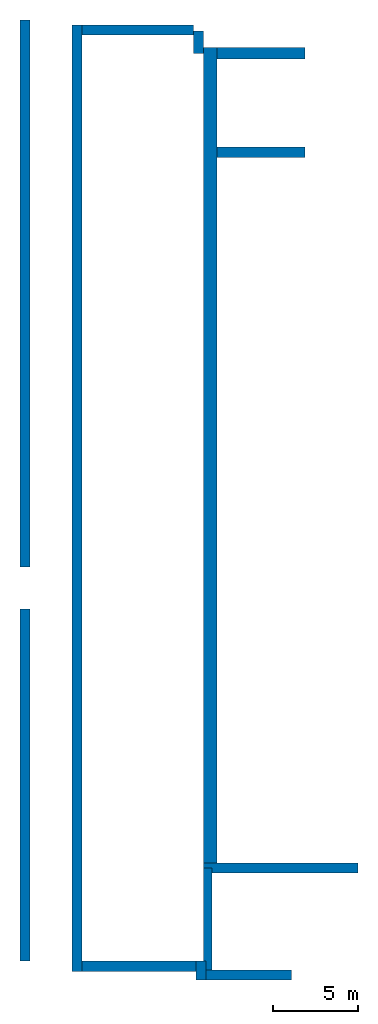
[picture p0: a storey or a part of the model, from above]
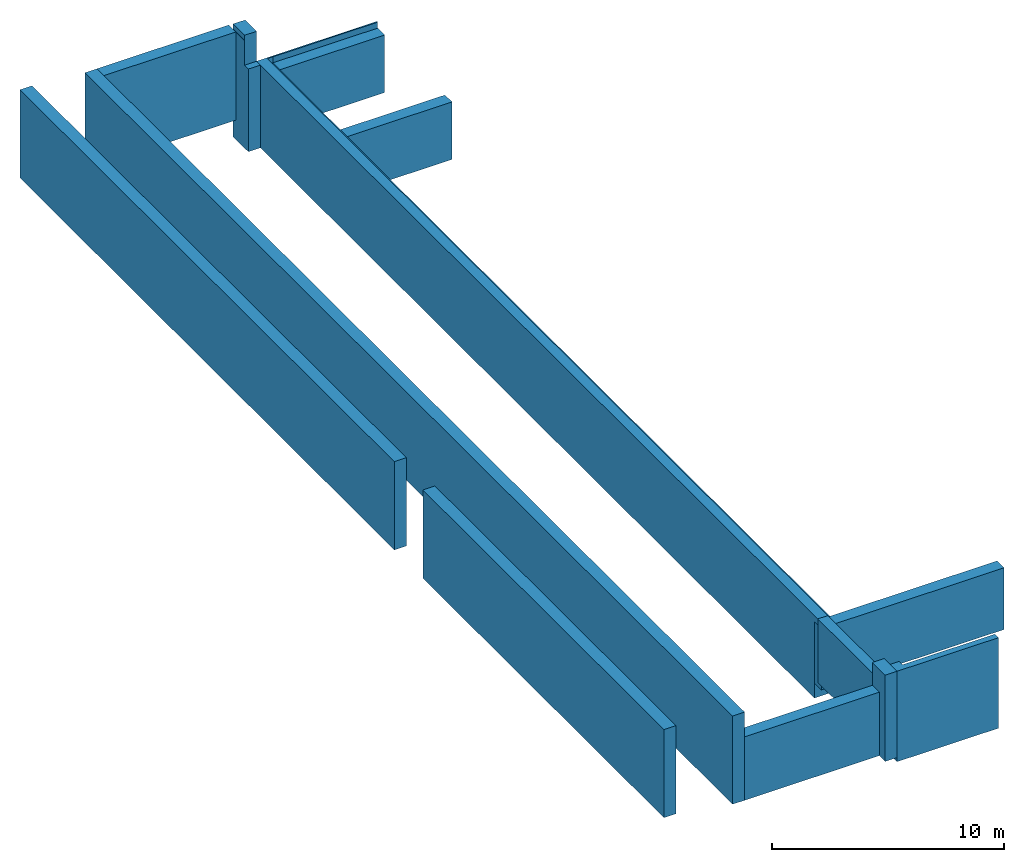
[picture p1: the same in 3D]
Properties of the parts of a building model (IFC2X3), part 1 of 7

# File
Description: ViewDefinition [CoordinationView_V2.0, QuantityTakeOffAddOnView], RevitIdentifiers [VersionGUID: 77220d87-94bb-491e-9206-e94cbbbe58ce, NumberOfSaves: 40], CoordinateReference [CoordinateBase: Project Base Point, ProjectSite: Internal]
File name: 22001 - AR_RaRa_AB_TJ_Pilv.ifc
Time: 2025-01-14T10:44:37
Written by: ODA IFC SDK 22.8
Made in: 22.1.70.9 - IFC 22.7.0.0 - Default UI

# IfcProject, 22001
LongName: Eesti Rahvusraamatukogu hoone renoveerimise projekteerimistööd; Phase: TJ

# IfcSite, Default
LongName: 78401:107:0570; RefLatitude: 59, 26, 11, 113586; RefLongitude: 24, 45, 9, 290313; RefElevation: 0 mm
Pset_SiteCommon - BuildableArea: 11110 m2; TotalArea: 19297 m2; BuildingHeightLimit: 3420 mm
AR_Kinnistu - 010_Katastritunnus: 78401:107:0570; 015_Ehitatav_pindala: 11110 m2; 020_Pindala: 19297 m2; 025_Max_kõrgus: 3420

# IfcBuilding, Eesti Rahvusraamatukogu hoone renoveerimise projekteerimistööd
LongName: Eesti Rahvusraamatukogu hoone renoveerimise projekteerimistööd
Pset_BuildingCommon - SprinklerProtection: yes; NumberOfStoreys: 10
AR_Hoone - 001_Nimetus: Eesti Rahvusraamatukogu hoone renoveerimise projekteerimistööd; 030_Hoone_aadress: Tõnismägi 2 ja Endla tn. 3, Tallinn, Harju maakond; 035_Sprinkler: yes; 040_Kõrgus: 34.18; ?: 11110; 050_Neto_pindala: 45329.3; 055_Neto_ruumala: 194973

# IfcBuildingStorey: Level:Level head 1 (12)
In: Eesti Rahvusraamatukogu hoone renoveerimise projekteerimistööd
Pset_AirSideSystemInformation - sets with these values: 2
Name | LongName | Elevation (mm) | Name = 060_Korruse_nimi | AboveGround = 070_Maapealne | 065_Korruse_number
-2. korrus | -2. korrus | -4990 | -3. Korrus_-7.50 | no | AB-3
-1. korrus | -1. korrus | -1650 | -1. korrus | no | AB-1
1. korrus | 1. korrus | 0 | 1. korrus | yes | AB1
E-korpus 2. korrus | E-korpus 2. korrus | 3100 | E-korpus 2. korrus | yes | E2
2. korrus | 2. korrus | 4950 | 2. korrus | yes | AB2
E-korpus 3. korrus | E-korpus 3. korrus | 6100 | E-korpus 3. korrus | yes | E3
3. korrus | 3. korrus | 8250 | 3. korrus | yes | AB3
4. korrus | 4. korrus | 11550 | 4. korrus | yes | AB4
5. korrus | 5. korrus | 14850 | 5. korrus | yes | AB5
6. korrus | 6. korrus | 18150 | 6. korrus | yes | AB6
7. korrus | 7. korrus | 21550 | 7. korrus | yes | AB7
8. korrus | 8. korrus | 24800 | 8. korrus | yes | AB8

# IfcBuildingStorey: Level:Level head 2, E-korpus -1. korrus
In: Eesti Rahvusraamatukogu hoone renoveerimise projekteerimistööd
LongName: E-korpus -1. korrus; Elevation: -4060 mm
Pset_AirSideSystemInformation - Name: E-korpus -1. korrus; sets with these values: 2
Pset_BuildingStoreyCommon - AboveGround: no
AR_Korrus - 070_Maapealne: no; 060_Korruse_nimi: E-korpus -1. korrus; 065_Korruse_number: E-1

# IfcSpace: Abiruum AB-3205:7871316, AB-3205
In: 3. korrus
LongName: Abiruum; InteriorOrExteriorSpace: INTERNAL; Group: SE AB 3.1M2 kõrvaltsoon
Pset_AirSideSystemInformation - Name: Abiruum
Pset_ProductRequirements - Name: Abiruum; Category: 12200 Büroo
Pset_SpaceCommon - Reference: Abiruum AB-3205; Category: 12200 Büroo
AR_Tsoon - 085_Tuletõkkesektsioon: EI120; 090_Pindala: 2.22796 m2; 080_Tähis SE: SE AB 3.1M2 kõrvaltsoon
AR_Ruum - 100_Nimi: Abiruum; 105_Number: AB-3205; 110_Tüüp: Mitteeluruumid; 115_Kategooria: RR Büroo; 120_Pindala: 2.22796 m2; 125_Turvatsoon: Kollane
BaseQuantities - NetFloorArea: 2.22796 m2; Height: 3000 mm; GrossFloorArea: 2.22796 m2; GrossVolume: 6.68388 m3

# IfcSpace: Büroo AB-1113:4274502, AB-1113
In: 1. korrus
LongName: Büroo; InteriorOrExteriorSpace: INTERNAL; Group: TT 57
Pset_AirSideSystemInformation - Name: Büroo
Pset_ProductRequirements - Name: Büroo; Category: 12200 Büroo
Pset_SpaceCommon - Reference: Büroo AB-1113; Category: 12200 Büroo
AR_Tsoon - 080_Tähis TO: TT 57; 085_Tuletõkkesektsioon: EI60; 090_Pindala: 31.6928 m2
AR_Ruum - 100_Nimi: Büroo; 105_Number: AB-1113; 110_Tüüp: Mitteeluruumid; 115_Kategooria: RR Büroo; 120_Pindala: 31.6928 m2; 125_Turvatsoon: Kollane
BaseQuantities - NetFloorArea: 31.6928 m2; Height: 3000 mm; GrossFloorArea: 31.6928 m2; GrossVolume: 95.0783 m3

# IfcSpace: Büroo AB-1114:6909133, AB-1114
In: 1. korrus
LongName: Büroo; InteriorOrExteriorSpace: INTERNAL; Group: TT 57
Pset_AirSideSystemInformation - Name: Büroo
Pset_ProductRequirements - Name: Büroo; Category: 12200 Büroo
Pset_SpaceCommon - Reference: Büroo AB-1114; Category: 12200 Büroo
AR_Tsoon - 080_Tähis TO: TT 57; 085_Tuletõkkesektsioon: EI60; 090_Pindala: 35.2581 m2
AR_Ruum - 100_Nimi: Büroo; 105_Number: AB-1114; 110_Tüüp: Mitteeluruumid; 115_Kategooria: RR Büroo; 120_Pindala: 35.2581 m2; 125_Turvatsoon: Kollane
BaseQuantities - NetFloorArea: 35.2581 m2; Height: 6300 mm; GrossFloorArea: 35.2581 m2; GrossVolume: 222.126 m3

# IfcSpace: Büroo AB-1122:6909135, AB-1122
In: 1. korrus
LongName: Büroo; InteriorOrExteriorSpace: INTERNAL; Group: TT 57
Pset_AirSideSystemInformation - Name: Büroo
Pset_ProductRequirements - Name: Büroo; Category: 12200 Büroo
Pset_SpaceCommon - Reference: Büroo AB-1122; Category: 12200 Büroo
AR_Tsoon - 080_Tähis TO: TT 57; 085_Tuletõkkesektsioon: EI60; 090_Pindala: 32.9428 m2
AR_Ruum - 100_Nimi: Büroo; 105_Number: AB-1122; 110_Tüüp: Mitteeluruumid; 115_Kategooria: RR Büroo; 120_Pindala: 32.9428 m2; 125_Turvatsoon: Kollane
BaseQuantities - NetFloorArea: 32.9428 m2; Height: 6300 mm; GrossFloorArea: 32.9428 m2; GrossVolume: 207.539 m3

# IfcSpace: Büroo AB-1124.1:13919361, AB-1124.1
In: 1. korrus
LongName: Büroo; InteriorOrExteriorSpace: INTERNAL; Group: TT 57
Pset_AirSideSystemInformation - Name: Büroo
Pset_ProductRequirements - Name: Büroo; Category: 12200 Büroo
Pset_SpaceCommon - Reference: Büroo AB-1124.1; Category: 12200 Büroo
AR_Tsoon - 080_Tähis TO: TT 57; 085_Tuletõkkesektsioon: EI60; 090_Pindala: 32.217 m2
AR_Ruum - 100_Nimi: Büroo; 105_Number: AB-1124.1; 110_Tüüp: Mitteeluruumid; 115_Kategooria: RR Büroo; 120_Pindala: 32.217 m2; 125_Turvatsoon: Kollane
BaseQuantities - NetFloorArea: 32.217 m2; Height: 9900 mm; GrossFloorArea: 32.217 m2; GrossVolume: 318.948 m3

# IfcSpace: Büroo AB-1124:1302545, AB-1124
In: 1. korrus
LongName: Büroo; InteriorOrExteriorSpace: INTERNAL; Group: TT 57
Pset_AirSideSystemInformation - Name: Büroo
Pset_ProductRequirements - Name: Büroo; Category: 12200 Büroo
Pset_SpaceCommon - Reference: Büroo AB-1124; Category: 12200 Büroo
AR_Tsoon - 080_Tähis TO: TT 57; 085_Tuletõkkesektsioon: EI60; 090_Pindala: 30.4486 m2
AR_Ruum - 100_Nimi: Büroo; 105_Number: AB-1124; 110_Tüüp: Mitteeluruumid; 115_Kategooria: RR Büroo; 120_Pindala: 30.4486 m2; 125_Turvatsoon: Kollane
BaseQuantities - NetFloorArea: 30.4486 m2; Height: 3000 mm; GrossFloorArea: 30.4486 m2; GrossVolume: 91.3458 m3

# IfcSpace: Dušš AB-01012:9327001, AB-01012
In: -1. korrus
LongName: Dušš; InteriorOrExteriorSpace: INTERNAL; Group: TT 48; SE AB -1.1M4
Pset_AirSideSystemInformation - Name: Dušš; sets with these values: 2
Pset_SpaceCommon - Reference: Dušš AB-01012
AR_Tsoon - 080_Tähis TO: TT 48; 085_Tuletõkkesektsioon: EI60; 090_Pindala: 3.37676 m2; 080_Tähis SE: SE AB -1.1M4
AR_Ruum - 100_Nimi: Dušš; 105_Number: AB-01012; 110_Tüüp: Üldkasutatavad alad; 115_Kategooria: Personaliruumid; 120_Pindala: 3.37676 m2; 125_Turvatsoon: Roheline
BaseQuantities - NetFloorArea: 3.37676 m2; Height: 9900 mm; GrossFloorArea: 3.37676 m2; GrossVolume: 33.43 m3

# IfcSpace: Eesruum / köök AB-2104:1990514, AB-2104
In: 2. korrus
LongName: Eesruum / köök; InteriorOrExteriorSpace: INTERNAL; Group: TT 23
Pset_AirSideSystemInformation - Name: Eesruum / köök
Pset_ProductRequirements - Name: Eesruum / köök; Category: 12200 Büroo
Pset_SpaceCommon - Reference: Eesruum / köök AB-2104; Category: 12200 Büroo
AR_Tsoon - 080_Tähis TO: TT 23; 085_Tuletõkkesektsioon: EI60; 090_Pindala: 13.9472 m2
AR_Ruum - 100_Nimi: Eesruum / köök; 105_Number: AB-2104; 110_Tüüp: Üldkasutatavad alad; 115_Kategooria: RR Büroo; 120_Pindala: 13.9472 m2; 125_Turvatsoon: Kollane
BaseQuantities - NetFloorArea: 13.9472 m2; Height: 3901.76 mm; GrossPerimeter: 16099.2 mm; GrossFloorArea: 13.9472 m2; GrossVolume: 54.4189 m3

# IfcSpace: Eesruum E-2002:2863406, E-2002
In: E-korpus 2. korrus
LongName: Eesruum; InteriorOrExteriorSpace: INTERNAL; Group: TT 26
Pset_AirSideSystemInformation - Name: Eesruum; sets with these values: 2
Pset_SpaceCommon - Reference: Eesruum E-2002
AR_Tsoon - 080_Tähis TO: TT 26; 085_Tuletõkkesektsioon: EI60; 090_Pindala: 4.54861 m2
AR_Ruum - 100_Nimi: Eesruum; 105_Number: E-2002; 110_Tüüp: Üldkasutatavad alad; 115_Kategooria: Üldala; 120_Pindala: 4.54861 m2; 125_Turvatsoon: Kollane
BaseQuantities - NetFloorArea: 4.54861 m2; Height: 3121.53 mm; GrossPerimeter: 9055.15 mm; GrossFloorArea: 4.54861 m2; GrossVolume: 14.1986 m3

# IfcSpace: Fuajee AB-1036:6178383, AB-1036
In: 1. korrus
LongName: Fuajee; InteriorOrExteriorSpace: INTERNAL; Group: TT 01; SE AB 1.1M4
Pset_AirSideSystemInformation - Name: Fuajee; sets with these values: 2
Pset_SpaceCommon - Reference: Fuajee AB-1036
AR_Tsoon - 080_Tähis TO: TT 01; 085_Tuletõkkesektsioon: EI60; 090_Pindala: 132.862 m2; 080_Tähis SE: SE AB 1.1M4
AR_Ruum - 100_Nimi: Fuajee; 105_Number: AB-1036; 110_Tüüp: Üldkasutatavad alad; 115_Kategooria: Üldala; 120_Pindala: 132.862 m2; 125_Turvatsoon: Roheline
BaseQuantities - NetFloorArea: 132.862 m2; Height: 2974.99 mm; GrossPerimeter: 61078.5 mm; GrossFloorArea: 132.862 m2; GrossVolume: 395.264 m3

# IfcSpace: Garderoob AB-3235:6668970, AB-3235
In: 3. korrus
LongName: Garderoob; InteriorOrExteriorSpace: INTERNAL; Group: TT 27; SE AB 3.1M2
Pset_AirSideSystemInformation - Name: Garderoob
Pset_ProductRequirements - Name: Garderoob; Category: 12200 Büroo
Pset_SpaceCommon - Reference: Garderoob AB-3235; Category: 12200 Büroo
AR_Tsoon - 080_Tähis TO: TT 27; 085_Tuletõkkesektsioon: EI90; 090_Pindala: 14.8637 m2; 080_Tähis SE: SE AB 3.1M2
AR_Ruum - 100_Nimi: Garderoob; 105_Number: AB-3235; 110_Tüüp: Mitteeluruumid; 115_Kategooria: Üld õppeala; 120_Pindala: 14.8637 m2; 125_Turvatsoon: Kollane
BaseQuantities - NetFloorArea: 14.8637 m2; Height: 3000 mm; GrossPerimeter: 17231 mm; GrossFloorArea: 14.8637 m2; GrossVolume: 44.5911 m3

# IfcSpace: Hoidlatöötajad AB-2123:1362904, AB-2123
In: 2. korrus
LongName: Hoidlatöötajad; InteriorOrExteriorSpace: INTERNAL; Group: TT 21
Pset_AirSideSystemInformation - Name: Hoidlatöötajad
Pset_ProductRequirements - Name: Hoidlatöötajad; Category: 12200 Büroo
Pset_SpaceCommon - Reference: Hoidlatöötajad AB-2123; Category: 12200 Büroo
AR_Tsoon - 080_Tähis TO: TT 21; 085_Tuletõkkesektsioon: EI60; 090_Pindala: 32.9681 m2
AR_Ruum - 100_Nimi: Hoidlatöötajad; 105_Number: AB-2123; 110_Tüüp: Mitteeluruumid; 115_Kategooria: RR Büroo; 120_Pindala: 32.9681 m2; 125_Turvatsoon: Kollane
BaseQuantities - NetFloorArea: 32.9681 m2; Height: 3000 mm; GrossPerimeter: 23109 mm; GrossFloorArea: 32.9681 m2; GrossVolume: 98.9042 m3

# IfcSpace: Hoiuruum, ümbrised AB-01109:4434795, AB-01109
In: -1. korrus
LongName: Hoiuruum, ümbrised; InteriorOrExteriorSpace: INTERNAL; Group: SE AB -1.1M4 kõrvaltsoon
Pset_AirSideSystemInformation - Name: Hoiuruum, ümbrised
Pset_ProductRequirements - Name: Hoiuruum, ümbrised; Category: 12624 Arhiiv
Pset_SpaceCommon - Reference: Hoiuruum, ümbrised AB-01109; Category: 12624 Arhiiv
AR_Tsoon - 085_Tuletõkkesektsioon: EI90; 090_Pindala: 18.2886 m2; 080_Tähis SE: SE AB -1.1M4 kõrvaltsoon
AR_Ruum - 100_Nimi: Hoiuruum, ümbrised; 105_Number: AB-01109; 110_Tüüp: Mitteeluruumid; 115_Kategooria: RR Büroo; 120_Pindala: 18.2886 m2; 125_Turvatsoon: Punane
BaseQuantities - NetFloorArea: 18.2886 m2; Height: 2985 mm; GrossFloorArea: 18.2886 m2; GrossVolume: 54.5913 m3

# IfcSpace: ITAK AB-2138:1362880, AB-2138
In: 2. korrus
LongName: ITAK; InteriorOrExteriorSpace: INTERNAL; Group: TT 21
Pset_AirSideSystemInformation - Name: ITAK
Pset_ProductRequirements - Name: ITAK; Category: 12200 Büroo
Pset_SpaceCommon - Reference: ITAK AB-2138; Category: 12200 Büroo
AR_Tsoon - 080_Tähis TO: TT 21; 085_Tuletõkkesektsioon: EI60; 090_Pindala: 51.3226 m2
AR_Ruum - 100_Nimi: ITAK; 105_Number: AB-2138; 110_Tüüp: Mitteeluruumid; 115_Kategooria: RR Büroo; 120_Pindala: 51.3226 m2; 125_Turvatsoon: Kollane
BaseQuantities - NetFloorArea: 51.3226 m2; Height: 3000 mm; GrossPerimeter: 31345.1 mm; GrossFloorArea: 51.3226 m2; GrossVolume: 153.968 m3

# IfcSpace: ITAK Juhataja AB-2137:7048196, AB-2137
In: 2. korrus
LongName: ITAK Juhataja; InteriorOrExteriorSpace: INTERNAL; Group: TT 21
Pset_AirSideSystemInformation - Name: ITAK Juhataja
Pset_ProductRequirements - Name: ITAK Juhataja; Category: 12200 Büroo
Pset_SpaceCommon - Reference: ITAK Juhataja AB-2137; Category: 12200 Büroo
AR_Tsoon - 080_Tähis TO: TT 21; 085_Tuletõkkesektsioon: EI60; 090_Pindala: 17.2797 m2
AR_Ruum - 100_Nimi: ITAK Juhataja; 105_Number: AB-2137; 110_Tüüp: Mitteeluruumid; 115_Kategooria: RR Büroo; 120_Pindala: 17.2797 m2; 125_Turvatsoon: Punane
BaseQuantities - NetFloorArea: 17.2797 m2; Height: 3000 mm; GrossPerimeter: 17564.5 mm; GrossFloorArea: 17.2797 m2; GrossVolume: 51.8392 m3

# IfcSpace: ITAK puhkeruum AB-2139:1362876, AB-2139
In: 2. korrus
LongName: ITAK puhkeruum; InteriorOrExteriorSpace: INTERNAL; Group: TT 21
Pset_AirSideSystemInformation - Name: ITAK puhkeruum
Pset_ProductRequirements - Name: ITAK puhkeruum; Category: 12200 Büroo
Pset_SpaceCommon - Reference: ITAK puhkeruum AB-2139; Category: 12200 Büroo
AR_Tsoon - 080_Tähis TO: TT 21; 085_Tuletõkkesektsioon: EI60; 090_Pindala: 32.2565 m2
AR_Ruum - 100_Nimi: ITAK puhkeruum; 105_Number: AB-2139; 110_Tüüp: Mitteeluruumid; 115_Kategooria: RR Büroo; 120_Pindala: 32.2565 m2; 125_Turvatsoon: Kollane
BaseQuantities - NetFloorArea: 32.2565 m2; Height: 3000 mm; GrossPerimeter: 23408 mm; GrossFloorArea: 32.2565 m2; GrossVolume: 96.7696 m3

# IfcSpace: Juhtiv spets. F-1116:2388867, F-1116
In: 1. korrus
LongName: Juhtiv spets.; InteriorOrExteriorSpace: INTERNAL; Group: TT 05
Pset_AirSideSystemInformation - Name: Juhtiv spets.
Pset_ProductRequirements - Name: Juhtiv spets.; Category: 12200 Büroo
Pset_SpaceCommon - Reference: Juhtiv spets. F-1116; Category: 12200 Büroo
AR_Tsoon - 080_Tähis TO: TT 05; 085_Tuletõkkesektsioon: EI60; 090_Pindala: 17.6284 m2
AR_Ruum - 100_Nimi: Juhtiv spets.; 105_Number: F-1116; 110_Tüüp: Mitteeluruumid; 115_Kategooria: RR Büroo; 120_Pindala: 17.6284 m2; 125_Turvatsoon: Punane
BaseQuantities - NetFloorArea: 17.6284 m2; Height: 4000 mm; GrossFloorArea: 17.6284 m2; GrossVolume: 70.5136 m3

# IfcSpace: KAO ladu AB-2136:1362888, AB-2136
In: 2. korrus
LongName: KAO ladu; InteriorOrExteriorSpace: INTERNAL
Pset_AirSideSystemInformation - Name: KAO ladu
Pset_ProductRequirements - Name: KAO ladu; Category: 12200 Büroo
Pset_SpaceCommon - Reference: KAO ladu AB-2136; Category: 12200 Büroo
AR_Tsoon - 085_Tuletõkkesektsioon: EI120; 090_Pindala: 11.8014 m2
AR_Ruum - 100_Nimi: KAO ladu; 105_Number: AB-2136; 110_Tüüp: Mitteeluruumid; 115_Kategooria: RR Büroo; 120_Pindala: 11.8014 m2; 125_Turvatsoon: Kollane
BaseQuantities - NetFloorArea: 11.8014 m2; Height: 3000 mm; GrossPerimeter: 15571 mm; GrossFloorArea: 11.8014 m2; GrossVolume: 35.4042 m3

# IfcSpace: Kabinet AB-2121:1362984, AB-2121
In: 2. korrus
LongName: Kabinet; InteriorOrExteriorSpace: INTERNAL; Group: TT 21
Pset_AirSideSystemInformation - Name: Kabinet
Pset_ProductRequirements - Name: Kabinet; Category: 12200 Büroo
Pset_SpaceCommon - Reference: Kabinet AB-2121; Category: 12200 Büroo
AR_Tsoon - 080_Tähis TO: TT 21; 085_Tuletõkkesektsioon: EI60; 090_Pindala: 31.8685 m2
AR_Ruum - 100_Nimi: Kabinet; 105_Number: AB-2121; 110_Tüüp: Mitteeluruumid; 115_Kategooria: RR Büroo; 120_Pindala: 31.8685 m2; 125_Turvatsoon: Kollane
BaseQuantities - NetFloorArea: 31.8685 m2; Height: 3000 mm; GrossPerimeter: 23062 mm; GrossFloorArea: 31.8685 m2; GrossVolume: 95.6054 m3

# IfcSpace: Kanal AB-02302:5475221, AB-02302
In: E-korpus -1. korrus
LongName: Kanal; InteriorOrExteriorSpace: INTERNAL
Pset_AirSideSystemInformation - Name: Kanal; sets with these values: 2
Pset_SpaceCommon - Reference: Kanal AB-02302
AR_Tsoon - 085_Tuletõkkesektsioon: EI60; 090_Pindala: 32.5664 m2
AR_Ruum - 100_Nimi: Kanal; 105_Number: AB-02302; 110_Tüüp: Tehnilised ruumid; 115_Kategooria: Tehnilised ruumid; 120_Pindala: 32.5664 m2; 125_Turvatsoon: Punane
BaseQuantities - NetFloorArea: 32.5664 m2; Height: 2062.47 mm; GrossFloorArea: 32.5664 m2; GrossVolume: 67.1671 m3

# IfcSpace: Kanal AB-02303:5281081, AB-02303
In: E-korpus -1. korrus
LongName: Kanal; InteriorOrExteriorSpace: INTERNAL; Group: SE AB -2.1M2 AT
Pset_AirSideSystemInformation - Name: Kanal; sets with these values: 2
Pset_SpaceCommon - Reference: Kanal AB-02303
AR_Tsoon - 085_Tuletõkkesektsioon: EI60; 090_Pindala: 198.182 m2; 080_Tähis SE: SE AB -2.1M2 AT
AR_Ruum - 100_Nimi: Kanal; 105_Number: AB-02303; 110_Tüüp: Tehnilised ruumid; 115_Kategooria: Tehnilised ruumid; 120_Pindala: 198.182 m2; 125_Turvatsoon: Punane
BaseQuantities - NetFloorArea: 198.182 m2; Height: 1910 mm; GrossFloorArea: 198.182 m2; GrossVolume: 378.528 m3

# IfcSpace: Karbistamise tööruum F-1108:2388882, F-1108
In: 1. korrus
LongName: Karbistamise tööruum; InteriorOrExteriorSpace: INTERNAL; Group: TT 05
Pset_AirSideSystemInformation - Name: Karbistamise tööruum
Pset_ProductRequirements - Name: Karbistamise tööruum; Category: 12200 Büroo
Pset_SpaceCommon - Reference: Karbistamise tööruum F-1108; Category: 12200 Büroo
AR_Tsoon - 080_Tähis TO: TT 05; 085_Tuletõkkesektsioon: EI60; 090_Pindala: 39.6037 m2
AR_Ruum - 100_Nimi: Karbistamise tööruum; 105_Number: F-1108; 110_Tüüp: Mitteeluruumid; 115_Kategooria: RR Büroo; 120_Pindala: 39.6037 m2; 125_Turvatsoon: Punane
BaseQuantities - NetFloorArea: 39.6037 m2; Height: 2980 mm; GrossPerimeter: 25598.2 mm; GrossFloorArea: 39.6037 m2; GrossVolume: 118.019 m3

# IfcSpace: Keemialabor F-1102:2388885, F-1102
In: 1. korrus
LongName: Keemialabor; InteriorOrExteriorSpace: INTERNAL; Group: TT 05; SE F 1.1M2
Pset_AirSideSystemInformation - Name: Keemialabor
Pset_ProductRequirements - Name: Keemialabor; Category: 12200 Büroo
Pset_SpaceCommon - Reference: Keemialabor F-1102; Category: 12200 Büroo
AR_Tsoon - 080_Tähis TO: TT 05; 085_Tuletõkkesektsioon: EI60; 090_Pindala: 25.182 m2; 080_Tähis SE: SE F 1.1M2
AR_Ruum - 100_Nimi: Keemialabor; 105_Number: F-1102; 110_Tüüp: Mitteeluruumid; 115_Kategooria: RR Büroo; 120_Pindala: 25.182 m2; 125_Turvatsoon: Punane
BaseQuantities - NetFloorArea: 25.182 m2; Height: 2980 mm; GrossPerimeter: 27881 mm; GrossFloorArea: 25.182 m2; GrossVolume: 75.0424 m3

# IfcSpace: Konservaatorite ja köitjate tööruum F-1113:2388815, F-1113
In: 1. korrus
LongName: Konservaatorite ja köitjate tööruum; InteriorOrExteriorSpace: INTERNAL; Group: TT 05
Pset_AirSideSystemInformation - Name: Konservaatorite ja köitjate tööruum
Pset_ProductRequirements - Name: Konservaatorite ja köitjate tööruum; Category: 12200 Büroo
Pset_SpaceCommon - Reference: Konservaatorite ja köitjate tööruum F-1113; Category: 12200 Büroo
AR_Tsoon - 080_Tähis TO: TT 05; 085_Tuletõkkesektsioon: EI60; 090_Pindala: 154.796 m2
AR_Ruum - 100_Nimi: Konservaatorite ja köitjate tööruum; 105_Number: F-1113; 110_Tüüp: Mitteeluruumid; 115_Kategooria: RR Büroo; 120_Pindala: 154.796 m2; 125_Turvatsoon: Punane
BaseQuantities - NetFloorArea: 154.796 m2; Height: 2980 mm; GrossPerimeter: 54601.2 mm; GrossFloorArea: 154.796 m2; GrossVolume: 461.293 m3

# IfcSpace: Konverentsikeskuse teenindusala E-1601:2608946, E-1601
In: 1. korrus
LongName: Konverentsikeskuse teenindusala; InteriorOrExteriorSpace: INTERNAL; Group: TT 01; SE AB 1.1M4
Pset_AirSideSystemInformation - Name: Konverentsikeskuse teenindusala
Pset_ProductRequirements - Name: Konverentsikeskuse teenindusala; Category: 12623 Raamatukogu
Pset_SpaceCommon - Reference: Konverentsikeskuse teenindusala E-1601; Category: 12623 Raamatukogu
AR_Tsoon - 080_Tähis TO: TT 01; 085_Tuletõkkesektsioon: EI60; 090_Pindala: 76.9714 m2; 080_Tähis SE: SE AB 1.1M4
AR_Ruum - 100_Nimi: Konverentsikeskuse teenindusala; 105_Number: E-1601; 110_Tüüp: Mitteeluruumid; 115_Kategooria: Konverentsikeskus; 120_Pindala: 76.9714 m2; 125_Turvatsoon: Kollane
BaseQuantities - NetFloorArea: 76.9714 m2; Height: 2979.98 mm; GrossPerimeter: 39418.4 mm; GrossFloorArea: 76.9714 m2; GrossVolume: 229.373 m3

# IfcSpace: Koridor AB-1001:2608963, AB-1001
In: 1. korrus
LongName: Koridor; InteriorOrExteriorSpace: INTERNAL; Group: SE TR3 L3
Pset_AirSideSystemInformation - Name: Koridor; sets with these values: 2
Pset_SpaceCommon - Reference: Koridor AB-1001
AR_Tsoon - 085_Tuletõkkesektsioon: EI60; 090_Pindala: 29.358 m2; 080_Tähis SE: SE TR3 L3
AR_Ruum - 100_Nimi: Koridor; 105_Number: AB-1001; 110_Tüüp: Üldkasutatavad alad; 115_Kategooria: Üldala; 120_Pindala: 29.358 m2; 125_Turvatsoon: Roheline
BaseQuantities - NetFloorArea: 29.358 m2; Height: 3000 mm; GrossPerimeter: 31100 mm; GrossFloorArea: 29.358 m2; GrossVolume: 88.074 m3

# IfcSpace: Koridor F-1009:2857749, F-1009
In: 1. korrus
LongName: Koridor; InteriorOrExteriorSpace: INTERNAL; Group: TT 05; SE F 1.1M2
Pset_AirSideSystemInformation - Name: Koridor; sets with these values: 2
Pset_SpaceCommon - Reference: Koridor F-1009
AR_Tsoon - 080_Tähis TO: TT 05; 085_Tuletõkkesektsioon: EI60; 090_Pindala: 79.2115 m2; 080_Tähis SE: SE F 1.1M2
AR_Ruum - 100_Nimi: Koridor; 105_Number: F-1009; 110_Tüüp: Üldkasutatavad alad; 115_Kategooria: Üldala; 120_Pindala: 79.2115 m2; 125_Turvatsoon: Kollane
BaseQuantities - NetFloorArea: 79.2115 m2; Height: 2980 mm; GrossFloorArea: 79.2115 m2; GrossVolume: 236.05 m3

# IfcSpace: Koridor F-1010:2857747, F-1010
In: 1. korrus
LongName: Koridor; InteriorOrExteriorSpace: INTERNAL; Group: TT 05
Pset_AirSideSystemInformation - Name: Koridor; sets with these values: 2
Pset_SpaceCommon - Reference: Koridor F-1010
AR_Tsoon - 080_Tähis TO: TT 05; 085_Tuletõkkesektsioon: EI60; 090_Pindala: 14.6776 m2
AR_Ruum - 100_Nimi: Koridor; 105_Number: F-1010; 110_Tüüp: Üldkasutatavad alad; 115_Kategooria: Üldala; 120_Pindala: 14.6776 m2; 125_Turvatsoon: Kollane
BaseQuantities - NetFloorArea: 14.6776 m2; Height: 2980 mm; GrossPerimeter: 17026.6 mm; GrossFloorArea: 14.6776 m2; GrossVolume: 43.7392 m3

# IfcSpace: Koristus personali puhkeruum AB-01008:1468837, AB-01008
In: -1. korrus
LongName: Koristus personali puhkeruum; InteriorOrExteriorSpace: INTERNAL; Group: TT 48; SE AB -1.1M4
Pset_AirSideSystemInformation - Name: Koristus personali puhkeruum; sets with these values: 2
Pset_SpaceCommon - Reference: Koristus personali puhkeruum AB-01008
AR_Tsoon - 080_Tähis TO: TT 48; 085_Tuletõkkesektsioon: EI60; 090_Pindala: 56.1981 m2; 080_Tähis SE: SE AB -1.1M4
AR_Ruum - 100_Nimi: Koristus personali puhkeruum; 105_Number: AB-01008; 110_Tüüp: Üldkasutatavad alad; 115_Kategooria: Personaliruumid; 120_Pindala: 56.1981 m2; 125_Turvatsoon: Kollane
BaseQuantities - NetFloorArea: 56.1981 m2; Height: 2985 mm; GrossFloorArea: 56.1981 m2; GrossVolume: 167.751 m3

# IfcSpace: Koristv. E-1001:7772610, E-1001
In: 1. korrus
LongName: Koristv.; InteriorOrExteriorSpace: INTERNAL; Group: TT 01; SE AB 1.1M4
Pset_AirSideSystemInformation - Name: Koristv.; sets with these values: 2
Pset_SpaceCommon - Reference: Koristv. E-1001
AR_Tsoon - 080_Tähis TO: TT 01; 085_Tuletõkkesektsioon: EI60; 090_Pindala: 5.12927 m2; 080_Tähis SE: SE AB 1.1M4
AR_Ruum - 100_Nimi: Koristv.; 105_Number: E-1001; 110_Tüüp: Üldkasutatavad alad; 115_Kategooria: Konverentsikeskus; 120_Pindala: 5.12927 m2; 125_Turvatsoon: Kollane
BaseQuantities - NetFloorArea: 5.12927 m2; Height: 9900 mm; GrossPerimeter: 9864.71 mm; GrossFloorArea: 5.12927 m2; GrossVolume: 50.7798 m3

# IfcSpace: Ladu (reserv) AB-01303:1465441, AB-01303
In: -1. korrus
LongName: Ladu (reserv); InteriorOrExteriorSpace: INTERNAL; Group: SE AB -1.1M4 kõrvaltsoon
Pset_AirSideSystemInformation - Name: Ladu (reserv); sets with these values: 2
Pset_SpaceCommon - Reference: Ladu (reserv) AB-01303
AR_Tsoon - 085_Tuletõkkesektsioon: EI90; 090_Pindala: 28.1808 m2; 080_Tähis SE: SE AB -1.1M4 kõrvaltsoon
AR_Ruum - 100_Nimi: Ladu (reserv); 105_Number: AB-01303; 110_Tüüp: Tehnilised ruumid; 115_Kategooria: Tehnilised ruumid; 120_Pindala: 28.1808 m2; 125_Turvatsoon: Punane
BaseQuantities - NetFloorArea: 28.1808 m2; Height: 2985 mm; GrossFloorArea: 28.1808 m2; GrossVolume: 84.1195 m3

# IfcSpace: Laste ala AB-3207:1386924, AB-3207
In: 3. korrus
LongName: Laste ala; InteriorOrExteriorSpace: INTERNAL; Group: TT 27; SE AB 3.1M2
Pset_AirSideSystemInformation - Name: Laste ala
Pset_ProductRequirements - Name: Laste ala; Category: 12623 Raamatukogu
Pset_SpaceCommon - Reference: Laste ala AB-3207; Category: 12623 Raamatukogu
AR_Tsoon - 080_Tähis TO: TT 27; 085_Tuletõkkesektsioon: EI90; 090_Pindala: 138.926 m2; 080_Tähis SE: SE AB 3.1M2
AR_Ruum - 100_Nimi: Laste ala; 105_Number: AB-3207; 110_Tüüp: Mitteeluruumid; 115_Kategooria: Üld õppeala; 120_Pindala: 138.926 m2; 125_Turvatsoon: Roheline
BaseQuantities - NetFloorArea: 138.926 m2; Height: 3000 mm; GrossPerimeter: 57708 mm; GrossFloorArea: 138.926 m2; GrossVolume: 416.777 m3

# IfcSpace: Logistikakeskus AB-2122:1362898, AB-2122
In: 2. korrus
LongName: Logistikakeskus; InteriorOrExteriorSpace: INTERNAL; Group: TT 21
Pset_AirSideSystemInformation - Name: Logistikakeskus
Pset_ProductRequirements - Name: Logistikakeskus; Category: 12200 Büroo
Pset_SpaceCommon - Reference: Logistikakeskus AB-2122; Category: 12200 Büroo
AR_Tsoon - 080_Tähis TO: TT 21; 085_Tuletõkkesektsioon: EI60; 090_Pindala: 34.1907 m2
AR_Ruum - 100_Nimi: Logistikakeskus; 105_Number: AB-2122; 110_Tüüp: Mitteeluruumid; 115_Kategooria: RR Büroo; 120_Pindala: 34.1907 m2; 125_Turvatsoon: Kollane
BaseQuantities - NetFloorArea: 34.1907 m2; Height: 3000 mm; GrossPerimeter: 24039 mm; GrossFloorArea: 34.1907 m2; GrossVolume: 102.572 m3

# IfcSpace: Lugemissaal vasak AB-3232:6669264, AB-3232
In: 3. korrus
LongName: Lugemissaal vasak; InteriorOrExteriorSpace: INTERNAL; Group: TT 27; SE AB 3.1M2
Pset_AirSideSystemInformation - Name: Lugemissaal vasak
Pset_ProductRequirements - Name: Lugemissaal vasak; Category: 12623 Raamatukogu
Pset_SpaceCommon - Reference: Lugemissaal vasak AB-3232; Category: 12623 Raamatukogu
AR_Tsoon - 080_Tähis TO: TT 27; 085_Tuletõkkesektsioon: EI90; 090_Pindala: 599.833 m2; 080_Tähis SE: SE AB 3.1M2
AR_Ruum - 100_Nimi: Lugemissaal vasak; 105_Number: AB-3232; 110_Tüüp: Mitteeluruumid; 115_Kategooria: Üld õppeala; 120_Pindala: 599.833 m2; 125_Turvatsoon: Roheline
BaseQuantities - NetFloorArea: 599.833 m2; Height: 3000 mm; GrossFloorArea: 599.833 m2; GrossVolume: 1799.5 m3

# IfcSpace: Nurgasalong E-2601:2860596, E-2601
In: E-korpus 2. korrus
LongName: Nurgasalong; InteriorOrExteriorSpace: INTERNAL; Group: TT 26
Pset_AirSideSystemInformation - Name: Nurgasalong
Pset_ProductRequirements - Name: Nurgasalong; Category: 12623 Raamatukogu
Pset_SpaceCommon - Reference: Nurgasalong E-2601; Category: 12623 Raamatukogu
AR_Tsoon - 080_Tähis TO: TT 26; 085_Tuletõkkesektsioon: EI60; 090_Pindala: 55.0577 m2
AR_Ruum - 100_Nimi: Nurgasalong; 105_Number: E-2601; 110_Tüüp: Mitteeluruumid; 115_Kategooria: Konverentsikeskus; 120_Pindala: 55.0577 m2; 125_Turvatsoon: Kollane
BaseQuantities - NetFloorArea: 55.0577 m2; Height: 5626.4 mm; GrossFloorArea: 55.0577 m2; GrossVolume: 309.777 m3

# IfcSpace: Nõup/puhker AB-1112:6909131, AB-1112
In: 1. korrus
LongName: Nõup/puhker; InteriorOrExteriorSpace: INTERNAL; Group: TT 57
Pset_AirSideSystemInformation - Name: Nõup/puhker
Pset_ProductRequirements - Name: Nõup/puhker; Category: 12200 Büroo
Pset_SpaceCommon - Reference: Nõup/puhker AB-1112; Category: 12200 Büroo
AR_Tsoon - 080_Tähis TO: TT 57; 085_Tuletõkkesektsioon: EI60; 090_Pindala: 17.9611 m2
AR_Ruum - 100_Nimi: Nõup/puhker; 105_Number: AB-1112; 110_Tüüp: Mitteeluruumid; 115_Kategooria: RR Büroo; 120_Pindala: 17.9611 m2; 125_Turvatsoon: Kollane
BaseQuantities - NetFloorArea: 17.9611 m2; Height: 6300 mm; GrossFloorArea: 17.9611 m2; GrossVolume: 113.155 m3

# IfcSpace: Osak.juh. + koosolekur. F-1101:2388837, F-1101
In: 1. korrus
LongName: Osak.juh. + koosolekur.; InteriorOrExteriorSpace: INTERNAL; Group: TT 05; SE F 1.1M2
Pset_AirSideSystemInformation - Name: Osak.juh. + koosolekur.
Pset_ProductRequirements - Name: Osak.juh. + koosolekur.; Category: 12200 Büroo
Pset_SpaceCommon - Reference: Osak.juh. + koosolekur. F-1101; Category: 12200 Büroo
AR_Tsoon - 080_Tähis TO: TT 05; 085_Tuletõkkesektsioon: EI60; 090_Pindala: 19.3515 m2; 080_Tähis SE: SE F 1.1M2
AR_Ruum - 100_Nimi: Osak.juh. + koosolekur.; 105_Number: F-1101; 110_Tüüp: Mitteeluruumid; 115_Kategooria: RR Büroo; 120_Pindala: 19.3515 m2; 125_Turvatsoon: Punane
BaseQuantities - NetFloorArea: 19.3515 m2; Height: 3180 mm; GrossFloorArea: 19.3515 m2; GrossVolume: 61.5379 m3

# IfcSpace: Osakonna juhataja AB-1111:1302555, AB-1111
In: 1. korrus
LongName: Osakonna juhataja; InteriorOrExteriorSpace: INTERNAL; Group: TT 57
Pset_AirSideSystemInformation - Name: Osakonna juhataja
Pset_ProductRequirements - Name: Osakonna juhataja; Category: 12200 Büroo
Pset_SpaceCommon - Reference: Osakonna juhataja AB-1111; Category: 12200 Büroo
AR_Tsoon - 080_Tähis TO: TT 57; 085_Tuletõkkesektsioon: EI60; 090_Pindala: 15.1464 m2
AR_Ruum - 100_Nimi: Osakonna juhataja; 105_Number: AB-1111; 110_Tüüp: Mitteeluruumid; 115_Kategooria: RR Büroo; 120_Pindala: 15.1464 m2; 125_Turvatsoon: Kollane
BaseQuantities - NetFloorArea: 15.1464 m2; Height: 3000 mm; GrossFloorArea: 15.1464 m2; GrossVolume: 45.4391 m3

# IfcSpace: Paberimärgtöötlus F-1114:2395984, F-1114
In: 1. korrus
LongName: Paberimärgtöötlus; InteriorOrExteriorSpace: INTERNAL; Group: TT 05
Pset_AirSideSystemInformation - Name: Paberimärgtöötlus
Pset_ProductRequirements - Name: Paberimärgtöötlus; Category: 12200 Büroo
Pset_SpaceCommon - Reference: Paberimärgtöötlus F-1114; Category: 12200 Büroo
AR_Tsoon - 080_Tähis TO: TT 05; 085_Tuletõkkesektsioon: EI60; 090_Pindala: 134.855 m2
AR_Ruum - 100_Nimi: Paberimärgtöötlus; 105_Number: F-1114; 110_Tüüp: Mitteeluruumid; 115_Kategooria: RR Büroo; 120_Pindala: 134.855 m2; 125_Turvatsoon: Punane
BaseQuantities - NetFloorArea: 134.855 m2; Height: 2980 mm; GrossPerimeter: 58953 mm; GrossFloorArea: 134.855 m2; GrossVolume: 401.868 m3

# IfcSpace: Panipaik AB-1122.1:2608971, AB-1122.1
In: 1. korrus
LongName: Panipaik; InteriorOrExteriorSpace: INTERNAL; Group: TT 57
Pset_AirSideSystemInformation - Name: Panipaik
Pset_ProductRequirements - Name: Panipaik; Category: 12200 Büroo
Pset_SpaceCommon - Reference: Panipaik AB-1122.1; Category: 12200 Büroo
AR_Tsoon - 080_Tähis TO: TT 57; 085_Tuletõkkesektsioon: EI60; 090_Pindala: 3.31215 m2
AR_Ruum - 100_Nimi: Panipaik; 105_Number: AB-1122.1; 110_Tüüp: Mitteeluruumid; 115_Kategooria: RR Büroo; 120_Pindala: 3.31215 m2; 125_Turvatsoon: Roheline
BaseQuantities - NetFloorArea: 3.31215 m2; Height: 3000 mm; GrossFloorArea: 3.31215 m2; GrossVolume: 9.93645 m3

# IfcSpace: Panipaik AB-3234:7871310, AB-3234
In: 3. korrus
LongName: Panipaik; InteriorOrExteriorSpace: INTERNAL; Group: TT 27; SE AB 3.1M2
Pset_AirSideSystemInformation - Name: Panipaik
Pset_ProductRequirements - Name: Panipaik; Category: 12623 Raamatukogu
Pset_SpaceCommon - Reference: Panipaik AB-3234; Category: 12623 Raamatukogu
AR_Tsoon - 080_Tähis TO: TT 27; 085_Tuletõkkesektsioon: EI90; 090_Pindala: 2.32763 m2; 080_Tähis SE: SE AB 3.1M2
AR_Ruum - 100_Nimi: Panipaik; 105_Number: AB-3234; 110_Tüüp: Mitteeluruumid; 115_Kategooria: RR Büroo; 120_Pindala: 2.32763 m2; 125_Turvatsoon: Kollane
BaseQuantities - NetFloorArea: 2.32763 m2; Height: 3000 mm; GrossFloorArea: 2.32763 m2; GrossVolume: 6.9829 m3

# IfcSpace: Panipaik AB-4224:2864778, AB-4224
In: 4. korrus
LongName: Panipaik; InteriorOrExteriorSpace: INTERNAL; Group: TT 29; SE AB 4.1M4
Pset_AirSideSystemInformation - Name: Panipaik
Pset_ProductRequirements - Name: Panipaik; Category: 12200 Büroo
Pset_SpaceCommon - Reference: Panipaik AB-4224; Category: 12200 Büroo
AR_Tsoon - 080_Tähis TO: TT 29; 085_Tuletõkkesektsioon: EI90; 090_Pindala: 2.63711 m2; 080_Tähis SE: SE AB 4.1M4
AR_Ruum - 100_Nimi: Panipaik; 105_Number: AB-4224; 110_Tüüp: Mitteeluruumid; 115_Kategooria: RR Büroo; 120_Pindala: 2.63711 m2; 125_Turvatsoon: Kollane
BaseQuantities - NetFloorArea: 2.63711 m2; Height: 3000 mm; GrossFloorArea: 2.63711 m2; GrossVolume: 7.91134 m3

# IfcSpace: Pesuruum AB-01121:1465444, AB-01121
In: -1. korrus
LongName: Pesuruum; InteriorOrExteriorSpace: INTERNAL; Group: SE AB -1.1M4 kõrvaltsoon
Pset_AirSideSystemInformation - Name: Pesuruum
Pset_ProductRequirements - Name: Pesuruum; Category: 12623 Raamatukogu
Pset_SpaceCommon - Reference: Pesuruum AB-01121; Category: 12623 Raamatukogu
AR_Tsoon - 085_Tuletõkkesektsioon: EI60; 090_Pindala: 26.4041 m2; 080_Tähis SE: SE AB -1.1M4 kõrvaltsoon
AR_Ruum - 100_Nimi: Pesuruum; 105_Number: AB-01121; 110_Tüüp: Mitteeluruumid; 115_Kategooria: RR mitteeluruum; 120_Pindala: 26.4041 m2; 125_Turvatsoon: Punane
BaseQuantities - NetFloorArea: 26.4041 m2; Height: 2985 mm; GrossFloorArea: 26.4041 m2; GrossVolume: 78.8162 m3

# IfcSpace: Puhkeala koridor F-1006.2:13447483, F-1006.2
In: 1. korrus
LongName: Puhkeala koridor; InteriorOrExteriorSpace: INTERNAL; Group: TT 05; SE F 1.1M2
Pset_AirSideSystemInformation - Name: Puhkeala koridor; sets with these values: 2
Pset_SpaceCommon - Reference: Puhkeala koridor F-1006.2
AR_Tsoon - 080_Tähis TO: TT 05; 090_Pindala: 23.4112 m2; 080_Tähis SE: SE F 1.1M2
AR_Ruum - 100_Nimi: Puhkeala koridor; 105_Number: F-1006.2; 110_Tüüp: Üldkasutatavad alad; 115_Kategooria: RR Büroo; 120_Pindala: 23.4112 m2; 125_Turvatsoon: Punane
BaseQuantities - NetFloorArea: 23.4112 m2; Height: 9900 mm; GrossFloorArea: 23.4112 m2; GrossVolume: 231.771 m3

# IfcSpace: RMIT kabinet / ladu AB-01111:1468833, AB-01111
In: -1. korrus
LongName: RMIT kabinet / ladu; InteriorOrExteriorSpace: INTERNAL; Group: SE AB -1.1M4 kõrvaltsoon
Pset_AirSideSystemInformation - Name: RMIT kabinet / ladu
Pset_ProductRequirements - Name: RMIT kabinet / ladu; Category: 12623 Raamatukogu
Pset_SpaceCommon - Reference: RMIT kabinet / ladu AB-01111; Category: 12623 Raamatukogu
AR_Tsoon - 085_Tuletõkkesektsioon: EI90; 090_Pindala: 30.315 m2; 080_Tähis SE: SE AB -1.1M4 kõrvaltsoon
AR_Ruum - 100_Nimi: RMIT kabinet / ladu; 105_Number: AB-01111; 110_Tüüp: Mitteeluruumid; 115_Kategooria: RR Büroo; 120_Pindala: 30.315 m2; 125_Turvatsoon: Punane
BaseQuantities - NetFloorArea: 30.315 m2; Height: 2985 mm; GrossPerimeter: 22734.1 mm; GrossFloorArea: 30.315 m2; GrossVolume: 90.4904 m3

# IfcSpace: Riietus AB-01014:9327002, AB-01014
In: -1. korrus
LongName: Riietus; InteriorOrExteriorSpace: INTERNAL; Group: TT 48; SE AB -1.1M4
Pset_AirSideSystemInformation - Name: Riietus; sets with these values: 2
Pset_SpaceCommon - Reference: Riietus AB-01014
AR_Tsoon - 080_Tähis TO: TT 48; 085_Tuletõkkesektsioon: EI60; 090_Pindala: 8.63759 m2; 080_Tähis SE: SE AB -1.1M4
AR_Ruum - 100_Nimi: Riietus; 105_Number: AB-01014; 110_Tüüp: Üldkasutatavad alad; 115_Kategooria: Personaliruumid; 120_Pindala: 8.63759 m2; 125_Turvatsoon: Roheline
BaseQuantities - NetFloorArea: 8.63759 m2; Height: 9900 mm; GrossFloorArea: 8.63759 m2; GrossVolume: 85.5121 m3

# IfcSpace: Sprinkleri vahekeskus AB-01305:8066055, AB-01305
In: -1. korrus
LongName: Sprinkleri vahekeskus; InteriorOrExteriorSpace: INTERNAL; Group: SE AB -1.1M4 kõrvaltsoon
Pset_AirSideSystemInformation - Name: Sprinkleri vahekeskus; sets with these values: 2
Pset_SpaceCommon - Reference: Sprinkleri vahekeskus AB-01305
AR_Tsoon - 085_Tuletõkkesektsioon: EI60; 090_Pindala: 24.9205 m2; 080_Tähis SE: SE AB -1.1M4 kõrvaltsoon
AR_Ruum - 100_Nimi: Sprinkleri vahekeskus; 105_Number: AB-01305; 110_Tüüp: Tehnilised ruumid; 115_Kategooria: Tehnilised ruumid; 120_Pindala: 24.9205 m2; 125_Turvatsoon: Punane
BaseQuantities - NetFloorArea: 24.9205 m2; Height: 9900 mm; GrossFloorArea: 24.9205 m2; GrossVolume: 246.713 m3

# IfcSpace: TR5 AB-1010:2608967, AB-1010
In: 1. korrus
LongName: TR5; InteriorOrExteriorSpace: INTERNAL
Pset_AirSideSystemInformation - Name: TR5; sets with these values: 2
Pset_SpaceCommon - Reference: TR5 AB-1010
AR_Tsoon - 085_Tuletõkkesektsioon: EI60; 090_Pindala: 15.308 m2
AR_Ruum - 100_Nimi: TR5; 105_Number: AB-1010; 110_Tüüp: Üldkasutatavad alad; 115_Kategooria: Üldala; 120_Pindala: 15.308 m2; 125_Turvatsoon: Roheline
BaseQuantities - NetFloorArea: 15.308 m2; Height: 3000 mm; GrossPerimeter: 16620 mm; GrossFloorArea: 15.308 m2; GrossVolume: 45.924 m3

# IfcSpace: TR5 AB-2012:2605995, AB-2012
In: 2. korrus
LongName: TR5; InteriorOrExteriorSpace: INTERNAL
Pset_AirSideSystemInformation - Name: TR5; sets with these values: 2
Pset_SpaceCommon - Reference: TR5 AB-2012
AR_Tsoon - 085_Tuletõkkesektsioon: EI60; 090_Pindala: 15.4165 m2
AR_Ruum - 100_Nimi: TR5; 105_Number: AB-2012; 110_Tüüp: Üldkasutatavad alad; 115_Kategooria: Üldala; 120_Pindala: 15.4165 m2; 125_Turvatsoon: Roheline
BaseQuantities - NetFloorArea: 15.4165 m2; Height: 3000 mm; GrossPerimeter: 16791 mm; GrossFloorArea: 15.4165 m2; GrossVolume: 46.2496 m3

# IfcSpace: TR7 AB-2001:2606016, AB-2001
In: 2. korrus
LongName: TR7; InteriorOrExteriorSpace: INTERNAL
Pset_AirSideSystemInformation - Name: TR7; sets with these values: 2
Pset_SpaceCommon - Reference: TR7 AB-2001
AR_Tsoon - 085_Tuletõkkesektsioon: EI60; 090_Pindala: 11.4736 m2
AR_Ruum - 100_Nimi: TR7; 105_Number: AB-2001; 110_Tüüp: Üldkasutatavad alad; 115_Kategooria: Üldala; 120_Pindala: 11.4736 m2; 125_Turvatsoon: Roheline
BaseQuantities - NetFloorArea: 11.4736 m2; Height: 3935.73 mm; GrossFloorArea: 11.4736 m2; GrossVolume: 45.1569 m3

# IfcSpace: TR8 E-1006:4268952, E-1006
In: 1. korrus
LongName: TR8; InteriorOrExteriorSpace: INTERNAL; Group: SE TR8 L3
Pset_AirSideSystemInformation - Name: TR8; sets with these values: 2
Pset_SpaceCommon - Reference: TR8 E-1006
AR_Tsoon - 085_Tuletõkkesektsioon: EI60; 090_Pindala: 25.1668 m2; 080_Tähis SE: SE TR8 L3
AR_Ruum - 100_Nimi: TR8; 105_Number: E-1006; 110_Tüüp: Üldkasutatavad alad; 115_Kategooria: Üldala; 120_Pindala: 25.1668 m2; 125_Turvatsoon: Roheline
BaseQuantities - NetFloorArea: 25.1668 m2; Height: 3576.83 mm; GrossFloorArea: 25.1668 m2; GrossVolume: 90.0175 m3

# IfcSpace: TR8 E-2003:5244741, E-2003
In: E-korpus 2. korrus
LongName: TR8; InteriorOrExteriorSpace: INTERNAL; Group: SE TR8 L3
Pset_AirSideSystemInformation - Name: TR8; sets with these values: 2
Pset_SpaceCommon - Reference: TR8 E-2003
AR_Tsoon - 085_Tuletõkkesektsioon: EI60; 090_Pindala: 23.5743 m2; 080_Tähis SE: SE TR8 L3
AR_Ruum - 100_Nimi: TR8; 105_Number: E-2003; 110_Tüüp: Üldkasutatavad alad; 115_Kategooria: Üldala; 120_Pindala: 23.5743 m2; 125_Turvatsoon: Roheline
BaseQuantities - NetFloorArea: 23.5743 m2; Height: 6353.19 mm; GrossFloorArea: 23.5743 m2; GrossVolume: 149.772 m3

# IfcSpace: Tehniline ruum AB-02304:5478881, AB-02304
In: E-korpus -1. korrus
LongName: Tehniline ruum; InteriorOrExteriorSpace: INTERNAL; Group: SE AB -2.1M2 AT
Pset_AirSideSystemInformation - Name: Tehniline ruum; sets with these values: 2
Pset_SpaceCommon - Reference: Tehniline ruum AB-02304
AR_Tsoon - 085_Tuletõkkesektsioon: EI60; 090_Pindala: 27.2621 m2; 080_Tähis SE: SE AB -2.1M2 AT
AR_Ruum - 100_Nimi: Tehniline ruum; 105_Number: AB-02304; 110_Tüüp: Tehnilised ruumid; 115_Kategooria: Tehnilised ruumid; 120_Pindala: 27.2621 m2; 125_Turvatsoon: Punane
BaseQuantities - NetFloorArea: 27.2621 m2; Height: 2830 mm; GrossPerimeter: 36761.8 mm; GrossFloorArea: 27.2621 m2; GrossVolume: 77.1517 m3

# IfcSpace: Tehniline ruum AB-02305:5479009, AB-02305
In: -2. korrus
LongName: Tehniline ruum; InteriorOrExteriorSpace: INTERNAL; Group: SE AB -2.1M2 AT; TT 41
Pset_AirSideSystemInformation - Name: Tehniline ruum; sets with these values: 2
Pset_SpaceCommon - Reference: Tehniline ruum AB-02305
AR_Tsoon - 080_Tähis TO: TT 41; 085_Tuletõkkesektsioon: EI60; 090_Pindala: 61.1549 m2; 080_Tähis SE: SE AB -2.1M2 AT
AR_Ruum - 100_Nimi: Tehniline ruum; 105_Number: AB-02305; 110_Tüüp: Tehnilised ruumid; 115_Kategooria: Tehnilised ruumid; 120_Pindala: 61.1549 m2; 125_Turvatsoon: Punane
BaseQuantities - NetFloorArea: 61.1549 m2; Height: 4090 mm; GrossFloorArea: 61.1549 m2; GrossVolume: 250.124 m3

# IfcSpace: Tehno F-2301:5698775, F-2301
In: E-korpus 2. korrus
LongName: Tehno; InteriorOrExteriorSpace: INTERNAL
Pset_AirSideSystemInformation - Name: Tehno; sets with these values: 2
Pset_SpaceCommon - Reference: Tehno F-2301
AR_Tsoon - 090_Pindala: 38.1265 m2
AR_Ruum - 100_Nimi: Tehno; 105_Number: F-2301; 110_Tüüp: Tehnilised ruumid; 115_Kategooria: Tehnilised ruumid; 120_Pindala: 38.1265 m2; 125_Turvatsoon: Punane
BaseQuantities - NetFloorArea: 38.1265 m2; Height: 2370 mm; GrossFloorArea: 38.1265 m2; GrossVolume: 90.3598 m3

# IfcSpace: Trepi panipaik F-1005:7790228, F-1005
In: 1. korrus
LongName: Trepi panipaik; InteriorOrExteriorSpace: INTERNAL
Pset_AirSideSystemInformation - Name: Trepi panipaik; sets with these values: 2
Pset_SpaceCommon - Reference: Trepi panipaik F-1005
AR_Tsoon - 085_Tuletõkkesektsioon: EI120; 090_Pindala: 19.3138 m2
AR_Ruum - 100_Nimi: Trepi panipaik; 105_Number: F-1005; 110_Tüüp: Üldkasutatavad alad; 115_Kategooria: Üldala; 120_Pindala: 19.3138 m2; 125_Turvatsoon: Kollane
BaseQuantities - NetFloorArea: 19.3138 m2; Height: 3494.13 mm; GrossFloorArea: 19.3138 m2; GrossVolume: 67.4851 m3

# IfcSpace: Töökoda AB-01110:1468831, AB-01110
In: -1. korrus
LongName: Töökoda; InteriorOrExteriorSpace: INTERNAL; Group: TT 48; SE AB -1.1M4
Pset_AirSideSystemInformation - Name: Töökoda
Pset_ProductRequirements - Name: Töökoda; Category: 12200 Büroo
Pset_SpaceCommon - Reference: Töökoda AB-01110; Category: 12200 Büroo
AR_Tsoon - 080_Tähis TO: TT 48; 085_Tuletõkkesektsioon: EI60; 090_Pindala: 22.856 m2; 080_Tähis SE: SE AB -1.1M4
AR_Ruum - 100_Nimi: Töökoda; 105_Number: AB-01110; 110_Tüüp: Mitteeluruumid; 115_Kategooria: RR Büroo; 120_Pindala: 22.856 m2; 125_Turvatsoon: Punane
BaseQuantities - NetFloorArea: 22.856 m2; Height: 2985 mm; GrossFloorArea: 22.856 m2; GrossVolume: 68.2251 m3

# IfcSpace: Tööruum AB-2201:7506857, AB-2201
In: 2. korrus
LongName: Tööruum; InteriorOrExteriorSpace: INTERNAL; Group: TT 01; SE AB 1.1M4
Pset_AirSideSystemInformation - Name: Tööruum
Pset_ProductRequirements - Name: Tööruum; Category: 12623 Raamatukogu
Pset_SpaceCommon - Reference: Tööruum AB-2201; Category: 12623 Raamatukogu
AR_Tsoon - 080_Tähis TO: TT 01; 085_Tuletõkkesektsioon: EI60; 090_Pindala: 31.1399 m2; 080_Tähis SE: SE AB 1.1M4
AR_Ruum - 100_Nimi: Tööruum; 105_Number: AB-2201; 110_Tüüp: Mitteeluruumid; 115_Kategooria: RR Büroo; 120_Pindala: 31.1399 m2; 125_Turvatsoon: Kollane
BaseQuantities - NetFloorArea: 31.1399 m2; Height: 3000 mm; GrossPerimeter: 22371 mm; GrossFloorArea: 31.1399 m2; GrossVolume: 93.4197 m3

# IfcSpace: Vabakasutus AB-01112:4579865, AB-01112
In: -1. korrus
LongName: Vabakasutus; InteriorOrExteriorSpace: INTERNAL
Pset_AirSideSystemInformation - Name: Vabakasutus
Pset_ProductRequirements - Name: Vabakasutus; Category: 12200 Büroo
Pset_SpaceCommon - Reference: Vabakasutus AB-01112; Category: 12200 Büroo
AR_Tsoon - 085_Tuletõkkesektsioon: EI90; 090_Pindala: 28.8619 m2
AR_Ruum - 100_Nimi: Vabakasutus; 105_Number: AB-01112; 110_Tüüp: Mitteeluruumid; 115_Kategooria: RR Büroo; 120_Pindala: 28.8619 m2; 125_Turvatsoon: Kollane
BaseQuantities - NetFloorArea: 28.8619 m2; Height: 2985 mm; GrossFloorArea: 28.8619 m2; GrossVolume: 86.1528 m3

# IfcSpace: Vanema ja lapse tuba AB-3206:2603919, AB-3206
In: 3. korrus
LongName: Vanema ja lapse tuba; InteriorOrExteriorSpace: INTERNAL; Group: SE AB 3.1M2 kõrvaltsoon
Pset_AirSideSystemInformation - Name: Vanema ja lapse tuba
Pset_ProductRequirements - Name: Vanema ja lapse tuba; Category: 12200 Büroo
Pset_SpaceCommon - Reference: Vanema ja lapse tuba AB-3206; Category: 12200 Büroo
AR_Tsoon - 085_Tuletõkkesektsioon: EI120; 090_Pindala: 7.5593 m2; 080_Tähis SE: SE AB 3.1M2 kõrvaltsoon
AR_Ruum - 100_Nimi: Vanema ja lapse tuba; 105_Number: AB-3206; 110_Tüüp: Mitteeluruumid; 115_Kategooria: Üldala; 120_Pindala: 7.5593 m2; 125_Turvatsoon: Roheline
BaseQuantities - NetFloorArea: 7.5593 m2; Height: 3000 mm; GrossPerimeter: 11302 mm; GrossFloorArea: 7.5593 m2; GrossVolume: 22.6779 m3

# IfcSpace: Vent.ruum AB-01304:1465447, AB-01304
In: -1. korrus
LongName: Vent.ruum; InteriorOrExteriorSpace: INTERNAL; Group: SE AB -1.1M4 kõrvaltsoon
Pset_AirSideSystemInformation - Name: Vent.ruum; sets with these values: 2
Pset_SpaceCommon - Reference: Vent.ruum AB-01304
AR_Tsoon - 085_Tuletõkkesektsioon: EI60; 090_Pindala: 24.808 m2; 080_Tähis SE: SE AB -1.1M4 kõrvaltsoon
AR_Ruum - 100_Nimi: Vent.ruum; 105_Number: AB-01304; 110_Tüüp: Tehnilised ruumid; 115_Kategooria: Tehnilised ruumid; 120_Pindala: 24.808 m2; 125_Turvatsoon: Punane
BaseQuantities - NetFloorArea: 24.808 m2; Height: 2985 mm; GrossFloorArea: 24.808 m2; GrossVolume: 74.0519 m3

# IfcSpace: WC AB-01011:9327000, AB-01011
In: -1. korrus
LongName: WC; InteriorOrExteriorSpace: INTERNAL; Group: TT 48; SE AB -1.1M4
Pset_AirSideSystemInformation - Name: WC; sets with these values: 2
Pset_SpaceCommon - Reference: WC AB-01011
AR_Tsoon - 080_Tähis TO: TT 48; 085_Tuletõkkesektsioon: EI60; 090_Pindala: 3.08757 m2; 080_Tähis SE: SE AB -1.1M4
AR_Ruum - 100_Nimi: WC; 105_Number: AB-01011; 110_Tüüp: Üldkasutatavad alad; 115_Kategooria: Personaliruumid; 120_Pindala: 3.08757 m2; 125_Turvatsoon: Roheline
BaseQuantities - NetFloorArea: 3.08757 m2; Height: 9900 mm; GrossPerimeter: 7334.03 mm; GrossFloorArea: 3.08757 m2; GrossVolume: 30.567 m3

# IfcSpace: WC E-2001:2863409, E-2001
In: E-korpus 2. korrus
LongName: WC; InteriorOrExteriorSpace: INTERNAL; Group: TT 26
Pset_AirSideSystemInformation - Name: WC; sets with these values: 2
Pset_SpaceCommon - Reference: WC E-2001
AR_Tsoon - 080_Tähis TO: TT 26; 085_Tuletõkkesektsioon: EI60; 090_Pindala: 2.43845 m2
AR_Ruum - 100_Nimi: WC; 105_Number: E-2001; 110_Tüüp: Üldkasutatavad alad; 115_Kategooria: Üldala; 120_Pindala: 2.43845 m2; 125_Turvatsoon: Kollane
BaseQuantities - NetFloorArea: 2.43845 m2; Height: 5370 mm; GrossPerimeter: 6633.62 mm; GrossFloorArea: 2.43845 m2; GrossVolume: 13.0945 m3

# IfcSpace: wc AB-1011:2608969, AB-1011
In: 1. korrus
LongName: wc; InteriorOrExteriorSpace: INTERNAL; Group: TT 57
Pset_AirSideSystemInformation - Name: wc; sets with these values: 2
Pset_SpaceCommon - Reference: wc AB-1011
AR_Tsoon - 080_Tähis TO: TT 57; 085_Tuletõkkesektsioon: EI60; 090_Pindala: 7.37265 m2
AR_Ruum - 100_Nimi: wc; 105_Number: AB-1011; 110_Tüüp: Üldkasutatavad alad; 115_Kategooria: Üldala; 120_Pindala: 7.37265 m2; 125_Turvatsoon: Roheline
BaseQuantities - NetFloorArea: 7.37265 m2; Height: 3000 mm; GrossPerimeter: 13870 mm; GrossFloorArea: 7.37265 m2; GrossVolume: 22.1179 m3

# IfcSpace: wc N E-1002:7811904, E-1002
In: 1. korrus
LongName: wc N; InteriorOrExteriorSpace: INTERNAL; Group: TT 01; SE AB 1.1M4
Pset_AirSideSystemInformation - Name: wc N; sets with these values: 2
Pset_SpaceCommon - Reference: wc N E-1002
AR_Tsoon - 080_Tähis TO: TT 01; 085_Tuletõkkesektsioon: EI60; 090_Pindala: 20.5576 m2; 080_Tähis SE: SE AB 1.1M4
AR_Ruum - 100_Nimi: wc N; 105_Number: E-1002; 110_Tüüp: Üldkasutatavad alad; 115_Kategooria: Konverentsikeskus; 120_Pindala: 20.5576 m2; 125_Turvatsoon: Kollane
BaseQuantities - NetFloorArea: 20.5576 m2; Height: 9900 mm; GrossPerimeter: 28902.2 mm; GrossFloorArea: 20.5576 m2; GrossVolume: 203.52 m3

# IfcSpace: Õppeklass F-1115:2386106, F-1115
In: 1. korrus
LongName: Õppeklass; InteriorOrExteriorSpace: INTERNAL; Group: TT 05
Pset_AirSideSystemInformation - Name: Õppeklass
Pset_ProductRequirements - Name: Õppeklass; Category: 12200 Büroo
Pset_SpaceCommon - Reference: Õppeklass F-1115; Category: 12200 Büroo
AR_Tsoon - 080_Tähis TO: TT 05; 085_Tuletõkkesektsioon: EI60; 090_Pindala: 51.1523 m2
AR_Ruum - 100_Nimi: Õppeklass; 105_Number: F-1115; 110_Tüüp: Mitteeluruumid; 115_Kategooria: RR Büroo; 120_Pindala: 51.1523 m2; 125_Turvatsoon: Punane
BaseQuantities - NetFloorArea: 51.1523 m2; Height: 2980 mm; GrossPerimeter: 31055 mm; GrossFloorArea: 51.1523 m2; GrossVolume: 152.434 m3

# IfcBeam: -2.korruse kanali tala:-2.korruse kanali tala, -2.korruse kanali tala:-2.korruse kanali tala:5245717
In: -1. korrus
Type - Pset_BeamCommon - IsExternal: no; LoadBearing: yes
Material: ol. olev materjal
BaseQuantities - Length: 543.81 mm; CrossSectionArea: 0.807742 m2; OuterSurfaceArea: 3.02324 m2; GrossVolume: 0.439258 m3; NetVolume: 0.439258 m3
Pset_BeamCommon - Reference: -2.korruse kanali tala
Pset_QuantityTakeOff - Reference: -2.korruse kanali tala; sets with these values: 2

# IfcColumn: Post, nelinurkne:ol. olev - 400x 400mm (15)
Type - PredefinedType: COLUMN; Material: ol. olev materjal
Type - Pset_ColumnCommon - IsExternal: no
Pset_ColumnCommon - Reference: ol. olev - 400x 400mm
Pset_QuantityTakeOff - Reference: ol. olev - 400x 400mm; sets with these values: 2
Name (Post, nelinurkne:ol. olev - 400x 400mm:...) | In | Length (mm) | CrossSectionArea (m2) | OuterSurfaceArea (m2) | GrossVolume (m3) | NetVolume (m3)
985273 | 2. korrus | 2730 | 0.16 | 4.368 | 0.4368 | 0.4848
985863 | 2. korrus | 2730 | 0.16 | 4.368 | 0.4368 | 0.4848
990545 | 3. korrus |  | 2.3447 |  |  | 0.430462
990559 | 3. korrus |  | 2.3447 |  |  | 0.430462
1030307 | -1. korrus | 1650 | 0.16 | 2.64 | 0.264 | 0.264
1030632 | -1. korrus | 2750 | 0.16 | 4.4 | 0.44 | 0.4912
1356715 | 3. korrus | 400 | 1.06 | 2.536 | 0.424 | 0.424
1356747 | 3. korrus | 400 | 1.16 | 2.736 | 0.464 | 0.464
1477402 | 3. korrus | 400 | 1.16 | 2.736 | 0.464 | 0.464
1477403 | 3. korrus | 3000 | 0.16 | 4.8 | 0.48 | 0.48
1477404 | 3. korrus | 2750 | 0.16 | 4.4 | 0.44 | 0.44 | Pset_ColumnCommon - Slope: 0 deg
1477405 | 3. korrus | 400 | 1.06 | 2.536 | 0.424 | 0.424 | Pset_ColumnCommon - Slope: 0 deg
2094417 | 1. korrus | 400 | 1.2753 | 2.96 | 0.51012 | 0.51012 | Pset_ColumnCommon - Slope: 0 deg
2608731 | 1. korrus | 1100 | 0.16 | 1.76 | 0.176 | 0.7552
8666306 | 3. korrus | 400 | 1.06 | 2.536 | 0.424 | 0.424 | Pset_ColumnCommon - Slope: 0 deg

# IfcCovering: Basic Roof:TV-01 plaat 1 (tume) (5)
Type - Pset_ConcreteElementGeneral - FireRating: -
Type - Pset_CoveringCommon - FireRating: -; AcousticRating: -; FlammabilityRating: A1- A1fl
Type - Pset_ManufacturerTypeInformation - Manufacturer: Energie KER
Type - AR_Viimistlus - 000_Muinsuskaitse: no; 001_Nimetus: TV-01 plaat 1 (tume); 205_Tüüp: TV-01; 200_Materjal: Täismassplaat; 215_Tulekindlusklass: A1- A1fl; 220_Viimistlus: Piombo RT (tumehall); 240_Märghõõrdekindlus: 3; 245_Aluspind: Reguleeritavate tugijalgade süsteem DD Pedestals; 900_Tootja: Energie KER; 905_Mudel: Basaltina
Material: EST. Betoonplaat tume 20 mm
Pset_CoveringCommon - Reference: TV-01 plaat 1 (tume); TotalThickness: 20 mm
Pset_QuantityTakeOff - Reference: TV-01 plaat 1 (tume)
AR_Viimistlus - 230_Niiskuskindlus: yes; 003_Elemendi_staadium: Projekteeritud; 210_Paksus: 20 mm
Name (Basic Roof:TV-01 plaat 1 (tume):...) | In | 225_Pindala (m2) = GrossCeilingArea (m2)
9925995 | 3. korrus | 46.98
9926006 | 3. korrus | 47.0061
9953289 | 1. korrus | 26.348
9953300 | 1. korrus | 26.1431
10916931 | E-korpus 2. korrus | 1124.89

# IfcCovering: Basic Roof:TV-01 plaat 1 (tume) 2 (2)
In: 1. korrus
Type - Pset_ConcreteElementGeneral - FireRating: -
Type - Pset_CoveringCommon - FireRating: -; AcousticRating: -; FlammabilityRating: A1- A1fl
Type - Pset_ManufacturerTypeInformation - Manufacturer: Energie KER
Type - AR_Viimistlus - 000_Muinsuskaitse: no; 001_Nimetus: TV-01 plaat 1 (tume) 2; 200_Materjal: Täismassplaat; 215_Tulekindlusklass: A1- A1fl; 220_Viimistlus: Piombo RT (tumehall); 240_Märghõõrdekindlus: 3; 245_Aluspind: Reguleeritavate tugijalgade süsteem DD Pedestals; 900_Tootja: Energie KER; 905_Mudel: Basaltina
Material: EST. Betoonplaat tume 20 mm, LUMION_grey concrete 130 mm
Pset_CoveringCommon - Reference: TV-01 plaat 1 (tume) 2; TotalThickness: 150 mm
Pset_QuantityTakeOff - Reference: TV-01 plaat 1 (tume) 2
AR_Viimistlus - 230_Niiskuskindlus: yes; 003_Elemendi_staadium: Projekteeritud; 210_Paksus: 150 mm
Name (Basic Roof:TV-01 plaat 1 (tume) 2:...) | 225_Pindala (m2) = GrossCeilingArea (m2)
11999270 | 35.2391
11999337 | 27.121

# IfcCovering: Basic Roof:TV-01 plaat 2 (hele) (3)
Type - Pset_ConcreteElementGeneral - FireRating: -
Type - Pset_CoveringCommon - FireRating: -; AcousticRating: -; FlammabilityRating: A1- A1fl
Type - Pset_ManufacturerTypeInformation - Manufacturer: Energie KER
Type - AR_Viimistlus - 000_Muinsuskaitse: no; 001_Nimetus: TV-01 plaat 2 (hele); 205_Tüüp: TV-02; 200_Materjal: Täismassplaat; 215_Tulekindlusklass: A1- A1fl; 220_Viimistlus: Groa RT (helehall); 240_Märghõõrdekindlus: 3; 245_Aluspind: Reguleeritavate tugijalgade süsteem DD Pedestals; 900_Tootja: Energie KER; 905_Mudel: Sunstone
Material: EST. Betoonplaat hele 20 mm
Pset_CoveringCommon - Reference: TV-01 plaat 2 (hele); TotalThickness: 20 mm
Pset_QuantityTakeOff - Reference: TV-01 plaat 2 (hele)
AR_Viimistlus - 003_Elemendi_staadium: Projekteeritud; 210_Paksus: 20 mm; 230_Niiskuskindlus: yes
Name (Basic Roof:TV-01 plaat 2 (hele):...) | In | 225_Pindala (m2) = GrossCeilingArea (m2)
9904870 | 5. korrus | 105.858
9907522 | 4. korrus | 106.173
9925976 | 3. korrus | 105.941

# IfcCovering: Fassaadiplaat:FP-01- 400x840 (94)
In: 3. korrus
Type - Pset_CoveringCommon - FlammabilityRating: A1
Type - Pset_ManufacturerTypeInformation - Manufacturer: LEVANTINA
Type - AR_Viimistlus - 000_Muinsuskaitse: no; 001_Nimetus: FP-01- 400x840; 205_Tüüp: FP-01; 200_Materjal: Läbimassplaat; 215_Tulekindlusklass: A1; 220_Viimistlus: toon BLAZE DARK 5mm; 240_Märghõõrdekindlus: 5; 245_Aluspind: Ol. Olev sein, alumiiniumprofiil fassaadisüsteem; 900_Tootja: LEVANTINA; 905_Mudel: Techlam
Material: LUMION_facade new panels
Pset_CoveringCommon - Reference: FP-01- 400x840; sets with these values: 2
AR_Viimistlus - 230_Niiskuskindlus: yes; 003_Elemendi_staadium: Projekteeritud; 225_Pindala: 0.7092 m2
BaseQuantities - GrossCeilingArea: 0.7092 m2
Name (Fassaadiplaat:FP-01- 400x840:...)
11730653
11741982
11742178
11742308
11742438
11742568
11742698
11742828
11742958
11743088
11743218
11743348
11743478
11743608
11743738
11743868
11743998
11744128
11744258
11744388
11744518
11744648
11744778
11744908
11745038
11745168
11745298
11745428
11745558
11745688
11745818
11745948
11746078
11746208
11746338
11746468
11746598
11746728
11746858
11746988
11747118
11747248
11747378
11747508
11747638
11747768
11747898
11748599
11748876
11748907
11748910
11748913
11748916
11748919
11748922
11748925
11748928
11748931
11748934
11748937
11748940
11748943
11748946
11748949
11748952
11748955
11748958
11748961
11748964
11748967
11748970
11748973
11748976
11748979
11748982
11748985
11748988
11748991
11748994
11748997
11749000
11749003
11749006
11749009
11749012
11749015
11749018
11749021
11749024
11749027
11749030
11749033
11749036
11749039

# IfcCurtainWall: Curtain Wall:A-15 (2)
In: 3. korrus
Type - Pset_ConcreteElementGeneral - FireRating: -
Type - Pset_CurtainWallCommon - IsExternal: yes; AcousticRating: 35dB; FireRating: -; ThermalTransmittance: 0.81 kg/K/s3
Type - Pset_ManufacturerTypeInformation - Manufacturer: Aluprof
Type - AR_Rippfassaad - 335_Välispiire: yes; 001_Nimetus: A-15; 300_Tüüp: A-15; 305_Ava_mõõt: 2600x2300; 320_Klaas: Toonitud peegelklaas, pronks; 325_Helipidavus: 35dB; 315_Avanemine: Saksa tüüpi; 330_Tulekindlus: -; 340_Soojusläbivus: 0.81; 350_Klaaspakett: 3x klaaspakett, toonitud peegelklaas, pronks; 375_Viimistlus_seest: RAL 9005 (must); 376_Viimistlus_väljast: RAL 9005 (must); 385_Raami_materjal: Alumiiniumprofiil; 900_Tootja: Aluprof; 905_Mudel: MB-104 Passive SI
Type - AR_Aken - 335_Väalispiire: yes; 001_Nimetus: A-15; 300_Tüüp: A-15; 310_Materjal: Alumiinium; 315_Avanemine: Saksa tüüpi; 320_Klaas: Toonitud peegelklaas, pronks; 325_Helipidavus: 35dB; 330_Tulekindlus: -; 340_Soojusläbivus: 0.81; 350_Klaaspakett: 3x klaaspakett, toonitud peegelklaas, pronks; 375_Viimistlus_seest: RAL 9005 (must); 376_Viimistlus_väljast: RAL 9005 (must); 900_Tootja: Aluprof; 905_Mudel: MB-104 Passive SI
Type - SA_Rippfassaad - 325_Helipidavus: 35dB; 330_Tulekindlus: -; 340_Soojusläbivus: 0.81
Pset_CurtainWallCommon - Reference: A-15
Pset_QuantityTakeOff - Reference: A-15
AR_Rippfassaad - 003_Elemendi_staadium: Projekteeritud; 345_Päiksekiirgus_tegur: 0.4; 390_Paneeli_materjal: Toonitud peegelklaas, pronks
AR_Aken - 003_Elemendi_staadium: Projekteeritud; 345_Paiksekiirgus_tegur: 0.4
SA_Rippfassaad - 003_Elemendi_staadium: Projekteeritud
Name (Curtain Wall:A-15:...) | AR_Rippfassaad, 355_Pindala (m2) = AR_Aken, 355_Pindala (m2) = SA_Rippfassaad, 355_Pindala (m2) | 305_Ava_kõrgus
10357354 | 5.98 | 2300
10389266 | 5.746 | 2210

# IfcCurtainWall: Curtain Wall:A-16 (6)
In: 3. korrus
Type - Pset_ConcreteElementGeneral - FireRating: -
Type - Pset_CurtainWallCommon - IsExternal: yes; AcousticRating: 35dB; FireRating: -; ThermalTransmittance: 0.81 kg/K/s3
Type - Pset_ManufacturerTypeInformation - Manufacturer: Aluprof
Type - AR_Rippfassaad - 335_Välispiire: yes; 001_Nimetus: A-16; 300_Tüüp: A-16; 305_Ava_mõõt: 2600x2000; 320_Klaas: Toonitud peegelklaas, pronks; 325_Helipidavus: 35dB; 315_Avanemine: Saksa tüüpi; 330_Tulekindlus: -; 340_Soojusläbivus: 0.81; 350_Klaaspakett: 3x klaaspakett, toonitud peegelklaas, pronks; 375_Viimistlus_seest: RAL 9005 (must); 376_Viimistlus_väljast: RAL 9005 (must); 385_Raami_materjal: Alumiiniumprofiil; 900_Tootja: Aluprof; 905_Mudel: MB-104 Passive SI
Type - AR_Aken - 335_Väalispiire: yes; 001_Nimetus: A-16; 300_Tüüp: A-16; 310_Materjal: Alumiinium; 315_Avanemine: Saksa tüüpi; 320_Klaas: Toonitud peegelklaas, pronks; 325_Helipidavus: 35dB; 330_Tulekindlus: -; 340_Soojusläbivus: 0.81; 350_Klaaspakett: 3x klaaspakett, toonitud peegelklaas, pronks; 375_Viimistlus_seest: RAL 9005 (must); 376_Viimistlus_väljast: RAL 9005 (must); 900_Tootja: Aluprof; 905_Mudel: MB-104 Passive SI
Type - SA_Rippfassaad - 325_Helipidavus: 35dB; 330_Tulekindlus: -; 340_Soojusläbivus: 0.81
Pset_CurtainWallCommon - Reference: A-16
Pset_QuantityTakeOff - Reference: A-16
AR_Rippfassaad - 003_Elemendi_staadium: Projekteeritud; 345_Päiksekiirgus_tegur: 0.4; 355_Pindala: 5.2 m2; 390_Paneeli_materjal: Toonitud peegelklaas, pronks
AR_Aken - 003_Elemendi_staadium: Projekteeritud; 345_Paiksekiirgus_tegur: 0.4; 355_Pindala: 5.2 m2
SA_Rippfassaad - 003_Elemendi_staadium: Projekteeritud; 305_Ava_kõrgus: 2000; 355_Pindala: 5.2 m2
Name (Curtain Wall:A-16:...)
10389264
10389365
10389384
10389437
10389456
10389475

# IfcCurtainWall: Curtain Wall:A-17 (2)
In: 3. korrus
Type - Pset_ConcreteElementGeneral - FireRating: -
Type - Pset_CurtainWallCommon - IsExternal: yes; AcousticRating: 35dB; FireRating: -; ThermalTransmittance: 0.8 kg/K/s3
Type - Pset_ManufacturerTypeInformation - Manufacturer: Aluprof
Type - AR_Rippfassaad - 335_Välispiire: yes; 001_Nimetus: A-17; 300_Tüüp: A-17; 305_Ava_mõõt: 2600x2000; 320_Klaas: Toonitud peegelklaas, pronks; 325_Helipidavus: 35dB; 315_Avanemine: Saksa tüüpi; 330_Tulekindlus: -; 340_Soojusläbivus: 0.8; 350_Klaaspakett: 3x klaaspakett, toonitud peegelklaas, pronks; 375_Viimistlus_seest: RAL 9005 (must); 376_Viimistlus_väljast: RAL 9005 (must); 385_Raami_materjal: Alumiiniumprofiil; 900_Tootja: Aluprof; 905_Mudel: MB-104 Passive SI
Type - AR_Aken - 335_Väalispiire: yes; 001_Nimetus: A-17; 300_Tüüp: A-17; 315_Avanemine: Saksa tüüpi; 320_Klaas: Toonitud peegelklaas, pronks; 325_Helipidavus: 35dB; 330_Tulekindlus: -; 340_Soojusläbivus: 0.8; 350_Klaaspakett: 3x klaaspakett, toonitud peegelklaas, pronks; 375_Viimistlus_seest: RAL 9005 (must); 376_Viimistlus_väljast: RAL 9005 (must); 900_Tootja: Aluprof; 905_Mudel: MB-104 Passive SI
Type - SA_Rippfassaad - 325_Helipidavus: 35dB; 330_Tulekindlus: -; 340_Soojusläbivus: 0.8
Pset_CurtainWallCommon - Reference: A-17
Pset_QuantityTakeOff - Reference: A-17
AR_Rippfassaad - 003_Elemendi_staadium: Projekteeritud; 345_Päiksekiirgus_tegur: 0.4; 355_Pindala: 4.745 m2; 390_Paneeli_materjal: Toonitud peegelklaas, pronks
AR_Aken - 003_Elemendi_staadium: Projekteeritud; 345_Paiksekiirgus_tegur: 0.4; 355_Pindala: 4.745 m2
SA_Rippfassaad - 003_Elemendi_staadium: Projekteeritud; 305_Ava_kõrgus: 2000; 355_Pindala: 4.745 m2
Name (Curtain Wall:A-17:...) | 001_Nimetus
10386003 | A-17p
10389494 | A-17v

# IfcCurtainWall: Curtain Wall:A-18 (2)
In: 3. korrus
Type - Pset_ConcreteElementGeneral - FireRating: -
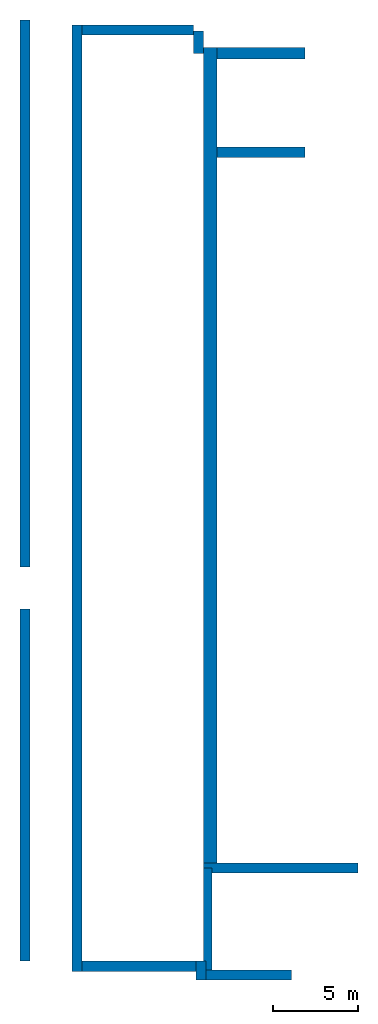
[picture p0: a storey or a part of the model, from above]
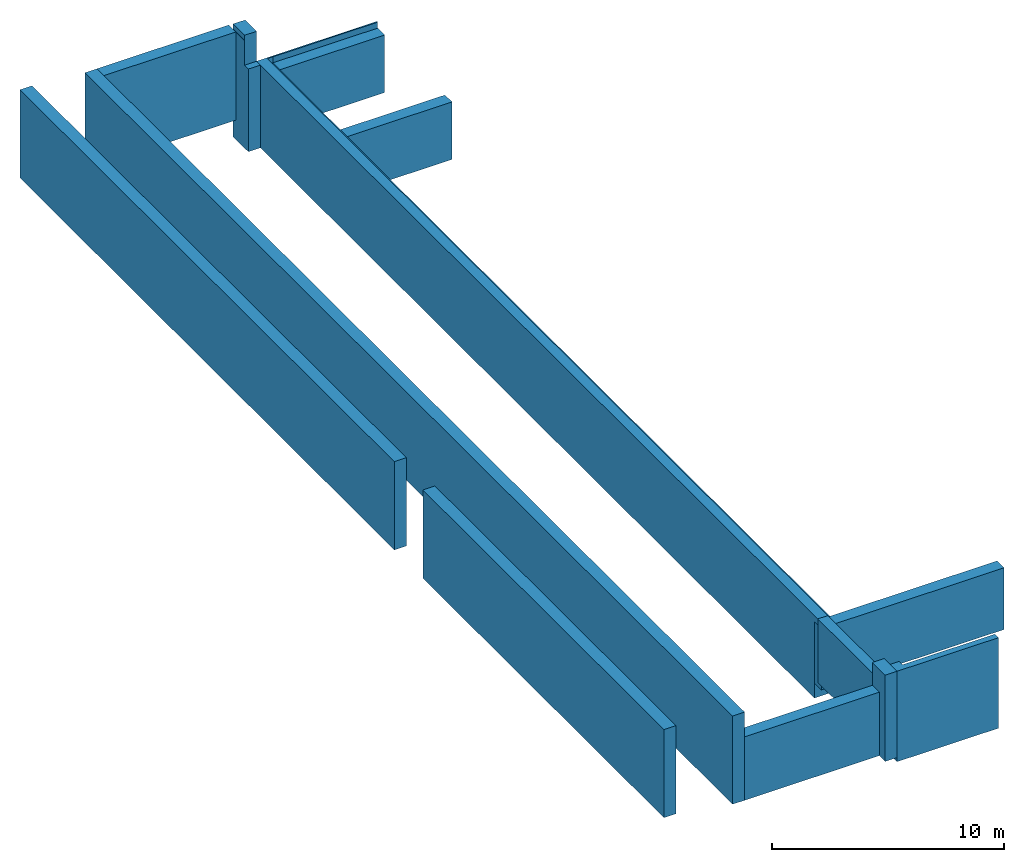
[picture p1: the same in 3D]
Properties of the parts of a building model (IFC2X3), part 2 of 7

# IfcCurtainWall: Curtain Wall:A-18 (2)
Type - Pset_CurtainWallCommon - IsExternal: yes; AcousticRating: 35dB; FireRating: -; ThermalTransmittance: 0.81 kg/K/s3
Type - Pset_ManufacturerTypeInformation - Manufacturer: Aluprof
Type - AR_Rippfassaad - 335_Välispiire: yes; 001_Nimetus: A-18; 300_Tüüp: A-18; 305_Ava_mõõt: 1300x1085; 320_Klaas: Toonitud peegelklaas, pronks; 325_Helipidavus: 35dB; 315_Avanemine: Saksa tüüpi; 330_Tulekindlus: -; 340_Soojusläbivus: 0.81; 350_Klaaspakett: 3x klaaspakett, toonitud peegelklaas, pronks; 375_Viimistlus_seest: RAL 9005 (must); 376_Viimistlus_väljast: RAL 9005 (must); 385_Raami_materjal: Alumiiniumprofiil; 900_Tootja: Aluprof; 905_Mudel: MB-104 Passive SI
Type - AR_Aken - 335_Väalispiire: yes; 001_Nimetus: A-18; 300_Tüüp: A-18; 310_Materjal: Alumiinium; 315_Avanemine: Saksa tüüpi; 320_Klaas: Toonitud peegelklaas, pronks; 325_Helipidavus: 35dB; 330_Tulekindlus: -; 340_Soojusläbivus: 0.81; 350_Klaaspakett: 3x klaaspakett, toonitud peegelklaas, pronks; 375_Viimistlus_seest: RAL 9005 (must); 376_Viimistlus_väljast: RAL 9005 (must); 900_Tootja: Aluprof; 905_Mudel: MB-104 Passive SI
Type - SA_Rippfassaad - 325_Helipidavus: 35dB; 330_Tulekindlus: -; 340_Soojusläbivus: 0.81
Pset_CurtainWallCommon - Reference: A-18
Pset_QuantityTakeOff - Reference: A-18
AR_Rippfassaad - 003_Elemendi_staadium: Projekteeritud; 345_Päiksekiirgus_tegur: 0.4; 355_Pindala: 0.955 m2; 390_Paneeli_materjal: Toonitud peegelklaas, pronks
AR_Aken - 003_Elemendi_staadium: Projekteeritud; 345_Paiksekiirgus_tegur: 0.4; 355_Pindala: 0.955 m2
SA_Rippfassaad - 003_Elemendi_staadium: Projekteeritud; 305_Ava_kõrgus: 1085; 355_Pindala: 0.955 m2
Name (Curtain Wall:A-18:...) | 001_Nimetus
10385964 | A-18v
10386025 | A-18p

# IfcCurtainWall: Curtain Wall:Ak-02 (6)
In: 1. korrus
Type - Pset_ConcreteElementGeneral - FireRating: -
Type - Pset_CurtainWallCommon - IsExternal: yes; AcousticRating: 35dB; FireRating: -; ThermalTransmittance: 0.81 kg/K/s3
Type - Pset_ManufacturerTypeInformation - Manufacturer: Aluprof
Type - AR_Rippfassaad - 335_Välispiire: yes; 001_Nimetus: Ak-02; 300_Tüüp: Ak-02; 305_Ava_mõõt: 5200x2000; 320_Klaas: Toonitud peegelklaas, pronks; 325_Helipidavus: 35dB; 315_Avanemine: Saksa tüüpi; 330_Tulekindlus: -; 340_Soojusläbivus: 0.81; 350_Klaaspakett: 3x klaaspakett, toonitud peegelklaas, pronks; 375_Viimistlus_seest: RAL 9005 (must); 376_Viimistlus_väljast: RAL 9005 (must); 385_Raami_materjal: Alumiiniumprofiil; 900_Tootja: Aluprof; 905_Mudel: MB-104 Passive SI
Type - AR_Aken - 335_Väalispiire: yes; 001_Nimetus: Ak-02; 300_Tüüp: Ak-02; 310_Materjal: Alumiinium; 315_Avanemine: Saksa tüüpi; 320_Klaas: Toonitud peegelklaas, pronks; 325_Helipidavus: 35dB; 330_Tulekindlus: -; 340_Soojusläbivus: 0.81; 350_Klaaspakett: 3x klaaspakett, toonitud peegelklaas, pronks; 375_Viimistlus_seest: RAL 9005 (must); 376_Viimistlus_väljast: RAL 9005 (must); 900_Tootja: Aluprof; 905_Mudel: MB-104 Passive SI
Type - SA_Rippfassaad - 325_Helipidavus: 35dB; 330_Tulekindlus: -; 340_Soojusläbivus: 0.81
Pset_CurtainWallCommon - Reference: Ak-02
Pset_QuantityTakeOff - Reference: Ak-02
AR_Rippfassaad - 003_Elemendi_staadium: Projekteeritud; 345_Päiksekiirgus_tegur: 0.4; 355_Pindala: 9.30357 m2; 390_Paneeli_materjal: Toonitud peegelklaas, pronks
AR_Aken - 003_Elemendi_staadium: Projekteeritud; 345_Paiksekiirgus_tegur: 0.4; 355_Pindala: 9.30357 m2
SA_Rippfassaad - 003_Elemendi_staadium: Projekteeritud; 355_Pindala: 9.30357 m2
Name (Curtain Wall:Ak-02:...) | 305_Ava_kõrgus
10515217 | 1970
10522642 | 1970
10522799 | 1970
10522949 | 1980
10523115 | 1980
10523265 | 1980

# IfcCurtainWall: Curtain Wall:Ak-04 (6)
In: 2. korrus
Type - Pset_ConcreteElementGeneral - FireRating: -
Type - Pset_CurtainWallCommon - IsExternal: yes; AcousticRating: 35dB; FireRating: -; ThermalTransmittance: 0.81 kg/K/s3
Type - Pset_ManufacturerTypeInformation - Manufacturer: Aluprof
Type - AR_Rippfassaad - 335_Välispiire: yes; 001_Nimetus: Ak-04; 300_Tüüp: Ak-04; 305_Ava_mõõt: 5200x1600; 320_Klaas: Toonitud peegelklaas, pronks; 325_Helipidavus: 35dB; 315_Avanemine: Saksa tüüpi; 330_Tulekindlus: -; 340_Soojusläbivus: 0.81; 350_Klaaspakett: 3x klaaspakett, toonitud peegelklaas, pronks; 375_Viimistlus_seest: RAL 9005 (must); 376_Viimistlus_väljast: RAL 9005 (must); 385_Raami_materjal: Alumiiniumprofiil; 900_Tootja: Aluprof; 905_Mudel: MB-104 Passive SI
Type - AR_Aken - 335_Väalispiire: yes; 001_Nimetus: Ak-04; 300_Tüüp: Ak-04; 310_Materjal: Alumiinium; 315_Avanemine: Saksa tüüpi; 320_Klaas: Toonitud peegelklaas, pronks; 325_Helipidavus: 35dB; 330_Tulekindlus: -; 340_Soojusläbivus: 0.81; 350_Klaaspakett: 3x klaaspakett, toonitud peegelklaas, pronks; 375_Viimistlus_seest: RAL 9005 (must); 376_Viimistlus_väljast: RAL 9005 (must); 900_Tootja: Aluprof; 905_Mudel: MB-104 Passive SI
Type - SA_Rippfassaad - 325_Helipidavus: 35dB; 330_Tulekindlus: -; 340_Soojusläbivus: 0.81
Pset_CurtainWallCommon - Reference: Ak-04
Pset_QuantityTakeOff - Reference: Ak-04
AR_Rippfassaad - 003_Elemendi_staadium: Projekteeritud; 345_Päiksekiirgus_tegur: 0.4; 355_Pindala: 7.18946 m2; 390_Paneeli_materjal: Toonitud peegelklaas, pronks
AR_Aken - 003_Elemendi_staadium: Projekteeritud; 345_Paiksekiirgus_tegur: 0.4; 355_Pindala: 7.18946 m2
SA_Rippfassaad - 003_Elemendi_staadium: Projekteeritud; 305_Ava_kõrgus: 1600; 355_Pindala: 7.18946 m2
Name (Curtain Wall:Ak-04:...)
10643986
10644080
10644174
10644268
10644362
10644456

# IfcCurtainWall: Curtain Wall:Ak-05 (10)
In: 1. korrus
Type - Pset_ConcreteElementGeneral - FireRating: -
Type - Pset_CurtainWallCommon - IsExternal: yes; AcousticRating: 35dB; FireRating: -; ThermalTransmittance: 0.81 kg/K/s3
Type - Pset_ManufacturerTypeInformation - Manufacturer: Aluprof
Type - AR_Rippfassaad - 335_Välispiire: yes; 001_Nimetus: Ak-05; 300_Tüüp: Ak-05; 305_Ava_mõõt: 5200x2400; 320_Klaas: Toonitud peegelklaas, pronks; 325_Helipidavus: 35dB; 315_Avanemine: Saksa tüüpi; 330_Tulekindlus: -; 340_Soojusläbivus: 0.81; 350_Klaaspakett: 3x klaaspakett, toonitud peegelklaas, pronks; 375_Viimistlus_seest: RAL 9005 (must); 376_Viimistlus_väljast: RAL 9005 (must); 385_Raami_materjal: Alumiiniumprofiil; 900_Tootja: Aluprof; 905_Mudel: MB-104 Passive SI
Type - AR_Aken - 335_Väalispiire: yes; 001_Nimetus: Ak-05; 300_Tüüp: Ak-05; 310_Materjal: Alumiinium; 315_Avanemine: Saksa tüüpi; 320_Klaas: Toonitud peegelklaas, pronks; 325_Helipidavus: 35dB; 330_Tulekindlus: -; 340_Soojusläbivus: 0.81; 350_Klaaspakett: 3x klaaspakett, toonitud peegelklaas, pronks; 375_Viimistlus_seest: RAL 9005 (must); 376_Viimistlus_väljast: RAL 9005 (must); 900_Tootja: Aluprof; 905_Mudel: MB-104 Passive SI
Type - SA_Rippfassaad - 325_Helipidavus: 35dB; 330_Tulekindlus: -; 340_Soojusläbivus: 0.81
Pset_CurtainWallCommon - Reference: Ak-05
Pset_QuantityTakeOff - Reference: Ak-05
AR_Rippfassaad - 003_Elemendi_staadium: Projekteeritud; 345_Päiksekiirgus_tegur: 0.4; 355_Pindala: 11.3812 m2; 390_Paneeli_materjal: Toonitud peegelklaas, pronks
AR_Aken - 003_Elemendi_staadium: Projekteeritud; 345_Paiksekiirgus_tegur: 0.4; 355_Pindala: 11.3812 m2
SA_Rippfassaad - 003_Elemendi_staadium: Projekteeritud; 305_Ava_kõrgus: 2400; 355_Pindala: 11.3812 m2
Name (Curtain Wall:Ak-05:...)
10532932
10533040
10533148
10533256
10533364
10533472
10533580
10533796
10533904
10534012

# IfcCurtainWall: Curtain Wall:Ak-05*, Curtain Wall:Ak-05*:10533688
In: 1. korrus
Type - Pset_ConcreteElementGeneral - FireRating: -
Type - Pset_CurtainWallCommon - IsExternal: yes; AcousticRating: 35dB; FireRating: -; ThermalTransmittance: 0.81 kg/K/s3
Type - Pset_ManufacturerTypeInformation - Manufacturer: Aluprof
Type - AR_Rippfassaad - 335_Välispiire: yes; 001_Nimetus: Ak-05*; 300_Tüüp: Ak-05; 305_Ava_mõõt: 5200x2400; 320_Klaas: Toonitud peegelklaas, pronks; 325_Helipidavus: 35dB; 315_Avanemine: Saksa tüüpi; 330_Tulekindlus: -; 340_Soojusläbivus: 0.81; 350_Klaaspakett: 3x klaaspakett, toonitud peegelklaas, pronks; 375_Viimistlus_seest: RAL 9005 (must); 376_Viimistlus_väljast: RAL 9005 (must); 385_Raami_materjal: Alumiiniumprofiil; 900_Tootja: Aluprof; 905_Mudel: MB-104 Passive SI
Type - AR_Aken - 335_Väalispiire: yes; 001_Nimetus: Ak-05*; 300_Tüüp: Ak-05; 310_Materjal: Alumiinium; 315_Avanemine: Saksa tüüpi; 320_Klaas: Toonitud peegelklaas, pronks; 325_Helipidavus: 35dB; 330_Tulekindlus: -; 340_Soojusläbivus: 0.81; 350_Klaaspakett: 3x klaaspakett, toonitud peegelklaas, pronks; 375_Viimistlus_seest: RAL 9005 (must); 376_Viimistlus_väljast: RAL 9005 (must); 900_Tootja: Aluprof; 905_Mudel: MB-104 Passive SI
Type - SA_Rippfassaad - 325_Helipidavus: 35dB; 330_Tulekindlus: -; 340_Soojusläbivus: 0.81
Pset_CurtainWallCommon - Reference: Ak-05*
Pset_QuantityTakeOff - Reference: Ak-05*
AR_Rippfassaad - 003_Elemendi_staadium: Projekteeritud; 345_Päiksekiirgus_tegur: 0.4; 355_Pindala: 11.3812 m2; 390_Paneeli_materjal: Toonitud peegelklaas, pronks
AR_Aken - 003_Elemendi_staadium: Projekteeritud; 345_Paiksekiirgus_tegur: 0.4; 355_Pindala: 11.3812 m2
SA_Rippfassaad - 003_Elemendi_staadium: Projekteeritud; 305_Ava_kõrgus: 2400; 355_Pindala: 11.3812 m2

# IfcCurtainWall: Curtain Wall:VLS Klaasvahesein profiilita 38db (19)
Type - Pset_ConcreteElementGeneral - FireRating: -
Type - Pset_CurtainWallCommon - IsExternal: no; ThermalTransmittance: 0 kg/K/s3; AcousticRating: 36dB; FireRating: -
Type - Pset_ManufacturerTypeInformation - Manufacturer: Structo
Type - AR_Rippfassaad - 000_Muinsuskaitse: no; 335_Välispiire: no; 340_Soojusläbivus: 0; 001_Nimetus: VLS Klaasvahesein profiilita 38db; 300_Tüüp: vt. SA infosisu sakki; 325_Helipidavus: 36dB; 330_Tulekindlus: -; 376_Viimistlus_väljast: -; 385_Raami_materjal: vt. SA infosisu sakki; 900_Tootja: Structo; 905_Mudel: vt. SA infosisu sakki
Type - AR_Aken - 000_Muinsuskaitse: no; 340_Soojusläbivus: 0; 001_Nimetus: VLS Klaasvahesein profiilita 38db; 300_Tüüp: vt. SA infosisu sakki; 325_Helipidavus: 36dB; 330_Tulekindlus: -; 335_Väalispiire: no; 376_Viimistlus_väljast: -; 900_Tootja: Structo; 905_Mudel: vt. SA infosisu sakki
Type - SA_Rippfassaad - 000_Muinsuskaitse: no; 340_Soojusläbivus: 0; 325_Helipidavus: 36dB; 330_Tulekindlus: -
Pset_CurtainWallCommon - Reference: VLS Klaasvahesein profiilita 38db
Pset_QuantityTakeOff - Reference: VLS Klaasvahesein profiilita 38db
AR_Rippfassaad - 003_Elemendi_staadium: Projekteeritud; 390_Paneeli_materjal: vt. SA infosisu sakki
AR_Aken - 003_Elemendi_staadium: Projekteeritud
SA_Rippfassaad - 003_Elemendi_staadium: Projekteeritud; 900_Tootja: Structo
Name (Curtain Wall:VLS Klaasvahesein profiilita 38db:...) | In | AR_Rippfassaad, 355_Pindala (m2) = AR_Aken, 355_Pindala (m2) = SA_Rippfassaad, 355_Pindala (m2) | 001_Nimetus | 300_Tuup | 305_Ava_kõrgus | 320_Klaas | 385_Raami_materjal | 905_Mudel
2388849 | 1. korrus | 12.504 | Klaasvahesein uksega | KLVS011 | 2400 | Kirgas lamineeritud klaas 12mm osaliselt kiletatud. Kile: Solyx SimGlas SXJ-0547 Feather Gradient- hajuva (gradient) efektiga- täismatist kirkaks. Klaasi alumine osa kaetud täismatt kilega, hajuv osa alates kõrgusest 1600mm, ülemine osa kirgas. Lahendusest teha näidis ühel tüüpsel klaasseinal ning kinnitada tellijaga. | Raam ja muud lisaelemendid pulbervärvitud RAL 9010 (valge) | Klaasvahesein Glassline 30 (250mm laiune küljepaneel ukse kõrval, kui on liitumine uksega)
2388858 | 1. korrus | 14.7816 | Klaasvahesein uksega | KLVS012 | 2400 | Kirgas lamineeritud klaas 12mm osaliselt kiletatud. Kile: Solyx SimGlas SXJ-0547 Feather Gradient- hajuva (gradient) efektiga- täismatist kirkaks. Klaasi alumine osa kaetud täismatt kilega, hajuv osa alates kõrgusest 1600mm, ülemine osa kirgas. Lahendusest teha näidis ühel tüüpsel klaasseinal ning kinnitada tellijaga. | Raam ja muud lisaelemendid pulbervärvitud RAL 9010 (valge) | Klaasvahesein Glassline 30 (250mm laiune küljepaneel ukse kõrval, kui on liitumine uksega)
2388972 | 1. korrus | 7.044 | Klaasvahesein | KLVS010 | 2400 | Kirgas lamineeritud klaas 12mm osaliselt kiletatud. Kile: Solyx SimGlas SXJ-0547 Feather Gradient- hajuva (gradient) efektiga- täismatist kirkaks. Klaasi alumine osa kaetud täismatt kilega, hajuv osa alates kõrgusest 1600mm, ülemine osa kirgas. Lahendusest teha näidis ühel tüüpsel klaasseinal ning kinnitada tellijaga. | Raam pulbervärvitud RAL 9010 (valge) | Klaasvahesein Glassline 30
3977816 | 1. korrus | 12.5039 | Klaasvahesein uksega | KLVS002 | 2400 | Kirgas lamineeritud klaas 12mm | Raam ja muud lisaelemendid pulbervärvitud RAL 9010 (valge) | Klaasvahesein Glassline 30 (250mm laiune küljepaneel ukse kõrval, kui on liitumine uksega)
3977823 | 1. korrus | 12.504 | Klaasvahesein uksega | KLVS007 | 2400 | Kirgas lamineeritud klaas 12mm | Raam ja muud lisaelemendid pulbervärvitud RAL 9010 (valge) | Klaasvahesein Glassline 30 (250mm laiune küljepaneel ukse kõrval, kui on liitumine uksega)
6869705 | 1. korrus | 6.24 | Klaasvahesein | KLVS267 | 2400 | Kirgas lamineeritud klaas 12mm osaliselt kiletatud. Kile: Solyx SimGlas SXJ-0547 Feather Gradient- hajuva (gradient) efektiga- täismatist kirkaks. Klaasi alumine osa kaetud täismatt kilega, hajuv osa alates kõrgusest 1600mm, ülemine osa kirgas. Lahendusest teha näidis ühel tüüpsel klaasseinal ning kinnitada tellijaga. | Raam pulbervärvitud RAL 9010 (valge) | Klaasvahesein Glassline 30
6869783 | 1. korrus | 12.4212 | Klaasvahesein | KLVS017 | 2400 | Kirgas lamineeritud klaas 12mm osaliselt kiletatud. Kile: Solyx SimGlas SXJ-0547 Feather Gradient- hajuva (gradient) efektiga- täismatist kirkaks. Klaasi alumine osa kaetud täismatt kilega, hajuv osa alates kõrgusest 1600mm, ülemine osa kirgas. Lahendusest teha näidis ühel tüüpsel klaasseinal ning kinnitada tellijaga. | Raam pulbervärvitud RAL 9010 (valge) | Klaasvahesein Glassline 30
6965720 | 2. korrus | 13.68 | Klaasvahesein | KLVS033-1 | 2400 | Kirgas lamineeritud klaas 12mm osaliselt kiletatud. Kile: Solyx SimGlas SXJ-0547 Feather Gradient- hajuva (gradient) efektiga- täismatist kirkaks. Klaasi alumine osa kaetud täismatt kilega, hajuv osa alates kõrgusest 1600mm, ülemine osa kirgas. Lahendusest teha näidis ühel tüüpsel klaasseinal ning kinnitada tellijaga. | Raam pulbervärvitud RAL 9010 (valge) | Klaasvahesein Glassline 30 (250mm laiune küljepaneel ukse kõrval, kui on liitumine uksega)
10323830 | 2. korrus | 5.2212 | Klaasvahesein | KLVS030 | 2400 | Kirgas lamineeritud klaas 12mm osaliselt kiletatud. Kile: Solyx SimGlas SXJ-0547 Feather Gradient- hajuva (gradient) efektiga- täismatist kirkaks. Klaasi alumine osa kaetud täismatt kilega, hajuv osa alates kõrgusest 1600mm, ülemine osa kirgas. Lahendusest teha näidis ühel tüüpsel klaasseinal ning kinnitada tellijaga. | Raam pulbervärvitud RAL 9010 (valge) | Klaasvahesein Glassline 30 (250mm laiune küljepaneel ukse kõrval, kui on liitumine uksega)
10323844 | 2. korrus | 6.0606 | Klaasvahesein | KLVS031 | 2400 | Kirgas lamineeritud klaas 12mm osaliselt kiletatud. Kile: Solyx SimGlas SXJ-0547 Feather Gradient- hajuva (gradient) efektiga- täismatist kirkaks. Klaasi alumine osa kaetud täismatt kilega, hajuv osa alates kõrgusest 1600mm, ülemine osa kirgas. Lahendusest teha näidis ühel tüüpsel klaasseinal ning kinnitada tellijaga. | Raam pulbervärvitud RAL 9010 (valge) | Klaasvahesein Glassline 30 (250mm laiune küljepaneel ukse kõrval, kui on liitumine uksega)
10323858 | 2. korrus | 12.4212 | Klaasvahesein | KLVS029 | 2400 | Kirgas lamineeritud klaas 12mm osaliselt kiletatud. Kile: Solyx SimGlas SXJ-0547 Feather Gradient- hajuva (gradient) efektiga- täismatist kirkaks. Klaasi alumine osa kaetud täismatt kilega, hajuv osa alates kõrgusest 1600mm, ülemine osa kirgas. Lahendusest teha näidis ühel tüüpsel klaasseinal ning kinnitada tellijaga. | Raam pulbervärvitud RAL 9010 (valge) | Klaasvahesein Glassline 30 (250mm laiune küljepaneel ukse kõrval, kui on liitumine uksega)
10323882 | 2. korrus | 5.3172 | Klaasvahesein | KLVS036 | 2400 | Kirgas lamineeritud klaas 12mm osaliselt kiletatud. Kile: Solyx SimGlas SXJ-0547 Feather Gradient- hajuva (gradient) efektiga- täismatist kirkaks. Klaasi alumine osa kaetud täismatt kilega, hajuv osa alates kõrgusest 1600mm, ülemine osa kirgas. Lahendusest teha näidis ühel tüüpsel klaasseinal ning kinnitada tellijaga. | Raam pulbervärvitud RAL 9010 (valge) | Klaasvahesein Glassline 30 (250mm laiune küljepaneel ukse kõrval, kui on liitumine uksega)
10323896 | 2. korrus | 6.24 | Klaasvahesein | KLVS037 | 2400 | Kirgas lamineeritud klaas 12mm osaliselt kiletatud. Kile: Solyx SimGlas SXJ-0547 Feather Gradient- hajuva (gradient) efektiga- täismatist kirkaks. Klaasi alumine osa kaetud täismatt kilega, hajuv osa alates kõrgusest 1600mm, ülemine osa kirgas. Lahendusest teha näidis ühel tüüpsel klaasseinal ning kinnitada tellijaga. | Raam pulbervärvitud RAL 9010 (valge) | Klaasvahesein Glassline 30 (250mm laiune küljepaneel ukse kõrval, kui on liitumine uksega)
13277708 | 1. korrus | 3.3325 | Klaasvahesein | KLVS009 | 2150 | Kirgas lamineeritud klaas 12mm osaliselt kiletatud. Kile: Solyx SimGlas SXJ-0547 Feather Gradient- hajuva (gradient) efektiga- täismatist kirkaks. Klaasi alumine osa kaetud täismatt kilega, hajuv osa alates kõrgusest 1600mm, ülemine osa kirgas. Lahendusest teha näidis ühel tüüpsel klaasseinal ning kinnitada tellijaga. | Raam pulbervärvitud RAL 9010 (valge) | Klaasvahesein Glassline 30
13278701 | 1. korrus | 3.3325 | Klaasvahesein uksega | KLVS269 | 2150 | Kirgas lamineeritud klaas 12mm osaliselt kiletatud. Kile: Solyx SimGlas SXJ-0547 Feather Gradient- hajuva (gradient) efektiga- täismatist kirkaks. Klaasi alumine osa kaetud täismatt kilega, hajuv osa alates kõrgusest 1600mm, ülemine osa kirgas. Lahendusest teha näidis ühel tüüpsel klaasseinal ning kinnitada tellijaga. | Raam ja kilp pulbervärvitud RAL 9010 (valge) | Klaasvahesein Glassline 30 (250mm laiune küljepaneel ukse kõrval, kui on liitumine uksega)
13284496 | 1. korrus | 12.3972 | Klaasvahesein | KLVS268 | 2400 | Kirgas lamineeritud klaas 12mm osaliselt kiletatud. Kile: Solyx SimGlas SXJ-0547 Feather Gradient- hajuva (gradient) efektiga- täismatist kirkaks. Klaasi alumine osa kaetud täismatt kilega, hajuv osa alates kõrgusest 1600mm, ülemine osa kirgas. Lahendusest teha näidis ühel tüüpsel klaasseinal ning kinnitada tellijaga. | Raam pulbervärvitud RAL 9010 (valge) | Klaasvahesein Glassline 30
13321292 | 1. korrus | 14.892 | Klaasvahesein | KLVS019 | 2400 | Kirgas lamineeritud klaas 12mm osaliselt kiletatud. Kile: Solyx SimGlas SXJ-0547 Feather Gradient- hajuva (gradient) efektiga- täismatist kirkaks. Klaasi alumine osa kaetud täismatt kilega, hajuv osa alates kõrgusest 1600mm, ülemine osa kirg | Raam pulbervärvitud RAL 9010 (valge) | Klaasvahesein Glassline 30
13918883 | 1. korrus | 5.2212 | Klaasvahesein | KLVS283 | 2400 | Kirgas lamineeritud klaas 12mm osaliselt kiletatud. Kile: Solyx SimGlas SXJ-0547 Feather Gradient- hajuva (gradient) efektiga- täismatist kirkaks. Klaasi alumine osa kaetud täismatt kilega, hajuv osa alates kõrgusest 1600mm, ülemine osa kirgas. Lahendusest teha näidis ühel tüüpsel klaasseinal ning kinnitada tellijaga. | Raam pulbervärvitud RAL 9010 (valge) | Klaasvahesein Glassline 30
13918990 | 1. korrus | 6.24 | Klaasvahesein uksega | KLVS284 | 2400 | Kirgas lamineeritud klaas 12mm osaliselt kiletatud. Kile: Solyx SimGlas SXJ-0547 Feather Gradient- hajuva (gradient) efektiga- täismatist kirkaks. Klaasi alumine osa kaetud täismatt kilega, hajuv osa alates kõrgusest 1600mm, ülemine osa kirgas. Lahendusest teha näidis ühel tüüpsel klaasseinal ning kinnitada tellijaga. | Raam pulbervärvitud RAL 9010 (valge), ukse kõrvale jääv kilp spoonitud uksega sama spooniga | Klaasvahesein Glassline 30 (250mm laiune küljepaneel ukse kõrval, kui on liitumine uksega)

# IfcCurtainWall: Curtain Wall:VLS avatäide profiilita klaas, Curtain Wall:VLS avatäide profiilita klaas:10323825
In: 2. korrus
Type - Pset_ConcreteElementGeneral - FireRating: -
Type - Pset_CurtainWallCommon - IsExternal: no; ThermalTransmittance: 0 kg/K/s3; AcousticRating: 36dB; FireRating: -
Type - Pset_ManufacturerTypeInformation - Manufacturer: vt. SA infosisu sakki
Type - AR_Rippfassaad - 000_Muinsuskaitse: no; 335_Välispiire: no; 340_Soojusläbivus: 0; 001_Nimetus: VLS avatäide profiilita klaas; 300_Tüüp: vt. SA infosisu sakki; 325_Helipidavus: 36dB; 330_Tulekindlus: -; 376_Viimistlus_väljast: -; 385_Raami_materjal: vt. SA infosisu sakki; 900_Tootja: vt. SA infosisu sakki; 905_Mudel: vt. SA infosisu sakki
Type - AR_Aken - 000_Muinsuskaitse: no; 340_Soojusläbivus: 0; 335_Väalispiire: no; 001_Nimetus: VLS avatäide profiilita klaas; 300_Tüüp: vt. SA infosisu sakki; 325_Helipidavus: 36dB; 330_Tulekindlus: -; 376_Viimistlus_väljast: -; 900_Tootja: vt. SA infosisu sakki; 905_Mudel: vt. SA infosisu sakki
Type - SA_Rippfassaad - 000_Muinsuskaitse: no; 340_Soojusläbivus: 0; 325_Helipidavus: 36dB; 330_Tulekindlus: -
Pset_CurtainWallCommon - Reference: VLS avatäide profiilita klaas
Pset_QuantityTakeOff - Reference: VLS avatäide profiilita klaas
AR_Rippfassaad - 003_Elemendi_staadium: Projekteeritud; 355_Pindala: 0.5846 m2; 390_Paneeli_materjal: vt. SA infosisu sakki
AR_Aken - 003_Elemendi_staadium: Projekteeritud; 355_Pindala: 0.5846 m2
SA_Rippfassaad - 001_Nimetus: Klaasvahesein; 003_Elemendi_staadium: Projekteeritud; 300_Tuup: KLVS033-2; 305_Ava_kõrgus: 1580; 320_Klaas: Kirgas lamineeritud klaas 12mm; 355_Pindala: 0.5846 m2; 385_Raami_materjal: Raam pulbervärvitud RAL 9010 (valge); 900_Tootja: Structo; 905_Mudel: Klaasvahesein Glassline 30

# IfcCurtainWall: Curtain Wall:ol. olev HTKK klaassein - klaasvalu (17)
Type - Pset_ConcreteElementGeneral - FireRating: -
Type - Pset_CurtainWallCommon - IsExternal: no; AcousticRating: 30dB; FireRating: -
Type - AR_Rippfassaad - 000_Muinsuskaitse: yes; 001_Nimetus: ol. olev HTKK klaassein - klaasvalu; 325_Helipidavus: 30dB; 330_Tulekindlus: -
Type - AR_Aken - 000_Muinsuskaitse: yes; 001_Nimetus: ol. olev HTKK klaassein - klaasvalu; 325_Helipidavus: 30dB; 330_Tulekindlus: -
Type - SA_Rippfassaad - 000_Muinsuskaitse: yes; 325_Helipidavus: 30dB; 330_Tulekindlus: -
Pset_CurtainWallCommon - Reference: ol. olev HTKK klaassein - klaasvalu
Pset_QuantityTakeOff - Reference: ol. olev HTKK klaassein - klaasvalu
Name (Curtain Wall:ol. olev HTKK klaassein - klaasvalu:...) | In
12837720 | 4. korrus
12839558 | 5. korrus
13032404 | 3. korrus
13032406 | 3. korrus
13032412 | 3. korrus
13202542 | 3. korrus
13202544 | 3. korrus
13204377 | 3. korrus
13204379 | 3. korrus
13385538 | 4. korrus
13386205 | 4. korrus
13394425 | 5. korrus
13395278 | 5. korrus
13395359 | 5. korrus
13395583 | 5. korrus
13395589 | 5. korrus
13395595 | 5. korrus

# IfcCurtainWall: Curtain Wall:ol. olev MK vent. rest (5)
Type - Pset_CurtainWallCommon - IsExternal: yes
Type - AR_Rippfassaad - 000_Muinsuskaitse: yes; 335_Välispiire: yes; 001_Nimetus: ol. olev MK vent. rest; 300_Tüüp: Ol-VR-MK; 376_Viimistlus_väljast: Pulbervärvitud RAL9005 (must)
Type - AR_Aken - 000_Muinsuskaitse: yes; 001_Nimetus: ol. olev MK vent. rest; 300_Tüüp: Ol-VR-MK; 310_Materjal: Demonteerida, restureerida, puhastada roostest, kruntida ja pulbervärvida. Vt. täpsemalt märkusi.; 335_Väalispiire: yes; 376_Viimistlus_väljast: Pulbervärvitud RAL9005 (must)
Type - SA_Rippfassaad - 000_Muinsuskaitse: yes
Pset_CurtainWallCommon - Reference: ol. olev MK vent. rest
Pset_QuantityTakeOff - Reference: ol. olev MK vent. rest
Name (Curtain Wall:ol. olev MK vent. rest:...) | In
4455516 | 1. korrus | AR_Rippfassaad - 003_Elemendi_staadium: Olemasolev; 355_Pindala: 2.88911 m2; sets with these values: 2; SA_Rippfassaad - 001_Nimetus: Ol-VR-MK; 003_Elemendi_staadium: Olemasolev; 300_Tuup: ol. olev VR; 305_Ava_kõrgus: 953; 355_Pindala: 2.88911 m2
4455566 | 1. korrus | AR_Rippfassaad - 003_Elemendi_staadium: Olemasolev; 355_Pindala: 2.88911 m2; sets with these values: 2; SA_Rippfassaad - 001_Nimetus: Ol-VR-MK; 003_Elemendi_staadium: Olemasolev; 300_Tuup: ol. olev VR; 305_Ava_kõrgus: 953; 355_Pindala: 2.88911 m2
14176897 | -1. korrus
14176899 | 1. korrus
16565838 | 1. korrus

# IfcDiscreteAccessory: 3K aste terrassile3:3K aste terrassile3, 3K aste terrassile3:3K aste terrassile3:12826677
In: 3. korrus
Type - Material: Default Floor
Type - AR - 000_Muinsuskaitse: no; 335_Välispiire: no; 001_Nimetus: 3K aste terrassile3; 205_Tüüp: vt SA osa
Pset_QuantityTakeOff - Reference: 3K aste terrassile3

# IfcDiscreteAccessory: 3K aste terrassile4:3K aste terrassile4, 3K aste terrassile4:3K aste terrassile4:12826701
In: 3. korrus
Type - Material: Default Floor
Type - AR - 000_Muinsuskaitse: no; 335_Välispiire: no; 001_Nimetus: 3K aste terrassile4; 205_Tüüp: vt SA osa
Pset_QuantityTakeOff - Reference: 3K aste terrassile4

# IfcDiscreteAccessory: 3K aste terrassile5:3K aste terrassile4, 3K aste terrassile5:3K aste terrassile4:15525525
In: 3. korrus
Type - Material: Default Floor
Type - AR - 000_Muinsuskaitse: no; 335_Välispiire: no; 001_Nimetus: 3K aste terrassile4; 205_Tüüp: vt SA osa
Pset_QuantityTakeOff - Reference: 3K aste terrassile4

# IfcDiscreteAccessory: 3K aste terrassile8:3K aste terrassile3, 3K aste terrassile8:3K aste terrassile3:15527489
In: 3. korrus
Type - Material: Default Floor
Type - AR - 000_Muinsuskaitse: no; 335_Välispiire: no; 001_Nimetus: 3K aste terrassile3; 205_Tüüp: vt SA osa
Pset_QuantityTakeOff - Reference: 3K aste terrassile3

# IfcDiscreteAccessory: 3K astme laiendus terrassile4:3K astmelaiendus terrassile4, 3K astme laiendus terrassile4:3K astmelaiendus terrassile4:12826713
In: 3. korrus
Type - Material: Default Floor
Type - AR - 000_Muinsuskaitse: no; 335_Välispiire: no; 001_Nimetus: 3K astmelaiendus terrassile4; 205_Tüüp: vt SA osa
Pset_QuantityTakeOff - Reference: 3K astmelaiendus terrassile4

# IfcDiscreteAccessory: 3K astmelaiendus terrassile3:3K astmelaiendus terrassile3, 3K astmelaiendus terrassile3:3K astmelaiendus terrassile3:12826689
In: 3. korrus
Type - Material: Default Floor
Type - AR - 000_Muinsuskaitse: no; 335_Välispiire: no; 001_Nimetus: 3K astmelaiendus terrassile3; 205_Tüüp: vt SA osa
Pset_QuantityTakeOff - Reference: 3K astmelaiendus terrassile3

# IfcDiscreteAccessory: F-korpuse kanali kate:Süvendi rest 01, F-korpuse kanali kate:Süvendi rest 01:13171964
In: 1. korrus
Type - Material: Viimistlus. Rest.
Type - AR - 000_Muinsuskaitse: no; 001_Nimetus: Süvendi rest 01
Pset_QuantityTakeOff - Reference: Süvendi rest 01

# IfcDiscreteAccessory: Jalapuhastusrest 8:JPR-01, Jalapuhastusrest 8:JPR-01:12752808
In: E-korpus 2. korrus
Type - Material: EST. Metall. Alumiinium. Värvitud.
Type - AR - 000_Muinsuskaitse: no; 335_Välispiire: yes; 001_Nimetus: JPR-01; 205_Tüüp: JPR-01; 455_Eriomadused: 500x1000mm; 130_Pikkus: 500x1000mm; 220_Viimistlus: Kuumtsingitud terasrest viimistlus, restisilm 9x31mm.; 310_Materjal: Polümeerbetoonist alusvann koos kuumtsingitud terasest raamiga. Fikseeritult, sulguriga, sifooniga,paigaldada tõstetudpõranda süsteemile, terrassitasapinnaga tasa. Toode Aco Self Vario
Pset_QuantityTakeOff - Reference: JPR-01

# IfcDiscreteAccessory: katuseredel11:R-01, katuseredel11:R-01:6543879
In: 3. korrus
Type - Material: EST. Metall. Teras. RAL9005
Type - Pset_ManufacturerTypeInformation - Manufacturer: -
Type - AR - 000_Muinsuskaitse: no; 335_Välispiire: yes; 001_Nimetus: R-01; 205_Tüüp: R-01; 455_Eriomadused: 2000mm; 130_Pikkus: 2000mm; 220_Viimistlus: RAL9005 (must); 310_Materjal: Metall, Pural kattega, pulbervärvitud; 900_Tootja: -; 905_Mudel: -
Pset_QuantityTakeOff - Reference: R-01

# IfcDoor: 1-poolne, klaasseina uks:Metallprofiiluks 01, 1-poolne, klaasseina uks:Metallprofiiluks 01:3977824
In: 1. korrus
Type - OperationType: SINGLE_SWING_LEFT; ParameterTakesPrecedence: no; Sizeable: no; Classification: B2030100 Uniformat (Uniformat); Material: EST. Klaas. 1x. E-korpus, EST.Alumiinium.RAL9005
Type - 1-poolne, klaasseina uks:Metallprofiiluks 01:3977824:1 - PanelOperation: SWINGING
Type - Pset_ConcreteElementGeneral - FireRating: -
Type - Pset_DoorCommon - IsExternal: no; ThermalTransmittance: 0 kg/K/s3; SelfClosing: no; FireExit: yes; FireRating: -; AcousticRating: 36dB
Type - AR_Uks - 000_Muinsuskaitse: no; 335_Välispiire: no; 340_Soojusläbivus: 0; 365_Isesulguv: no; 370_Evakuatsiooniväljapääs: yes; 001_Nimetus: Metallprofiiluks 01; 300_Tüüp: vt. SA infosisu sakki; 310_Materjal: Alumiiniumprofiil klaasuks; 320_Klaas: vt. SA infosisu sakki; 325_Helipidavus: 36dB; 330_Tulekindlus: -; 350_Klaaspakett: 12mm karastatud ja lamineeritud klaas vastavalt tootele; 375_Viimistlus_seest: vt. SA infosisu sakki; 376_Viimistlus_väljast: vt. SA infosisu sakki
Type - SA_Uks - 000_Muinsuskaitse: no; 335_Välispiire: no; 340_Soojusläbivus: 0; 365_Isesulguv: no; 370_Evakuatsiooniväljapääs: yes; 310_Materjal: Alumiiniumprofiil klaasuks; 325_Helipidavus: 36dB; 330_Tulekindlus: -; 350_Klaaspakett: 12mm karastatud ja lamineeritud klaas vastavalt tootele
OverallHeight: 2400 mm; OverallWidth: 1000 mm
Pset_DoorCommon - Reference: Metallprofiiluks 01; HandicapAccessible: yes
Pset_QuantityTakeOff - Reference: Metallprofiiluks 01
AR_Uks - 360_Ratastooliga: yes; 003_Elemendi_staadium: Projekteeritud; 305_Ava_mõõt_laius: 1000 mm; 305_Ava_mõõt_korgus: 2400 mm; 315_Avanemine: parem; 355_Pindala: 2.4 m2; 380_Lukustus: Vt. lukustuse projekti!; 455_Eriomadused: Üks uks kahepoolse ukse komplektist- vt. põhiplaane! Uks liitub klaasseina ja tumma kilbiga 250mm (ruumilülititele, kaardilugejale vms)- Vt. lisaks klaasvaheseinte loendit!
SA_Uks - 360_Ratastooliga: yes; 001_Nimetus: Alumiiniumprofiilis klaasuks klaasseina osana (üks pool kahepoolsest uksest); 003_Elemendi_staadium: Projekteeritud; 004_Lävepakk: Laskuv lävepakk; 005_Furnituur: Ukselink: VAL32.544010_NIS, viimistlus: harjatud RST. Hinged: Structo Pivot peithing.; 300_Tüüp: SRR0527; 305_Ava_laius: 1000 mm; 305_Ava_kõrgus: 2400 mm; 315_Avanemine: parem; 320_Klaas: Kirgas klaas; 355_Pindala: 2.4 m2; 375_Viimistlus_seest: Raam pulbervärvitud RAL 9010 (valge); 380_Lukustus: Vt. lukustuse projekti!; 900_Tootja: Structo; 905_Mudel: Porta-53G Aluslim 12 raamitud täisklaasuks (üks uks kahepoolse ukse komplektist)
BaseQuantities - Height: 2400 mm; Width: 1000 mm; Area: 2.4 m2

# IfcDoor: 1-poolne, klaasseina uks:Metallprofiiluks 01, 1-poolne, klaasseina uks:Metallprofiiluks 01:7887686
In: 1. korrus
Type - OperationType: SINGLE_SWING_LEFT; ParameterTakesPrecedence: no; Sizeable: no; Classification: B2030100 Uniformat (Uniformat); Material: EST. Klaas. 1x. E-korpus, EST.Alumiinium.RAL9005
Type - 1-poolne, klaasseina uks:Metallprofiiluks 01:7887686:1 - PanelOperation: SWINGING
Type - Pset_ConcreteElementGeneral - FireRating: -
Type - Pset_DoorCommon - IsExternal: no; ThermalTransmittance: 0 kg/K/s3; SelfClosing: no; FireExit: yes; FireRating: -; AcousticRating: 36dB
Type - AR_Uks - 000_Muinsuskaitse: no; 335_Välispiire: no; 340_Soojusläbivus: 0; 365_Isesulguv: no; 370_Evakuatsiooniväljapääs: yes; 001_Nimetus: Metallprofiiluks 01; 300_Tüüp: vt. SA infosisu sakki; 310_Materjal: Alumiiniumprofiil klaasuks; 320_Klaas: vt. SA infosisu sakki; 325_Helipidavus: 36dB; 330_Tulekindlus: -; 350_Klaaspakett: 12mm karastatud ja lamineeritud klaas vastavalt tootele; 375_Viimistlus_seest: vt. SA infosisu sakki; 376_Viimistlus_väljast: vt. SA infosisu sakki
Type - SA_Uks - 000_Muinsuskaitse: no; 335_Välispiire: no; 340_Soojusläbivus: 0; 365_Isesulguv: no; 370_Evakuatsiooniväljapääs: yes; 310_Materjal: Alumiiniumprofiil klaasuks; 325_Helipidavus: 36dB; 330_Tulekindlus: -; 350_Klaaspakett: 12mm karastatud ja lamineeritud klaas vastavalt tootele
OverallHeight: 2400 mm; OverallWidth: 1100 mm
Pset_DoorCommon - Reference: Metallprofiiluks 01; HandicapAccessible: yes
Pset_QuantityTakeOff - Reference: Metallprofiiluks 01
AR_Uks - 003_Elemendi_staadium: Projekteeritud; 305_Ava_mõõt_laius: 1100 mm; 305_Ava_mõõt_korgus: 2400 mm; 315_Avanemine: parem; 355_Pindala: 2.64 m2; 360_Ratastooliga: yes; 380_Lukustus: Vt. lukustuse projekti!; 455_Eriomadused: Üks uks kahepoolse ukse komplektist- vt. põhiplaane! Uks liitub klaasseina ja tumma kilbiga 350mm (ruumilülititele, kaardilugejale vms)- Vt. lisaks klaasvaheseinte loendit!
SA_Uks - 360_Ratastooliga: yes; 001_Nimetus: Metallprofiiluks klaasseina osana (üks pool kahepoolsest uksest); 003_Elemendi_staadium: Projekteeritud; 004_Lävepakk: Laskuv lävepakk; 005_Furnituur: Ukselink: VAL32.544010_NIS, viimistlus: harjatud RST. Hinged: vastavalt tootele, toon sama mis lengil.; 300_Tüüp: SRR0753; 305_Ava_laius: 1100 mm; 305_Ava_kõrgus: 2400 mm; 315_Avanemine: parem; 320_Klaas: Kirgas klaas; 355_Pindala: 2.64 m2; 375_Viimistlus_seest: Raam pulbervärvitud RAL 9010 (valge); 380_Lukustus: Vt. lukustuse projekti!; 900_Tootja: Structo; 905_Mudel: Porta-53G Aluslim 12 raamitud täisklaasuks (üks uks kahepoolse ukse komplektist)
BaseQuantities - Height: 2400 mm; Width: 1100 mm; Area: 2.64 m2

# IfcDoor: 1-poolne, klaasseina uks:Metallprofiiluks 01, 1-poolne, klaasseina uks:Metallprofiiluks 01:7887748
In: 1. korrus
Type - OperationType: SINGLE_SWING_LEFT; ParameterTakesPrecedence: no; Sizeable: no; Classification: B2030100 Uniformat (Uniformat); Material: EST. Klaas. 1x. E-korpus, EST.Alumiinium.RAL9005
Type - 1-poolne, klaasseina uks:Metallprofiiluks 01:7887748:1 - PanelOperation: SWINGING
Type - Pset_ConcreteElementGeneral - FireRating: -
Type - Pset_DoorCommon - IsExternal: no; ThermalTransmittance: 0 kg/K/s3; SelfClosing: no; FireExit: yes; FireRating: -; AcousticRating: 36dB
Type - AR_Uks - 000_Muinsuskaitse: no; 335_Välispiire: no; 340_Soojusläbivus: 0; 365_Isesulguv: no; 370_Evakuatsiooniväljapääs: yes; 001_Nimetus: Metallprofiiluks 01; 300_Tüüp: vt. SA infosisu sakki; 310_Materjal: Alumiiniumprofiil klaasuks; 320_Klaas: vt. SA infosisu sakki; 325_Helipidavus: 36dB; 330_Tulekindlus: -; 350_Klaaspakett: 12mm karastatud ja lamineeritud klaas vastavalt tootele; 375_Viimistlus_seest: vt. SA infosisu sakki; 376_Viimistlus_väljast: vt. SA infosisu sakki
Type - SA_Uks - 000_Muinsuskaitse: no; 335_Välispiire: no; 340_Soojusläbivus: 0; 365_Isesulguv: no; 370_Evakuatsiooniväljapääs: yes; 310_Materjal: Alumiiniumprofiil klaasuks; 325_Helipidavus: 36dB; 330_Tulekindlus: -; 350_Klaaspakett: 12mm karastatud ja lamineeritud klaas vastavalt tootele
OverallHeight: 2400 mm; OverallWidth: 900 mm
Pset_DoorCommon - Reference: Metallprofiiluks 01; HandicapAccessible: yes
Pset_QuantityTakeOff - Reference: Metallprofiiluks 01
AR_Uks - 360_Ratastooliga: yes; 003_Elemendi_staadium: Projekteeritud; 305_Ava_mõõt_laius: 900 mm; 305_Ava_mõõt_korgus: 2400 mm; 315_Avanemine: parem; 355_Pindala: 2.16 m2; 380_Lukustus: Vt. lukustuse projekti!; 455_Eriomadused: Üks uks kahepoolse ukse komplektist- vt. põhiplaane! Uks liitub klaasseina ja tumma kilbiga 250mm (ruumilülititele, kaardilugejale vms)- Vt. lisaks klaasvaheseinte loendit!
SA_Uks - 360_Ratastooliga: yes; 001_Nimetus: Alumiiniumprofiilis klaasuks klaasseina osana (üks pool kahepoolsest uksest); 003_Elemendi_staadium: Projekteeritud; 004_Lävepakk: Laskuv lävepakk; 005_Furnituur: Ukselink: VAL32.544010_NIS, viimistlus: harjatud RST. Hinged: Structo Pivot peithing.; 300_Tüüp: SRR0249; 305_Ava_laius: 900 mm; 305_Ava_kõrgus: 2400 mm; 315_Avanemine: parem; 320_Klaas: Kirgas klaas; 355_Pindala: 2.16 m2; 375_Viimistlus_seest: Raam pulbervärvitud RAL 9010 (valge); 380_Lukustus: Vt. lukustuse projekti!; 900_Tootja: Structo; 905_Mudel: Porta-53G Aluslim 12 raamitud täisklaasuks (üks uks kahepoolse ukse komplektist)
BaseQuantities - Height: 2400 mm; Width: 900 mm; Area: 2.16 m2

# IfcDoor: 1-poolne, klaasseina uks:Metallprofiiluks 01, 1-poolne, klaasseina uks:Metallprofiiluks 01:7887688
In: 1. korrus
Type - OperationType: SINGLE_SWING_RIGHT; ParameterTakesPrecedence: no; Sizeable: no; Classification: B2030100 Uniformat (Uniformat); Material: EST. Klaas. 1x. E-korpus, EST.Alumiinium.RAL9005
Type - 1-poolne, klaasseina uks:Metallprofiiluks 01:7887688:1 - PanelOperation: SWINGING
Type - Pset_ConcreteElementGeneral - FireRating: -
Type - Pset_DoorCommon - IsExternal: no; ThermalTransmittance: 0 kg/K/s3; SelfClosing: no; FireExit: yes; FireRating: -; AcousticRating: 36dB
Type - AR_Uks - 000_Muinsuskaitse: no; 335_Välispiire: no; 340_Soojusläbivus: 0; 365_Isesulguv: no; 370_Evakuatsiooniväljapääs: yes; 001_Nimetus: Metallprofiiluks 01; 300_Tüüp: vt. SA infosisu sakki; 310_Materjal: Alumiiniumprofiil klaasuks; 320_Klaas: vt. SA infosisu sakki; 325_Helipidavus: 36dB; 330_Tulekindlus: -; 350_Klaaspakett: 12mm karastatud ja lamineeritud klaas vastavalt tootele; 375_Viimistlus_seest: vt. SA infosisu sakki; 376_Viimistlus_väljast: vt. SA infosisu sakki
Type - SA_Uks - 000_Muinsuskaitse: no; 335_Välispiire: no; 340_Soojusläbivus: 0; 365_Isesulguv: no; 370_Evakuatsiooniväljapääs: yes; 310_Materjal: Alumiiniumprofiil klaasuks; 325_Helipidavus: 36dB; 330_Tulekindlus: -; 350_Klaaspakett: 12mm karastatud ja lamineeritud klaas vastavalt tootele
OverallHeight: 2400 mm; OverallWidth: 1100 mm
Pset_DoorCommon - Reference: Metallprofiiluks 01; HandicapAccessible: yes
Pset_QuantityTakeOff - Reference: Metallprofiiluks 01
AR_Uks - 360_Ratastooliga: yes; 003_Elemendi_staadium: Projekteeritud; 305_Ava_mõõt_laius: 1100 mm; 305_Ava_mõõt_korgus: 2400 mm; 315_Avanemine: vasak; 355_Pindala: 2.64 m2; 380_Lukustus: Vt. lukustuse projekti!; 455_Eriomadused: Üks uks kahepoolse ukse komplektist- vt. põhiplaane! Uks liitub klaasseina ja tumma kilbiga 250mm (ruumilülititele, kaardilugejale vms)- Vt. lisaks klaasvaheseinte loendit! Mitteaaktiivne ukseleht varustada kiirriiviga.
SA_Uks - 360_Ratastooliga: yes; 001_Nimetus: Metallprofiiluks klaasseina osana (üks pool kahepoolsest uksest); 003_Elemendi_staadium: Projekteeritud; 004_Lävepakk: Laskuv lävepakk; 005_Furnituur: Ukselink: VAL32.544010_NIS, viimistlus: harjatud RST. Hinged: vastavalt tootele, toon sama mis lengil.; 300_Tüüp: SRR0752; 305_Ava_laius: 1100 mm; 305_Ava_kõrgus: 2400 mm; 315_Avanemine: vasak; 320_Klaas: Kirgas klaas; 355_Pindala: 2.64 m2; 375_Viimistlus_seest: Raam pulbervärvitud RAL 9010 (valge); 380_Lukustus: Vt. lukustuse projekti!; 900_Tootja: Structo; 905_Mudel: Porta-53G Aluslim 12 raamitud täisklaasuks (üks uks kahepoolse ukse komplektist)
BaseQuantities - Height: 2400 mm; Width: 1100 mm; Area: 2.64 m2

# IfcDoor: 1-poolne, klaasseina uks:Metallprofiiluks 01, 1-poolne, klaasseina uks:Metallprofiiluks 01:7887746
In: 1. korrus
Type - OperationType: SINGLE_SWING_RIGHT; ParameterTakesPrecedence: no; Sizeable: no; Classification: B2030100 Uniformat (Uniformat); Material: EST. Klaas. 1x. E-korpus, EST.Alumiinium.RAL9005
Type - 1-poolne, klaasseina uks:Metallprofiiluks 01:7887746:1 - PanelOperation: SWINGING
Type - Pset_ConcreteElementGeneral - FireRating: -
Type - Pset_DoorCommon - IsExternal: no; ThermalTransmittance: 0 kg/K/s3; SelfClosing: no; FireExit: yes; FireRating: -; AcousticRating: 36dB
Type - AR_Uks - 000_Muinsuskaitse: no; 335_Välispiire: no; 340_Soojusläbivus: 0; 365_Isesulguv: no; 370_Evakuatsiooniväljapääs: yes; 001_Nimetus: Metallprofiiluks 01; 300_Tüüp: vt. SA infosisu sakki; 310_Materjal: Alumiiniumprofiil klaasuks; 320_Klaas: vt. SA infosisu sakki; 325_Helipidavus: 36dB; 330_Tulekindlus: -; 350_Klaaspakett: 12mm karastatud ja lamineeritud klaas vastavalt tootele; 375_Viimistlus_seest: vt. SA infosisu sakki; 376_Viimistlus_väljast: vt. SA infosisu sakki
Type - SA_Uks - 000_Muinsuskaitse: no; 335_Välispiire: no; 340_Soojusläbivus: 0; 365_Isesulguv: no; 370_Evakuatsiooniväljapääs: yes; 310_Materjal: Alumiiniumprofiil klaasuks; 325_Helipidavus: 36dB; 330_Tulekindlus: -; 350_Klaaspakett: 12mm karastatud ja lamineeritud klaas vastavalt tootele
OverallHeight: 2400 mm; OverallWidth: 925 mm
Pset_DoorCommon - Reference: Metallprofiiluks 01; HandicapAccessible: yes
Pset_QuantityTakeOff - Reference: Metallprofiiluks 01
AR_Uks - 360_Ratastooliga: yes; 003_Elemendi_staadium: Projekteeritud; 305_Ava_mõõt_laius: 925 mm; 305_Ava_mõõt_korgus: 2400 mm; 315_Avanemine: vasak; 355_Pindala: 2.22 m2; 380_Lukustus: Vt. lukustuse projekti!; 455_Eriomadused: Üks uks kahepoolse ukse komplektist- vt. põhiplaane! Uks liitub klaasseina ja tumma kilbiga 250mm (ruumilülititele, kaardilugejale vms)- Vt. lisaks klaasvaheseinte loendit!
SA_Uks - 360_Ratastooliga: yes; 001_Nimetus: Alumiiniumprofiilis klaasuks klaasseina osana (üks pool kahepoolsest uksest); 003_Elemendi_staadium: Projekteeritud; 004_Lävepakk: Laskuv lävepakk; 005_Furnituur: Ukselink: VAL32.544010_NIS, viimistlus: harjatud RST. Hinged: Structo Pivot peithing.; 300_Tüüp: SRR0250; 305_Ava_laius: 925 mm; 305_Ava_kõrgus: 2400 mm; 315_Avanemine: vasak; 320_Klaas: Kirgas klaas; 355_Pindala: 2.22 m2; 375_Viimistlus_seest: Raam pulbervärvitud RAL 9010 (valge); 380_Lukustus: Vt. lukustuse projekti!; 900_Tootja: Structo; 905_Mudel: Porta-53G Aluslim 12 raamitud täisklaasuks (üks uks kahepoolse ukse komplektist)
BaseQuantities - Height: 2400 mm; Width: 925 mm; Area: 2.22 m2

# IfcDoor: 1-poolne, klaasseina uks:Metallprofiiluks 01, 1-poolne, klaasseina uks:Metallprofiiluks 01:7887750
In: 1. korrus
Type - OperationType: SINGLE_SWING_RIGHT; ParameterTakesPrecedence: no; Sizeable: no; Classification: B2030100 Uniformat (Uniformat); Material: EST. Klaas. 1x. E-korpus, EST.Alumiinium.RAL9005
Type - 1-poolne, klaasseina uks:Metallprofiiluks 01:7887750:1 - PanelOperation: SWINGING
Type - Pset_ConcreteElementGeneral - FireRating: -
Type - Pset_DoorCommon - IsExternal: no; ThermalTransmittance: 0 kg/K/s3; SelfClosing: no; FireExit: yes; FireRating: -; AcousticRating: 36dB
Type - AR_Uks - 000_Muinsuskaitse: no; 335_Välispiire: no; 340_Soojusläbivus: 0; 365_Isesulguv: no; 370_Evakuatsiooniväljapääs: yes; 001_Nimetus: Metallprofiiluks 01; 300_Tüüp: vt. SA infosisu sakki; 310_Materjal: Alumiiniumprofiil klaasuks; 320_Klaas: vt. SA infosisu sakki; 325_Helipidavus: 36dB; 330_Tulekindlus: -; 350_Klaaspakett: 12mm karastatud ja lamineeritud klaas vastavalt tootele; 375_Viimistlus_seest: vt. SA infosisu sakki; 376_Viimistlus_väljast: vt. SA infosisu sakki
Type - SA_Uks - 000_Muinsuskaitse: no; 335_Välispiire: no; 340_Soojusläbivus: 0; 365_Isesulguv: no; 370_Evakuatsiooniväljapääs: yes; 310_Materjal: Alumiiniumprofiil klaasuks; 325_Helipidavus: 36dB; 330_Tulekindlus: -; 350_Klaaspakett: 12mm karastatud ja lamineeritud klaas vastavalt tootele
OverallHeight: 2400 mm; OverallWidth: 1025 mm
Pset_DoorCommon - Reference: Metallprofiiluks 01; HandicapAccessible: yes
Pset_QuantityTakeOff - Reference: Metallprofiiluks 01
AR_Uks - 360_Ratastooliga: yes; 003_Elemendi_staadium: Projekteeritud; 305_Ava_mõõt_laius: 1025 mm; 305_Ava_mõõt_korgus: 2400 mm; 315_Avanemine: vasak; 355_Pindala: 2.46 m2; 380_Lukustus: Vt. lukustuse projekti!; 455_Eriomadused: Üks uks kahepoolse ukse komplektist- vt. põhiplaane! Uks liitub klaasseina ja tumma kilbiga 250mm (ruumilülititele, kaardilugejale vms)- Vt. lisaks klaasvaheseinte loendit! Mitteaktiivne ukseleht vasutstada kiirriiviga.
SA_Uks - 360_Ratastooliga: yes; 001_Nimetus: Alumiiniumprofiilis klaasuks klaasseina osana (üks pool kahepoolsest uksest); 003_Elemendi_staadium: Projekteeritud; 004_Lävepakk: Laskuv lävepakk; 005_Furnituur: Ukselink: VAL32.544010_NIS, viimistlus: harjatud RST. Hinged: Structo Pivot peithing.; 300_Tüüp: SRR0528; 305_Ava_laius: 1025 mm; 305_Ava_kõrgus: 2400 mm; 315_Avanemine: vasak; 320_Klaas: Kirgas klaas; 355_Pindala: 2.46 m2; 375_Viimistlus_seest: Raam pulbervärvitud RAL 9010 (valge); 380_Lukustus: Vt. lukustuse projekti!; 900_Tootja: Structo; 905_Mudel: Porta-53G Aluslim 12 raamitud täisklaasuks (üks uks kahepoolse ukse komplektist)
BaseQuantities - Height: 2400 mm; Width: 1025 mm; Area: 2.46 m2

# IfcDoor: 1-poolne, klaasseina uks:Metallprofiiluks ühepoolne, 1-poolne, klaasseina uks:Metallprofiiluks ühepoolne:7887692
In: 1. korrus
Type - OperationType: SINGLE_SWING_RIGHT; ParameterTakesPrecedence: no; Sizeable: no; Classification: B2030100 Uniformat (Uniformat); Material: EST. Klaas. 3x. Default, EST.Alumiinium.RAL9005
Type - 1-poolne, klaasseina uks:Metallprofiiluks ühepoolne:7887692:1 - PanelOperation: SWINGING
Type - Pset_ConcreteElementGeneral - FireRating: -
Type - Pset_DoorCommon - IsExternal: no; ThermalTransmittance: 0 kg/K/s3; FireExit: yes; SelfClosing: yes; FireRating: -; AcousticRating: 36dB
Type - AR_Uks - 000_Muinsuskaitse: no; 335_Välispiire: no; 340_Soojusläbivus: 0; 365_Isesulguv: yes; 370_Evakuatsiooniväljapääs: yes; 001_Nimetus: Metallprofiiluks ühepoolne; 300_Tüüp: vt. SA infosisu sakki; 310_Materjal: Alumiiniumprofiil klaasuks; 320_Klaas: vt. SA infosisu sakki; 325_Helipidavus: 36dB; 330_Tulekindlus: -; 350_Klaaspakett: karastatud ja lamineeritud klaas vastavalt tootele; 375_Viimistlus_seest: vt. SA infosisu sakki; 376_Viimistlus_väljast: vt. SA infosisu sakki
Type - SA_Uks - 000_Muinsuskaitse: no; 335_Välispiire: no; 340_Soojusläbivus: 0; 365_Isesulguv: yes; 370_Evakuatsiooniväljapääs: yes; 310_Materjal: Alumiiniumprofiil klaasuks; 325_Helipidavus: 36dB; 330_Tulekindlus: -; 350_Klaaspakett: karastatud ja lamineeritud klaas vastavalt tootele
OverallHeight: 2400 mm; OverallWidth: 925 mm
Pset_DoorCommon - HandicapAccessible: yes; Reference: Metallprofiiluks ühepoolne
Pset_QuantityTakeOff - Reference: Metallprofiiluks ühepoolne
AR_Uks - 360_Ratastooliga: yes; 003_Elemendi_staadium: Projekteeritud; 305_Ava_mõõt_laius: 925 mm; 305_Ava_mõõt_korgus: 2400 mm; 315_Avanemine: vasak; 355_Pindala: 2.22 m2; 380_Lukustus: Vt. lukustuse projekti!; 455_Eriomadused: Uks liitub klaasseina ja tumma kilbiga 250mm (ruumilülititele, kaardilugejale vms)- Vt. lisaks klaasvaheseinte loendit!
SA_Uks - 360_Ratastooliga: yes; 001_Nimetus: Metallprofiiluks klaasseina osana; 003_Elemendi_staadium: Projekteeritud; 004_Lävepakk: Laskuv lävepakk; 005_Furnituur: Ukselink: VAL32.544010_NIS, viimistlus: harjatud RST. Hinged: vastavalt tootele, toon sama mis lengil.; 300_Tüüp: SRR0768; 305_Ava_laius: 925 mm; 305_Ava_kõrgus: 2400 mm; 315_Avanemine: vasak; 320_Klaas: Kirgas klaas osaliselt kiletatud. Kile: Solyx SimGlas SXJ-0547 Feather Gradient- hajuva (gradient) efektiga- täismatist kirkaks. Klaasi alumine osa kaetud täismatt kilega, hajuv osa alates kõrgusest 1600mm, ülemine osa kirgas. Lahendusest teha näidis ühel; 355_Pindala: 2.22 m2; 375_Viimistlus_seest: Raam pulbervärvitud RAL 9010 (valge); 380_Lukustus: Vt. lukustuse projekti!; 900_Tootja: Structo; 905_Mudel: Porta-53G Aluslim 12 raamitud täisklaasuks
BaseQuantities - Height: 2400 mm; Width: 925 mm; Area: 2.22 m2

# IfcDoor: Klaasseina ukse tüüp 2:VU-15 (10)
In: 1. korrus
Type - ParameterTakesPrecedence: no; Sizeable: no; Material: Metal - Solar Innovations - Powder Coat, LUMION_dark steel window frames, EST. Klaas. 3x. Default
Type - Pset_ConcreteElementGeneral - FireRating: -
Type - Pset_DoorCommon - IsExternal: yes; FireRating: -; AcousticRating: 35dB; ThermalTransmittance: 1 kg/K/s3
Type - Pset_ManufacturerTypeInformation - Manufacturer: Aluprof
Type - AR_Uks - 000_Muinsuskaitse: no; 335_Välispiire: yes; 001_Nimetus: VU-15; 300_Tüüp: VU-15; 310_Materjal: Alumiiniumprofiil; 320_Klaas: Toonitud peegelklaas, pronks; 325_Helipidavus: 35dB; 330_Tulekindlus: -; 340_Soojusläbivus: 1; 350_Klaaspakett: Toonklaas 10mm; 375_Viimistlus_seest: RAL 9005 (must); 376_Viimistlus_väljast: RAL 9005 (must); 900_Tootja: Aluprof; 905_Mudel: MB-104 Passive SI
Type - SA_Uks - 000_Muinsuskaitse: no; 335_Välispiire: yes; 340_Soojusläbivus: 1; 310_Materjal: Alumiiniumprofiil; 325_Helipidavus: 35dB; 330_Tulekindlus: -; 350_Klaaspakett: Toonklaas 10mm
Type - BIM - AR VU Sulgurid: Vt. märkus
OverallHeight: 2300 mm; OverallWidth: 850 mm
Pset_DoorCommon - FireExit: yes; SelfClosing: yes; HandicapAccessible: yes; Reference: VU-15
Pset_DoorWindowGlazingType - SolarHeatGainTransmittance: 0.4
Pset_QuantityTakeOff - Reference: VU-15
AR_Uks - 365_Isesulguv: yes; 370_Evakuatsiooniväljapääs: yes; 360_Ratastooliga: yes; 003_Elemendi_staadium: Projekteeritud; 305_Ava_mõõt_laius: 850 mm; 305_Ava_mõõt_korgus: 2300 mm; 315_Avanemine: Parem; 345_Päiksekiirgus_tegur: 0.4; 355_Pindala: 1.955 m2; 380_Lukustus: Vt. lukustuse projekti!
SA_Uks - 365_Isesulguv: yes; 370_Evakuatsiooniväljapääs: yes; 360_Ratastooliga: yes; 003_Elemendi_staadium: Projekteeritud; 004_Lävepakk: 20mm; 305_Ava_laius: 850 mm; 305_Ava_kõrgus: 2300 mm; 315_Avanemine: Parem; 345_Päiksekiirgus_tegur: 0.4; 355_Pindala: 1.955 m2; 380_Lukustus: Vt. lukustuse projekti!
BaseQuantities - Height: 2300 mm; Width: 850 mm; Area: 1.955 m2
Name (Klaasseina ukse tüüp 2:VU-15:...) | 001_Nimetus | 300_Tüüp
10533019 | VU-15p | 2372
10533124 | VU-15p | 2375
10533232 | VU-15p | 2378
10533340 | VU-15p | 2381
10533448 | VU-15p | 2384
10533556 | VU-15p | 2387
10533664 | VU-15p | 2390
10533772 | VU-15p* | 2393 | AR_Uks - 455_Eriomadused: uks avanev kompensatsiooniõhuks
10533880 | VU-15p* | 2396 | AR_Uks - 455_Eriomadused: uks avanev kompensatsiooniõhuks
10533988 | VU-15p | 2399

# IfcDoor: Klaasseina ukse tüüp 2:VU-15, Klaasseina ukse tüüp 2:VU-15:10534096
In: 1. korrus
Type - ParameterTakesPrecedence: no; Sizeable: no; Material: Metal - Solar Innovations - Powder Coat, LUMION_dark steel window frames, EST. Klaas. 3x. Default
Type - Pset_ConcreteElementGeneral - FireRating: -
Type - Pset_DoorCommon - IsExternal: yes; ThermalTransmittance: 1 kg/K/s3; FireRating: -; AcousticRating: 35dB
Type - Pset_ManufacturerTypeInformation - Manufacturer: Aluprof
Type - AR_Uks - 000_Muinsuskaitse: no; 335_Välispiire: yes; 340_Soojusläbivus: 1; 001_Nimetus: VU-15; 300_Tüüp: VU-15; 310_Materjal: Alumiiniumprofiil; 320_Klaas: Toonitud peegelklaas, pronks; 325_Helipidavus: 35dB; 330_Tulekindlus: -; 350_Klaaspakett: Toonklaas 10mm; 375_Viimistlus_seest: RAL 9005 (must); 376_Viimistlus_väljast: RAL 9005 (must); 900_Tootja: Aluprof; 905_Mudel: MB-104 Passive SI
Type - SA_Uks - 000_Muinsuskaitse: no; 335_Välispiire: yes; 340_Soojusläbivus: 1; 310_Materjal: Alumiiniumprofiil; 325_Helipidavus: 35dB; 330_Tulekindlus: -; 350_Klaaspakett: Toonklaas 10mm
Type - BIM - AR VU Sulgurid: Vt. märkus
OverallHeight: 2300 mm; OverallWidth: 850 mm
Pset_DoorCommon - FireExit: yes; SelfClosing: yes; HandicapAccessible: yes; Reference: VU-15
Pset_DoorWindowGlazingType - SolarHeatGainTransmittance: 0.4
Pset_QuantityTakeOff - Reference: VU-15
AR_Uks - 365_Isesulguv: yes; 370_Evakuatsiooniväljapääs: yes; 360_Ratastooliga: yes; 003_Elemendi_staadium: Projekteeritud; 305_Ava_mõõt_laius: 850 mm; 305_Ava_mõõt_korgus: 2300 mm; 315_Avanemine: Parem; 345_Päiksekiirgus_tegur: 0.4; 355_Pindala: 1.955 m2; 380_Lukustus: Vt. lukustuse projekti!
SA_Uks - 365_Isesulguv: yes; 370_Evakuatsiooniväljapääs: yes; 360_Ratastooliga: yes; 001_Nimetus: VU-15v; 003_Elemendi_staadium: Projekteeritud; 004_Lävepakk: 20mm; 300_Tüüp: 2402; 305_Ava_laius: 850 mm; 305_Ava_kõrgus: 2300 mm; 315_Avanemine: Parem; 345_Päiksekiirgus_tegur: 0.4; 355_Pindala: 1.955 m2; 380_Lukustus: Vt. lukustuse projekti!
BaseQuantities - Height: 2300 mm; Width: 850 mm; Area: 1.955 m2

# IfcDoor: Metallprofiiluks klaasseinaosana:uus metallprofiiluks - 900x2300, Metallprofiiluks klaasseinaosana:uus metallprofiiluks - 900x2300:13278712
In: 1. korrus
Type - OperationType: SINGLE_SWING_RIGHT; ParameterTakesPrecedence: no; Sizeable: no; Classification: B2030100 Uniformat (Uniformat); Material: Aluminum, Glass, <Unnamed>
Type - Metallprofiiluks klaasseinaosana:uus metallprofiiluks - 900x2300:13278712:1 - PanelOperation: SWINGING
Type - Pset_ConcreteElementGeneral - FireRating: EI-45
Type - Pset_DoorCommon - IsExternal: no; ThermalTransmittance: 0 kg/K/s3; SelfClosing: no; FireExit: yes; FireRating: EI-45; AcousticRating: 42dB
Type - AR_Uks - 000_Muinsuskaitse: no; 335_Välispiire: no; 340_Soojusläbivus: 0; 365_Isesulguv: no; 370_Evakuatsiooniväljapääs: yes; 001_Nimetus: uus metallprofiiluks - 900x2300; 300_Tüüp: vt. SA infosisu sakki; 310_Materjal: Metallprofiiluks klaasosaga; 320_Klaas: vt. SA infosisu sakki; 325_Helipidavus: 42dB; 330_Tulekindlus: EI-45; 350_Klaaspakett: tuletõkkeklaas vastavalt tootele; 375_Viimistlus_seest: vt. SA infosisu sakki; 376_Viimistlus_väljast: vt. SA infosisu sakki
Type - SA_Uks - 000_Muinsuskaitse: no; 335_Välispiire: no; 340_Soojusläbivus: 0; 365_Isesulguv: no; 370_Evakuatsiooniväljapääs: yes; 310_Materjal: Metallprofiiluks klaasosaga; 325_Helipidavus: 42dB; 330_Tulekindlus: EI-45; 350_Klaaspakett: tuletõkkeklaas vastavalt tootele
OverallHeight: 2150 mm; OverallWidth: 900 mm
Pset_DoorCommon - HandicapAccessible: yes; Reference: uus metallprofiiluks - 900x2300
Pset_QuantityTakeOff - Reference: uus metallprofiiluks - 900x2300
AR_Uks - 360_Ratastooliga: yes; 003_Elemendi_staadium: Projekteeritud; 305_Ava_mõõt_laius: 900 mm; 305_Ava_mõõt_korgus: 2150 mm; 315_Avanemine: Vasak; 355_Pindala: 1.935 m2; 380_Lukustus: Vt. lukustuse projekti!; 455_Eriomadused: Uks liitub klaasseina ja tumma kilbiga 250mm (ruumilülititele, kaardilugejale vms)- Vt. lisaks klaasvaheseinte loendit!
SA_Uks - 360_Ratastooliga: yes; 001_Nimetus: Alumiiniumprofiilis klaasuks klaasseina osana; 003_Elemendi_staadium: Projekteeritud; 004_Lävepakk: Laskuv lävepakk; 005_Furnituur: Ukselink: VAL32.544010_NIS, viimistlus: harjatud RST. Hinged: Structo peithing.; 300_Tüüp: SRR0789; 305_Ava_laius: 900 mm; 305_Ava_kõrgus: 2150 mm; 315_Avanemine: Vasak; 320_Klaas: Kirgas klaas osaliselt kiletatud. Kile: Solyx SimGlas SXJ-0547 Feather Gradient- hajuva (gradient) efektiga- täismatist kirkaks. Klaasi alumine osa kaetud täismatt kilega, hajuv osa alates kõrgusest 1600mm, ülemine osa kirgas. Lahendusest teha näidis ühel; 355_Pindala: 1.935 m2; 375_Viimistlus_seest: Raam pulbervärvitud RAL 9010 (valge); 380_Lukustus: Vt. lukustuse projekti!; 900_Tootja: Structo; 905_Mudel: Porta-53G Aluslim 12 raamitud täisklaasuks
BaseQuantities - Height: 2150 mm; Width: 900 mm; Area: 1.935 m2

# IfcDoor: SMA_D01, 1-poolne, kaar klaasiga:VU-63_1200x2100 (kaar 400mm), SMA_D01, 1-poolne, kaar klaasiga:VU-63_1200x2100 (kaar 400mm):5600994
In: E-korpus 2. korrus
Type - ParameterTakesPrecedence: no; Sizeable: no; Material: EST. Metall. Alumiinium. Värvitud., EST. Klaas. 3x. Default
Type - Pset_ConcreteElementGeneral - FireRating: -
Type - Pset_DoorCommon - IsExternal: yes; FireRating: -; AcousticRating: Rw=34dB; ThermalTransmittance: 1.43 kg/K/s3
Type - Pset_ManufacturerTypeInformation - Manufacturer: Sakumetall+puitraamil klaasframuuk
Type - AR_Uks - 000_Muinsuskaitse: no; 335_Välispiire: yes; 001_Nimetus: VU-63_1200x2100 (kaar 400mm); 300_Tüüp: VU-63; 305_Ava_mõõt_laius: 1200 mm; 305_Ava_mõõt_korgus: 2100 mm; 310_Materjal: Metalluks klaasframuugiga; 320_Klaas: Toonitud peegelklaas, pronks; 325_Helipidavus: Rw=34dB; 330_Tulekindlus: -; 340_Soojusläbivus: 1.43; 350_Klaaspakett: Toonklaas 10mm; 375_Viimistlus_seest: RAL 9005 (must); 376_Viimistlus_väljast: RAL 9005 (must); 380_Lukustus: Vt. lukustuse projekti!; 900_Tootja: Sakumetall+puitraamil klaasframuuk; 905_Mudel: -
Type - SA_Uks - 000_Muinsuskaitse: no; 335_Välispiire: yes; 305_Ava_laius: 1200 mm; 305_Ava_kõrgus: 2100 mm; 310_Materjal: Metalluks klaasframuugiga; 325_Helipidavus: Rw=34dB; 330_Tulekindlus: -; 340_Soojusläbivus: 1.43; 350_Klaaspakett: Toonklaas 10mm; 380_Lukustus: Vt. lukustuse projekti!
OverallHeight: 2500 mm; OverallWidth: 1200 mm
Pset_DoorCommon - FireExit: no; HandicapAccessible: no; SelfClosing: yes; Reference: VU-63_1200x2100 (kaar 400mm)
Pset_DoorWindowGlazingType - SolarHeatGainTransmittance: 0.4
Pset_QuantityTakeOff - Reference: VU-63_1200x2100 (kaar 400mm)
AR_Uks - 360_Ratastooliga: no; 370_Evakuatsiooniväljapääs: no; 365_Isesulguv: yes; 003_Elemendi_staadium: Projekteeritud; 315_Avanemine: Vasak; 345_Päiksekiirgus_tegur: 0.4; 355_Pindala: 7.24196 m2
SA_Uks - 360_Ratastooliga: no; 370_Evakuatsiooniväljapääs: no; 365_Isesulguv: yes; 001_Nimetus: VU-63v; 003_Elemendi_staadium: Projekteeritud; 004_Lävepakk: 25mm RST; 315_Avanemine: Vasak; 345_Päiksekiirgus_tegur: 0.4; 355_Pindala: 7.24196 m2
BIM - AR VU Sulgurid: Meh. sulgur
BaseQuantities - Height: 2100 mm; Width: 1200 mm; Area: 7.24196 m2

# IfcDoor: SMA_D01, 1-poolne:HLU-03 - 600x800mm, SMA_D01, 1-poolne:HLU-03 - 600x800mm:13043182
In: -1. korrus
Type - ParameterTakesPrecedence: no; Sizeable: no; Material: EST. Metall. Alumiinium. Värvitud., EST. Klaas. 3x. Default
Type - Pset_ConcreteElementGeneral - FireRating: -
Type - Pset_DoorCommon - IsExternal: no; FireRating: -; AcousticRating: -; ThermalTransmittance: 1.1 kg/K/s3
Type - Pset_ManufacturerTypeInformation - Manufacturer: Luugiladu Sakir
Type - AR_Uks - 000_Muinsuskaitse: no; 335_Välispiire: no; 001_Nimetus: HLU-03 - 600x800mm; 300_Tüüp: vt. SA infosisu sakki; 305_Ava_mõõt_laius: 600 mm; 305_Ava_mõõt_korgus: 800 mm; 310_Materjal: Terasplekk; 320_Klaas: vt. SA infosisu sakki; 325_Helipidavus: -; 330_Tulekindlus: -; 340_Soojusläbivus: 1.1; 350_Klaaspakett: -; 375_Viimistlus_seest: vt. SA infosisu sakki; 376_Viimistlus_väljast: vt. SA infosisu sakki; 900_Tootja: Luugiladu Sakir
Type - SA_Uks - 000_Muinsuskaitse: no; 335_Välispiire: no; 305_Ava_laius: 600 mm; 305_Ava_kõrgus: 800 mm; 310_Materjal: Terasplekk; 325_Helipidavus: -; 330_Tulekindlus: -; 340_Soojusläbivus: 1.1; 350_Klaaspakett: -
OverallHeight: 800 mm; OverallWidth: 600 mm
Pset_DoorCommon - FireExit: no; HandicapAccessible: no; SelfClosing: no; Reference: HLU-03 - 600x800mm
Pset_QuantityTakeOff - Reference: HLU-03 - 600x800mm
AR_Uks - 360_Ratastooliga: no; 365_Isesulguv: no; 370_Evakuatsiooniväljapääs: no; 003_Elemendi_staadium: Projekteeritud; 315_Avanemine: vasak; 355_Pindala: 1.57763 m2; 380_Lukustus: Tootepõhine lukustus.; 455_Eriomadused: -
SA_Uks - 360_Ratastooliga: no; 365_Isesulguv: no; 370_Evakuatsiooniväljapääs: no; 001_Nimetus: Hooldusluuk; 003_Elemendi_staadium: Projekteeritud; 004_Lävepakk: Tihendid vastavalt tootele; 005_Furnituur: Vastavalt tootele; 300_Tüüp: SRR0366; 315_Avanemine: vasak; 320_Klaas: Puudub; 355_Pindala: 1.57763 m2; 375_Viimistlus_seest: Seinaga analoogset tooni.; 380_Lukustus: Tootepõhine lukustus.; 900_Tootja: Karlbilder; 905_Mudel: Metallist hooldusluuk
BaseQuantities - Height: 800 mm; Width: 600 mm; Area: 1.57763 m2

# IfcDoor: SMA_D01, 1-poolne:SU-00 - 1000x2100 lävepakuta, SMA_D01, 1-poolne:SU-00 - 1000x2100 lävepakuta:9543578
In: 1. korrus
Type - OperationType: SINGLE_SWING_RIGHT; ParameterTakesPrecedence: no; Sizeable: no; Material: EST. Metall. Alumiinium. Värvitud.
Type - SMA_D01, 1-poolne:SU-00 - 1000x2100 lävepakuta:9543578:1 - PanelOperation: SWINGING
Type - Pset_ConcreteElementGeneral - FireRating: -
Type - Pset_DoorCommon - IsExternal: no; ThermalTransmittance: 0 kg/K/s3; FireRating: -; AcousticRating: -
Type - AR_Uks - 000_Muinsuskaitse: no; 335_Välispiire: no; 340_Soojusläbivus: 0; 001_Nimetus: SU-00 - 1000x2100 lävepakuta; 300_Tüüp: vt. SA infosisu sakki; 305_Ava_mõõt_laius: 1000 mm; 305_Ava_mõõt_korgus: 2100 mm; 310_Materjal: Puituks; 320_Klaas: vt. SA infosisu sakki; 325_Helipidavus: -; 330_Tulekindlus: -; 350_Klaaspakett: -; 375_Viimistlus_seest: vt. SA infosisu sakki; 376_Viimistlus_väljast: vt. SA infosisu sakki
Type - SA_Uks - 000_Muinsuskaitse: no; 335_Välispiire: no; 340_Soojusläbivus: 0; 305_Ava_laius: 1000 mm; 305_Ava_kõrgus: 2100 mm; 310_Materjal: Puituks; 325_Helipidavus: -; 330_Tulekindlus: -; 350_Klaaspakett: -
OverallHeight: 2100 mm; OverallWidth: 1000 mm
Pset_DoorCommon - FireExit: no; SelfClosing: no; HandicapAccessible: yes; Reference: SU-00 - 1000x2100 lävepakuta
Pset_QuantityTakeOff - Reference: SU-00 - 1000x2100 lävepakuta
AR_Uks - 365_Isesulguv: no; 370_Evakuatsiooniväljapääs: no; 360_Ratastooliga: yes; 003_Elemendi_staadium: Projekteeritud; 315_Avanemine: vasak; 355_Pindala: 5.24943 m2; 380_Lukustus: Vt. lukustuse projekti!; 455_Eriomadused: -
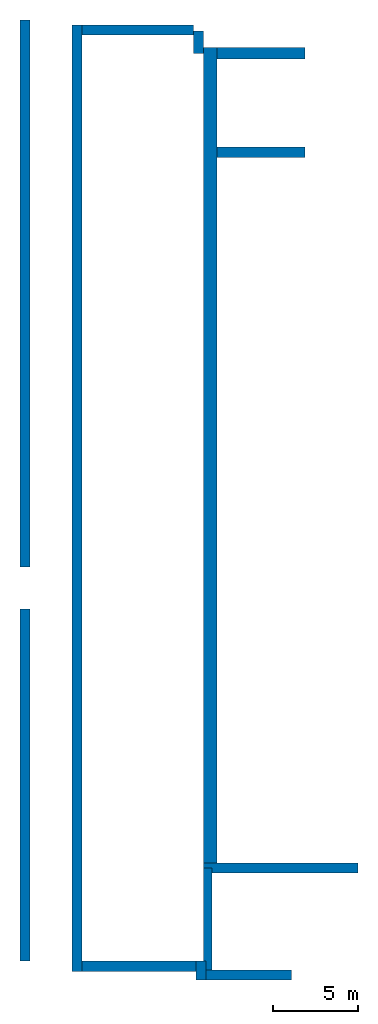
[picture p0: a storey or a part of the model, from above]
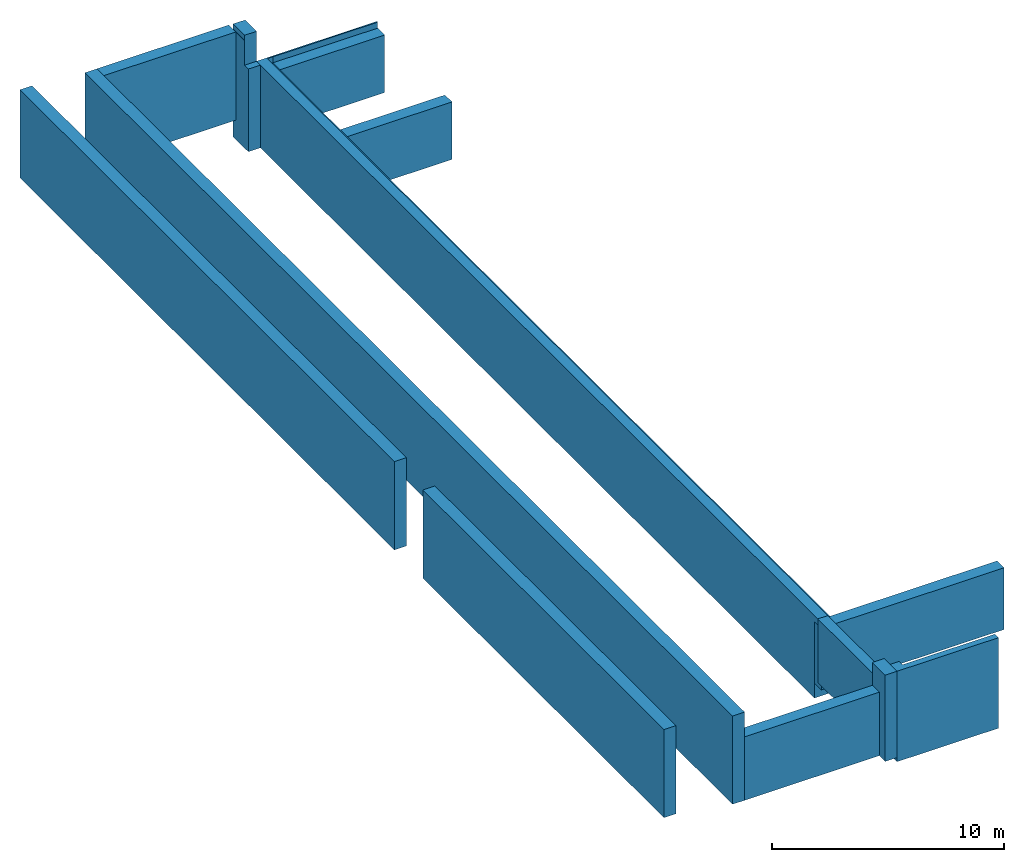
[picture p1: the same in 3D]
Properties of the parts of a building model (IFC2X3), part 3 of 7

# IfcDoor: SMA_D01, 1-poolne:SU-00 - 1000x2100 lävepakuta, SMA_D01, 1-poolne:SU-00 - 1000x2100 lävepakuta:9543578
SA_Uks - 365_Isesulguv: no; 370_Evakuatsiooniväljapääs: no; 360_Ratastooliga: yes; 001_Nimetus: Ühepoolne tumm uks KVTD pos.15 eeskujul; 003_Elemendi_staadium: Projekteeritud; 004_Lävepakk: -; 005_Furnituur: Ukselink: VAL5_008E_NIS / VAL51_008E_NIS (evak.uksel), viimistlus: harjatud RST. Hinged: analoogsed olemasolevatele ustele, pulbervärvitud RAL 7039 (tume hall).; 300_Tüüp: SRR0803; 315_Avanemine: vasak; 320_Klaas: Puudub; 355_Pindala: 5.24943 m2; 375_Viimistlus_seest: Ukseleht, liistud ja leng spoonitud muinsuskaitse all olevate spoonitud ustega analoogse spooniga, mis toonida õlitatud pähkli tooni, lakkida mattlakiga. Viimistluspinnast esitada näidis!; 380_Lukustus: Vt. lukustuse projekti!; 900_Tootja: Jeld-Wen; 905_Mudel: Sile spoonitud puituks
BaseQuantities - Height: 2100 mm; Width: 1000 mm; Area: 5.24943 m2

# IfcDoor: SMA_D01, 1-poolne:SU-00 - 800x2100, SMA_D01, 1-poolne:SU-00 - 800x2100:8981867
In: -1. korrus
Type - ParameterTakesPrecedence: no; Sizeable: no; Material: EST. Metall. Alumiinium. Värvitud.
Type - Pset_ConcreteElementGeneral - FireRating: -
Type - Pset_DoorCommon - IsExternal: no; ThermalTransmittance: 0 kg/K/s3; FireRating: -; AcousticRating: -
Type - AR_Uks - 000_Muinsuskaitse: no; 335_Välispiire: no; 340_Soojusläbivus: 0; 001_Nimetus: SU-00 - 800x2100; 300_Tüüp: vt. SA infosisu sakki; 305_Ava_mõõt_laius: 800 mm; 305_Ava_mõõt_korgus: 2100 mm; 310_Materjal: Puituks; 320_Klaas: vt. SA infosisu sakki; 325_Helipidavus: -; 330_Tulekindlus: -; 350_Klaaspakett: -; 375_Viimistlus_seest: vt. SA infosisu sakki; 376_Viimistlus_väljast: vt. SA infosisu sakki
Type - SA_Uks - 000_Muinsuskaitse: no; 335_Välispiire: no; 340_Soojusläbivus: 0; 305_Ava_laius: 800 mm; 305_Ava_kõrgus: 2100 mm; 310_Materjal: Puituks; 325_Helipidavus: -; 330_Tulekindlus: -; 350_Klaaspakett: -
OverallHeight: 2100 mm; OverallWidth: 800 mm
Pset_DoorCommon - FireExit: no; HandicapAccessible: no; SelfClosing: no; Reference: SU-00 - 800x2100
Pset_QuantityTakeOff - Reference: SU-00 - 800x2100
AR_Uks - 360_Ratastooliga: no; 365_Isesulguv: no; 370_Evakuatsiooniväljapääs: no; 003_Elemendi_staadium: Projekteeritud; 315_Avanemine: parem; 355_Pindala: 4.31743 m2; 380_Lukustus: D-Line- Knud Holscher 14347802300, harjatud RST; 455_Eriomadused: Piirdeliist 60mm
SA_Uks - 360_Ratastooliga: no; 365_Isesulguv: no; 370_Evakuatsiooniväljapääs: no; 001_Nimetus: Ühepoolne niiskuskindel tumm uks; 003_Elemendi_staadium: Projekteeritud; 004_Lävepakk: -; 005_Furnituur: Ukselink: VAL32.544010_NIS, viimistlus: harjatud RST. Hinged: Fiskostar, toon sama, mis lengil.; 300_Tüüp: SRR0510; 315_Avanemine: parem; 320_Klaas: Puudub; 355_Pindala: 4.31743 m2; 375_Viimistlus_seest: Ukseleht, leng ja liist kaetud kõrgsurvelaminaadiga: Formica F7928 Mouse Matte (tume hall).; 380_Lukustus: D-Line- Knud Holscher 14347802300, harjatud RST; 900_Tootja: Jeld-Wen; 905_Mudel: Sile lamineeritud puituks
BaseQuantities - Height: 2100 mm; Width: 800 mm; Area: 4.31743 m2

# IfcDoor: SMA_D01, 1-poolne:SU-00 - puituks 800x2100 ventil. lävepakuga, SMA_D01, 1-poolne:SU-00 - puituks 800x2100 ventil. lävepakuga:8981842
In: -1. korrus
Type - ParameterTakesPrecedence: no; Sizeable: no; Material: EST. Metall. Alumiinium. Värvitud.
Type - Pset_ConcreteElementGeneral - FireRating: -
Type - Pset_DoorCommon - IsExternal: no; ThermalTransmittance: 0 kg/K/s3; FireRating: -; AcousticRating: -
Type - AR_Uks - 000_Muinsuskaitse: no; 335_Välispiire: no; 340_Soojusläbivus: 0; 001_Nimetus: SU-00 - puituks 800x2100 ventil. lävepakuga; 300_Tüüp: vt. SA infosisu sakki; 305_Ava_mõõt_laius: 800 mm; 305_Ava_mõõt_korgus: 2100 mm; 310_Materjal: Puituks; 320_Klaas: vt. SA infosisu sakki; 325_Helipidavus: -; 330_Tulekindlus: -; 350_Klaaspakett: -; 375_Viimistlus_seest: vt. SA infosisu sakki; 376_Viimistlus_väljast: vt. SA infosisu sakki
Type - SA_Uks - 000_Muinsuskaitse: no; 335_Välispiire: no; 340_Soojusläbivus: 0; 305_Ava_laius: 800 mm; 305_Ava_kõrgus: 2100 mm; 310_Materjal: Puituks; 325_Helipidavus: -; 330_Tulekindlus: -; 350_Klaaspakett: -
OverallHeight: 2100 mm; OverallWidth: 800 mm
Pset_DoorCommon - FireExit: no; HandicapAccessible: no; SelfClosing: no; Reference: SU-00 - puituks 800x2100 ventil. lävepakuga
Pset_QuantityTakeOff - Reference: SU-00 - puituks 800x2100 ventil. lävepakuga
AR_Uks - 360_Ratastooliga: no; 365_Isesulguv: no; 370_Evakuatsiooniväljapääs: no; 003_Elemendi_staadium: Projekteeritud; 315_Avanemine: parem; 355_Pindala: 4.31743 m2; 380_Lukustus: D-Line- Knud Holscher 14347802300, harjatud RST; 455_Eriomadused: Piirdeliist 60mm
SA_Uks - 360_Ratastooliga: no; 365_Isesulguv: no; 370_Evakuatsiooniväljapääs: no; 001_Nimetus: Ühepoolne tumm uks; 003_Elemendi_staadium: Projekteeritud; 004_Lävepakk: Puidust, ventileeriv; 005_Furnituur: Ukselink: VAL32.544010_NIS, viimistlus: harjatud RST. Fiskostar, toon sama mis lengil.; 300_Tüüp: SRR0497; 315_Avanemine: parem; 320_Klaas: Puudub; 355_Pindala: 4.31743 m2; 375_Viimistlus_seest: Ukseleht, leng ja liist värvitud: RAL 7037 (tume hall).; 380_Lukustus: D-Line- Knud Holscher 14347802300, harjatud RST; 900_Tootja: Jeld-Wen; 905_Mudel: Sile värvitud puituks
BaseQuantities - Height: 2100 mm; Width: 800 mm; Area: 4.31743 m2

# IfcDoor: SMA_D01, 1-poolne:ol. olev MKU-15 - 800x2100, SMA_D01, 1-poolne:ol. olev MKU-15 - 800x2100:1383072
In: 3. korrus
Type - ParameterTakesPrecedence: no; Sizeable: no; Material: EST. Metall. Alumiinium. Värvitud., ol. olev - voolikukapp, MK uksed, elemendid
Type - Pset_ConcreteElementGeneral - FireRating: -
Type - Pset_DoorCommon - IsExternal: no; ThermalTransmittance: 0 kg/K/s3; FireRating: -; AcousticRating: MK ustel 30dB / uutel 38dB
Type - AR_Uks - 335_Välispiire: no; 340_Soojusläbivus: 0; 000_Muinsuskaitse: yes; 001_Nimetus: ol. olev MKU-15 - 800x2100; 300_Tüüp: vt. SA infosisu sakki; 305_Ava_mõõt_laius: 800 mm; 305_Ava_mõõt_korgus: 2100 mm; 310_Materjal: Puituks; 320_Klaas: vt. SA infosisu sakki; 325_Helipidavus: MK ustel 30dB / uutel 38dB; 330_Tulekindlus: -; 350_Klaaspakett: -; 375_Viimistlus_seest: vt. SA infosisu sakki; 376_Viimistlus_väljast: vt. SA infosisu sakki
Type - SA_Uks - 335_Välispiire: no; 340_Soojusläbivus: 0; 000_Muinsuskaitse: yes; 305_Ava_laius: 800 mm; 305_Ava_kõrgus: 2100 mm; 310_Materjal: Puituks; 325_Helipidavus: MK ustel 30dB / uutel 38dB; 330_Tulekindlus: -; 350_Klaaspakett: -
OverallHeight: 2100 mm; OverallWidth: 800 mm
Pset_DoorCommon - Reference: ol. olev MKU-15 - 800x2100; FireExit: no; HandicapAccessible: no; SelfClosing: no
Pset_QuantityTakeOff - Reference: ol. olev MKU-15 - 800x2100
AR_Uks - 003_Elemendi_staadium: Olemasolev; 315_Avanemine: parem; 355_Pindala: 4.31743 m2; 360_Ratastooliga: no; 365_Isesulguv: no; 370_Evakuatsiooniväljapääs: no; 380_Lukustus: Vt. lukustuse projekti!; 455_Eriomadused: Puuduvad või katkised osad korrastada või asendada.
SA_Uks - 360_Ratastooliga: no; 365_Isesulguv: no; 370_Evakuatsiooniväljapääs: no; 001_Nimetus: KVTD pos.15; 003_Elemendi_staadium: Olemasolev; 004_Lävepakk: Laskuv lävepakk; 005_Furnituur: Ukselink: VAL5_008E_NIS / VAL51_008E_NIS (evak.uksel), viimistlus: harjatud RST. Hinged: olemasolevad või analoogsed olemasolevatele, pulbervärvitud RAL 7039 (tume hall).; 300_Tüüp: SRR0282; 315_Avanemine: parem; 320_Klaas: Puudub; 355_Pindala: 4.31743 m2; 375_Viimistlus_seest: Olemasolev spoon ja puitdetailid toonida õlitatud pähkli tooni, lakkida mattlakiga. Viimistluspinnast esitada näidis!; 380_Lukustus: Vt. lukustuse projekti!; 900_Tootja: Puudub; 905_Mudel: Olemasolev spoonitud sile uks
BaseQuantities - Height: 2100 mm; Width: 800 mm; Area: 4.31743 m2

# IfcDoor: SMA_D01, 1-poolne:uus puituks - 700x2100 lävepakuta 2 (2)
In: 1. korrus
Type - ParameterTakesPrecedence: no; Sizeable: no; Material: EST. Metall. Alumiinium. Värvitud.
Type - Pset_ConcreteElementGeneral - FireRating: -
Type - Pset_DoorCommon - IsExternal: no; ThermalTransmittance: 0 kg/K/s3; FireRating: -; AcousticRating: -
Type - AR_Uks - 000_Muinsuskaitse: no; 335_Välispiire: no; 340_Soojusläbivus: 0; 001_Nimetus: uus puituks - 700x2100 lävepakuta 2; 300_Tüüp: vt. SA infosisu sakki; 305_Ava_mõõt_laius: 700 mm; 305_Ava_mõõt_korgus: 2100 mm; 310_Materjal: Puituks; 320_Klaas: vt. SA infosisu sakki; 325_Helipidavus: -; 330_Tulekindlus: -; 350_Klaaspakett: -; 375_Viimistlus_seest: vt. SA infosisu sakki; 376_Viimistlus_väljast: vt. SA infosisu sakki
Type - SA_Uks - 000_Muinsuskaitse: no; 335_Välispiire: no; 340_Soojusläbivus: 0; 305_Ava_laius: 700 mm; 305_Ava_kõrgus: 2100 mm; 310_Materjal: Puituks; 325_Helipidavus: -; 330_Tulekindlus: -; 350_Klaaspakett: -
OverallHeight: 2100 mm; OverallWidth: 700 mm
Pset_DoorCommon - FireExit: no; HandicapAccessible: no; SelfClosing: no; Reference: uus puituks - 700x2100 lävepakuta 2
Pset_QuantityTakeOff - Reference: uus puituks - 700x2100 lävepakuta 2
AR_Uks - 360_Ratastooliga: no; 365_Isesulguv: no; 370_Evakuatsiooniväljapääs: no; 003_Elemendi_staadium: Projekteeritud; 355_Pindala: 3.85143 m2; 380_Lukustus: D-Line- Knud Holscher 14347802300, harjatud RST; 455_Eriomadused: -
SA_Uks - 360_Ratastooliga: no; 365_Isesulguv: no; 370_Evakuatsiooniväljapääs: no; 001_Nimetus: Ühepoolne tumm uks KVTD pos.15 eeskujul; 003_Elemendi_staadium: Projekteeritud; 004_Lävepakk: -; 005_Furnituur: Ukselink: VAL5_008E_NIS / VAL51_008E_NIS (evak.uksel), viimistlus: harjatud RST. Hinged: analoogsed olemasolevatele ustele, pulbervärvitud RAL 7039 (tume hall).; 320_Klaas: Puudub; 355_Pindala: 3.85143 m2; 375_Viimistlus_seest: Ukseleht, liistud ja leng spoonitud muinsuskaitse all olevate spoonitud ustega analoogse spooniga, mis toonida õlitatud pähkli tooni, lakkida mattlakiga. Viimistluspinnast esitada näidis!; 380_Lukustus: D-Line- Knud Holscher 14347802300, harjatud RST; 900_Tootja: Jeld-Wen; 905_Mudel: Sile spoonitud puituks
BaseQuantities - Height: 2100 mm; Width: 700 mm; Area: 3.85143 m2
Name (SMA_D01, 1-poolne:uus puituks - 700x2100 lävepakuta 2:...) | AR_Uks, 315_Avanemine = SA_Uks, 315_Avanemine | 300_Tüüp
15366973 | vasak | SRR0626
15367203 | parem | SRR0595

# IfcDoor: SMA_D01, 1-poolne:uus puituks - 750x2250 lävepakuta, SMA_D01, 1-poolne:uus puituks - 750x2250 lävepakuta:2242801
In: 1. korrus
Type - ParameterTakesPrecedence: no; Sizeable: no; Material: EST. Metall. Alumiinium. Värvitud.
Type - Pset_ConcreteElementGeneral - FireRating: -
Type - Pset_DoorCommon - IsExternal: no; ThermalTransmittance: 0 kg/K/s3; FireRating: -; AcousticRating: -
Type - AR_Uks - 000_Muinsuskaitse: no; 335_Välispiire: no; 340_Soojusläbivus: 0; 001_Nimetus: uus puituks - 750x2250 lävepakuta; 300_Tüüp: vt. SA infosisu sakki; 305_Ava_mõõt_laius: 750 mm; 305_Ava_mõõt_korgus: 2250 mm; 310_Materjal: Puituks; 320_Klaas: vt. SA infosisu sakki; 325_Helipidavus: -; 330_Tulekindlus: -; 350_Klaaspakett: -; 375_Viimistlus_seest: vt. SA infosisu sakki; 376_Viimistlus_väljast: vt. SA infosisu sakki
Type - SA_Uks - 000_Muinsuskaitse: no; 335_Välispiire: no; 340_Soojusläbivus: 0; 305_Ava_laius: 750 mm; 305_Ava_kõrgus: 2250 mm; 310_Materjal: Puituks; 325_Helipidavus: -; 330_Tulekindlus: -; 350_Klaaspakett: -
OverallHeight: 2250 mm; OverallWidth: 750 mm
Pset_DoorCommon - FireExit: no; HandicapAccessible: no; SelfClosing: no; Reference: uus puituks - 750x2250 lävepakuta
Pset_QuantityTakeOff - Reference: uus puituks - 750x2250 lävepakuta
AR_Uks - 360_Ratastooliga: no; 365_Isesulguv: no; 370_Evakuatsiooniväljapääs: no; 003_Elemendi_staadium: Projekteeritud; 315_Avanemine: parem; 355_Pindala: 4.37918 m2; 380_Lukustus: Vt. lukustuse projekti!; 455_Eriomadused: -
SA_Uks - 360_Ratastooliga: no; 365_Isesulguv: no; 370_Evakuatsiooniväljapääs: no; 001_Nimetus: Ühepoolne tumm uks KVTD pos.15 eeskujul; 003_Elemendi_staadium: Projekteeritud; 004_Lävepakk: -; 005_Furnituur: Ukselink: VAL5_008E_NIS / VAL51_008E_NIS (evak.uksel), viimistlus: harjatud RST. Hinged: analoogsed olemasolevatele ustele, pulbervärvitud RAL 7039 (tume hall).; 300_Tüüp: SRR0703; 315_Avanemine: parem; 320_Klaas: Puudub; 355_Pindala: 4.37918 m2; 375_Viimistlus_seest: Ukseleht, liistud ja leng spoonitud muinsuskaitse all olevate spoonitud ustega analoogse spooniga, mis toonida õlitatud pähkli tooni, lakkida mattlakiga. Viimistluspinnast esitada näidis!; 380_Lukustus: Vt. lukustuse projekti!; 900_Tootja: Jeld-Wen; 905_Mudel: Sile spoonitud puituks
BaseQuantities - Height: 2250 mm; Width: 750 mm; Area: 4.37918 m2

# IfcDoor: SMA_D02, 2-poolne:2000x2400mm EI30 laskuv lävep. 2, SMA_D02, 2-poolne:2000x2400mm EI30 laskuv lävep. 2:13278779
In: 1. korrus
Type - OperationType: DOUBLE_DOOR_SINGLE_SWING; ParameterTakesPrecedence: no; Sizeable: no; Material: EST. Metall. Plekk. Värvitud. RAL7023 (Concrete grey)
Type - SMA_D02, 2-poolne:2000x2400mm EI30 laskuv lävep. 2:13278779:1 - PanelOperation: SWINGING
Type - Pset_ConcreteElementGeneral - FireRating: EI-30
Type - Pset_DoorCommon - IsExternal: no; ThermalTransmittance: 0 kg/K/s3; FireRating: EI-30; AcousticRating: 38dB
Type - Pset_ManufacturerTypeInformation - Manufacturer: vt. SA infosisu sakki
Type - AR_Uks - 000_Muinsuskaitse: no; 335_Välispiire: no; 340_Soojusläbivus: 0; 001_Nimetus: 2000x2400mm EI30 laskuv lävep. 2; 300_Tüüp: vt. SA infosisu sakki; 305_Ava_mõõt_laius: 2000 mm; 305_Ava_mõõt_korgus: 2400 mm; 310_Materjal: Puituks; 320_Klaas: vt. SA infosisu sakki; 325_Helipidavus: 38dB; 330_Tulekindlus: EI-30; 350_Klaaspakett: -; 375_Viimistlus_seest: vt. SA infosisu sakki; 376_Viimistlus_väljast: vt. SA infosisu sakki; 900_Tootja: vt. SA infosisu sakki; 905_Mudel: vt. SA infosisu sakki
Type - SA_Uks - 000_Muinsuskaitse: no; 335_Välispiire: no; 340_Soojusläbivus: 0; 305_Ava_laius: 2000 mm; 305_Ava_kõrgus: 2400 mm; 310_Materjal: Puituks; 325_Helipidavus: 38dB; 330_Tulekindlus: EI-30; 350_Klaaspakett: -
OverallHeight: 2400 mm; OverallWidth: 2000 mm
Pset_DoorCommon - FireExit: yes; SelfClosing: yes; HandicapAccessible: yes; Reference: 2000x2400mm EI30 laskuv lävep. 2
Pset_QuantityTakeOff - Reference: 2000x2400mm EI30 laskuv lävep. 2
AR_Uks - 365_Isesulguv: yes; 370_Evakuatsiooniväljapääs: yes; 360_Ratastooliga: yes; 003_Elemendi_staadium: Projekteeritud; 315_Avanemine: Parem; 355_Pindala: 11.2709 m2; 380_Lukustus: Vt. lukustuse projekti!; 455_Eriomadused: aktiivse ukselehe valgusava min.1050mm
SA_Uks - 365_Isesulguv: yes; 370_Evakuatsiooniväljapääs: yes; 360_Ratastooliga: yes; 001_Nimetus: Kahepoolne tumm uks KVTD pos.15 eeskujul; 003_Elemendi_staadium: Projekteeritud; 004_Lävepakk: Laskuv lävepakk; 005_Furnituur: Ukselink: VAL5_008E_NIS / VAL51_008E_NIS (evak.uksel), viimistlus: harjatud RST. Hinged: analoogsed olemasolevatele ustele, pulbervärvitud RAL 7039 (tume hall).; 300_Tüüp: SRR0788; 315_Avanemine: Parem; 320_Klaas: Puudub; 355_Pindala: 11.2709 m2; 375_Viimistlus_seest: Ukseleht, liistud ja leng spoonitud muinsuskaitse all olevate spoonitud ustega analoogse spooniga, mis toonida õlitatud pähkli tooni, lakkida mattlakiga. Viimistluspinnast esitada näidis!; 380_Lukustus: Vt. lukustuse projekti!; 900_Tootja: Jeld-Wen; 905_Mudel: Sile, puidust, spoonitud tuletõkkeuks
BaseQuantities - Height: 2400 mm; Width: 2000 mm; Area: 11.2709 m2

# IfcDoor: SMA_D02, 2-poolne:SU-00 - 1500x2100, SMA_D02, 2-poolne:SU-00 - 1500x2100:10952802
In: 1. korrus
Type - OperationType: DOUBLE_DOOR_SINGLE_SWING; ParameterTakesPrecedence: no; Sizeable: no; Material: EST. Metall. Plekk. Värvitud. RAL7023 (Concrete grey)
Type - SMA_D02, 2-poolne:SU-00 - 1500x2100:10952802:1 - PanelOperation: SWINGING
Type - Pset_ConcreteElementGeneral - FireRating: -
Type - Pset_DoorCommon - IsExternal: no; ThermalTransmittance: 0 kg/K/s3; FireRating: -; AcousticRating: 38dB
Type - AR_Uks - 000_Muinsuskaitse: no; 335_Välispiire: no; 340_Soojusläbivus: 0; 001_Nimetus: SU-00 - 1500x2100; 300_Tüüp: vt. SA infosisu sakki; 305_Ava_mõõt_laius: 1500 mm; 305_Ava_mõõt_korgus: 2100 mm; 310_Materjal: Puituks; 320_Klaas: vt. SA infosisu sakki; 325_Helipidavus: 38dB; 330_Tulekindlus: -; 350_Klaaspakett: -; 375_Viimistlus_seest: vt. SA infosisu sakki; 376_Viimistlus_väljast: vt. SA infosisu sakki
Type - SA_Uks - 000_Muinsuskaitse: no; 335_Välispiire: no; 340_Soojusläbivus: 0; 305_Ava_laius: 1500 mm; 305_Ava_kõrgus: 2100 mm; 310_Materjal: Puituks; 325_Helipidavus: 38dB; 330_Tulekindlus: -; 350_Klaaspakett: -
OverallHeight: 2100 mm; OverallWidth: 1500 mm
Pset_DoorCommon - SelfClosing: no; FireExit: yes; HandicapAccessible: yes; Reference: SU-00 - 1500x2100
Pset_QuantityTakeOff - Reference: SU-00 - 1500x2100
AR_Uks - 365_Isesulguv: no; 370_Evakuatsiooniväljapääs: yes; 360_Ratastooliga: yes; 003_Elemendi_staadium: Projekteeritud; 315_Avanemine: vasak; 355_Pindala: 7.67886 m2; 380_Lukustus: Vt. lukustuse projekti!; 455_Eriomadused: Aktiivse ukselehe valgusava min. 1050mm
SA_Uks - 365_Isesulguv: no; 370_Evakuatsiooniväljapääs: yes; 360_Ratastooliga: yes; 001_Nimetus: Kahepoolne tumm uks; 003_Elemendi_staadium: Projekteeritud; 004_Lävepakk: Laskuv lävepakk; 005_Furnituur: Ukselink: VAL32.544010_NIS, viimistlus: harjatud RST. Hinged: peithing; 300_Tüüp: SRR0224; 315_Avanemine: vasak; 320_Klaas: Puudub; 355_Pindala: 7.67886 m2; 375_Viimistlus_seest: Ukseleht, leng ja liist värvitud: RAL 7037 (tume hall).; 380_Lukustus: Vt. lukustuse projekti!; 900_Tootja: Eritellimusel; 905_Mudel: Sile värvitud puituks
BaseQuantities - Height: 2100 mm; Width: 1500 mm; Area: 7.67886 m2

# IfcDoor: SMA_D02, 2-poolne:ol. olev - 630x1020, SMA_D02, 2-poolne:ol. olev - 630x1020:1759973
In: 3. korrus
Type - ParameterTakesPrecedence: no; Sizeable: no; Material: EST. Metall. Plekk. Värvitud. RAL7023 (Concrete grey)
Type - Pset_ConcreteElementGeneral - FireRating: -
Type - Pset_DoorCommon - IsExternal: no; ThermalTransmittance: 0 kg/K/s3; FireRating: -; AcousticRating: -
Type - AR_Uks - 000_Muinsuskaitse: no; 335_Välispiire: no; 340_Soojusläbivus: 0; 001_Nimetus: ol. olev - 630x1020; 300_Tüüp: vt,SA infosisu sakki; 305_Ava_mõõt_laius: 630 mm; 305_Ava_mõõt_korgus: 1020 mm; 310_Materjal: Puituks; 320_Klaas: vt. SA infosisu sakki; 325_Helipidavus: -; 330_Tulekindlus: -; 350_Klaaspakett: -; 375_Viimistlus_seest: vt. SA infosisu sakki; 376_Viimistlus_väljast: vt. SA infosisu sakki
Type - SA_Uks - 000_Muinsuskaitse: no; 335_Välispiire: no; 340_Soojusläbivus: 0; 305_Ava_laius: 630 mm; 305_Ava_kõrgus: 1020 mm; 310_Materjal: Puituks; 325_Helipidavus: -; 330_Tulekindlus: -; 350_Klaaspakett: -
OverallHeight: 1020 mm; OverallWidth: 630 mm
Pset_DoorCommon - HandicapAccessible: no; Reference: ol. olev - 630x1020; FireExit: yes; SelfClosing: yes
Pset_QuantityTakeOff - Reference: ol. olev - 630x1020
AR_Uks - 360_Ratastooliga: no; 003_Elemendi_staadium: Projekteeritud; 315_Avanemine: kahepoolne; 355_Pindala: 1.88966 m2; 365_Isesulguv: yes; 370_Evakuatsiooniväljapääs: yes; 380_Lukustus: Vt. lukustuse projekti!; 455_Eriomadused: Luugitüüpi uks
SA_Uks - 360_Ratastooliga: no; 365_Isesulguv: yes; 370_Evakuatsiooniväljapääs: yes; 001_Nimetus: Kahepoolne tumm uks; 003_Elemendi_staadium: Projekteeritud; 004_Lävepakk: -; 005_Furnituur: Ukselink: VAL32.544010_NIS, viimistlus: harjatud RST. Fiskostar, toon sama mis lengil.; 300_Tüüp: SRR0805; 315_Avanemine: kahepoolne; 320_Klaas: Puudub; 355_Pindala: 1.88966 m2; 375_Viimistlus_seest: Ukseleht, leng ja liist värvitud: RAL 7037 (tume hall).; 380_Lukustus: Vt. lukustuse projekti!; 900_Tootja: Jeld-Wen; 905_Mudel: Sile värvitud puituks
BaseQuantities - Height: 1020 mm; Width: 630 mm; Area: 1.88966 m2

# IfcDoor: SMA_D03, jaotusega klaasseina uks:VU-12p, SMA_D03, jaotusega klaasseina uks:VU-12p:10357355
In: 3. korrus
Type - OperationType: DOUBLE_SWING_LEFT; ParameterTakesPrecedence: no; Sizeable: no; Material: EST. Metall. Teras. RAL9005, EST. Klaas. 3x. Default
Type - SMA_D03, jaotusega klaasseina uks:VU-12p:10357355:1 - PanelOperation: DOUBLE_ACTING
Type - Pset_ConcreteElementGeneral - FireRating: -
Type - Pset_DoorCommon - IsExternal: yes; FireExit: yes; SelfClosing: yes; FireRating: -; AcousticRating: 35dB; ThermalTransmittance: 1.2 kg/K/s3
Type - Pset_ManufacturerTypeInformation - Manufacturer: Aluprof
Type - AR_Uks - 000_Muinsuskaitse: no; 365_Isesulguv: yes; 370_Evakuatsiooniväljapääs: yes; 335_Välispiire: yes; 001_Nimetus: VU-12p; 300_Tüüp: VU-12; 310_Materjal: Alumiiniumprofiil; 320_Klaas: Toonitud peegelklaas, pronks; 325_Helipidavus: 35dB; 330_Tulekindlus: -; 340_Soojusläbivus: 1.2; 350_Klaaspakett: Toonklaas 10mm; 375_Viimistlus_seest: RAL 9005 (must); 376_Viimistlus_väljast: RAL 9005 (must); 900_Tootja: Aluprof; 905_Mudel: MB-104 Passive SI
Type - SA_Uks - 000_Muinsuskaitse: no; 365_Isesulguv: yes; 370_Evakuatsiooniväljapääs: yes; 335_Välispiire: yes; 310_Materjal: Alumiiniumprofiil; 325_Helipidavus: 35dB; 330_Tulekindlus: -; 340_Soojusläbivus: 1.2; 350_Klaaspakett: Toonklaas 10mm
Type - BIM - AR VU Sulgurid: Meh. sulgur
OverallHeight: 2254 mm; OverallWidth: 1220.16 mm
Pset_DoorCommon - HandicapAccessible: no; Reference: VU-12p
Pset_DoorWindowGlazingType - SolarHeatGainTransmittance: 0.4
Pset_QuantityTakeOff - Reference: VU-12p
AR_Uks - 360_Ratastooliga: no; 003_Elemendi_staadium: Projekteeritud; 305_Ava_mõõt_laius: 1220 mm; 305_Ava_mõõt_korgus: 2254 mm; 315_Avanemine: Parem; 345_Päiksekiirgus_tegur: 0.4; 355_Pindala: 2.74988 m2; 380_Lukustus: Vt. lukustuse projekti!
SA_Uks - 360_Ratastooliga: no; 001_Nimetus: VU-12p; 003_Elemendi_staadium: Projekteeritud; 004_Lävepakk: 20mm; 305_Ava_laius: 1220 mm; 305_Ava_kõrgus: 2254 mm; 315_Avanemine: Parem; 345_Päiksekiirgus_tegur: 0.4; 355_Pindala: 2.74988 m2; 380_Lukustus: Vt. lukustuse projekti!
BaseQuantities - Height: 2254 mm; Width: 1220 mm; Area: 2.74988 m2

# IfcDoor: SMA_D03, jaotusega klaasseina uks:VU-12p, SMA_D03, jaotusega klaasseina uks:VU-12p:10389267
In: 3. korrus
Type - OperationType: DOUBLE_SWING_LEFT; ParameterTakesPrecedence: no; Sizeable: no; Material: EST. Metall. Teras. RAL9005, EST. Klaas. 3x. Default
Type - SMA_D03, jaotusega klaasseina uks:VU-12p:10389267:1 - PanelOperation: DOUBLE_ACTING
Type - Pset_ConcreteElementGeneral - FireRating: -
Type - Pset_DoorCommon - IsExternal: yes; FireExit: yes; SelfClosing: yes; ThermalTransmittance: 1.2 kg/K/s3; FireRating: -; AcousticRating: 35dB
Type - Pset_ManufacturerTypeInformation - Manufacturer: Aluprof
Type - AR_Uks - 000_Muinsuskaitse: no; 365_Isesulguv: yes; 370_Evakuatsiooniväljapääs: yes; 335_Välispiire: yes; 001_Nimetus: VU-12p; 300_Tüüp: VU-12; 310_Materjal: Alumiiniumprofiil; 320_Klaas: Toonitud peegelklaas, pronks; 325_Helipidavus: 35dB; 330_Tulekindlus: -; 340_Soojusläbivus: 1.2; 350_Klaaspakett: Toonklaas 10mm; 375_Viimistlus_seest: RAL 9005 (must); 376_Viimistlus_väljast: RAL 9005 (must); 900_Tootja: Aluprof; 905_Mudel: MB-104 Passive SI
Type - SA_Uks - 000_Muinsuskaitse: no; 365_Isesulguv: yes; 370_Evakuatsiooniväljapääs: yes; 335_Välispiire: yes; 310_Materjal: Alumiiniumprofiil; 325_Helipidavus: 35dB; 330_Tulekindlus: -; 340_Soojusläbivus: 1.2; 350_Klaaspakett: Toonklaas 10mm
Type - BIM - AR VU Sulgurid: Meh. sulgur
OverallHeight: 2164 mm; OverallWidth: 1220.16 mm
Pset_DoorCommon - HandicapAccessible: no; Reference: VU-12p
Pset_DoorWindowGlazingType - SolarHeatGainTransmittance: 0.4
Pset_QuantityTakeOff - Reference: VU-12p
AR_Uks - 360_Ratastooliga: no; 003_Elemendi_staadium: Projekteeritud; 305_Ava_mõõt_laius: 1220 mm; 305_Ava_mõõt_korgus: 2164 mm; 315_Avanemine: Parem; 345_Päiksekiirgus_tegur: 0.4; 355_Pindala: 2.64008 m2; 380_Lukustus: Vt. lukustuse projekti!
SA_Uks - 360_Ratastooliga: no; 001_Nimetus: VU-12p; 003_Elemendi_staadium: Projekteeritud; 004_Lävepakk: 20mm; 305_Ava_laius: 1220 mm; 305_Ava_kõrgus: 2164 mm; 315_Avanemine: Parem; 345_Päiksekiirgus_tegur: 0.4; 355_Pindala: 2.64008 m2; 380_Lukustus: Vt. lukustuse projekti!
BaseQuantities - Height: 2164 mm; Width: 1220 mm; Area: 2.64008 m2

# IfcDoor: SMA_D03, jaotusega klaasseina uks:VU-12v, SMA_D03, jaotusega klaasseina uks:VU-12v:10357370
In: 3. korrus
Type - OperationType: SINGLE_SWING_RIGHT; ParameterTakesPrecedence: no; Sizeable: no; Material: EST. Metall. Teras. RAL9005, EST. Klaas. 3x. Default
Type - SMA_D03, jaotusega klaasseina uks:VU-12v:10357370:1 - PanelOperation: SWINGING
Type - Pset_ConcreteElementGeneral - FireRating: -
Type - Pset_DoorCommon - IsExternal: yes; FireExit: yes; SelfClosing: yes; ThermalTransmittance: 1.2 kg/K/s3; FireRating: -; AcousticRating: 35dB
Type - Pset_ManufacturerTypeInformation - Manufacturer: Aluprof
Type - AR_Uks - 000_Muinsuskaitse: no; 365_Isesulguv: yes; 370_Evakuatsiooniväljapääs: yes; 335_Välispiire: yes; 001_Nimetus: VU-12v; 300_Tüüp: VU-12; 310_Materjal: Alumiiniumprofiil; 320_Klaas: Toonitud peegelklaas, pronks; 325_Helipidavus: 35dB; 330_Tulekindlus: -; 340_Soojusläbivus: 1.2; 350_Klaaspakett: Toonklaas 10mm; 375_Viimistlus_seest: RAL 9005 (must); 376_Viimistlus_väljast: RAL 9005 (must); 900_Tootja: Aluprof; 905_Mudel: MB-104 Passive SI
Type - SA_Uks - 000_Muinsuskaitse: no; 365_Isesulguv: yes; 370_Evakuatsiooniväljapääs: yes; 335_Välispiire: yes; 310_Materjal: Alumiiniumprofiil; 325_Helipidavus: 35dB; 330_Tulekindlus: -; 340_Soojusläbivus: 1.2; 350_Klaaspakett: Toonklaas 10mm
Type - BIM - AR VU Sulgurid: Meh. sulgur
OverallHeight: 2240 mm; OverallWidth: 1220.16 mm
Pset_DoorCommon - HandicapAccessible: no; Reference: VU-12v
Pset_DoorWindowGlazingType - SolarHeatGainTransmittance: 0.4
Pset_QuantityTakeOff - Reference: VU-12v
AR_Uks - 360_Ratastooliga: no; 003_Elemendi_staadium: Projekteeritud; 305_Ava_mõõt_laius: 1220 mm; 305_Ava_mõõt_korgus: 2240 mm; 315_Avanemine: Vasak; 345_Päiksekiirgus_tegur: 0.4; 355_Pindala: 2.7328 m2; 380_Lukustus: Vt. lukustuse projekti!
SA_Uks - 360_Ratastooliga: no; 001_Nimetus: VU-12v; 003_Elemendi_staadium: Projekteeritud; 004_Lävepakk: 20mm; 300_Tüüp: 1194; 305_Ava_laius: 1220 mm; 305_Ava_kõrgus: 2240 mm; 315_Avanemine: Vasak; 345_Päiksekiirgus_tegur: 0.4; 355_Pindala: 2.7328 m2; 380_Lukustus: Vt. lukustuse projekti!
BaseQuantities - Height: 2240 mm; Width: 1220 mm; Area: 2.7328 m2

# IfcDoor: SMA_D03, jaotusega klaasseina uks:VU-12v, SMA_D03, jaotusega klaasseina uks:VU-12v:10389305
In: 3. korrus
Type - OperationType: SINGLE_SWING_RIGHT; ParameterTakesPrecedence: no; Sizeable: no; Material: EST. Metall. Teras. RAL9005, EST. Klaas. 3x. Default
Type - SMA_D03, jaotusega klaasseina uks:VU-12v:10389305:1 - PanelOperation: SWINGING
Type - Pset_ConcreteElementGeneral - FireRating: -
Type - Pset_DoorCommon - IsExternal: yes; FireExit: yes; SelfClosing: yes; ThermalTransmittance: 1.2 kg/K/s3; FireRating: -; AcousticRating: 35dB
Type - Pset_ManufacturerTypeInformation - Manufacturer: Aluprof
Type - AR_Uks - 000_Muinsuskaitse: no; 365_Isesulguv: yes; 370_Evakuatsiooniväljapääs: yes; 335_Välispiire: yes; 001_Nimetus: VU-12v; 300_Tüüp: VU-12; 310_Materjal: Alumiiniumprofiil; 320_Klaas: Toonitud peegelklaas, pronks; 325_Helipidavus: 35dB; 330_Tulekindlus: -; 340_Soojusläbivus: 1.2; 350_Klaaspakett: Toonklaas 10mm; 375_Viimistlus_seest: RAL 9005 (must); 376_Viimistlus_väljast: RAL 9005 (must); 900_Tootja: Aluprof; 905_Mudel: MB-104 Passive SI
Type - SA_Uks - 000_Muinsuskaitse: no; 365_Isesulguv: yes; 370_Evakuatsiooniväljapääs: yes; 335_Välispiire: yes; 310_Materjal: Alumiiniumprofiil; 325_Helipidavus: 35dB; 330_Tulekindlus: -; 340_Soojusläbivus: 1.2; 350_Klaaspakett: Toonklaas 10mm
Type - BIM - AR VU Sulgurid: Meh. sulgur
OverallHeight: 2150 mm; OverallWidth: 1220.16 mm
Pset_DoorCommon - HandicapAccessible: no; Reference: VU-12v
Pset_DoorWindowGlazingType - SolarHeatGainTransmittance: 0.4
Pset_QuantityTakeOff - Reference: VU-12v
AR_Uks - 360_Ratastooliga: no; 003_Elemendi_staadium: Projekteeritud; 305_Ava_mõõt_laius: 1220 mm; 305_Ava_mõõt_korgus: 2150 mm; 315_Avanemine: Vasak; 345_Päiksekiirgus_tegur: 0.4; 355_Pindala: 2.623 m2; 380_Lukustus: Vt. lukustuse projekti!
SA_Uks - 360_Ratastooliga: no; 001_Nimetus: VU-12v; 003_Elemendi_staadium: Projekteeritud; 004_Lävepakk: 20mm; 300_Tüüp: 1290; 305_Ava_laius: 1220 mm; 305_Ava_kõrgus: 2150 mm; 315_Avanemine: Vasak; 345_Päiksekiirgus_tegur: 0.4; 355_Pindala: 2.623 m2; 380_Lukustus: Vt. lukustuse projekti!
BaseQuantities - Height: 2150 mm; Width: 1220 mm; Area: 2.623 m2

# IfcDoor: SMA_hooldusluuk:hooldusluuk 600x600mm TTK, SMA_hooldusluuk:hooldusluuk 600x600mm TTK:16627925
In: 1. korrus
Type - ParameterTakesPrecedence: no; Sizeable: no; Material: EST. Metall. Alumiinium. Värvitud.
Type - Pset_ConcreteElementGeneral - FireRating: EI-60
Type - Pset_DoorCommon - IsExternal: no; ThermalTransmittance: 0 kg/K/s3; FireExit: no; SelfClosing: no; FireRating: EI-60; AcousticRating: -
Type - AR_Uks - 000_Muinsuskaitse: no; 335_Välispiire: no; 340_Soojusläbivus: 0; 365_Isesulguv: no; 370_Evakuatsiooniväljapääs: no; 001_Nimetus: hooldusluuk 600x600mm TTK; 300_Tüüp: Hooldusluuk 600x600mm, h=50mm põrandast; 305_Ava_mõõt_laius: 600 mm; 305_Ava_mõõt_korgus: 600 mm; 310_Materjal: Terasplekk; 320_Klaas: -; 325_Helipidavus: -; 330_Tulekindlus: EI-60; 350_Klaaspakett: -; 375_Viimistlus_seest: vt. SA infosisu sakki; 376_Viimistlus_väljast: vt. SA infosisu sakki; 380_Lukustus: Tootepõhine lukustus.; 905_Mudel: -
Type - SA_Uks - 000_Muinsuskaitse: no; 335_Välispiire: no; 340_Soojusläbivus: 0; 365_Isesulguv: no; 370_Evakuatsiooniväljapääs: no; 305_Ava_laius: 600 mm; 305_Ava_kõrgus: 600 mm; 310_Materjal: Terasplekk; 325_Helipidavus: -; 330_Tulekindlus: EI-60; 350_Klaaspakett: -; 380_Lukustus: Tootepõhine lukustus.
OverallHeight: 600 mm; OverallWidth: 600 mm
Pset_DoorCommon - HandicapAccessible: no; Reference: hooldusluuk 600x600mm TTK
Pset_QuantityTakeOff - Reference: hooldusluuk 600x600mm TTK
AR_Uks - 360_Ratastooliga: no; 003_Elemendi_staadium: Projekteeritud; 315_Avanemine: vask; 355_Pindala: 1.03421 m2; 455_Eriomadused: -
SA_Uks - 360_Ratastooliga: no; 001_Nimetus: Hooldusluuk; 003_Elemendi_staadium: Projekteeritud; 004_Lävepakk: Tihendid vastavalt tootele; 005_Furnituur: Vastavalt tootele; 300_Tüüp: SRR0529; 315_Avanemine: vask; 320_Klaas: Puudub; 355_Pindala: 1.03421 m2; 375_Viimistlus_seest: Pulbervärvitakse plaaditud seinaga analoogset tooni; 900_Tootja: Karlbilder; 905_Mudel: Terasplekist tuletõkkeluuk
BaseQuantities - Height: 600 mm; Width: 600 mm; Area: 1.03421 m2

# IfcDoor: VLS Klaasseina KVTD uks:uus MKU-15 eeskujul - 900x2100 2, VLS Klaasseina KVTD uks:uus MKU-15 eeskujul - 900x2100 2:13919257
In: 1. korrus
Type - OperationType: SINGLE_SWING_LEFT; ParameterTakesPrecedence: no; Sizeable: no; Classification: B2030100 Uniformat (Uniformat); Material: Aluminum, Wood
Type - VLS Klaasseina KVTD uks:uus MKU-15 eeskujul - 900x2100 2:13919257:1 - PanelOperation: SWINGING
Type - Pset_ConcreteElementGeneral - FireRating: -
Type - Pset_DoorCommon - IsExternal: no; ThermalTransmittance: 0 kg/K/s3; FireExit: no; SelfClosing: yes; FireRating: -; AcousticRating: 38dB
Type - AR_Uks - 000_Muinsuskaitse: no; 335_Välispiire: no; 340_Soojusläbivus: 0; 370_Evakuatsiooniväljapääs: no; 365_Isesulguv: yes; 001_Nimetus: uus MKU-15 eeskujul - 900x2100 2; 300_Tüüp: vt. SA infosisu sakki; 310_Materjal: Puituks alumiinium portaalis. Uks ja portaal on klaasvaheseina osa.; 320_Klaas: vt. SA infosisu sakki; 325_Helipidavus: 38dB; 330_Tulekindlus: -; 350_Klaaspakett: -; 375_Viimistlus_seest: vt. SA infosisu sakki; 376_Viimistlus_väljast: vt. SA infosisu sakki
Type - SA_Uks - 000_Muinsuskaitse: no; 335_Välispiire: no; 340_Soojusläbivus: 0; 370_Evakuatsiooniväljapääs: no; 365_Isesulguv: yes; 310_Materjal: Puituks alumiinium portaalis. Uks ja portaal on klaasvaheseina osa.; 325_Helipidavus: 38dB; 330_Tulekindlus: -; 350_Klaaspakett: -
OverallHeight: 2300 mm; OverallWidth: 900 mm
Pset_DoorCommon - HandicapAccessible: yes; Reference: uus MKU-15 eeskujul - 900x2100 2
Pset_QuantityTakeOff - Reference: uus MKU-15 eeskujul - 900x2100 2
AR_Uks - 360_Ratastooliga: yes; 003_Elemendi_staadium: Projekteeritud; 305_Ava_mõõt_laius: 900 mm; 305_Ava_mõõt_korgus: 2300 mm; 315_Avanemine: parem; 355_Pindala: 2.07 m2; 380_Lukustus: Vt. lukustuse projekti!; 455_Eriomadused: -
SA_Uks - 360_Ratastooliga: yes; 001_Nimetus: Ühepoolne tumm uks KVTD pos.15 eeskujul; 003_Elemendi_staadium: Projekteeritud; 004_Lävepakk: Laskuv lävepakk; 005_Furnituur: Ukselink: VAL5_008E_NIS / VAL51_008E_NIS (evak.uksel), viimistlus: harjatud RST. Hinged: Structo tavahing; 300_Tüüp: SRR1068; 305_Ava_laius: 900 mm; 305_Ava_kõrgus: 2300 mm; 315_Avanemine: parem; 320_Klaas: Puudub; 355_Pindala: 2.07 m2; 375_Viimistlus_seest: Ukseleht, liistud ja leng spoonitud muinsuskaitse all olevate spoonitud ustega analoogse spooniga, mis toonida õlitatud pähkli tooni, lakkida mattlakiga. Viimistluspinnast esitada näidis!; 380_Lukustus: Vt. lukustuse projekti!; 900_Tootja: Structo; 905_Mudel: Spoonitud sile uks laeni alumiiniumportaalis
BaseQuantities - Height: 2300 mm; Width: 900 mm; Area: 2.07 m2

# IfcFurnishingElement: MA_Hepta prügikast:MA_Hepta prügikast (2)
In: 1. korrus
Type - Material: <Unnamed>
Type - AR - 001_Nimetus: MA_Hepta prügikast; 205_Tüüp: VV15
Pset_QuantityTakeOff - Reference: MA_Hepta prügikast
AR - 002_Elemendi_staadium: Projekteeritud
Name (MA_Hepta prügikast:MA_Hepta prügikast:...)
12536847
12536849

# IfcFurnishingElement: MA_Kohvikulaud:MA_Kohvikulaud (8)
In: 1. korrus
Type - Material: <Unnamed>
Type - AR - 001_Nimetus: MA_Kohvikulaud; 205_Tüüp: VV6
Pset_QuantityTakeOff - Reference: MA_Kohvikulaud
AR - 002_Elemendi_staadium: Projekteeritud
Name (MA_Kohvikulaud:MA_Kohvikulaud:...)
11999291
11999292
11999293
11999294
11999353
11999356
11999359
11999362

# IfcFurnishingElement: MA_Kohvikultool:MA_Kohvikultool (20)
In: 1. korrus
Type - Material: <Unnamed>
Type - AR - 001_Nimetus: MA_Kohvikultool; 205_Tüüp: VV7
Pset_QuantityTakeOff - Reference: MA_Kohvikultool
AR - 002_Elemendi_staadium: Projekteeritud
Name (MA_Kohvikultool:MA_Kohvikultool:...)
11999295
11999296
11999297
11999298
11999299
11999300
11999301
11999302
11999303
11999304
11999354
11999355
11999357
11999358
11999360
11999361
11999363
11999364
11999372
11999373

# IfcFurnishingElement: MA_Lillekast ümar:MA_Lillekast ümar d-700mm (4)
In: 1. korrus
Type - Material: <Unnamed>
Type - AR - 001_Nimetus: MA_Lillekast ümar d-700mm; 205_Tüüp: VV16
Pset_QuantityTakeOff - Reference: MA_Lillekast ümar d-700mm
AR - 002_Elemendi_staadium: Projekteeritud
Name (MA_Lillekast ümar:MA_Lillekast ümar d-700mm:...)
12536851
12536852
12536853
12536854

# IfcMember: Rectangular Mullion:250mm x 92mm PAREM (2)
In: 1. korrus
Type - PredefinedType: MULLION; Material: Aluminum
Type - Pset_MemberCommon - IsExternal: no
Pset_MemberCommon - Reference: 250mm x 92mm PAREM; Span: 2300 mm
Pset_QuantityTakeOff - Reference: 250mm x 92mm PAREM
BaseQuantities - Length: 2300 mm; CrossSectionArea: 0.8096 m2; NetVolume: 0.0529 m3; NetSurfaceArea: 1.6192 m2
Name (Rectangular Mullion:250mm x 92mm PAREM:...)
13879999
13880347

# IfcMember: Rectangular Mullion:250mm x 92mm VASAK (4)
In: 1. korrus
Type - PredefinedType: MULLION; Material: Aluminum
Type - Pset_MemberCommon - IsExternal: no
Pset_MemberCommon - Reference: 250mm x 92mm VASAK
Pset_QuantityTakeOff - Reference: 250mm x 92mm VASAK
Name (Rectangular Mullion:250mm x 92mm VASAK:...) | Span (mm) = Length (mm) | CrossSectionArea (m2) | NetVolume (m3) | NetSurfaceArea (m2)
13879871 | 2300 | 0.8096 | 0.0529 | 1.6192
13880383 | 2300 | 0.8096 | 0.0529 | 1.6192
13880113 | 2050 | 0.7241 | 0.04715 | 1.4482
13919912 | 2300 | 0.8096 | 0.0529 | 1.6192

# IfcMember: Rectangular Mullion:30mm Square (56)
In: 1. korrus
Type - PredefinedType: MULLION; Material: <Unnamed>
Type - Pset_MemberCommon - IsExternal: no
Pset_MemberCommon - Reference: 30mm Square
Pset_QuantityTakeOff - Reference: 30mm Square
Name (Rectangular Mullion:30mm Square:...) | Span (mm) = Length (mm) | CrossSectionArea (m2) | NetVolume (m3) | NetSurfaceArea (m2)
4455773 | 2200 | 0.1329 | 0.00198 | 0.2658 | Pset_MemberCommon - IsExternal: yes
4455774 | 2200 | 0.1329 | 0.00198 | 0.2658 | Pset_MemberCommon - IsExternal: yes
4455775 | 2200 | 0.1329 | 0.00198 | 0.2658 | Pset_MemberCommon - IsExternal: yes
4455776 | 2200 | 0.1329 | 0.00198 | 0.2658 | Pset_MemberCommon - IsExternal: yes
4455777 | 2200 | 0.1329 | 0.00198 | 0.2658 | Pset_MemberCommon - IsExternal: yes
4455778 | 2200 | 0.1329 | 0.00198 | 0.2658 | Pset_MemberCommon - IsExternal: yes
4455779 | 2200 | 0.1329 | 0.00198 | 0.2658 | Pset_MemberCommon - IsExternal: yes
4455780 | 2200 | 0.1329 | 0.00198 | 0.2658 | Pset_MemberCommon - IsExternal: yes
4455781 | 2200 | 0.1329 | 0.00198 | 0.2658 | Pset_MemberCommon - IsExternal: yes
4455782 | 2200 | 0.1329 | 0.00198 | 0.2658 | Pset_MemberCommon - IsExternal: yes
4455783 | 2200 | 0.1329 | 0.00198 | 0.2658 | Pset_MemberCommon - IsExternal: yes
4455784 | 2200 | 0.1329 | 0.00198 | 0.2658 | Pset_MemberCommon - IsExternal: yes
4455785 | 2200 | 0.1329 | 0.00198 | 0.2658 | Pset_MemberCommon - IsExternal: yes
4455786 | 2200 | 0.1329 | 0.00198 | 0.2658 | Pset_MemberCommon - IsExternal: yes
4455787 | 2200 | 0.1329 | 0.00198 | 0.2658 | Pset_MemberCommon - IsExternal: yes
4455788 | 2200 | 0.1329 | 0.00198 | 0.2658 | Pset_MemberCommon - IsExternal: yes
4455789 | 2200 | 0.1329 | 0.00198 | 0.2658 | Pset_MemberCommon - IsExternal: yes
4455790 | 2200 | 0.1329 | 0.00198 | 0.2658 | Pset_MemberCommon - IsExternal: yes
4455791 | 2200 | 0.1329 | 0.00198 | 0.2658 | Pset_MemberCommon - IsExternal: yes
4455792 | 2200 | 0.1329 | 0.00198 | 0.2658 | Pset_MemberCommon - IsExternal: yes
4455793 | 2200 | 0.1329 | 0.00198 | 0.2658 | Pset_MemberCommon - IsExternal: yes
4455794 | 2134.93 | 0.128996 | 0.00192144 | 0.257992 | Pset_MemberCommon - IsExternal: yes
4455795 | 1990.17 | 0.12031 | 0.00179115 | 0.24062 | Pset_MemberCommon - IsExternal: yes
4455796 | 1828.56 | 0.110614 | 0.0016457 | 0.221227 | Pset_MemberCommon - IsExternal: yes
4455797 | 1645.14 | 0.0996082 | 0.00148062 | 0.199216 | Pset_MemberCommon - IsExternal: yes
4455798 | 1431.55 | 0.0867928 | 0.00128839 | 0.173586 | Pset_MemberCommon - IsExternal: yes
4455799 | 1171.4 | 0.0711839 | 0.00105426 | 0.142368 | Pset_MemberCommon - IsExternal: yes
4455800 | 821.597 | 0.0501958 | 0.000739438 | 0.100392 | Pset_MemberCommon - IsExternal: yes
4455672 | 2200 | 0.1329 | 0.00198 | 0.2658
4455673 | 2200 | 0.1329 | 0.00198 | 0.2658
4455674 | 2200 | 0.1329 | 0.00198 | 0.2658
4455675 | 2200 | 0.1329 | 0.00198 | 0.2658
4455676 | 2200 | 0.1329 | 0.00198 | 0.2658
4455677 | 2200 | 0.1329 | 0.00198 | 0.2658
4455678 | 2200 | 0.1329 | 0.00198 | 0.2658
4455679 | 2200 | 0.1329 | 0.00198 | 0.2658
4455680 | 2200 | 0.1329 | 0.00198 | 0.2658
4455681 | 2200 | 0.1329 | 0.00198 | 0.2658
4455682 | 2200 | 0.1329 | 0.00198 | 0.2658
4455683 | 2200 | 0.1329 | 0.00198 | 0.2658
4455684 | 2200 | 0.1329 | 0.00198 | 0.2658
4455685 | 2200 | 0.1329 | 0.00198 | 0.2658
4455689 | 2200 | 0.1329 | 0.00198 | 0.2658
4455690 | 2200 | 0.1329 | 0.00198 | 0.2658
4455691 | 2200 | 0.1329 | 0.00198 | 0.2658
4455692 | 2200 | 0.1329 | 0.00198 | 0.2658
4455693 | 2200 | 0.1329 | 0.00198 | 0.2658
4455694 | 2200 | 0.1329 | 0.00198 | 0.2658
4455695 | 2200 | 0.1329 | 0.00198 | 0.2658
4455696 | 2134.93 | 0.128996 | 0.00192144 | 0.257992
4455697 | 1990.17 | 0.12031 | 0.00179115 | 0.24062
4455698 | 1828.56 | 0.110614 | 0.0016457 | 0.221227
4455699 | 1645.14 | 0.0996082 | 0.00148062 | 0.199216
4455700 | 1431.55 | 0.0867928 | 0.00128839 | 0.173586
4455701 | 1171.4 | 0.0711839 | 0.00105426 | 0.142368
4455702 | 821.597 | 0.0501958 | 0.000739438 | 0.100392

# IfcMember: Rectangular Mullion:50mm x 92mm (169)
Type - PredefinedType: MULLION; Material: Aluminum
Type - Pset_MemberCommon - IsExternal: no
Pset_MemberCommon - Reference: 50mm x 92mm
Pset_QuantityTakeOff - Reference: 50mm x 92mm
Name (Rectangular Mullion:50mm x 92mm:...) | In | Span (mm) = Length (mm) | CrossSectionArea (m2) | NetVolume (m3) | NetSurfaceArea (m2)
2388852 | 1. korrus | 1042 | 0.152564 | 0.0047932 | 0.300528
2388853 | 1. korrus | 2400 | 0.3454 | 0.01104 | 0.6908
2388854 | 1. korrus | 2300 | 0.3312 | 0.01058 | 0.6624
7887789 | 1. korrus | 1042 | 0.152564 | 0.0047932 | 0.295928
7887790 | 1. korrus | 876 | 0.128992 | 0.0040296 | 0.253384
7887791 | 1. korrus | 1042 | 0.152564 | 0.0047932 | 0.300528
7887792 | 1. korrus | 1042 | 0.152564 | 0.0047932 | 0.295928
7887795 | 1. korrus | 876 | 0.128992 | 0.0040296 | 0.253384
2388860 | 1. korrus | 3143.08 | 0.450918 | 0.0144582 | 0.901836
2388861 | 1. korrus | 2090.92 | 0.30151 | 0.00961822 | 0.60302
2388862 | 1. korrus | 2300 | 0.3312 | 0.01058 | 0.6624
2388863 | 1. korrus | 2300 | 0.3312 | 0.01058 | 0.6624
7887802 | 1. korrus | 2090.92 | 0.30151 | 0.00961822 | 0.60302
7887803 | 1. korrus | 3143.08 | 0.450918 | 0.0144582 | 0.901836
2388977 | 1. korrus | 745 | 0.11039 | 0.003427 | 0.21618
2388978 | 1. korrus | 1070 | 0.15654 | 0.004922 | 0.30848
2388979 | 1. korrus | 2350 | 0.3383 | 0.01081 | 0.6766
2388980 | 1. korrus | 2300 | 0.3312 | 0.01058 | 0.6624
7887807 | 1. korrus | 1070 | 0.15654 | 0.004922 | 0.30848
7887808 | 1. korrus | 1070 | 0.15654 | 0.004922 | 0.30388
7887809 | 1. korrus | 1070 | 0.15654 | 0.004922 | 0.30388
7887810 | 1. korrus | 795 | 0.11749 | 0.003657 | 0.23038
3977819 | 1. korrus | 978.625 | 0.143565 | 0.00450167 | 0.282529
3977820 | 1. korrus | 2400 | 0.3454 | 0.01104 | 0.6908
3977821 | 1. korrus | 2300 | 0.3312 | 0.01058 | 0.6624
7887856 | 1. korrus | 978.625 | 0.143565 | 0.00450167 | 0.277929
7887857 | 1. korrus | 1377.72 | 0.200236 | 0.0063375 | 0.395872
7887859 | 1. korrus | 1377.72 | 0.200236 | 0.0063375 | 0.395872
7887861 | 1. korrus | 978.625 | 0.143565 | 0.00450167 | 0.282529
7887862 | 1. korrus | 978.625 | 0.143565 | 0.00450167 | 0.277929
3977825 | 1. korrus | 1025.36 | 0.150201 | 0.00471665 | 0.295802
3977827 | 1. korrus | 2300 | 0.3312 | 0.01058 | 0.6624
3977828 | 1. korrus | 2400 | 0.3454 | 0.01104 | 0.6908
7887864 | 1. korrus | 1084.28 | 0.158568 | 0.0049877 | 0.312536
7887865 | 1. korrus | 1025.36 | 0.150201 | 0.00471665 | 0.291202
7887868 | 1. korrus | 1084.28 | 0.158568 | 0.0049877 | 0.312536
7887870 | 1. korrus | 1025.36 | 0.150201 | 0.00471665 | 0.291202
7887871 | 1. korrus | 1025.36 | 0.150201 | 0.00471665 | 0.295802
13282657 | 1. korrus | 868 | 0.127856 | 0.0039928 | 0.251112
13282658 | 1. korrus | 866 | 0.127572 | 0.0039836 | 0.250544
13282659 | 1. korrus | 2300 | 0.3312 | 0.01058 | 0.6624
13282660 | 1. korrus | 2300 | 0.3312 | 0.01058 | 0.6624
13285765 | 1. korrus | 866 | 0.127572 | 0.0039836 | 0.250544
13285766 | 1. korrus | 866 | 0.127572 | 0.0039836 | 0.245944
13285865 | 1. korrus | 866 | 0.127572 | 0.0039836 | 0.245944
13285866 | 1. korrus | 868 | 0.127856 | 0.0039928 | 0.251112
6869793 | 1. korrus | 902.5 | 0.132755 | 0.0041515 | 0.26091
6869794 | 1. korrus | 668 | 0.099456 | 0.0030728 | 0.194312
6869795 | 1. korrus | 877.5 | 0.129205 | 0.0040365 | 0.24921
6869796 | 1. korrus | 925 | 0.13595 | 0.004255 | 0.2627
6869797 | 1. korrus | 877.5 | 0.129205 | 0.0040365 | 0.24921
6869798 | 1. korrus | 668 | 0.099456 | 0.0030728 | 0.194312
6869799 | 1. korrus | 877.5 | 0.129205 | 0.0040365 | 0.24921
6869800 | 1. korrus | 877.5 | 0.129205 | 0.0040365 | 0.24921
6869801 | 1. korrus | 902.5 | 0.132755 | 0.0041515 | 0.26091
6869802 | 1. korrus | 2300 | 0.3312 | 0.01058 | 0.6624
6869803 | 1. korrus | 2300 | 0.3312 | 0.01058 | 0.6624
6869806 | 1. korrus | 925 | 0.13595 | 0.004255 | 0.2627
13265270 | 1. korrus | 925 | 0.13595 | 0.004255 | 0.2627
13265271 | 1. korrus | 925 | 0.13595 | 0.004255 | 0.2627
6965726 | 2. korrus | 1011.67 | 0.148257 | 0.00465367 | 0.291913
6965727 | 2. korrus | 1140 | 0.16648 | 0.005244 | 0.32836
6965728 | 2. korrus | 1140 | 0.16648 | 0.005244 | 0.32376
6965729 | 2. korrus | 1140 | 0.16648 | 0.005244 | 0.32836
6965730 | 2. korrus | 1140 | 0.16648 | 0.005244 | 0.32376
6965731 | 2. korrus | 1140 | 0.16648 | 0.005244 | 0.32376
6965732 | 2. korrus | 2300 | 0.3312 | 0.01058 | 0.6624
6965733 | 2. korrus | 2300 | 0.3312 | 0.01058 | 0.6624
6965773 | 2. korrus | 1140 | 0.16648 | 0.005244 | 0.32376
6965774 | 2. korrus | 1140 | 0.16648 | 0.005244 | 0.32376
6965775 | 2. korrus | 1140 | 0.16648 | 0.005244 | 0.32376
6965776 | 2. korrus | 128.333 | 0.0228233 | 0.000590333 | 0.0364467
10329053 | 2. korrus | 128.333 | 0.0228233 | 0.000590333 | 0.0364467
10329054 | 2. korrus | 1011.67 | 0.148257 | 0.00465367 | 0.291913
10323836 | 2. korrus | 803.333 | 0.118673 | 0.00369533 | 0.232747
10323837 | 2. korrus | 568.833 | 0.0853743 | 0.00261663 | 0.166149
10323838 | 2. korrus | 803.333 | 0.118673 | 0.00369533 | 0.228147
10323839 | 2. korrus | 568.833 | 0.0853743 | 0.00261663 | 0.166149
10323840 | 2. korrus | 803.333 | 0.118673 | 0.00369533 | 0.228147
10323841 | 2. korrus | 803.333 | 0.118673 | 0.00369533 | 0.232747
10323842 | 2. korrus | 2300 | 0.3312 | 0.01058 | 0.6624
10323843 | 2. korrus | 2300 | 0.3312 | 0.01058 | 0.6624
10323850 | 2. korrus | 845.25 | 0.124626 | 0.00388815 | 0.244651
10323851 | 2. korrus | 840.084 | 0.123892 | 0.00386439 | 0.243184
10323852 | 2. korrus | 840 | 0.12388 | 0.003864 | 0.23856
10323853 | 2. korrus | 840.084 | 0.123892 | 0.00386439 | 0.243184
10323854 | 2. korrus | 840 | 0.12388 | 0.003864 | 0.23856
10323855 | 2. korrus | 845.25 | 0.124626 | 0.00388815 | 0.244651
10323856 | 2. korrus | 2300 | 0.3312 | 0.01058 | 0.6624
10323857 | 2. korrus | 2300 | 0.3312 | 0.01058 | 0.6624
10323868 | 2. korrus | 1082 | 0.158244 | 0.0049772 | 0.311888
10323869 | 2. korrus | 847.481 | 0.124942 | 0.00389841 | 0.245285
10323870 | 2. korrus | 1082 | 0.158244 | 0.0049772 | 0.307288
10323871 | 2. korrus | 1082 | 0.158244 | 0.0049772 | 0.307288
10323872 | 2. korrus | 1082 | 0.158244 | 0.0049772 | 0.307288
10323873 | 2. korrus | 847.481 | 0.124942 | 0.00389841 | 0.245285
10323874 | 2. korrus | 1082 | 0.158244 | 0.0049772 | 0.307288
10323875 | 2. korrus | 1082 | 0.158244 | 0.0049772 | 0.307288
10323876 | 2. korrus | 1082 | 0.158244 | 0.0049772 | 0.307288
10323877 | 2. korrus | 1082 | 0.158244 | 0.0049772 | 0.311888
10323878 | 2. korrus | 2300 | 0.3312 | 0.01058 | 0.6624
10323879 | 2. korrus | 2300 | 0.3312 | 0.01058 | 0.6624
10323888 | 2. korrus | 816.667 | 0.120567 | 0.00375667 | 0.236533
10323889 | 2. korrus | 582.167 | 0.0872677 | 0.00267797 | 0.169935
10323890 | 2. korrus | 816.667 | 0.120567 | 0.00375667 | 0.231933
10323891 | 2. korrus | 582.167 | 0.0872677 | 0.00267797 | 0.169935
10323892 | 2. korrus | 816.667 | 0.120567 | 0.00375667 | 0.231933
10323893 | 2. korrus | 816.667 | 0.120567 | 0.00375667 | 0.236533
10323894 | 2. korrus | 2300 | 0.3312 | 0.01058 | 0.6624
10323895 | 2. korrus | 2300 | 0.3312 | 0.01058 | 0.6624
10323902 | 2. korrus | 866.667 | 0.127667 | 0.00398667 | 0.250733
10323903 | 2. korrus | 866.667 | 0.127667 | 0.00398667 | 0.250733
10323904 | 2. korrus | 866.667 | 0.127667 | 0.00398667 | 0.246133
10323905 | 2. korrus | 866.667 | 0.127667 | 0.00398667 | 0.250733
10323906 | 2. korrus | 866.667 | 0.127667 | 0.00398667 | 0.246133
10323907 | 2. korrus | 866.667 | 0.127667 | 0.00398667 | 0.250733
10323908 | 2. korrus | 2300 | 0.3312 | 0.01058 | 0.6624
10323909 | 2. korrus | 2300 | 0.3312 | 0.01058 | 0.6624
13277711 | 1. korrus | 1450 | 0.2105 | 0.00667 | 0.421
13277712 | 1. korrus | 1450 | 0.2105 | 0.00667 | 0.421
13277713 | 1. korrus | 2150 | 0.3099 | 0.00989 | 0.6198
13277714 | 1. korrus | 2150 | 0.3099 | 0.00989 | 0.6198
13278704 | 1. korrus | 600 | 0.0898 | 0.00276 | 0.1796
13278705 | 1. korrus | 2150 | 0.3099 | 0.00989 | 0.6198
13278706 | 1. korrus | 2050 | 0.2957 | 0.00943 | 0.5914
13278725 | 1. korrus | 600 | 0.0898 | 0.00276 | 0.1796
13284502 | 1. korrus | 1080 | 0.15796 | 0.004968 | 0.31132
13284503 | 1. korrus | 845.5 | 0.124661 | 0.0038893 | 0.244722
13284504 | 1. korrus | 2300 | 0.3312 | 0.01058 | 0.6624
13284505 | 1. korrus | 2300 | 0.3312 | 0.01058 | 0.6624
13285292 | 1. korrus | 845.5 | 0.124661 | 0.0038893 | 0.244722
13285293 | 1. korrus | 1080 | 0.15796 | 0.004968 | 0.30672
13285354 | 1. korrus | 1080 | 0.15796 | 0.004968 | 0.30672
13285355 | 1. korrus | 1080 | 0.15796 | 0.004968 | 0.30672
13285453 | 1. korrus | 1080 | 0.15796 | 0.004968 | 0.30672
13285454 | 1. korrus | 1080 | 0.15796 | 0.004968 | 0.30672
13285568 | 1. korrus | 1080 | 0.15796 | 0.004968 | 0.30672
13285569 | 1. korrus | 1080 | 0.15796 | 0.004968 | 0.31132
13321294 | 1. korrus | 1040 | 0.15228 | 0.004784 | 0.29996
13321295 | 1. korrus | 1033 | 0.151286 | 0.0047518 | 0.297972
13321296 | 1. korrus | 2300 | 0.3312 | 0.01058 | 0.6624
13321297 | 1. korrus | 2300 | 0.3312 | 0.01058 | 0.6624
13321300 | 1. korrus | 1033 | 0.151286 | 0.0047518 | 0.297972
13321301 | 1. korrus | 1033 | 0.151286 | 0.0047518 | 0.293372
13321304 | 1. korrus | 1033 | 0.151286 | 0.0047518 | 0.293372
13321305 | 1. korrus | 1033 | 0.151286 | 0.0047518 | 0.293372
13321308 | 1. korrus | 1033 | 0.151286 | 0.0047518 | 0.293372
13321309 | 1. korrus | 1033 | 0.151286 | 0.0047518 | 0.293372
13321312 | 1. korrus | 1033 | 0.151286 | 0.0047518 | 0.293372
13321313 | 1. korrus | 1033 | 0.151286 | 0.0047518 | 0.293372
13321368 | 1. korrus | 1033 | 0.151286 | 0.0047518 | 0.293372
13321369 | 1. korrus | 1040 | 0.15228 | 0.004784 | 0.29996
13918888 | 1. korrus | 510 | 0.07702 | 0.002346 | 0.14944
13918889 | 1. korrus | 865.5 | 0.127501 | 0.0039813 | 0.250402
13918890 | 1. korrus | 2300 | 0.3312 | 0.01058 | 0.6624
13918891 | 1. korrus | 2300 | 0.3312 | 0.01058 | 0.6624
13919131 | 1. korrus | 800 | 0.1182 | 0.00368 | 0.2272
13919132 | 1. korrus | 510 | 0.07702 | 0.002346 | 0.14944
13919176 | 1. korrus | 865.5 | 0.127501 | 0.0039813 | 0.250402
13919177 | 1. korrus | 800 | 0.1182 | 0.00368 | 0.2272
13918995 | 1. korrus | 975 | 0.14305 | 0.004485 | 0.2815
13918996 | 1. korrus | 675 | 0.10045 | 0.003105 | 0.1963
13918997 | 1. korrus | 2300 | 0.3312 | 0.01058 | 0.6624
13918998 | 1. korrus | 2300 | 0.3312 | 0.01058 | 0.6624
13919264 | 1. korrus | 675 | 0.10045 | 0.003105 | 0.1963
13919265 | 1. korrus | 950 | 0.1395 | 0.00437 | 0.2698
13919317 | 1. korrus | 950 | 0.1395 | 0.00437 | 0.2698
13919318 | 1. korrus | 975 | 0.14305 | 0.004485 | 0.2815
13919921 | 1. korrus | 2300 | 0.3312 | 0.01058 | 0.6624

# IfcMember: Rectangular Mullion:NEW 10x90mm (11)
In: 1. korrus
Type - PredefinedType: MULLION; Material: Lumion_aluminium
Type - Pset_MemberCommon - IsExternal: no
Pset_MemberCommon - Reference: NEW 10x90mm; Span: 850 mm
Pset_QuantityTakeOff - Reference: NEW 10x90mm
BaseQuantities - Length: 850 mm; CrossSectionArea: 0.0859 m2; NetVolume: 0.000765 m3; NetSurfaceArea: 0.1718 m2
Name (Rectangular Mullion:NEW 10x90mm:...)
10533007 | Pset_MemberCommon - IsExternal: yes
10533115
10533223
10533331
10533439
10533547
10533655
10533763
10533871
10533979
10534087

# IfcMember: Rectangular Mullion:NEW 150x90mm (84)
Type - PredefinedType: MULLION; Material: LUMION_dark steel window frames
Type - Pset_MemberCommon - IsExternal: no
Pset_MemberCommon - Reference: NEW 150x90mm
Pset_QuantityTakeOff - Reference: NEW 150x90mm
Name (Rectangular Mullion:NEW 150x90mm:...) | In | Span (mm) = Length (mm) | CrossSectionArea (m2) | NetVolume (m3) | NetSurfaceArea (m2)
10386043 | 3. korrus | 450 | 0.1204 | 0.00558 | 0.2284 | Pset_MemberCommon - IsExternal: yes
10386044 | 3. korrus | 1550 | 0.366291 | 0.0182977 | 0.720181 | Pset_MemberCommon - IsExternal: yes
10389363 | 3. korrus | 450 | 0.1204 | 0.00558 | 0.2284
10389364 | 3. korrus | 1550 | 0.3844 | 0.01922 | 0.7564
10389382 | 3. korrus | 450 | 0.1204 | 0.00558 | 0.2284
10389383 | 3. korrus | 1550 | 0.3844 | 0.01922 | 0.7564
10389401 | 3. korrus | 450 | 0.1204 | 0.00558 | 0.2284
10389402 | 3. korrus | 1550 | 0.3844 | 0.01922 | 0.7564
10389454 | 3. korrus | 450 | 0.1204 | 0.00558 | 0.2284
10389455 | 3. korrus | 1550 | 0.3844 | 0.01922 | 0.7564
10389473 | 3. korrus | 450 | 0.1204 | 0.00558 | 0.2284
10389474 | 3. korrus | 1550 | 0.3844 | 0.01922 | 0.7564
10389492 | 3. korrus | 450 | 0.1204 | 0.00558 | 0.2284
10389493 | 3. korrus | 1550 | 0.3844 | 0.01922 | 0.7564
10389510 | 3. korrus | 450 | 0.1204 | 0.00558 | 0.2284
10389511 | 3. korrus | 1550 | 0.366291 | 0.0182977 | 0.720181
10515275 | 1. korrus | 639.875 | 0.14643 | 0.00691963 | 0.28046
10515276 | 1. korrus | 1190 | 0.298 | 0.014756 | 0.5836
10515283 | 1. korrus | 639.875 | 0.14643 | 0.00691963 | 0.28046
10515284 | 1. korrus | 1190 | 0.298 | 0.014756 | 0.5836
10522700 | 1. korrus | 639.875 | 0.14643 | 0.00691963 | 0.28046
10522701 | 1. korrus | 1190 | 0.298 | 0.014756 | 0.5836
10522708 | 1. korrus | 639.875 | 0.14643 | 0.00691963 | 0.28046
10522709 | 1. korrus | 1190 | 0.298 | 0.014756 | 0.5836
10522857 | 1. korrus | 639.875 | 0.14643 | 0.00691963 | 0.28046
10522858 | 1. korrus | 1190 | 0.298 | 0.014756 | 0.5836
10522865 | 1. korrus | 639.875 | 0.14643 | 0.00691963 | 0.28046
10522866 | 1. korrus | 1190 | 0.298 | 0.014756 | 0.5836
10523007 | 1. korrus | 639.875 | 0.14643 | 0.00691963 | 0.28046
10523008 | 1. korrus | 1190 | 0.298 | 0.014756 | 0.5836
10523015 | 1. korrus | 639.875 | 0.14643 | 0.00691963 | 0.28046
10523016 | 1. korrus | 1190 | 0.298 | 0.014756 | 0.5836
10523173 | 1. korrus | 639.875 | 0.14643 | 0.00691963 | 0.28046
10523174 | 1. korrus | 1190 | 0.298 | 0.014756 | 0.5836
10523181 | 1. korrus | 639.875 | 0.14643 | 0.00691963 | 0.28046
10523182 | 1. korrus | 1190 | 0.298 | 0.014756 | 0.5836
10523323 | 1. korrus | 639.875 | 0.14643 | 0.00691963 | 0.28046
10523324 | 1. korrus | 1190 | 0.298 | 0.014756 | 0.5836
10523331 | 1. korrus | 639.875 | 0.14643 | 0.00691963 | 0.28046
10523332 | 1. korrus | 1190 | 0.298 | 0.014756 | 0.5836
10532981 | 1. korrus | 1760 | 0.4348 | 0.021824 | 0.8572
10532982 | 1. korrus | 550 | 0.1444 | 0.00682 | 0.2764
10532983 | 1. korrus | 1760 | 0.4348 | 0.021824 | 0.8572
10532984 | 1. korrus | 550 | 0.1444 | 0.00682 | 0.2764
10533089 | 1. korrus | 1760 | 0.4348 | 0.021824 | 0.8572
10533090 | 1. korrus | 550 | 0.1444 | 0.00682 | 0.2764
10533091 | 1. korrus | 1760 | 0.4348 | 0.021824 | 0.8572
10533092 | 1. korrus | 550 | 0.1444 | 0.00682 | 0.2764
10533197 | 1. korrus | 1760 | 0.4348 | 0.021824 | 0.8572
10533198 | 1. korrus | 550 | 0.1444 | 0.00682 | 0.2764
10533199 | 1. korrus | 1760 | 0.4348 | 0.021824 | 0.8572
10533200 | 1. korrus | 550 | 0.1444 | 0.00682 | 0.2764
10533305 | 1. korrus | 1760 | 0.4348 | 0.021824 | 0.8572
10533306 | 1. korrus | 550 | 0.1444 | 0.00682 | 0.2764
10533307 | 1. korrus | 1760 | 0.4348 | 0.021824 | 0.8572
10533308 | 1. korrus | 550 | 0.1444 | 0.00682 | 0.2764
10533413 | 1. korrus | 1760 | 0.4348 | 0.021824 | 0.8572
10533414 | 1. korrus | 550 | 0.1444 | 0.00682 | 0.2764
10533415 | 1. korrus | 1760 | 0.4348 | 0.021824 | 0.8572
10533416 | 1. korrus | 550 | 0.1444 | 0.00682 | 0.2764
10533521 | 1. korrus | 1760 | 0.4348 | 0.021824 | 0.8572
10533522 | 1. korrus | 550 | 0.1444 | 0.00682 | 0.2764
10533523 | 1. korrus | 1760 | 0.4348 | 0.021824 | 0.8572
10533524 | 1. korrus | 550 | 0.1444 | 0.00682 | 0.2764
10533629 | 1. korrus | 1760 | 0.4348 | 0.021824 | 0.8572
10533630 | 1. korrus | 550 | 0.1444 | 0.00682 | 0.2764
10533631 | 1. korrus | 1760 | 0.4348 | 0.021824 | 0.8572
10533632 | 1. korrus | 550 | 0.1444 | 0.00682 | 0.2764
10533737 | 1. korrus | 1760 | 0.4348 | 0.021824 | 0.8572
10533738 | 1. korrus | 550 | 0.1444 | 0.00682 | 0.2764
10533739 | 1. korrus | 1760 | 0.4348 | 0.021824 | 0.8572
10533740 | 1. korrus | 550 | 0.1444 | 0.00682 | 0.2764
10533845 | 1. korrus | 1760 | 0.4348 | 0.021824 | 0.8572
10533846 | 1. korrus | 550 | 0.1444 | 0.00682 | 0.2764
10533847 | 1. korrus | 1760 | 0.4348 | 0.021824 | 0.8572
10533848 | 1. korrus | 550 | 0.1444 | 0.00682 | 0.2764
10533953 | 1. korrus | 1760 | 0.4348 | 0.021824 | 0.8572
10533954 | 1. korrus | 550 | 0.1444 | 0.00682 | 0.2764
10533955 | 1. korrus | 1760 | 0.4348 | 0.021824 | 0.8572
10533956 | 1. korrus | 550 | 0.1444 | 0.00682 | 0.2764
10534061 | 1. korrus | 1760 | 0.4348 | 0.021824 | 0.8572
10534062 | 1. korrus | 550 | 0.1444 | 0.00682 | 0.2764
10534063 | 1. korrus | 1760 | 0.4348 | 0.021824 | 0.8572
10534064 | 1. korrus | 550 | 0.1444 | 0.00682 | 0.2764

# IfcMember: Rectangular Mullion:NEW 300x100mm (24)
Type - PredefinedType: MULLION; Material: LUMION_dark steel window frames
Type - Pset_MemberCommon - IsExternal: no
Pset_MemberCommon - Reference: NEW 300x100mm
Pset_QuantityTakeOff - Reference: NEW 300x100mm
Name (Rectangular Mullion:NEW 300x100mm:...) | In | Span (mm) = Length (mm) | CrossSectionArea (m2) | NetVolume (m3) | NetSurfaceArea (m2)
10515279 | 1. korrus | 750.572 | 0.293959 | 0.0174863 | 0.561817 | Pset_MemberCommon - IsExternal: yes
10515280 | 1. korrus | 1250 | 0.5261 | 0.032625 | 1.0261 | Pset_MemberCommon - IsExternal: yes
10522704 | 1. korrus | 750.572 | 0.293959 | 0.0174863 | 0.561817
10522705 | 1. korrus | 1250 | 0.5261 | 0.032625 | 1.0261
10522861 | 1. korrus | 750.572 | 0.293959 | 0.0174863 | 0.561817
10522862 | 1. korrus | 1250 | 0.5261 | 0.032625 | 1.0261
10523011 | 1. korrus | 750.572 | 0.293959 | 0.0174863 | 0.561817
10523012 | 1. korrus | 1250 | 0.5261 | 0.032625 | 1.0261
10523177 | 1. korrus | 750.572 | 0.293959 | 0.0174863 | 0.561817
10523178 | 1. korrus | 1250 | 0.5261 | 0.032625 | 1.0261
10523327 | 1. korrus | 750.572 | 0.293959 | 0.0174863 | 0.561817
10523328 | 1. korrus | 1250 | 0.5261 | 0.032625 | 1.0261
10644076 | 2. korrus | 800 | 0.31372 | 0.018776 | 0.60134
10644077 | 2. korrus | 800 | 0.3461 | 0.02088 | 0.6661
10644170 | 2. korrus | 800 | 0.31372 | 0.018776 | 0.60134
10644171 | 2. korrus | 800 | 0.3461 | 0.02088 | 0.6661
10644264 | 2. korrus | 800 | 0.31372 | 0.018776 | 0.60134
10644265 | 2. korrus | 800 | 0.3461 | 0.02088 | 0.6661
10644358 | 2. korrus | 800 | 0.31372 | 0.018776 | 0.60134
10644359 | 2. korrus | 800 | 0.3461 | 0.02088 | 0.6661
10644452 | 2. korrus | 800 | 0.31372 | 0.018776 | 0.60134
10644453 | 2. korrus | 800 | 0.3461 | 0.02088 | 0.6661
10644546 | 2. korrus | 800 | 0.31372 | 0.018776 | 0.60134
10644547 | 2. korrus | 800 | 0.3461 | 0.02088 | 0.6661

# IfcMember: Rectangular Mullion:NEW 40x70mm (2)
In: 3. korrus
Type - PredefinedType: MULLION; Material: LUMION_dark steel window frames
Type - Pset_MemberCommon - IsExternal: no
Pset_MemberCommon - Reference: NEW 40x70mm
Pset_QuantityTakeOff - Reference: NEW 40x70mm
Name (Rectangular Mullion:NEW 40x70mm:...) | Span (mm) = Length (mm) | CrossSectionArea (m2) | NetVolume (m3) | NetSurfaceArea (m2)
10357388 | 2240 | 0.2492 | 0.006272 | 0.4984 | Pset_MemberCommon - IsExternal: yes
10389279 | 2150 | 0.2393 | 0.00602 | 0.4786

# IfcMember: Rectangular Mullion:NEW 60x70mm (510)
Type - PredefinedType: MULLION; Material: LUMION_dark steel window frames
Type - Pset_MemberCommon - IsExternal: no
Pset_MemberCommon - Reference: NEW 60x70mm
Pset_QuantityTakeOff - Reference: NEW 60x70mm
Name (Rectangular Mullion:NEW 60x70mm:...) | In | Span (mm) = Length (mm) | CrossSectionArea (m2) | NetVolume (m3) | NetSurfaceArea (m2)
10357378 | 3. korrus | 2300 | 0.3032 | 0.00966 | 0.6064 | Pset_MemberCommon - IsExternal: yes
10357381 | 3. korrus | 2300 | 0.3032 | 0.00966 | 0.6064 | Pset_MemberCommon - IsExternal: yes
10357383 | 3. korrus | 1240 | 0.1654 | 0.005208 | 0.3308 | Pset_MemberCommon - IsExternal: yes
10385999 | 3. korrus | 1084.62 | 0.140666 | 0.00434443 | 0.281332
10386000 | 3. korrus | 1180 | 0.1576 | 0.004956 | 0.3152
10386001 | 3. korrus | 384.615 | 0.0522166 | 0.00154013 | 0.104433
10386002 | 3. korrus | 1476.48 | 0.189625 | 0.00591502 | 0.37925
10386047 | 3. korrus | 450 | 0.0627 | 0.00189 | 0.1212
10386048 | 3. korrus | 850 | 0.112717 | 0.00349474 | 0.221233
10386049 | 3. korrus | 1550 | 0.2057 | 0.00651 | 0.4072
10386050 | 3. korrus | 450 | 0.0627 | 0.00189 | 0.1212
10386051 | 3. korrus | 1240 | 0.164482 | 0.00517623 | 0.328965
10386052 | 3. korrus | 1476.48 | 0.193242 | 0.0060942 | 0.386484
10386053 | 3. korrus | 1165 | 0.15565 | 0.004893 | 0.3113
10386054 | 3. korrus | 1165 | 0.15565 | 0.004893 | 0.3113
10386055 | 3. korrus | 1084.62 | 0.140666 | 0.00434443 | 0.281332
10386056 | 3. korrus | 1180 | 0.1576 | 0.004956 | 0.3152
10386057 | 3. korrus | 384.615 | 0.0522166 | 0.00154013 | 0.104433
10386058 | 3. korrus | 1476.48 | 0.189625 | 0.00591502 | 0.37925
10389355 | 3. korrus | 1550 | 0.2057 | 0.00651 | 0.4072
10389356 | 3. korrus | 450 | 0.0627 | 0.00189 | 0.1212
10389357 | 3. korrus | 1165 | 0.15565 | 0.004893 | 0.3113
10389358 | 3. korrus | 1165 | 0.15565 | 0.004893 | 0.3113
10389359 | 3. korrus | 450 | 0.0627 | 0.00189 | 0.1212
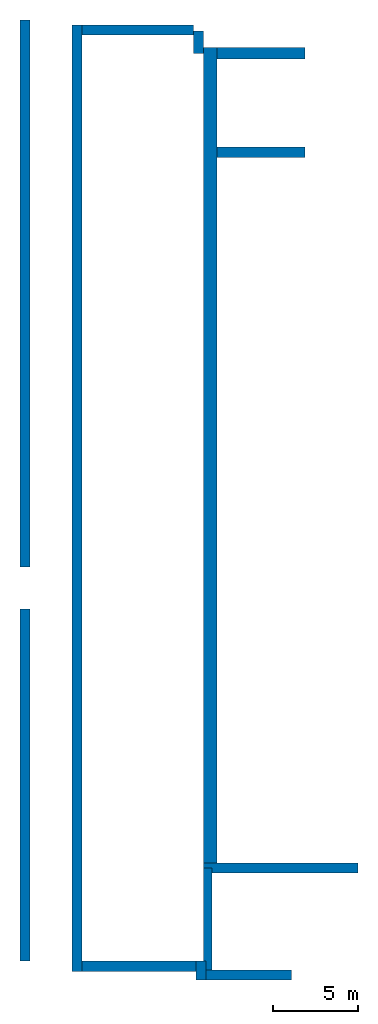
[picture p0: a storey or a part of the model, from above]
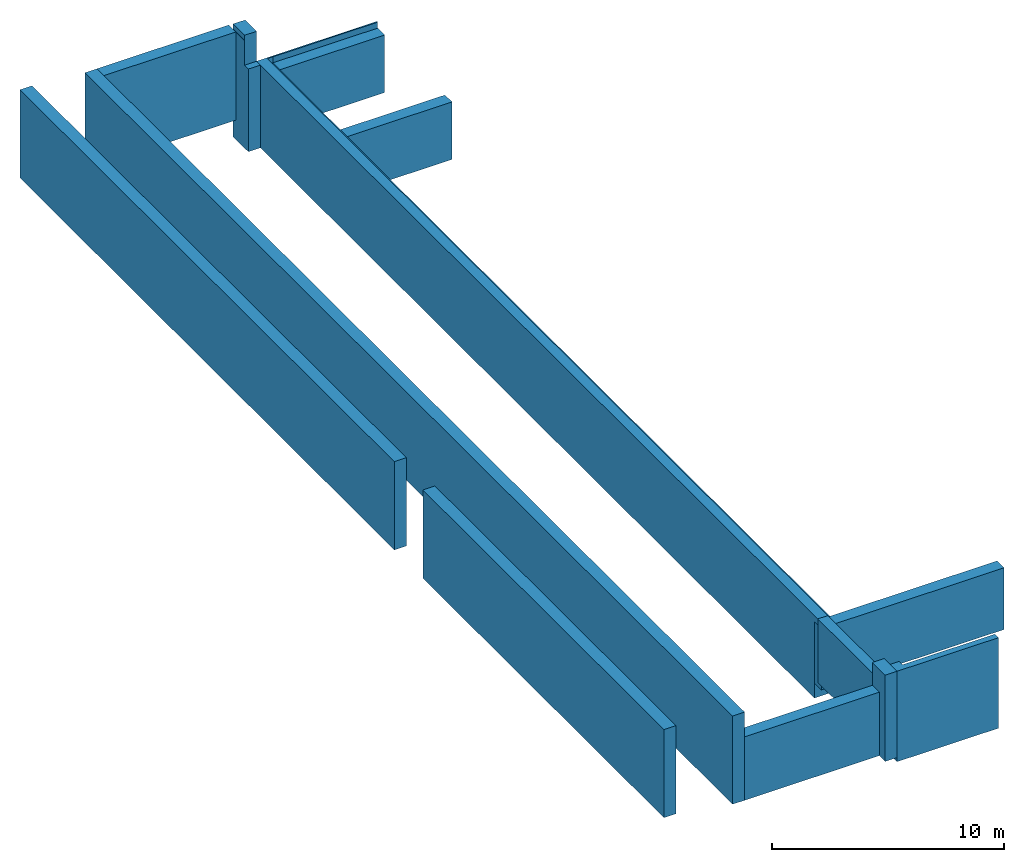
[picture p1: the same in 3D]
Properties of the parts of a building model (IFC2X3), part 4 of 7

# IfcMember: Rectangular Mullion:NEW 60x70mm (510)
Name (Rectangular Mullion:NEW 60x70mm:...) | In | Span (mm) = Length (mm) | CrossSectionArea (m2) | NetVolume (m3) | NetSurfaceArea (m2)
10389360 | 3. korrus | 1550 | 0.2057 | 0.00651 | 0.4072
10389361 | 3. korrus | 1165 | 0.15565 | 0.004893 | 0.3113
10389362 | 3. korrus | 1165 | 0.15565 | 0.004893 | 0.3113
10389268 | 3. korrus | 2210 | 0.2915 | 0.009282 | 0.583
10389269 | 3. korrus | 2210 | 0.2915 | 0.009282 | 0.583
10389270 | 3. korrus | 1240 | 0.1654 | 0.005208 | 0.3308
10389374 | 3. korrus | 1550 | 0.2057 | 0.00651 | 0.4072
10389375 | 3. korrus | 450 | 0.0627 | 0.00189 | 0.1212
10389376 | 3. korrus | 1165 | 0.15565 | 0.004893 | 0.3113
10389377 | 3. korrus | 1165 | 0.15565 | 0.004893 | 0.3113
10389378 | 3. korrus | 450 | 0.0627 | 0.00189 | 0.1212
10389379 | 3. korrus | 1550 | 0.2057 | 0.00651 | 0.4072
10389380 | 3. korrus | 1165 | 0.15565 | 0.004893 | 0.3113
10389381 | 3. korrus | 1165 | 0.15565 | 0.004893 | 0.3113
10389393 | 3. korrus | 1550 | 0.2057 | 0.00651 | 0.4072
10389394 | 3. korrus | 450 | 0.0627 | 0.00189 | 0.1212
10389395 | 3. korrus | 1165 | 0.15565 | 0.004893 | 0.3113
10389396 | 3. korrus | 1165 | 0.15565 | 0.004893 | 0.3113
10389397 | 3. korrus | 450 | 0.0627 | 0.00189 | 0.1212
10389398 | 3. korrus | 1550 | 0.2057 | 0.00651 | 0.4072
10389399 | 3. korrus | 1165 | 0.15565 | 0.004893 | 0.3113
10389400 | 3. korrus | 1165 | 0.15565 | 0.004893 | 0.3113
10389446 | 3. korrus | 1550 | 0.2057 | 0.00651 | 0.4072
10389447 | 3. korrus | 450 | 0.0627 | 0.00189 | 0.1212
10389448 | 3. korrus | 1165 | 0.15565 | 0.004893 | 0.3113
10389449 | 3. korrus | 1165 | 0.15565 | 0.004893 | 0.3113
10389450 | 3. korrus | 450 | 0.0627 | 0.00189 | 0.1212
10389451 | 3. korrus | 1550 | 0.2057 | 0.00651 | 0.4072
10389452 | 3. korrus | 1165 | 0.15565 | 0.004893 | 0.3113
10389453 | 3. korrus | 1165 | 0.15565 | 0.004893 | 0.3113
10389465 | 3. korrus | 1550 | 0.2057 | 0.00651 | 0.4072
10389466 | 3. korrus | 450 | 0.0627 | 0.00189 | 0.1212
10389467 | 3. korrus | 1165 | 0.15565 | 0.004893 | 0.3113
10389468 | 3. korrus | 1165 | 0.15565 | 0.004893 | 0.3113
10389469 | 3. korrus | 450 | 0.0627 | 0.00189 | 0.1212
10389470 | 3. korrus | 1550 | 0.2057 | 0.00651 | 0.4072
10389471 | 3. korrus | 1165 | 0.15565 | 0.004893 | 0.3113
10389472 | 3. korrus | 1165 | 0.15565 | 0.004893 | 0.3113
10389484 | 3. korrus | 1550 | 0.2057 | 0.00651 | 0.4072
10389485 | 3. korrus | 450 | 0.0627 | 0.00189 | 0.1212
10389486 | 3. korrus | 1165 | 0.15565 | 0.004893 | 0.3113
10389487 | 3. korrus | 1165 | 0.15565 | 0.004893 | 0.3113
10389488 | 3. korrus | 450 | 0.0627 | 0.00189 | 0.1212
10389489 | 3. korrus | 1550 | 0.2057 | 0.00651 | 0.4072
10389490 | 3. korrus | 1165 | 0.15565 | 0.004893 | 0.3113
10389491 | 3. korrus | 1165 | 0.15565 | 0.004893 | 0.3113
10389503 | 3. korrus | 1550 | 0.2057 | 0.00651 | 0.4072
10389504 | 3. korrus | 450 | 0.0627 | 0.00189 | 0.1212
10389505 | 3. korrus | 1165 | 0.15565 | 0.004893 | 0.3113
10389506 | 3. korrus | 1165 | 0.15565 | 0.004893 | 0.3113
10389507 | 3. korrus | 450 | 0.0627 | 0.00189 | 0.1212
10389508 | 3. korrus | 850 | 0.112717 | 0.00349474 | 0.221233
10389509 | 3. korrus | 1240 | 0.164482 | 0.00517623 | 0.328965
10389527 | 3. korrus | 1476.48 | 0.193242 | 0.0060942 | 0.386484
10515297 | 1. korrus | 500 | 0.0692 | 0.0021 | 0.13
10515298 | 1. korrus | 500 | 0.0692 | 0.0021 | 0.13
10515299 | 1. korrus | 500 | 0.0692 | 0.0021 | 0.13
10515300 | 1. korrus | 450 | 0.0627 | 0.00189 | 0.1212
10515301 | 1. korrus | 500 | 0.0692 | 0.0021 | 0.13
10515302 | 1. korrus | 500 | 0.0692 | 0.0021 | 0.13
10515303 | 1. korrus | 500 | 0.0692 | 0.0021 | 0.13
10515304 | 1. korrus | 440 | 0.0614 | 0.001848 | 0.1186
10515305 | 1. korrus | 450 | 0.0627 | 0.00189 | 0.1212
10515306 | 1. korrus | 440 | 0.0614 | 0.001848 | 0.1186
10515307 | 1. korrus | 100 | 0.0142242 | 0.000296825 | 0.0242484
10515308 | 1. korrus | 1250 | 0.1667 | 0.00525 | 0.3292
10515309 | 1. korrus | 1250 | 0.1667 | 0.00525 | 0.3292
10515310 | 1. korrus | 100 | 0.0142242 | 0.000296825 | 0.0242484
10522722 | 1. korrus | 500 | 0.0692 | 0.0021 | 0.13
10522723 | 1. korrus | 500 | 0.0692 | 0.0021 | 0.13
10522724 | 1. korrus | 500 | 0.0692 | 0.0021 | 0.13
10522725 | 1. korrus | 450 | 0.0627 | 0.00189 | 0.1212
10522726 | 1. korrus | 500 | 0.0692 | 0.0021 | 0.13
10522727 | 1. korrus | 500 | 0.0692 | 0.0021 | 0.13
10522728 | 1. korrus | 500 | 0.0692 | 0.0021 | 0.13
10522729 | 1. korrus | 440 | 0.0614 | 0.001848 | 0.1186
10522730 | 1. korrus | 450 | 0.0627 | 0.00189 | 0.1212
10522731 | 1. korrus | 440 | 0.0614 | 0.001848 | 0.1186
10522732 | 1. korrus | 100 | 0.0142242 | 0.000296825 | 0.0242484
10522733 | 1. korrus | 1250 | 0.1667 | 0.00525 | 0.3292
10522734 | 1. korrus | 1250 | 0.1667 | 0.00525 | 0.3292
10522735 | 1. korrus | 100 | 0.0142242 | 0.000296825 | 0.0242484
10522879 | 1. korrus | 500 | 0.0692 | 0.0021 | 0.13
10522880 | 1. korrus | 500 | 0.0692 | 0.0021 | 0.13
10522881 | 1. korrus | 500 | 0.0692 | 0.0021 | 0.13
10522882 | 1. korrus | 450 | 0.0627 | 0.00189 | 0.1212
10522883 | 1. korrus | 500 | 0.0692 | 0.0021 | 0.13
10522884 | 1. korrus | 500 | 0.0692 | 0.0021 | 0.13
10522885 | 1. korrus | 500 | 0.0692 | 0.0021 | 0.13
10522886 | 1. korrus | 440 | 0.0614 | 0.001848 | 0.1186
10522887 | 1. korrus | 450 | 0.0627 | 0.00189 | 0.1212
10522888 | 1. korrus | 440 | 0.0614 | 0.001848 | 0.1186
10522889 | 1. korrus | 100 | 0.0142242 | 0.000296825 | 0.0242484
10522890 | 1. korrus | 1250 | 0.1667 | 0.00525 | 0.3292
10522891 | 1. korrus | 1250 | 0.1667 | 0.00525 | 0.3292
10522892 | 1. korrus | 100 | 0.0142242 | 0.000296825 | 0.0242484
10523029 | 1. korrus | 500 | 0.0692 | 0.0021 | 0.13
10523030 | 1. korrus | 500 | 0.0692 | 0.0021 | 0.13
10523031 | 1. korrus | 500 | 0.0692 | 0.0021 | 0.13
10523032 | 1. korrus | 450 | 0.0627 | 0.00189 | 0.1212
10523033 | 1. korrus | 500 | 0.0692 | 0.0021 | 0.13
10523034 | 1. korrus | 500 | 0.0692 | 0.0021 | 0.13
10523035 | 1. korrus | 500 | 0.0692 | 0.0021 | 0.13
10523036 | 1. korrus | 440 | 0.0614 | 0.001848 | 0.1186
10523037 | 1. korrus | 450 | 0.0627 | 0.00189 | 0.1212
10523038 | 1. korrus | 440 | 0.0614 | 0.001848 | 0.1186
10523039 | 1. korrus | 100 | 0.0142242 | 0.000296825 | 0.0242484
10523040 | 1. korrus | 1250 | 0.1667 | 0.00525 | 0.3292
10523041 | 1. korrus | 1250 | 0.1667 | 0.00525 | 0.3292
10523042 | 1. korrus | 100 | 0.0142242 | 0.000296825 | 0.0242484
10523195 | 1. korrus | 500 | 0.0692 | 0.0021 | 0.13
10523196 | 1. korrus | 500 | 0.0692 | 0.0021 | 0.13
10523197 | 1. korrus | 500 | 0.0692 | 0.0021 | 0.13
10523198 | 1. korrus | 450 | 0.0627 | 0.00189 | 0.1212
10523199 | 1. korrus | 500 | 0.0692 | 0.0021 | 0.13
10523200 | 1. korrus | 500 | 0.0692 | 0.0021 | 0.13
10523201 | 1. korrus | 500 | 0.0692 | 0.0021 | 0.13
10523202 | 1. korrus | 440 | 0.0614 | 0.001848 | 0.1186
10523203 | 1. korrus | 450 | 0.0627 | 0.00189 | 0.1212
10523204 | 1. korrus | 440 | 0.0614 | 0.001848 | 0.1186
10523205 | 1. korrus | 100 | 0.0142242 | 0.000296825 | 0.0242484
10523206 | 1. korrus | 1250 | 0.1667 | 0.00525 | 0.3292
10523207 | 1. korrus | 1250 | 0.1667 | 0.00525 | 0.3292
10523208 | 1. korrus | 100 | 0.0142242 | 0.000296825 | 0.0242484
10523345 | 1. korrus | 500 | 0.0692 | 0.0021 | 0.13
10523346 | 1. korrus | 500 | 0.0692 | 0.0021 | 0.13
10523347 | 1. korrus | 500 | 0.0692 | 0.0021 | 0.13
10523348 | 1. korrus | 450 | 0.0627 | 0.00189 | 0.1212
10523349 | 1. korrus | 500 | 0.0692 | 0.0021 | 0.13
10523350 | 1. korrus | 500 | 0.0692 | 0.0021 | 0.13
10523351 | 1. korrus | 500 | 0.0692 | 0.0021 | 0.13
10523352 | 1. korrus | 440 | 0.0614 | 0.001848 | 0.1186
10523353 | 1. korrus | 450 | 0.0627 | 0.00189 | 0.1212
10523354 | 1. korrus | 440 | 0.0614 | 0.001848 | 0.1186
10523355 | 1. korrus | 100 | 0.0142242 | 0.000296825 | 0.0242484
10523356 | 1. korrus | 1250 | 0.1667 | 0.00525 | 0.3292
10523357 | 1. korrus | 1250 | 0.1667 | 0.00525 | 0.3292
10523358 | 1. korrus | 100 | 0.0142242 | 0.000296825 | 0.0242484
10532972 | 1. korrus | 561.871 | 0.0768464 | 0.00234704 | 0.153693
10532973 | 1. korrus | 545.458 | 0.0747243 | 0.00227848 | 0.149449
10532974 | 1. korrus | 221.205 | 0.0328005 | 0.000924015 | 0.0656009
10532975 | 1. korrus | 563.695 | 0.0750917 | 0.00227898 | 0.150183
10532976 | 1. korrus | 561.871 | 0.0768464 | 0.00234704 | 0.153693
10532977 | 1. korrus | 545.458 | 0.0747243 | 0.00227848 | 0.149449
10532978 | 1. korrus | 1001.37 | 0.133671 | 0.00418291 | 0.267342
10532979 | 1. korrus | 314.175 | 0.0448209 | 0.00131237 | 0.0896418
10532980 | 1. korrus | 563.695 | 0.0750917 | 0.00227898 | 0.150183
10532995 | 1. korrus | 1199.77 | 0.15818 | 0.00496345 | 0.312159
10532996 | 1. korrus | 550 | 0.0757 | 0.00231 | 0.1472
10532997 | 1. korrus | 550 | 0.0757 | 0.00231 | 0.1472
10532998 | 1. korrus | 1199.77 | 0.15818 | 0.00496345 | 0.312159
10532999 | 1. korrus | 450 | 0.0627 | 0.00189 | 0.1212
10533000 | 1. korrus | 530 | 0.0731 | 0.002226 | 0.1378
10533001 | 1. korrus | 530 | 0.0731 | 0.002226 | 0.1378
10533002 | 1. korrus | 530 | 0.0731 | 0.002226 | 0.1378
10533003 | 1. korrus | 530 | 0.0731 | 0.002226 | 0.1378
10533004 | 1. korrus | 455 | 0.06335 | 0.001911 | 0.1225
10533005 | 1. korrus | 455 | 0.06335 | 0.001911 | 0.1225
10533006 | 1. korrus | 450 | 0.0627 | 0.00189 | 0.1212
10533031 | 1. korrus | 314.175 | 0.0448209 | 0.00131237 | 0.0896418
10533032 | 1. korrus | 221.205 | 0.0328005 | 0.000924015 | 0.0656009
10533033 | 1. korrus | 1150 | 0.1537 | 0.00483 | 0.3074
10533080 | 1. korrus | 561.871 | 0.0768464 | 0.00234704 | 0.153693
10533081 | 1. korrus | 545.458 | 0.0747243 | 0.00227848 | 0.149449
10533082 | 1. korrus | 221.205 | 0.0328005 | 0.000924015 | 0.0656009
10533083 | 1. korrus | 563.695 | 0.0750917 | 0.00227898 | 0.150183
10533084 | 1. korrus | 561.871 | 0.0768464 | 0.00234704 | 0.153693
10533085 | 1. korrus | 545.458 | 0.0747243 | 0.00227848 | 0.149449
10533086 | 1. korrus | 1001.37 | 0.133671 | 0.00418291 | 0.267342
10533087 | 1. korrus | 314.175 | 0.0448209 | 0.00131237 | 0.0896418
10533088 | 1. korrus | 563.695 | 0.0750917 | 0.00227898 | 0.150183
10533103 | 1. korrus | 1199.77 | 0.15818 | 0.00496345 | 0.312159
10533104 | 1. korrus | 550 | 0.0757 | 0.00231 | 0.1472
10533105 | 1. korrus | 550 | 0.0757 | 0.00231 | 0.1472
10533106 | 1. korrus | 1199.77 | 0.15818 | 0.00496345 | 0.312159
10533107 | 1. korrus | 450 | 0.0627 | 0.00189 | 0.1212
10533108 | 1. korrus | 530 | 0.0731 | 0.002226 | 0.1378
10533109 | 1. korrus | 530 | 0.0731 | 0.002226 | 0.1378
10533110 | 1. korrus | 530 | 0.0731 | 0.002226 | 0.1378
10533111 | 1. korrus | 530 | 0.0731 | 0.002226 | 0.1378
10533112 | 1. korrus | 455 | 0.06335 | 0.001911 | 0.1225
10533113 | 1. korrus | 455 | 0.06335 | 0.001911 | 0.1225
10533114 | 1. korrus | 450 | 0.0627 | 0.00189 | 0.1212
10533136 | 1. korrus | 314.175 | 0.0448209 | 0.00131237 | 0.0896418
10533137 | 1. korrus | 221.205 | 0.0328005 | 0.000924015 | 0.0656009
10533138 | 1. korrus | 1150 | 0.1537 | 0.00483 | 0.3074
10533188 | 1. korrus | 561.871 | 0.0768464 | 0.00234704 | 0.153693
10533189 | 1. korrus | 545.458 | 0.0747243 | 0.00227848 | 0.149449
10533190 | 1. korrus | 221.205 | 0.0328005 | 0.000924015 | 0.0656009
10533191 | 1. korrus | 563.695 | 0.0750917 | 0.00227898 | 0.150183
10533192 | 1. korrus | 561.871 | 0.0768464 | 0.00234704 | 0.153693
10533193 | 1. korrus | 545.458 | 0.0747243 | 0.00227848 | 0.149449
10533194 | 1. korrus | 1001.37 | 0.133671 | 0.00418291 | 0.267342
10533195 | 1. korrus | 314.175 | 0.0448209 | 0.00131237 | 0.0896418
10533196 | 1. korrus | 563.695 | 0.0750917 | 0.00227898 | 0.150183
10533211 | 1. korrus | 1199.77 | 0.15818 | 0.00496345 | 0.312159
10533212 | 1. korrus | 550 | 0.0757 | 0.00231 | 0.1472
10533213 | 1. korrus | 550 | 0.0757 | 0.00231 | 0.1472
10533214 | 1. korrus | 1199.77 | 0.15818 | 0.00496345 | 0.312159
10533215 | 1. korrus | 450 | 0.0627 | 0.00189 | 0.1212
10533216 | 1. korrus | 530 | 0.0731 | 0.002226 | 0.1378
10533217 | 1. korrus | 530 | 0.0731 | 0.002226 | 0.1378
10533218 | 1. korrus | 530 | 0.0731 | 0.002226 | 0.1378
10533219 | 1. korrus | 530 | 0.0731 | 0.002226 | 0.1378
10533220 | 1. korrus | 455 | 0.06335 | 0.001911 | 0.1225
10533221 | 1. korrus | 455 | 0.06335 | 0.001911 | 0.1225
10533222 | 1. korrus | 450 | 0.0627 | 0.00189 | 0.1212
10533244 | 1. korrus | 314.175 | 0.0448209 | 0.00131237 | 0.0896418
10533245 | 1. korrus | 221.205 | 0.0328005 | 0.000924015 | 0.0656009
10533246 | 1. korrus | 1150 | 0.1537 | 0.00483 | 0.3074
10533296 | 1. korrus | 561.871 | 0.0768464 | 0.00234704 | 0.153693
10533297 | 1. korrus | 545.458 | 0.0747243 | 0.00227848 | 0.149449
10533298 | 1. korrus | 221.205 | 0.0328005 | 0.000924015 | 0.0656009
10533299 | 1. korrus | 563.695 | 0.0750917 | 0.00227898 | 0.150183
10533300 | 1. korrus | 561.871 | 0.0768464 | 0.00234704 | 0.153693
10533301 | 1. korrus | 545.458 | 0.0747243 | 0.00227848 | 0.149449
10533302 | 1. korrus | 1001.37 | 0.133671 | 0.00418291 | 0.267342
10533303 | 1. korrus | 314.175 | 0.0448209 | 0.00131237 | 0.0896418
10533304 | 1. korrus | 563.695 | 0.0750917 | 0.00227898 | 0.150183
10533319 | 1. korrus | 1199.77 | 0.15818 | 0.00496345 | 0.312159
10533320 | 1. korrus | 550 | 0.0757 | 0.00231 | 0.1472
10533321 | 1. korrus | 550 | 0.0757 | 0.00231 | 0.1472
10533322 | 1. korrus | 1199.77 | 0.15818 | 0.00496345 | 0.312159
10533323 | 1. korrus | 450 | 0.0627 | 0.00189 | 0.1212
10533324 | 1. korrus | 530 | 0.0731 | 0.002226 | 0.1378
10533325 | 1. korrus | 530 | 0.0731 | 0.002226 | 0.1378
10533326 | 1. korrus | 530 | 0.0731 | 0.002226 | 0.1378
10533327 | 1. korrus | 530 | 0.0731 | 0.002226 | 0.1378
10533328 | 1. korrus | 455 | 0.06335 | 0.001911 | 0.1225
10533329 | 1. korrus | 455 | 0.06335 | 0.001911 | 0.1225
10533330 | 1. korrus | 450 | 0.0627 | 0.00189 | 0.1212
10533352 | 1. korrus | 314.175 | 0.0448209 | 0.00131237 | 0.0896418
10533353 | 1. korrus | 221.205 | 0.0328005 | 0.000924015 | 0.0656009
10533354 | 1. korrus | 1150 | 0.1537 | 0.00483 | 0.3074
10533404 | 1. korrus | 561.871 | 0.0768464 | 0.00234704 | 0.153693
10533405 | 1. korrus | 545.458 | 0.0747243 | 0.00227848 | 0.149449
10533406 | 1. korrus | 221.205 | 0.0328005 | 0.000924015 | 0.0656009
10533407 | 1. korrus | 563.695 | 0.0750917 | 0.00227898 | 0.150183
10533408 | 1. korrus | 561.871 | 0.0768464 | 0.00234704 | 0.153693
10533409 | 1. korrus | 545.458 | 0.0747243 | 0.00227848 | 0.149449
10533410 | 1. korrus | 1001.37 | 0.133671 | 0.00418291 | 0.267342
10533411 | 1. korrus | 314.175 | 0.0448209 | 0.00131237 | 0.0896418
10533412 | 1. korrus | 563.695 | 0.0750917 | 0.00227898 | 0.150183
10533427 | 1. korrus | 1199.77 | 0.15818 | 0.00496345 | 0.312159
10533428 | 1. korrus | 550 | 0.0757 | 0.00231 | 0.1472
10533429 | 1. korrus | 550 | 0.0757 | 0.00231 | 0.1472
10533430 | 1. korrus | 1199.77 | 0.15818 | 0.00496345 | 0.312159
10533431 | 1. korrus | 450 | 0.0627 | 0.00189 | 0.1212
10533432 | 1. korrus | 530 | 0.0731 | 0.002226 | 0.1378
10533433 | 1. korrus | 530 | 0.0731 | 0.002226 | 0.1378
10533434 | 1. korrus | 530 | 0.0731 | 0.002226 | 0.1378
10533435 | 1. korrus | 530 | 0.0731 | 0.002226 | 0.1378
10533436 | 1. korrus | 455 | 0.06335 | 0.001911 | 0.1225
10533437 | 1. korrus | 455 | 0.06335 | 0.001911 | 0.1225
10533438 | 1. korrus | 450 | 0.0627 | 0.00189 | 0.1212
10533460 | 1. korrus | 314.175 | 0.0448209 | 0.00131237 | 0.0896418
10533461 | 1. korrus | 221.205 | 0.0328005 | 0.000924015 | 0.0656009
10533462 | 1. korrus | 1150 | 0.1537 | 0.00483 | 0.3074
10533512 | 1. korrus | 561.871 | 0.0768464 | 0.00234704 | 0.153693
10533513 | 1. korrus | 545.458 | 0.0747243 | 0.00227848 | 0.149449
10533514 | 1. korrus | 221.205 | 0.0328005 | 0.000924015 | 0.0656009
10533515 | 1. korrus | 563.695 | 0.0750917 | 0.00227898 | 0.150183
10533516 | 1. korrus | 561.871 | 0.0768464 | 0.00234704 | 0.153693
10533517 | 1. korrus | 545.458 | 0.0747243 | 0.00227848 | 0.149449
10533518 | 1. korrus | 1001.37 | 0.133671 | 0.00418291 | 0.267342
10533519 | 1. korrus | 314.175 | 0.0448209 | 0.00131237 | 0.0896418
10533520 | 1. korrus | 563.695 | 0.0750917 | 0.00227898 | 0.150183
10533535 | 1. korrus | 1199.77 | 0.15818 | 0.00496345 | 0.312159
10533536 | 1. korrus | 550 | 0.0757 | 0.00231 | 0.1472
10533537 | 1. korrus | 550 | 0.0757 | 0.00231 | 0.1472
10533538 | 1. korrus | 1199.77 | 0.15818 | 0.00496345 | 0.312159
10533539 | 1. korrus | 450 | 0.0627 | 0.00189 | 0.1212
10533540 | 1. korrus | 530 | 0.0731 | 0.002226 | 0.1378
10533541 | 1. korrus | 530 | 0.0731 | 0.002226 | 0.1378
10533542 | 1. korrus | 530 | 0.0731 | 0.002226 | 0.1378
10533543 | 1. korrus | 530 | 0.0731 | 0.002226 | 0.1378
10533544 | 1. korrus | 455 | 0.06335 | 0.001911 | 0.1225
10533545 | 1. korrus | 455 | 0.06335 | 0.001911 | 0.1225
10533546 | 1. korrus | 450 | 0.0627 | 0.00189 | 0.1212
10533568 | 1. korrus | 314.175 | 0.0448209 | 0.00131237 | 0.0896418
10533569 | 1. korrus | 221.205 | 0.0328005 | 0.000924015 | 0.0656009
10533570 | 1. korrus | 1150 | 0.1537 | 0.00483 | 0.3074
10533620 | 1. korrus | 561.871 | 0.0768464 | 0.00234704 | 0.153693
10533621 | 1. korrus | 545.458 | 0.0747243 | 0.00227848 | 0.149449
10533622 | 1. korrus | 221.205 | 0.0328005 | 0.000924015 | 0.0656009
10533623 | 1. korrus | 563.695 | 0.0750917 | 0.00227898 | 0.150183
10533624 | 1. korrus | 561.871 | 0.0768464 | 0.00234704 | 0.153693
10533625 | 1. korrus | 545.458 | 0.0747243 | 0.00227848 | 0.149449
10533626 | 1. korrus | 1001.37 | 0.133671 | 0.00418291 | 0.267342
10533627 | 1. korrus | 314.175 | 0.0448209 | 0.00131237 | 0.0896418
10533628 | 1. korrus | 563.695 | 0.0750917 | 0.00227898 | 0.150183
10533643 | 1. korrus | 1199.77 | 0.15818 | 0.00496345 | 0.312159
10533644 | 1. korrus | 550 | 0.0757 | 0.00231 | 0.1472
10533645 | 1. korrus | 550 | 0.0757 | 0.00231 | 0.1472
10533646 | 1. korrus | 1199.77 | 0.15818 | 0.00496345 | 0.312159
10533647 | 1. korrus | 450 | 0.0627 | 0.00189 | 0.1212
10533648 | 1. korrus | 530 | 0.0731 | 0.002226 | 0.1378
10533649 | 1. korrus | 530 | 0.0731 | 0.002226 | 0.1378
10533650 | 1. korrus | 530 | 0.0731 | 0.002226 | 0.1378
10533651 | 1. korrus | 530 | 0.0731 | 0.002226 | 0.1378
10533652 | 1. korrus | 455 | 0.06335 | 0.001911 | 0.1225
10533653 | 1. korrus | 455 | 0.06335 | 0.001911 | 0.1225
10533654 | 1. korrus | 450 | 0.0627 | 0.00189 | 0.1212
10533676 | 1. korrus | 314.175 | 0.0448209 | 0.00131237 | 0.0896418
10533677 | 1. korrus | 221.205 | 0.0328005 | 0.000924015 | 0.0656009
10533678 | 1. korrus | 1150 | 0.1537 | 0.00483 | 0.3074
10533728 | 1. korrus | 561.871 | 0.0768464 | 0.00234704 | 0.153693
10533729 | 1. korrus | 545.458 | 0.0747243 | 0.00227848 | 0.149449
10533730 | 1. korrus | 221.205 | 0.0328005 | 0.000924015 | 0.0656009
10533731 | 1. korrus | 563.695 | 0.0750917 | 0.00227898 | 0.150183
10533732 | 1. korrus | 561.871 | 0.0768464 | 0.00234704 | 0.153693
10533733 | 1. korrus | 545.458 | 0.0747243 | 0.00227848 | 0.149449
10533734 | 1. korrus | 1001.37 | 0.133671 | 0.00418291 | 0.267342
10533735 | 1. korrus | 314.175 | 0.0448209 | 0.00131237 | 0.0896418
10533736 | 1. korrus | 563.695 | 0.0750917 | 0.00227898 | 0.150183
10533751 | 1. korrus | 1199.77 | 0.15818 | 0.00496345 | 0.312159
10533752 | 1. korrus | 550 | 0.0757 | 0.00231 | 0.1472
10533753 | 1. korrus | 550 | 0.0757 | 0.00231 | 0.1472
10533754 | 1. korrus | 1199.77 | 0.15818 | 0.00496345 | 0.312159
10533755 | 1. korrus | 450 | 0.0627 | 0.00189 | 0.1212
10533756 | 1. korrus | 530 | 0.0731 | 0.002226 | 0.1378
10533757 | 1. korrus | 530 | 0.0731 | 0.002226 | 0.1378
10533758 | 1. korrus | 530 | 0.0731 | 0.002226 | 0.1378
10533759 | 1. korrus | 530 | 0.0731 | 0.002226 | 0.1378
10533760 | 1. korrus | 455 | 0.06335 | 0.001911 | 0.1225
10533761 | 1. korrus | 455 | 0.06335 | 0.001911 | 0.1225
10533762 | 1. korrus | 450 | 0.0627 | 0.00189 | 0.1212
10533784 | 1. korrus | 314.175 | 0.0448209 | 0.00131237 | 0.0896418
10533785 | 1. korrus | 221.205 | 0.0328005 | 0.000924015 | 0.0656009
10533786 | 1. korrus | 1150 | 0.1537 | 0.00483 | 0.3074
10533836 | 1. korrus | 561.871 | 0.0768464 | 0.00234704 | 0.153693
10533837 | 1. korrus | 545.458 | 0.0747243 | 0.00227848 | 0.149449
10533838 | 1. korrus | 221.205 | 0.0328005 | 0.000924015 | 0.0656009
10533839 | 1. korrus | 563.695 | 0.0750917 | 0.00227898 | 0.150183
10533840 | 1. korrus | 561.871 | 0.0768464 | 0.00234704 | 0.153693
10533841 | 1. korrus | 545.458 | 0.0747243 | 0.00227848 | 0.149449
10533842 | 1. korrus | 1001.37 | 0.133671 | 0.00418291 | 0.267342
10533843 | 1. korrus | 314.175 | 0.0448209 | 0.00131237 | 0.0896418
10533844 | 1. korrus | 563.695 | 0.0750917 | 0.00227898 | 0.150183
10533859 | 1. korrus | 1199.77 | 0.15818 | 0.00496345 | 0.312159
10533860 | 1. korrus | 550 | 0.0757 | 0.00231 | 0.1472
10533861 | 1. korrus | 550 | 0.0757 | 0.00231 | 0.1472
10533862 | 1. korrus | 1199.77 | 0.15818 | 0.00496345 | 0.312159
10533863 | 1. korrus | 450 | 0.0627 | 0.00189 | 0.1212
10533864 | 1. korrus | 530 | 0.0731 | 0.002226 | 0.1378
10533865 | 1. korrus | 530 | 0.0731 | 0.002226 | 0.1378
10533866 | 1. korrus | 530 | 0.0731 | 0.002226 | 0.1378
10533867 | 1. korrus | 530 | 0.0731 | 0.002226 | 0.1378
10533868 | 1. korrus | 455 | 0.06335 | 0.001911 | 0.1225
10533869 | 1. korrus | 455 | 0.06335 | 0.001911 | 0.1225
10533870 | 1. korrus | 450 | 0.0627 | 0.00189 | 0.1212
10533892 | 1. korrus | 314.175 | 0.0448209 | 0.00131237 | 0.0896418
10533893 | 1. korrus | 221.205 | 0.0328005 | 0.000924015 | 0.0656009
10533894 | 1. korrus | 1150 | 0.1537 | 0.00483 | 0.3074
10533944 | 1. korrus | 561.871 | 0.0768464 | 0.00234704 | 0.153693
10533945 | 1. korrus | 545.458 | 0.0747243 | 0.00227848 | 0.149449
10533946 | 1. korrus | 221.205 | 0.0328005 | 0.000924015 | 0.0656009
10533947 | 1. korrus | 563.695 | 0.0750917 | 0.00227898 | 0.150183
10533948 | 1. korrus | 561.871 | 0.0768464 | 0.00234704 | 0.153693
10533949 | 1. korrus | 545.458 | 0.0747243 | 0.00227848 | 0.149449
10533950 | 1. korrus | 1001.37 | 0.133671 | 0.00418291 | 0.267342
10533951 | 1. korrus | 314.175 | 0.0448209 | 0.00131237 | 0.0896418
10533952 | 1. korrus | 563.695 | 0.0750917 | 0.00227898 | 0.150183
10533967 | 1. korrus | 1199.77 | 0.15818 | 0.00496345 | 0.312159
10533968 | 1. korrus | 550 | 0.0757 | 0.00231 | 0.1472
10533969 | 1. korrus | 550 | 0.0757 | 0.00231 | 0.1472
10533970 | 1. korrus | 1199.77 | 0.15818 | 0.00496345 | 0.312159
10533971 | 1. korrus | 450 | 0.0627 | 0.00189 | 0.1212
10533972 | 1. korrus | 530 | 0.0731 | 0.002226 | 0.1378
10533973 | 1. korrus | 530 | 0.0731 | 0.002226 | 0.1378
10533974 | 1. korrus | 530 | 0.0731 | 0.002226 | 0.1378
10533975 | 1. korrus | 530 | 0.0731 | 0.002226 | 0.1378
10533976 | 1. korrus | 455 | 0.06335 | 0.001911 | 0.1225
10533977 | 1. korrus | 455 | 0.06335 | 0.001911 | 0.1225
10533978 | 1. korrus | 450 | 0.0627 | 0.00189 | 0.1212
10534000 | 1. korrus | 314.175 | 0.0448209 | 0.00131237 | 0.0896418
10534001 | 1. korrus | 221.205 | 0.0328005 | 0.000924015 | 0.0656009
10534002 | 1. korrus | 1150 | 0.1537 | 0.00483 | 0.3074
10534052 | 1. korrus | 561.871 | 0.0768464 | 0.00234704 | 0.153693
10534053 | 1. korrus | 545.458 | 0.0747243 | 0.00227848 | 0.149449
10534054 | 1. korrus | 221.205 | 0.0328005 | 0.000924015 | 0.0656009
10534055 | 1. korrus | 563.695 | 0.0750917 | 0.00227898 | 0.150183
10534056 | 1. korrus | 561.871 | 0.0768464 | 0.00234704 | 0.153693
10534057 | 1. korrus | 545.458 | 0.0747243 | 0.00227848 | 0.149449
10534058 | 1. korrus | 1001.37 | 0.133671 | 0.00418291 | 0.267342
10534059 | 1. korrus | 314.175 | 0.0448209 | 0.00131237 | 0.0896418
10534060 | 1. korrus | 563.695 | 0.0750917 | 0.00227898 | 0.150183
10534075 | 1. korrus | 1199.77 | 0.15818 | 0.00496345 | 0.312159
10534076 | 1. korrus | 550 | 0.0757 | 0.00231 | 0.1472
10534077 | 1. korrus | 550 | 0.0757 | 0.00231 | 0.1472
10534078 | 1. korrus | 1199.77 | 0.15818 | 0.00496345 | 0.312159
10534079 | 1. korrus | 450 | 0.0627 | 0.00189 | 0.1212
10534080 | 1. korrus | 530 | 0.0731 | 0.002226 | 0.1378
10534081 | 1. korrus | 530 | 0.0731 | 0.002226 | 0.1378
10534082 | 1. korrus | 530 | 0.0731 | 0.002226 | 0.1378
10534083 | 1. korrus | 530 | 0.0731 | 0.002226 | 0.1378
10534084 | 1. korrus | 455 | 0.06335 | 0.001911 | 0.1225
10534085 | 1. korrus | 455 | 0.06335 | 0.001911 | 0.1225
10534086 | 1. korrus | 450 | 0.0627 | 0.00189 | 0.1212
10534108 | 1. korrus | 314.175 | 0.0448209 | 0.00131237 | 0.0896418
10534109 | 1. korrus | 221.205 | 0.0328005 | 0.000924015 | 0.0656009
10534110 | 1. korrus | 1150 | 0.1537 | 0.00483 | 0.3074
10644046 | 2. korrus | 450 | 0.0627 | 0.00189 | 0.1212
10644047 | 2. korrus | 500 | 0.0692 | 0.0021 | 0.13
10644048 | 2. korrus | 500 | 0.0692 | 0.0021 | 0.13
10644049 | 2. korrus | 500 | 0.0692 | 0.0021 | 0.13
10644050 | 2. korrus | 500 | 0.0692 | 0.0021 | 0.13
10644051 | 2. korrus | 500 | 0.0692 | 0.0021 | 0.13
10644052 | 2. korrus | 500 | 0.0692 | 0.0021 | 0.13
10644053 | 2. korrus | 440 | 0.0614 | 0.001848 | 0.1186
10644054 | 2. korrus | 450 | 0.0627 | 0.00189 | 0.1212
10644055 | 2. korrus | 440 | 0.0614 | 0.001848 | 0.1186
10644056 | 2. korrus | 130 | 0.0181403 | 0.000423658 | 0.0320806
10644057 | 2. korrus | 800 | 0.1082 | 0.00336 | 0.2122
10644058 | 2. korrus | 800 | 0.1082 | 0.00336 | 0.2122
10644059 | 2. korrus | 130 | 0.0181403 | 0.000423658 | 0.0320806
10644140 | 2. korrus | 450 | 0.0627 | 0.00189 | 0.1212
10644141 | 2. korrus | 500 | 0.0692 | 0.0021 | 0.13
10644142 | 2. korrus | 500 | 0.0692 | 0.0021 | 0.13
10644143 | 2. korrus | 500 | 0.0692 | 0.0021 | 0.13
10644144 | 2. korrus | 500 | 0.0692 | 0.0021 | 0.13
10644145 | 2. korrus | 500 | 0.0692 | 0.0021 | 0.13
10644146 | 2. korrus | 500 | 0.0692 | 0.0021 | 0.13
10644147 | 2. korrus | 440 | 0.0614 | 0.001848 | 0.1186
10644148 | 2. korrus | 450 | 0.0627 | 0.00189 | 0.1212
10644149 | 2. korrus | 440 | 0.0614 | 0.001848 | 0.1186
10644150 | 2. korrus | 130 | 0.0181403 | 0.000423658 | 0.0320806
10644151 | 2. korrus | 800 | 0.1082 | 0.00336 | 0.2122
10644152 | 2. korrus | 800 | 0.1082 | 0.00336 | 0.2122
10644153 | 2. korrus | 130 | 0.0181403 | 0.000423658 | 0.0320806
10644234 | 2. korrus | 450 | 0.0627 | 0.00189 | 0.1212
10644235 | 2. korrus | 500 | 0.0692 | 0.0021 | 0.13
10644236 | 2. korrus | 500 | 0.0692 | 0.0021 | 0.13
10644237 | 2. korrus | 500 | 0.0692 | 0.0021 | 0.13
10644238 | 2. korrus | 500 | 0.0692 | 0.0021 | 0.13
10644239 | 2. korrus | 500 | 0.0692 | 0.0021 | 0.13
10644240 | 2. korrus | 500 | 0.0692 | 0.0021 | 0.13
10644241 | 2. korrus | 440 | 0.0614 | 0.001848 | 0.1186
10644242 | 2. korrus | 450 | 0.0627 | 0.00189 | 0.1212
10644243 | 2. korrus | 440 | 0.0614 | 0.001848 | 0.1186
10644244 | 2. korrus | 130 | 0.0181403 | 0.000423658 | 0.0320806
10644245 | 2. korrus | 800 | 0.1082 | 0.00336 | 0.2122
10644246 | 2. korrus | 800 | 0.1082 | 0.00336 | 0.2122
10644247 | 2. korrus | 130 | 0.0181403 | 0.000423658 | 0.0320806
10644328 | 2. korrus | 450 | 0.0627 | 0.00189 | 0.1212
10644329 | 2. korrus | 500 | 0.0692 | 0.0021 | 0.13
10644330 | 2. korrus | 500 | 0.0692 | 0.0021 | 0.13
10644331 | 2. korrus | 500 | 0.0692 | 0.0021 | 0.13
10644332 | 2. korrus | 500 | 0.0692 | 0.0021 | 0.13
10644333 | 2. korrus | 500 | 0.0692 | 0.0021 | 0.13
10644334 | 2. korrus | 500 | 0.0692 | 0.0021 | 0.13
10644335 | 2. korrus | 440 | 0.0614 | 0.001848 | 0.1186
10644336 | 2. korrus | 450 | 0.0627 | 0.00189 | 0.1212
10644337 | 2. korrus | 440 | 0.0614 | 0.001848 | 0.1186
10644338 | 2. korrus | 130 | 0.0181403 | 0.000423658 | 0.0320806
10644339 | 2. korrus | 800 | 0.1082 | 0.00336 | 0.2122
10644340 | 2. korrus | 800 | 0.1082 | 0.00336 | 0.2122
10644341 | 2. korrus | 130 | 0.0181403 | 0.000423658 | 0.0320806
10644422 | 2. korrus | 450 | 0.0627 | 0.00189 | 0.1212
10644423 | 2. korrus | 500 | 0.0692 | 0.0021 | 0.13
10644424 | 2. korrus | 500 | 0.0692 | 0.0021 | 0.13
10644425 | 2. korrus | 500 | 0.0692 | 0.0021 | 0.13
10644426 | 2. korrus | 500 | 0.0692 | 0.0021 | 0.13
10644427 | 2. korrus | 500 | 0.0692 | 0.0021 | 0.13
10644428 | 2. korrus | 500 | 0.0692 | 0.0021 | 0.13
10644429 | 2. korrus | 440 | 0.0614 | 0.001848 | 0.1186
10644430 | 2. korrus | 450 | 0.0627 | 0.00189 | 0.1212
10644431 | 2. korrus | 440 | 0.0614 | 0.001848 | 0.1186
10644432 | 2. korrus | 130 | 0.0181403 | 0.000423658 | 0.0320806
10644433 | 2. korrus | 800 | 0.1082 | 0.00336 | 0.2122
10644434 | 2. korrus | 800 | 0.1082 | 0.00336 | 0.2122
10644435 | 2. korrus | 130 | 0.0181403 | 0.000423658 | 0.0320806
10644516 | 2. korrus | 450 | 0.0627 | 0.00189 | 0.1212
10644517 | 2. korrus | 500 | 0.0692 | 0.0021 | 0.13
10644518 | 2. korrus | 500 | 0.0692 | 0.0021 | 0.13
10644519 | 2. korrus | 500 | 0.0692 | 0.0021 | 0.13
10644520 | 2. korrus | 500 | 0.0692 | 0.0021 | 0.13
10644521 | 2. korrus | 500 | 0.0692 | 0.0021 | 0.13
10644522 | 2. korrus | 500 | 0.0692 | 0.0021 | 0.13
10644523 | 2. korrus | 440 | 0.0614 | 0.001848 | 0.1186
10644524 | 2. korrus | 450 | 0.0627 | 0.00189 | 0.1212
10644525 | 2. korrus | 440 | 0.0614 | 0.001848 | 0.1186
10644526 | 2. korrus | 130 | 0.0181403 | 0.000423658 | 0.0320806
10644527 | 2. korrus | 800 | 0.1082 | 0.00336 | 0.2122
10644528 | 2. korrus | 800 | 0.1082 | 0.00336 | 0.2122
10644529 | 2. korrus | 130 | 0.0181403 | 0.000423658 | 0.0320806

# IfcMember: Rectangular Mullion:NEW 80x70mm (576)
Type - PredefinedType: MULLION; Material: LUMION_dark steel window frames
Type - Pset_MemberCommon - IsExternal: no
Pset_MemberCommon - Reference: NEW 80x70mm
Pset_QuantityTakeOff - Reference: NEW 80x70mm
Name (Rectangular Mullion:NEW 80x70mm:...) | In | Span (mm) = Length (mm) | CrossSectionArea (m2) | NetVolume (m3) | NetSurfaceArea (m2)
10386045 | 3. korrus | 1165 | 0.18035 | 0.006524 | 0.3607 | Pset_MemberCommon - IsExternal: yes
10386046 | 3. korrus | 1165 | 0.18035 | 0.006524 | 0.3607 | Pset_MemberCommon - IsExternal: yes
10389353 | 3. korrus | 1165 | 0.18035 | 0.006524 | 0.3607
10389354 | 3. korrus | 1165 | 0.18035 | 0.006524 | 0.3607
10389372 | 3. korrus | 1165 | 0.18035 | 0.006524 | 0.3607
10389373 | 3. korrus | 1165 | 0.18035 | 0.006524 | 0.3607
10389391 | 3. korrus | 1165 | 0.18035 | 0.006524 | 0.3607
10389392 | 3. korrus | 1165 | 0.18035 | 0.006524 | 0.3607
10389444 | 3. korrus | 1165 | 0.18035 | 0.006524 | 0.3607
10389445 | 3. korrus | 1165 | 0.18035 | 0.006524 | 0.3607
10389463 | 3. korrus | 1165 | 0.18035 | 0.006524 | 0.3607
10389464 | 3. korrus | 1165 | 0.18035 | 0.006524 | 0.3607
10389482 | 3. korrus | 1165 | 0.18035 | 0.006524 | 0.3607
10389483 | 3. korrus | 1165 | 0.18035 | 0.006524 | 0.3607
10389501 | 3. korrus | 1165 | 0.18035 | 0.006524 | 0.3607
10389502 | 3. korrus | 1165 | 0.18035 | 0.006524 | 0.3607
10515261 | 1. korrus | 552.945 | 0.0861798 | 0.00300317 | 0.17236
10515262 | 1. korrus | 530.965 | 0.084667 | 0.00295187 | 0.169334
10515263 | 1. korrus | 515.878 | 0.0824211 | 0.00286799 | 0.164842
10515264 | 1. korrus | 506.224 | 0.0809834 | 0.00281432 | 0.161967
10515265 | 1. korrus | 601.187 | 0.0951247 | 0.00334226 | 0.190249
10515266 | 1. korrus | 506.224 | 0.0809834 | 0.00281432 | 0.161967
10515267 | 1. korrus | 515.878 | 0.0824211 | 0.00286799 | 0.164842
10515268 | 1. korrus | 530.965 | 0.084667 | 0.00295187 | 0.169334
10515269 | 1. korrus | 601.187 | 0.0951247 | 0.00334226 | 0.190249
10515270 | 1. korrus | 552.945 | 0.0861798 | 0.00300317 | 0.17236
10515271 | 1. korrus | 335.569 | 0.0431609 | 0.00139382 | 0.0807218
10515272 | 1. korrus | 1190 | 0.1841 | 0.006664 | 0.3626
10515273 | 1. korrus | 513.633 | 0.0702117 | 0.00240763 | 0.134823
10515274 | 1. korrus | 1190 | 0.1841 | 0.006664 | 0.3626
10515277 | 1. korrus | 717.87 | 0.101211 | 0.00356909 | 0.196821
10515278 | 1. korrus | 1190 | 0.1841 | 0.006664 | 0.3626
10515281 | 1. korrus | 717.87 | 0.101211 | 0.00356909 | 0.196821
10515282 | 1. korrus | 1190 | 0.1841 | 0.006664 | 0.3626
10515285 | 1. korrus | 513.633 | 0.0702117 | 0.00240763 | 0.134823
10515286 | 1. korrus | 1190 | 0.1841 | 0.006664 | 0.3626
10515287 | 1. korrus | 335.569 | 0.0431609 | 0.00139382 | 0.0807218
10515288 | 1. korrus | 1190 | 0.1841 | 0.006664 | 0.3626
10515289 | 1. korrus | 420 | 0.0686 | 0.002352 | 0.1372
10515290 | 1. korrus | 385 | 0.06335 | 0.002156 | 0.1267
10515291 | 1. korrus | 385 | 0.06335 | 0.002156 | 0.1267
10515292 | 1. korrus | 410 | 0.0671 | 0.002296 | 0.1342
10515293 | 1. korrus | 385 | 0.06335 | 0.002156 | 0.1267
10515294 | 1. korrus | 385 | 0.06335 | 0.002156 | 0.1267
10515295 | 1. korrus | 420 | 0.0686 | 0.002352 | 0.1372
10515296 | 1. korrus | 410 | 0.0671 | 0.002296 | 0.1342
10522686 | 1. korrus | 552.945 | 0.0861798 | 0.00300317 | 0.17236
10522687 | 1. korrus | 530.965 | 0.084667 | 0.00295187 | 0.169334
10522688 | 1. korrus | 515.878 | 0.0824211 | 0.00286799 | 0.164842
10522689 | 1. korrus | 506.224 | 0.0809834 | 0.00281432 | 0.161967
10522690 | 1. korrus | 601.187 | 0.0951247 | 0.00334226 | 0.190249
10522691 | 1. korrus | 506.224 | 0.0809834 | 0.00281432 | 0.161967
10522692 | 1. korrus | 515.878 | 0.0824211 | 0.00286799 | 0.164842
10522693 | 1. korrus | 530.965 | 0.084667 | 0.00295187 | 0.169334
10522694 | 1. korrus | 601.187 | 0.0951247 | 0.00334226 | 0.190249
10522695 | 1. korrus | 552.945 | 0.0861798 | 0.00300317 | 0.17236
10522696 | 1. korrus | 335.569 | 0.0431609 | 0.00139382 | 0.0807218
10522697 | 1. korrus | 1190 | 0.1841 | 0.006664 | 0.3626
10522698 | 1. korrus | 513.633 | 0.0702117 | 0.00240763 | 0.134823
10522699 | 1. korrus | 1190 | 0.1841 | 0.006664 | 0.3626
10522702 | 1. korrus | 717.87 | 0.101211 | 0.00356909 | 0.196821
10522703 | 1. korrus | 1190 | 0.1841 | 0.006664 | 0.3626
10522706 | 1. korrus | 717.87 | 0.101211 | 0.00356909 | 0.196821
10522707 | 1. korrus | 1190 | 0.1841 | 0.006664 | 0.3626
10522710 | 1. korrus | 513.633 | 0.0702117 | 0.00240763 | 0.134823
10522711 | 1. korrus | 1190 | 0.1841 | 0.006664 | 0.3626
10522712 | 1. korrus | 335.569 | 0.0431609 | 0.00139382 | 0.0807218
10522713 | 1. korrus | 1190 | 0.1841 | 0.006664 | 0.3626
10522714 | 1. korrus | 420 | 0.0686 | 0.002352 | 0.1372
10522715 | 1. korrus | 385 | 0.06335 | 0.002156 | 0.1267
10522716 | 1. korrus | 385 | 0.06335 | 0.002156 | 0.1267
10522717 | 1. korrus | 410 | 0.0671 | 0.002296 | 0.1342
10522718 | 1. korrus | 385 | 0.06335 | 0.002156 | 0.1267
10522719 | 1. korrus | 385 | 0.06335 | 0.002156 | 0.1267
10522720 | 1. korrus | 420 | 0.0686 | 0.002352 | 0.1372
10522721 | 1. korrus | 410 | 0.0671 | 0.002296 | 0.1342
10522843 | 1. korrus | 552.945 | 0.0861798 | 0.00300317 | 0.17236
10522844 | 1. korrus | 530.965 | 0.084667 | 0.00295187 | 0.169334
10522845 | 1. korrus | 515.878 | 0.0824211 | 0.00286799 | 0.164842
10522846 | 1. korrus | 506.224 | 0.0809834 | 0.00281432 | 0.161967
10522847 | 1. korrus | 601.187 | 0.0951247 | 0.00334226 | 0.190249
10522848 | 1. korrus | 506.224 | 0.0809834 | 0.00281432 | 0.161967
10522849 | 1. korrus | 515.878 | 0.0824211 | 0.00286799 | 0.164842
10522850 | 1. korrus | 530.965 | 0.084667 | 0.00295187 | 0.169334
10522851 | 1. korrus | 601.187 | 0.0951247 | 0.00334226 | 0.190249
10522852 | 1. korrus | 552.945 | 0.0861798 | 0.00300317 | 0.17236
10522853 | 1. korrus | 335.569 | 0.0431609 | 0.00139382 | 0.0807218
10522854 | 1. korrus | 1190 | 0.1841 | 0.006664 | 0.3626
10522855 | 1. korrus | 513.633 | 0.0702117 | 0.00240763 | 0.134823
10522856 | 1. korrus | 1190 | 0.1841 | 0.006664 | 0.3626
10522859 | 1. korrus | 717.87 | 0.101211 | 0.00356909 | 0.196821
10522860 | 1. korrus | 1190 | 0.1841 | 0.006664 | 0.3626
10522863 | 1. korrus | 717.87 | 0.101211 | 0.00356909 | 0.196821
10522864 | 1. korrus | 1190 | 0.1841 | 0.006664 | 0.3626
10522867 | 1. korrus | 513.633 | 0.0702117 | 0.00240763 | 0.134823
10522868 | 1. korrus | 1190 | 0.1841 | 0.006664 | 0.3626
10522869 | 1. korrus | 335.569 | 0.0431609 | 0.00139382 | 0.0807218
10522870 | 1. korrus | 1190 | 0.1841 | 0.006664 | 0.3626
10522871 | 1. korrus | 420 | 0.0686 | 0.002352 | 0.1372
10522872 | 1. korrus | 385 | 0.06335 | 0.002156 | 0.1267
10522873 | 1. korrus | 385 | 0.06335 | 0.002156 | 0.1267
10522874 | 1. korrus | 410 | 0.0671 | 0.002296 | 0.1342
10522875 | 1. korrus | 385 | 0.06335 | 0.002156 | 0.1267
10522876 | 1. korrus | 385 | 0.06335 | 0.002156 | 0.1267
10522877 | 1. korrus | 420 | 0.0686 | 0.002352 | 0.1372
10522878 | 1. korrus | 410 | 0.0671 | 0.002296 | 0.1342
10522993 | 1. korrus | 552.945 | 0.0861798 | 0.00300317 | 0.17236
10522994 | 1. korrus | 530.965 | 0.084667 | 0.00295187 | 0.169334
10522995 | 1. korrus | 515.878 | 0.0824211 | 0.00286799 | 0.164842
10522996 | 1. korrus | 506.224 | 0.0809834 | 0.00281432 | 0.161967
10522997 | 1. korrus | 601.187 | 0.0951247 | 0.00334226 | 0.190249
10522998 | 1. korrus | 506.224 | 0.0809834 | 0.00281432 | 0.161967
10522999 | 1. korrus | 515.878 | 0.0824211 | 0.00286799 | 0.164842
10523000 | 1. korrus | 530.965 | 0.084667 | 0.00295187 | 0.169334
10523001 | 1. korrus | 601.187 | 0.0951247 | 0.00334226 | 0.190249
10523002 | 1. korrus | 552.945 | 0.0861798 | 0.00300317 | 0.17236
10523003 | 1. korrus | 335.569 | 0.0431609 | 0.00139382 | 0.0807218
10523004 | 1. korrus | 1190 | 0.1841 | 0.006664 | 0.3626
10523005 | 1. korrus | 513.633 | 0.0702117 | 0.00240763 | 0.134823
10523006 | 1. korrus | 1190 | 0.1841 | 0.006664 | 0.3626
10523009 | 1. korrus | 717.87 | 0.101211 | 0.00356909 | 0.196821
10523010 | 1. korrus | 1190 | 0.1841 | 0.006664 | 0.3626
10523013 | 1. korrus | 717.87 | 0.101211 | 0.00356909 | 0.196821
10523014 | 1. korrus | 1190 | 0.1841 | 0.006664 | 0.3626
10523017 | 1. korrus | 513.633 | 0.0702117 | 0.00240763 | 0.134823
10523018 | 1. korrus | 1190 | 0.1841 | 0.006664 | 0.3626
10523019 | 1. korrus | 335.569 | 0.0431609 | 0.00139382 | 0.0807218
10523020 | 1. korrus | 1190 | 0.1841 | 0.006664 | 0.3626
10523021 | 1. korrus | 420 | 0.0686 | 0.002352 | 0.1372
10523022 | 1. korrus | 385 | 0.06335 | 0.002156 | 0.1267
10523023 | 1. korrus | 385 | 0.06335 | 0.002156 | 0.1267
10523024 | 1. korrus | 410 | 0.0671 | 0.002296 | 0.1342
10523025 | 1. korrus | 385 | 0.06335 | 0.002156 | 0.1267
10523026 | 1. korrus | 385 | 0.06335 | 0.002156 | 0.1267
10523027 | 1. korrus | 420 | 0.0686 | 0.002352 | 0.1372
10523028 | 1. korrus | 410 | 0.0671 | 0.002296 | 0.1342
10523159 | 1. korrus | 552.945 | 0.0861798 | 0.00300317 | 0.17236
10523160 | 1. korrus | 530.965 | 0.084667 | 0.00295187 | 0.169334
10523161 | 1. korrus | 515.878 | 0.0824211 | 0.00286799 | 0.164842
10523162 | 1. korrus | 506.224 | 0.0809834 | 0.00281432 | 0.161967
10523163 | 1. korrus | 601.187 | 0.0951247 | 0.00334226 | 0.190249
10523164 | 1. korrus | 506.224 | 0.0809834 | 0.00281432 | 0.161967
10523165 | 1. korrus | 515.878 | 0.0824211 | 0.00286799 | 0.164842
10523166 | 1. korrus | 530.965 | 0.084667 | 0.00295187 | 0.169334
10523167 | 1. korrus | 601.187 | 0.0951247 | 0.00334226 | 0.190249
10523168 | 1. korrus | 552.945 | 0.0861798 | 0.00300317 | 0.17236
10523169 | 1. korrus | 335.569 | 0.0431609 | 0.00139382 | 0.0807218
10523170 | 1. korrus | 1190 | 0.1841 | 0.006664 | 0.3626
10523171 | 1. korrus | 513.633 | 0.0702117 | 0.00240763 | 0.134823
10523172 | 1. korrus | 1190 | 0.1841 | 0.006664 | 0.3626
10523175 | 1. korrus | 717.87 | 0.101211 | 0.00356909 | 0.196821
10523176 | 1. korrus | 1190 | 0.1841 | 0.006664 | 0.3626
10523179 | 1. korrus | 717.87 | 0.101211 | 0.00356909 | 0.196821
10523180 | 1. korrus | 1190 | 0.1841 | 0.006664 | 0.3626
10523183 | 1. korrus | 513.633 | 0.0702117 | 0.00240763 | 0.134823
10523184 | 1. korrus | 1190 | 0.1841 | 0.006664 | 0.3626
10523185 | 1. korrus | 335.569 | 0.0431609 | 0.00139382 | 0.0807218
10523186 | 1. korrus | 1190 | 0.1841 | 0.006664 | 0.3626
10523187 | 1. korrus | 420 | 0.0686 | 0.002352 | 0.1372
10523188 | 1. korrus | 385 | 0.06335 | 0.002156 | 0.1267
10523189 | 1. korrus | 385 | 0.06335 | 0.002156 | 0.1267
10523190 | 1. korrus | 410 | 0.0671 | 0.002296 | 0.1342
10523191 | 1. korrus | 385 | 0.06335 | 0.002156 | 0.1267
10523192 | 1. korrus | 385 | 0.06335 | 0.002156 | 0.1267
10523193 | 1. korrus | 420 | 0.0686 | 0.002352 | 0.1372
10523194 | 1. korrus | 410 | 0.0671 | 0.002296 | 0.1342
10523309 | 1. korrus | 552.945 | 0.0861798 | 0.00300317 | 0.17236
10523310 | 1. korrus | 530.965 | 0.084667 | 0.00295187 | 0.169334
10523311 | 1. korrus | 515.878 | 0.0824211 | 0.00286799 | 0.164842
10523312 | 1. korrus | 506.224 | 0.0809834 | 0.00281432 | 0.161967
10523313 | 1. korrus | 601.187 | 0.0951247 | 0.00334226 | 0.190249
10523314 | 1. korrus | 506.224 | 0.0809834 | 0.00281432 | 0.161967
10523315 | 1. korrus | 515.878 | 0.0824211 | 0.00286799 | 0.164842
10523316 | 1. korrus | 530.965 | 0.084667 | 0.00295187 | 0.169334
10523317 | 1. korrus | 601.187 | 0.0951247 | 0.00334226 | 0.190249
10523318 | 1. korrus | 552.945 | 0.0861798 | 0.00300317 | 0.17236
10523319 | 1. korrus | 335.569 | 0.0431609 | 0.00139382 | 0.0807218
10523320 | 1. korrus | 1190 | 0.1841 | 0.006664 | 0.3626
10523321 | 1. korrus | 513.633 | 0.0702117 | 0.00240763 | 0.134823
10523322 | 1. korrus | 1190 | 0.1841 | 0.006664 | 0.3626
10523325 | 1. korrus | 717.87 | 0.101211 | 0.00356909 | 0.196821
10523326 | 1. korrus | 1190 | 0.1841 | 0.006664 | 0.3626
10523329 | 1. korrus | 717.87 | 0.101211 | 0.00356909 | 0.196821
10523330 | 1. korrus | 1190 | 0.1841 | 0.006664 | 0.3626
10523333 | 1. korrus | 513.633 | 0.0702117 | 0.00240763 | 0.134823
10523334 | 1. korrus | 1190 | 0.1841 | 0.006664 | 0.3626
10523335 | 1. korrus | 335.569 | 0.0431609 | 0.00139382 | 0.0807218
10523336 | 1. korrus | 1190 | 0.1841 | 0.006664 | 0.3626
10523337 | 1. korrus | 420 | 0.0686 | 0.002352 | 0.1372
10523338 | 1. korrus | 385 | 0.06335 | 0.002156 | 0.1267
10523339 | 1. korrus | 385 | 0.06335 | 0.002156 | 0.1267
10523340 | 1. korrus | 410 | 0.0671 | 0.002296 | 0.1342
10523341 | 1. korrus | 385 | 0.06335 | 0.002156 | 0.1267
10523342 | 1. korrus | 385 | 0.06335 | 0.002156 | 0.1267
10523343 | 1. korrus | 420 | 0.0686 | 0.002352 | 0.1372
10523344 | 1. korrus | 410 | 0.0671 | 0.002296 | 0.1342
10532985 | 1. korrus | 450 | 0.0731 | 0.00252 | 0.1406
10532986 | 1. korrus | 530 | 0.0851 | 0.002968 | 0.159
10532987 | 1. korrus | 530 | 0.0851 | 0.002968 | 0.159
10532988 | 1. korrus | 530 | 0.0851 | 0.002968 | 0.159
10532989 | 1. korrus | 530 | 0.0851 | 0.002968 | 0.159
10532990 | 1. korrus | 455 | 0.07385 | 0.002548 | 0.1421
10532991 | 1. korrus | 455 | 0.07385 | 0.002548 | 0.1421
10532992 | 1. korrus | 450 | 0.0731 | 0.00252 | 0.1406
10532993 | 1. korrus | 450 | 0.0731 | 0.00252 | 0.1462
10532994 | 1. korrus | 450 | 0.0731 | 0.00252 | 0.1462
10533034 | 1. korrus | 1399.3 | 0.205976 | 0.00747244 | 0.411953
10533035 | 1. korrus | 1585.12 | 0.234087 | 0.00852592 | 0.468174
10533036 | 1. korrus | 1713.11 | 0.25344 | 0.00925107 | 0.506881
10533037 | 1. korrus | 1713.11 | 0.25344 | 0.00925107 | 0.506881
10533038 | 1. korrus | 1585.12 | 0.234087 | 0.00852592 | 0.468174
10533039 | 1. korrus | 1399.3 | 0.205976 | 0.00747244 | 0.411953
10533093 | 1. korrus | 450 | 0.0731 | 0.00252 | 0.1406
10533094 | 1. korrus | 530 | 0.0851 | 0.002968 | 0.159
10533095 | 1. korrus | 530 | 0.0851 | 0.002968 | 0.159
10533096 | 1. korrus | 530 | 0.0851 | 0.002968 | 0.159
10533097 | 1. korrus | 530 | 0.0851 | 0.002968 | 0.159
10533098 | 1. korrus | 455 | 0.07385 | 0.002548 | 0.1421
10533099 | 1. korrus | 455 | 0.07385 | 0.002548 | 0.1421
10533100 | 1. korrus | 450 | 0.0731 | 0.00252 | 0.1406
10533101 | 1. korrus | 450 | 0.0731 | 0.00252 | 0.1462
10533102 | 1. korrus | 450 | 0.0731 | 0.00252 | 0.1462
10533139 | 1. korrus | 1399.3 | 0.205976 | 0.00747244 | 0.411953
10533140 | 1. korrus | 1585.12 | 0.234087 | 0.00852592 | 0.468174
10533141 | 1. korrus | 1713.11 | 0.25344 | 0.00925107 | 0.506881
10533142 | 1. korrus | 1713.11 | 0.25344 | 0.00925107 | 0.506881
10533143 | 1. korrus | 1585.12 | 0.234087 | 0.00852592 | 0.468174
10533144 | 1. korrus | 1399.3 | 0.205976 | 0.00747244 | 0.411953
10533201 | 1. korrus | 450 | 0.0731 | 0.00252 | 0.1406
10533202 | 1. korrus | 530 | 0.0851 | 0.002968 | 0.159
10533203 | 1. korrus | 530 | 0.0851 | 0.002968 | 0.159
10533204 | 1. korrus | 530 | 0.0851 | 0.002968 | 0.159
10533205 | 1. korrus | 530 | 0.0851 | 0.002968 | 0.159
10533206 | 1. korrus | 455 | 0.07385 | 0.002548 | 0.1421
10533207 | 1. korrus | 455 | 0.07385 | 0.002548 | 0.1421
10533208 | 1. korrus | 450 | 0.0731 | 0.00252 | 0.1406
10533209 | 1. korrus | 450 | 0.0731 | 0.00252 | 0.1462
10533210 | 1. korrus | 450 | 0.0731 | 0.00252 | 0.1462
10533247 | 1. korrus | 1399.3 | 0.205976 | 0.00747244 | 0.411953
10533248 | 1. korrus | 1585.12 | 0.234087 | 0.00852592 | 0.468174
10533249 | 1. korrus | 1713.11 | 0.25344 | 0.00925107 | 0.506881
10533250 | 1. korrus | 1713.11 | 0.25344 | 0.00925107 | 0.506881
10533251 | 1. korrus | 1585.12 | 0.234087 | 0.00852592 | 0.468174
10533252 | 1. korrus | 1399.3 | 0.205976 | 0.00747244 | 0.411953
10533309 | 1. korrus | 450 | 0.0731 | 0.00252 | 0.1406
10533310 | 1. korrus | 530 | 0.0851 | 0.002968 | 0.159
10533311 | 1. korrus | 530 | 0.0851 | 0.002968 | 0.159
10533312 | 1. korrus | 530 | 0.0851 | 0.002968 | 0.159
10533313 | 1. korrus | 530 | 0.0851 | 0.002968 | 0.159
10533314 | 1. korrus | 455 | 0.07385 | 0.002548 | 0.1421
10533315 | 1. korrus | 455 | 0.07385 | 0.002548 | 0.1421
10533316 | 1. korrus | 450 | 0.0731 | 0.00252 | 0.1406
10533317 | 1. korrus | 450 | 0.0731 | 0.00252 | 0.1462
10533318 | 1. korrus | 450 | 0.0731 | 0.00252 | 0.1462
10533355 | 1. korrus | 1399.3 | 0.205976 | 0.00747244 | 0.411953
10533356 | 1. korrus | 1585.12 | 0.234087 | 0.00852592 | 0.468174
10533357 | 1. korrus | 1713.11 | 0.25344 | 0.00925107 | 0.506881
10533358 | 1. korrus | 1713.11 | 0.25344 | 0.00925107 | 0.506881
10533359 | 1. korrus | 1585.12 | 0.234087 | 0.00852592 | 0.468174
10533360 | 1. korrus | 1399.3 | 0.205976 | 0.00747244 | 0.411953
10533417 | 1. korrus | 450 | 0.0731 | 0.00252 | 0.1406
10533418 | 1. korrus | 530 | 0.0851 | 0.002968 | 0.159
10533419 | 1. korrus | 530 | 0.0851 | 0.002968 | 0.159
10533420 | 1. korrus | 530 | 0.0851 | 0.002968 | 0.159
10533421 | 1. korrus | 530 | 0.0851 | 0.002968 | 0.159
10533422 | 1. korrus | 455 | 0.07385 | 0.002548 | 0.1421
10533423 | 1. korrus | 455 | 0.07385 | 0.002548 | 0.1421
10533424 | 1. korrus | 450 | 0.0731 | 0.00252 | 0.1406
10533425 | 1. korrus | 450 | 0.0731 | 0.00252 | 0.1462
10533426 | 1. korrus | 450 | 0.0731 | 0.00252 | 0.1462
10533463 | 1. korrus | 1399.3 | 0.205976 | 0.00747244 | 0.411953
10533464 | 1. korrus | 1585.12 | 0.234087 | 0.00852592 | 0.468174
10533465 | 1. korrus | 1713.11 | 0.25344 | 0.00925107 | 0.506881
10533466 | 1. korrus | 1713.11 | 0.25344 | 0.00925107 | 0.506881
10533467 | 1. korrus | 1585.12 | 0.234087 | 0.00852592 | 0.468174
10533468 | 1. korrus | 1399.3 | 0.205976 | 0.00747244 | 0.411953
10533525 | 1. korrus | 450 | 0.0731 | 0.00252 | 0.1406
10533526 | 1. korrus | 530 | 0.0851 | 0.002968 | 0.159
10533527 | 1. korrus | 530 | 0.0851 | 0.002968 | 0.159
10533528 | 1. korrus | 530 | 0.0851 | 0.002968 | 0.159
10533529 | 1. korrus | 530 | 0.0851 | 0.002968 | 0.159
10533530 | 1. korrus | 455 | 0.07385 | 0.002548 | 0.1421
10533531 | 1. korrus | 455 | 0.07385 | 0.002548 | 0.1421
10533532 | 1. korrus | 450 | 0.0731 | 0.00252 | 0.1406
10533533 | 1. korrus | 450 | 0.0731 | 0.00252 | 0.1462
10533534 | 1. korrus | 450 | 0.0731 | 0.00252 | 0.1462
10533571 | 1. korrus | 1399.3 | 0.205976 | 0.00747244 | 0.411953
10533572 | 1. korrus | 1585.12 | 0.234087 | 0.00852592 | 0.468174
10533573 | 1. korrus | 1713.11 | 0.25344 | 0.00925107 | 0.506881
10533574 | 1. korrus | 1713.11 | 0.25344 | 0.00925107 | 0.506881
10533575 | 1. korrus | 1585.12 | 0.234087 | 0.00852592 | 0.468174
10533576 | 1. korrus | 1399.3 | 0.205976 | 0.00747244 | 0.411953
10533633 | 1. korrus | 450 | 0.0731 | 0.00252 | 0.1406
10533634 | 1. korrus | 530 | 0.0851 | 0.002968 | 0.159
10533635 | 1. korrus | 530 | 0.0851 | 0.002968 | 0.159
10533636 | 1. korrus | 530 | 0.0851 | 0.002968 | 0.159
10533637 | 1. korrus | 530 | 0.0851 | 0.002968 | 0.159
10533638 | 1. korrus | 455 | 0.07385 | 0.002548 | 0.1421
10533639 | 1. korrus | 455 | 0.07385 | 0.002548 | 0.1421
10533640 | 1. korrus | 450 | 0.0731 | 0.00252 | 0.1406
10533641 | 1. korrus | 450 | 0.0731 | 0.00252 | 0.1462
10533642 | 1. korrus | 450 | 0.0731 | 0.00252 | 0.1462
10533679 | 1. korrus | 1399.3 | 0.205976 | 0.00747244 | 0.411953
10533680 | 1. korrus | 1585.12 | 0.234087 | 0.00852592 | 0.468174
10533681 | 1. korrus | 1713.11 | 0.25344 | 0.00925107 | 0.506881
10533682 | 1. korrus | 1713.11 | 0.25344 | 0.00925107 | 0.506881
10533683 | 1. korrus | 1585.12 | 0.234087 | 0.00852592 | 0.468174
10533684 | 1. korrus | 1399.3 | 0.205976 | 0.00747244 | 0.411953
10533741 | 1. korrus | 450 | 0.0731 | 0.00252 | 0.1406
10533742 | 1. korrus | 530 | 0.0851 | 0.002968 | 0.159
10533743 | 1. korrus | 530 | 0.0851 | 0.002968 | 0.159
10533744 | 1. korrus | 530 | 0.0851 | 0.002968 | 0.159
10533745 | 1. korrus | 530 | 0.0851 | 0.002968 | 0.159
10533746 | 1. korrus | 455 | 0.07385 | 0.002548 | 0.1421
10533747 | 1. korrus | 455 | 0.07385 | 0.002548 | 0.1421
10533748 | 1. korrus | 450 | 0.0731 | 0.00252 | 0.1406
10533749 | 1. korrus | 450 | 0.0731 | 0.00252 | 0.1462
10533750 | 1. korrus | 450 | 0.0731 | 0.00252 | 0.1462
10533787 | 1. korrus | 1399.3 | 0.205976 | 0.00747244 | 0.411953
10533788 | 1. korrus | 1585.12 | 0.234087 | 0.00852592 | 0.468174
10533789 | 1. korrus | 1713.11 | 0.25344 | 0.00925107 | 0.506881
10533790 | 1. korrus | 1713.11 | 0.25344 | 0.00925107 | 0.506881
10533791 | 1. korrus | 1585.12 | 0.234087 | 0.00852592 | 0.468174
10533792 | 1. korrus | 1399.3 | 0.205976 | 0.00747244 | 0.411953
10533849 | 1. korrus | 450 | 0.0731 | 0.00252 | 0.1406
10533850 | 1. korrus | 530 | 0.0851 | 0.002968 | 0.159
10533851 | 1. korrus | 530 | 0.0851 | 0.002968 | 0.159
10533852 | 1. korrus | 530 | 0.0851 | 0.002968 | 0.159
10533853 | 1. korrus | 530 | 0.0851 | 0.002968 | 0.159
10533854 | 1. korrus | 455 | 0.07385 | 0.002548 | 0.1421
10533855 | 1. korrus | 455 | 0.07385 | 0.002548 | 0.1421
10533856 | 1. korrus | 450 | 0.0731 | 0.00252 | 0.1406
10533857 | 1. korrus | 450 | 0.0731 | 0.00252 | 0.1462
10533858 | 1. korrus | 450 | 0.0731 | 0.00252 | 0.1462
10533895 | 1. korrus | 1399.3 | 0.205976 | 0.00747244 | 0.411953
10533896 | 1. korrus | 1585.12 | 0.234087 | 0.00852592 | 0.468174
10533897 | 1. korrus | 1713.11 | 0.25344 | 0.00925107 | 0.506881
10533898 | 1. korrus | 1713.11 | 0.25344 | 0.00925107 | 0.506881
10533899 | 1. korrus | 1585.12 | 0.234087 | 0.00852592 | 0.468174
10533900 | 1. korrus | 1399.3 | 0.205976 | 0.00747244 | 0.411953
10533957 | 1. korrus | 450 | 0.0731 | 0.00252 | 0.1406
10533958 | 1. korrus | 530 | 0.0851 | 0.002968 | 0.159
10533959 | 1. korrus | 530 | 0.0851 | 0.002968 | 0.159
10533960 | 1. korrus | 530 | 0.0851 | 0.002968 | 0.159
10533961 | 1. korrus | 530 | 0.0851 | 0.002968 | 0.159
10533962 | 1. korrus | 455 | 0.07385 | 0.002548 | 0.1421
10533963 | 1. korrus | 455 | 0.07385 | 0.002548 | 0.1421
10533964 | 1. korrus | 450 | 0.0731 | 0.00252 | 0.1406
10533965 | 1. korrus | 450 | 0.0731 | 0.00252 | 0.1462
10533966 | 1. korrus | 450 | 0.0731 | 0.00252 | 0.1462
10534003 | 1. korrus | 1399.3 | 0.205976 | 0.00747244 | 0.411953
10534004 | 1. korrus | 1585.12 | 0.234087 | 0.00852592 | 0.468174
10534005 | 1. korrus | 1713.11 | 0.25344 | 0.00925107 | 0.506881
10534006 | 1. korrus | 1713.11 | 0.25344 | 0.00925107 | 0.506881
10534007 | 1. korrus | 1585.12 | 0.234087 | 0.00852592 | 0.468174
10534008 | 1. korrus | 1399.3 | 0.205976 | 0.00747244 | 0.411953
10534065 | 1. korrus | 450 | 0.0731 | 0.00252 | 0.1406
10534066 | 1. korrus | 530 | 0.0851 | 0.002968 | 0.159
10534067 | 1. korrus | 530 | 0.0851 | 0.002968 | 0.159
10534068 | 1. korrus | 530 | 0.0851 | 0.002968 | 0.159
10534069 | 1. korrus | 530 | 0.0851 | 0.002968 | 0.159
10534070 | 1. korrus | 455 | 0.07385 | 0.002548 | 0.1421
10534071 | 1. korrus | 455 | 0.07385 | 0.002548 | 0.1421
10534072 | 1. korrus | 450 | 0.0731 | 0.00252 | 0.1406
10534073 | 1. korrus | 450 | 0.0731 | 0.00252 | 0.1462
10534074 | 1. korrus | 450 | 0.0731 | 0.00252 | 0.1462
10534111 | 1. korrus | 1399.3 | 0.205976 | 0.00747244 | 0.411953
10534112 | 1. korrus | 1585.12 | 0.234087 | 0.00852592 | 0.468174
10534113 | 1. korrus | 1713.11 | 0.25344 | 0.00925107 | 0.506881
10534114 | 1. korrus | 1713.11 | 0.25344 | 0.00925107 | 0.506881
10534115 | 1. korrus | 1585.12 | 0.234087 | 0.00852592 | 0.468174
10534116 | 1. korrus | 1399.3 | 0.205976 | 0.00747244 | 0.411953
10644030 | 2. korrus | 373.202 | 0.0487593 | 0.0016023 | 0.0919187
10644031 | 2. korrus | 740 | 0.1166 | 0.004144 | 0.2276
10644032 | 2. korrus | 556.564 | 0.0766269 | 0.00264686 | 0.147654
10644033 | 2. korrus | 740 | 0.1166 | 0.004144 | 0.2276
10644034 | 2. korrus | 686.341 | 0.0963349 | 0.00338539 | 0.18707
10644035 | 2. korrus | 740 | 0.1166 | 0.004144 | 0.2276
10644036 | 2. korrus | 766.437 | 0.108492 | 0.0038409 | 0.211385
10644037 | 2. korrus | 740 | 0.1166 | 0.004144 | 0.2276
10644038 | 2. korrus | 766.437 | 0.108492 | 0.0038409 | 0.211385
10644039 | 2. korrus | 740 | 0.1166 | 0.004144 | 0.2276
10644040 | 2. korrus | 686.341 | 0.0963349 | 0.00338539 | 0.18707
10644041 | 2. korrus | 740 | 0.1166 | 0.004144 | 0.2276
10644042 | 2. korrus | 556.564 | 0.0766269 | 0.00264686 | 0.147654
10644043 | 2. korrus | 740 | 0.1166 | 0.004144 | 0.2276
10644044 | 2. korrus | 373.202 | 0.0487593 | 0.0016023 | 0.0919187
10644045 | 2. korrus | 740 | 0.1166 | 0.004144 | 0.2276
10644060 | 2. korrus | 506.562 | 0.0810193 | 0.00281565 | 0.162039
10644061 | 2. korrus | 516.766 | 0.0825386 | 0.00287237 | 0.165077
10644062 | 2. korrus | 532.779 | 0.0849226 | 0.00296138 | 0.169845
10644063 | 2. korrus | 556.258 | 0.0867182 | 0.00302361 | 0.173436
10644064 | 2. korrus | 506.562 | 0.0810193 | 0.00281565 | 0.162039
10644065 | 2. korrus | 516.766 | 0.0825386 | 0.00287237 | 0.165077
10644066 | 2. korrus | 532.779 | 0.0849226 | 0.00296138 | 0.169845
10644067 | 2. korrus | 556.258 | 0.0867182 | 0.00302361 | 0.173436
10644068 | 2. korrus | 410 | 0.0671 | 0.002296 | 0.1342
10644069 | 2. korrus | 420 | 0.0686 | 0.002352 | 0.1372
10644070 | 2. korrus | 420 | 0.0686 | 0.002352 | 0.1372
10644071 | 2. korrus | 420 | 0.0686 | 0.002352 | 0.1372
10644072 | 2. korrus | 420 | 0.0686 | 0.002352 | 0.1372
10644073 | 2. korrus | 420 | 0.0686 | 0.002352 | 0.1372
10644074 | 2. korrus | 420 | 0.0686 | 0.002352 | 0.1372
10644075 | 2. korrus | 410 | 0.0671 | 0.002296 | 0.1342
10644078 | 2. korrus | 601.251 | 0.095117 | 0.00334197 | 0.190234
10644079 | 2. korrus | 601.251 | 0.095117 | 0.00334197 | 0.190234
10644124 | 2. korrus | 373.202 | 0.0487593 | 0.0016023 | 0.0919187
10644125 | 2. korrus | 740 | 0.1166 | 0.004144 | 0.2276
10644126 | 2. korrus | 556.564 | 0.0766269 | 0.00264686 | 0.147654
10644127 | 2. korrus | 740 | 0.1166 | 0.004144 | 0.2276
10644128 | 2. korrus | 686.341 | 0.0963349 | 0.00338539 | 0.18707
10644129 | 2. korrus | 740 | 0.1166 | 0.004144 | 0.2276
10644130 | 2. korrus | 766.437 | 0.108492 | 0.0038409 | 0.211385
10644131 | 2. korrus | 740 | 0.1166 | 0.004144 | 0.2276
10644132 | 2. korrus | 766.437 | 0.108492 | 0.0038409 | 0.211385
10644133 | 2. korrus | 740 | 0.1166 | 0.004144 | 0.2276
10644134 | 2. korrus | 686.341 | 0.0963349 | 0.00338539 | 0.18707
10644135 | 2. korrus | 740 | 0.1166 | 0.004144 | 0.2276
10644136 | 2. korrus | 556.564 | 0.0766269 | 0.00264686 | 0.147654
10644137 | 2. korrus | 740 | 0.1166 | 0.004144 | 0.2276
10644138 | 2. korrus | 373.202 | 0.0487593 | 0.0016023 | 0.0919187
10644139 | 2. korrus | 740 | 0.1166 | 0.004144 | 0.2276
10644154 | 2. korrus | 506.562 | 0.0810193 | 0.00281565 | 0.162039
10644155 | 2. korrus | 516.766 | 0.0825386 | 0.00287237 | 0.165077
10644156 | 2. korrus | 532.779 | 0.0849226 | 0.00296138 | 0.169845
10644157 | 2. korrus | 556.258 | 0.0867182 | 0.00302361 | 0.173436
10644158 | 2. korrus | 506.562 | 0.0810193 | 0.00281565 | 0.162039
10644159 | 2. korrus | 516.766 | 0.0825386 | 0.00287237 | 0.165077
10644160 | 2. korrus | 532.779 | 0.0849226 | 0.00296138 | 0.169845
10644161 | 2. korrus | 556.258 | 0.0867182 | 0.00302361 | 0.173436
10644162 | 2. korrus | 410 | 0.0671 | 0.002296 | 0.1342
10644163 | 2. korrus | 420 | 0.0686 | 0.002352 | 0.1372
10644164 | 2. korrus | 420 | 0.0686 | 0.002352 | 0.1372
10644165 | 2. korrus | 420 | 0.0686 | 0.002352 | 0.1372
10644166 | 2. korrus | 420 | 0.0686 | 0.002352 | 0.1372
10644167 | 2. korrus | 420 | 0.0686 | 0.002352 | 0.1372
10644168 | 2. korrus | 420 | 0.0686 | 0.002352 | 0.1372
10644169 | 2. korrus | 410 | 0.0671 | 0.002296 | 0.1342
10644172 | 2. korrus | 601.251 | 0.095117 | 0.00334197 | 0.190234
10644173 | 2. korrus | 601.251 | 0.095117 | 0.00334197 | 0.190234
10644218 | 2. korrus | 373.202 | 0.0487593 | 0.0016023 | 0.0919187
10644219 | 2. korrus | 740 | 0.1166 | 0.004144 | 0.2276
10644220 | 2. korrus | 556.564 | 0.0766269 | 0.00264686 | 0.147654
10644221 | 2. korrus | 740 | 0.1166 | 0.004144 | 0.2276
10644222 | 2. korrus | 686.341 | 0.0963349 | 0.00338539 | 0.18707
10644223 | 2. korrus | 740 | 0.1166 | 0.004144 | 0.2276
10644224 | 2. korrus | 766.437 | 0.108492 | 0.0038409 | 0.211385
10644225 | 2. korrus | 740 | 0.1166 | 0.004144 | 0.2276
10644226 | 2. korrus | 766.437 | 0.108492 | 0.0038409 | 0.211385
10644227 | 2. korrus | 740 | 0.1166 | 0.004144 | 0.2276
10644228 | 2. korrus | 686.341 | 0.0963349 | 0.00338539 | 0.18707
10644229 | 2. korrus | 740 | 0.1166 | 0.004144 | 0.2276
10644230 | 2. korrus | 556.564 | 0.0766269 | 0.00264686 | 0.147654
10644231 | 2. korrus | 740 | 0.1166 | 0.004144 | 0.2276
10644232 | 2. korrus | 373.202 | 0.0487593 | 0.0016023 | 0.0919187
10644233 | 2. korrus | 740 | 0.1166 | 0.004144 | 0.2276
10644248 | 2. korrus | 506.562 | 0.0810193 | 0.00281565 | 0.162039
10644249 | 2. korrus | 516.766 | 0.0825386 | 0.00287237 | 0.165077
10644250 | 2. korrus | 532.779 | 0.0849226 | 0.00296138 | 0.169845
10644251 | 2. korrus | 556.258 | 0.0867182 | 0.00302361 | 0.173436
10644252 | 2. korrus | 506.562 | 0.0810193 | 0.00281565 | 0.162039
10644253 | 2. korrus | 516.766 | 0.0825386 | 0.00287237 | 0.165077
10644254 | 2. korrus | 532.779 | 0.0849226 | 0.00296138 | 0.169845
10644255 | 2. korrus | 556.258 | 0.0867182 | 0.00302361 | 0.173436
10644256 | 2. korrus | 410 | 0.0671 | 0.002296 | 0.1342
10644257 | 2. korrus | 420 | 0.0686 | 0.002352 | 0.1372
10644258 | 2. korrus | 420 | 0.0686 | 0.002352 | 0.1372
10644259 | 2. korrus | 420 | 0.0686 | 0.002352 | 0.1372
10644260 | 2. korrus | 420 | 0.0686 | 0.002352 | 0.1372
10644261 | 2. korrus | 420 | 0.0686 | 0.002352 | 0.1372
10644262 | 2. korrus | 420 | 0.0686 | 0.002352 | 0.1372
10644263 | 2. korrus | 410 | 0.0671 | 0.002296 | 0.1342
10644266 | 2. korrus | 601.251 | 0.095117 | 0.00334197 | 0.190234
10644267 | 2. korrus | 601.251 | 0.095117 | 0.00334197 | 0.190234
10644312 | 2. korrus | 373.202 | 0.0487593 | 0.0016023 | 0.0919187
10644313 | 2. korrus | 740 | 0.1166 | 0.004144 | 0.2276
10644314 | 2. korrus | 556.564 | 0.0766269 | 0.00264686 | 0.147654
10644315 | 2. korrus | 740 | 0.1166 | 0.004144 | 0.2276
10644316 | 2. korrus | 686.341 | 0.0963349 | 0.00338539 | 0.18707
10644317 | 2. korrus | 740 | 0.1166 | 0.004144 | 0.2276
10644318 | 2. korrus | 766.437 | 0.108492 | 0.0038409 | 0.211385
10644319 | 2. korrus | 740 | 0.1166 | 0.004144 | 0.2276
10644320 | 2. korrus | 766.437 | 0.108492 | 0.0038409 | 0.211385
10644321 | 2. korrus | 740 | 0.1166 | 0.004144 | 0.2276
10644322 | 2. korrus | 686.341 | 0.0963349 | 0.00338539 | 0.18707
10644323 | 2. korrus | 740 | 0.1166 | 0.004144 | 0.2276
10644324 | 2. korrus | 556.564 | 0.0766269 | 0.00264686 | 0.147654
10644325 | 2. korrus | 740 | 0.1166 | 0.004144 | 0.2276
10644326 | 2. korrus | 373.202 | 0.0487593 | 0.0016023 | 0.0919187
10644327 | 2. korrus | 740 | 0.1166 | 0.004144 | 0.2276
10644342 | 2. korrus | 506.562 | 0.0810193 | 0.00281565 | 0.162039
10644343 | 2. korrus | 516.766 | 0.0825386 | 0.00287237 | 0.165077
10644344 | 2. korrus | 532.779 | 0.0849226 | 0.00296138 | 0.169845
10644345 | 2. korrus | 556.258 | 0.0867182 | 0.00302361 | 0.173436
10644346 | 2. korrus | 506.562 | 0.0810193 | 0.00281565 | 0.162039
10644347 | 2. korrus | 516.766 | 0.0825386 | 0.00287237 | 0.165077
10644348 | 2. korrus | 532.779 | 0.0849226 | 0.00296138 | 0.169845
10644349 | 2. korrus | 556.258 | 0.0867182 | 0.00302361 | 0.173436
10644350 | 2. korrus | 410 | 0.0671 | 0.002296 | 0.1342
10644351 | 2. korrus | 420 | 0.0686 | 0.002352 | 0.1372
10644352 | 2. korrus | 420 | 0.0686 | 0.002352 | 0.1372
10644353 | 2. korrus | 420 | 0.0686 | 0.002352 | 0.1372
10644354 | 2. korrus | 420 | 0.0686 | 0.002352 | 0.1372
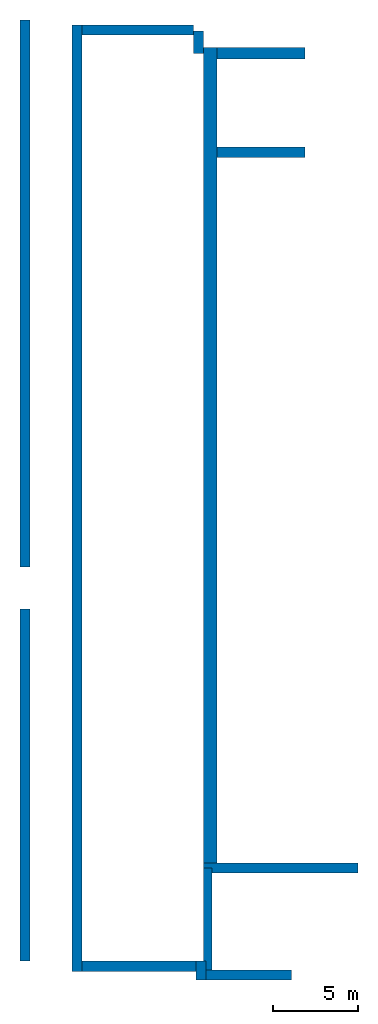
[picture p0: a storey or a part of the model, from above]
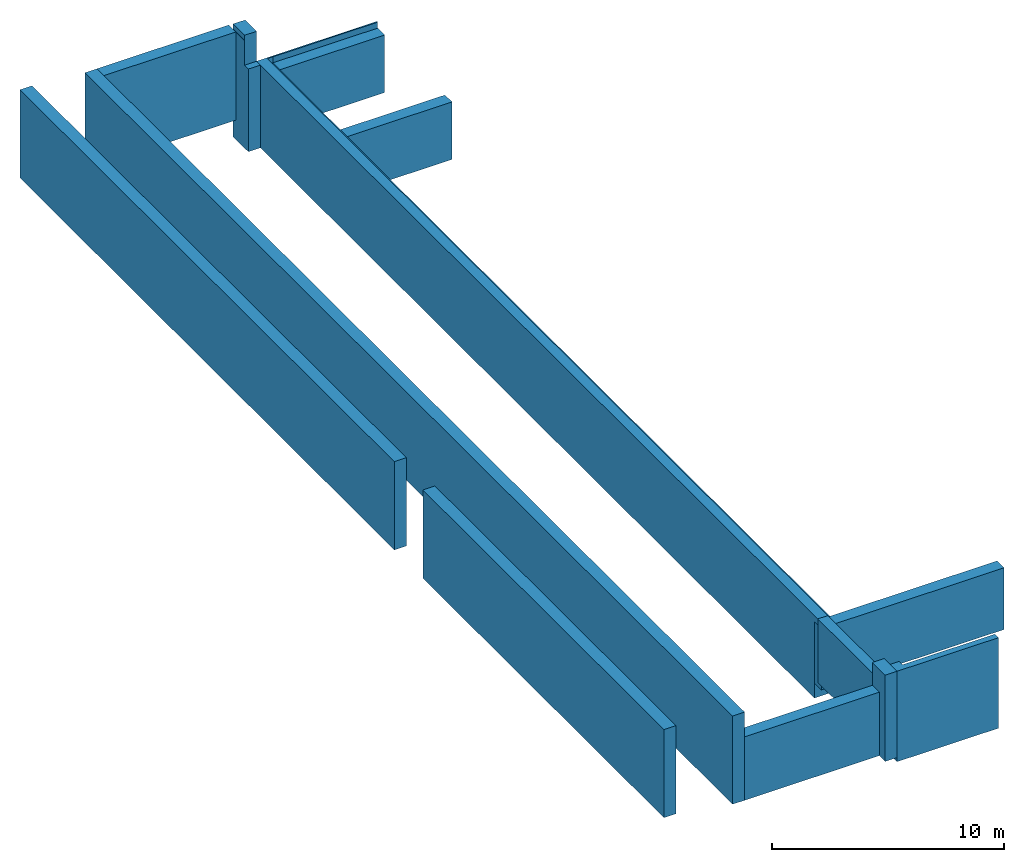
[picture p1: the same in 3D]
Properties of the parts of a building model (IFC2X3), part 5 of 7

# IfcMember: Rectangular Mullion:NEW 80x70mm (576)
Name (Rectangular Mullion:NEW 80x70mm:...) | In | Span (mm) = Length (mm) | CrossSectionArea (m2) | NetVolume (m3) | NetSurfaceArea (m2)
10644355 | 2. korrus | 420 | 0.0686 | 0.002352 | 0.1372
10644356 | 2. korrus | 420 | 0.0686 | 0.002352 | 0.1372
10644357 | 2. korrus | 410 | 0.0671 | 0.002296 | 0.1342
10644360 | 2. korrus | 601.251 | 0.095117 | 0.00334197 | 0.190234
10644361 | 2. korrus | 601.251 | 0.095117 | 0.00334197 | 0.190234
10644406 | 2. korrus | 373.202 | 0.0487593 | 0.0016023 | 0.0919187
10644407 | 2. korrus | 740 | 0.1166 | 0.004144 | 0.2276
10644408 | 2. korrus | 556.564 | 0.0766269 | 0.00264686 | 0.147654
10644409 | 2. korrus | 740 | 0.1166 | 0.004144 | 0.2276
10644410 | 2. korrus | 686.341 | 0.0963349 | 0.00338539 | 0.18707
10644411 | 2. korrus | 740 | 0.1166 | 0.004144 | 0.2276
10644412 | 2. korrus | 766.437 | 0.108492 | 0.0038409 | 0.211385
10644413 | 2. korrus | 740 | 0.1166 | 0.004144 | 0.2276
10644414 | 2. korrus | 766.437 | 0.108492 | 0.0038409 | 0.211385
10644415 | 2. korrus | 740 | 0.1166 | 0.004144 | 0.2276
10644416 | 2. korrus | 686.341 | 0.0963349 | 0.00338539 | 0.18707
10644417 | 2. korrus | 740 | 0.1166 | 0.004144 | 0.2276
10644418 | 2. korrus | 556.564 | 0.0766269 | 0.00264686 | 0.147654
10644419 | 2. korrus | 740 | 0.1166 | 0.004144 | 0.2276
10644420 | 2. korrus | 373.202 | 0.0487593 | 0.0016023 | 0.0919187
10644421 | 2. korrus | 740 | 0.1166 | 0.004144 | 0.2276
10644436 | 2. korrus | 506.562 | 0.0810193 | 0.00281565 | 0.162039
10644437 | 2. korrus | 516.766 | 0.0825386 | 0.00287237 | 0.165077
10644438 | 2. korrus | 532.779 | 0.0849226 | 0.00296138 | 0.169845
10644439 | 2. korrus | 556.258 | 0.0867182 | 0.00302361 | 0.173436
10644440 | 2. korrus | 506.562 | 0.0810193 | 0.00281565 | 0.162039
10644441 | 2. korrus | 516.766 | 0.0825386 | 0.00287237 | 0.165077
10644442 | 2. korrus | 532.779 | 0.0849226 | 0.00296138 | 0.169845
10644443 | 2. korrus | 556.258 | 0.0867182 | 0.00302361 | 0.173436
10644444 | 2. korrus | 410 | 0.0671 | 0.002296 | 0.1342
10644445 | 2. korrus | 420 | 0.0686 | 0.002352 | 0.1372
10644446 | 2. korrus | 420 | 0.0686 | 0.002352 | 0.1372
10644447 | 2. korrus | 420 | 0.0686 | 0.002352 | 0.1372
10644448 | 2. korrus | 420 | 0.0686 | 0.002352 | 0.1372
10644449 | 2. korrus | 420 | 0.0686 | 0.002352 | 0.1372
10644450 | 2. korrus | 420 | 0.0686 | 0.002352 | 0.1372
10644451 | 2. korrus | 410 | 0.0671 | 0.002296 | 0.1342
10644454 | 2. korrus | 601.251 | 0.095117 | 0.00334197 | 0.190234
10644455 | 2. korrus | 601.251 | 0.095117 | 0.00334197 | 0.190234
10644500 | 2. korrus | 373.202 | 0.0487593 | 0.0016023 | 0.0919187
10644501 | 2. korrus | 740 | 0.1166 | 0.004144 | 0.2276
10644502 | 2. korrus | 556.564 | 0.0766269 | 0.00264686 | 0.147654
10644503 | 2. korrus | 740 | 0.1166 | 0.004144 | 0.2276
10644504 | 2. korrus | 686.341 | 0.0963349 | 0.00338539 | 0.18707
10644505 | 2. korrus | 740 | 0.1166 | 0.004144 | 0.2276
10644506 | 2. korrus | 766.437 | 0.108492 | 0.0038409 | 0.211385
10644507 | 2. korrus | 740 | 0.1166 | 0.004144 | 0.2276
10644508 | 2. korrus | 766.437 | 0.108492 | 0.0038409 | 0.211385
10644509 | 2. korrus | 740 | 0.1166 | 0.004144 | 0.2276
10644510 | 2. korrus | 686.341 | 0.0963349 | 0.00338539 | 0.18707
10644511 | 2. korrus | 740 | 0.1166 | 0.004144 | 0.2276
10644512 | 2. korrus | 556.564 | 0.0766269 | 0.00264686 | 0.147654
10644513 | 2. korrus | 740 | 0.1166 | 0.004144 | 0.2276
10644514 | 2. korrus | 373.202 | 0.0487593 | 0.0016023 | 0.0919187
10644515 | 2. korrus | 740 | 0.1166 | 0.004144 | 0.2276
10644530 | 2. korrus | 506.562 | 0.0810193 | 0.00281565 | 0.162039
10644531 | 2. korrus | 516.766 | 0.0825386 | 0.00287237 | 0.165077
10644532 | 2. korrus | 532.779 | 0.0849226 | 0.00296138 | 0.169845
10644533 | 2. korrus | 556.258 | 0.0867182 | 0.00302361 | 0.173436
10644534 | 2. korrus | 506.562 | 0.0810193 | 0.00281565 | 0.162039
10644535 | 2. korrus | 516.766 | 0.0825386 | 0.00287237 | 0.165077
10644536 | 2. korrus | 532.779 | 0.0849226 | 0.00296138 | 0.169845
10644537 | 2. korrus | 556.258 | 0.0867182 | 0.00302361 | 0.173436
10644538 | 2. korrus | 410 | 0.0671 | 0.002296 | 0.1342
10644539 | 2. korrus | 420 | 0.0686 | 0.002352 | 0.1372
10644540 | 2. korrus | 420 | 0.0686 | 0.002352 | 0.1372
10644541 | 2. korrus | 420 | 0.0686 | 0.002352 | 0.1372
10644542 | 2. korrus | 420 | 0.0686 | 0.002352 | 0.1372
10644543 | 2. korrus | 420 | 0.0686 | 0.002352 | 0.1372
10644544 | 2. korrus | 420 | 0.0686 | 0.002352 | 0.1372
10644545 | 2. korrus | 410 | 0.0671 | 0.002296 | 0.1342
10644548 | 2. korrus | 601.251 | 0.095117 | 0.00334197 | 0.190234
10644549 | 2. korrus | 601.251 | 0.095117 | 0.00334197 | 0.190234

# IfcMember: Rectangular Mullion:Schüco vert. mullion, cover cap 45mm, profiil 150mm (2)
In: 3. korrus
Type - PredefinedType: MULLION; Material: LUMION_dark steel window frames
Type - Pset_MemberCommon - IsExternal: no
Pset_MemberCommon - Reference: Schüco vert. mullion, cover cap 45mm, profiil 150mm; Span: 1240 mm
Pset_QuantityTakeOff - Reference: Schüco vert. mullion, cover cap 45mm, profiil 150mm
BaseQuantities - Length: 1240 mm; CrossSectionArea: 0.729894 m2; NetVolume: 0.00403521 m3; NetSurfaceArea: 1.45979 m2
Name (Rectangular Mullion:Schüco vert. mullion, cover cap 45mm, profiil 150mm:...)
11548295 | Pset_MemberCommon - IsExternal: yes
11561255

# IfcOpeningElement: Opening (318)
Name | In | Depth (mm) | Height (mm) | Width (mm) | Pset_OpeningElementCommon, Reference | sets with these values
2 x Basic Wall:ol. olev - 780mm:783042 | 1. korrus | 3048 | 2150 | 1550 | ol. olev ava - 1550x2150 | 2
3 x Basic Wall:ol. olev - 780mm:788035 | 1. korrus | 1084.8 |  |  | Ak-02 | 2 | BaseQuantities - Area: 9.3035 m2
Basic Wall:ol. olev - 780mm:788035 | 1. korrus | 3048 |  |  | 5220x1660 | 2 | BaseQuantities - Area: 11.1334 m2
Basic Wall:ol. olev - 590mm:788125 | 1. korrus | 3048 |  |  | 5220x1390 | 2 | BaseQuantities - Area: 17.9572 m2
Basic Wall:ol. olev - 590mm:788125 | 1. korrus |  |  |  | 2220x1950x350 | 2
Basic Wall:ol. olev - 590mm:788125 | 1. korrus | 3048 |  |  | ol. olev MKU-22 - 2220x1950, EI-15 | 2 | BaseQuantities - Area: 3.06601 m2
2 x Basic Wall:ol. olev - 590mm:788125 | 1. korrus | 3048 | 1950 | 457.2 | ol. olev MKU-22 - 2220x1950, EI-15 | 2
9 x Basic Wall:ol. olev - 780mm:824131 | 1. korrus | 1084.8 |  |  | ol. olev klaassein_väljas | 2 | BaseQuantities - Area: 11.3811 m2
7 x Basic Wall:ol. olev - 780mm:770923 | 1. korrus |  | 290 | 5200 | ol. olev - 780mm | 2
Basic Wall:ol. olev - 780mm:770923 | 1. korrus |  | 290 | 5810 | ol. olev - 780mm | 2
Basic Wall:ol. olev - 780mm:770923 | 1. korrus |  | 5600 | 290 | ol. olev - 780mm | 2
Basic Wall:ol. olev - 600mm:824342 | 1. korrus | 1300 | 2970 | 400 | ol. olev ava - 1300x2970 | 2
Basic Wall:ol. olev - 600mm:824342 | 1. korrus | 1130 | 1950 | 400 | ol. olev ava - 1130x1950 | 2
3 x Basic Wall:ol. olev - 780mm:829503 | 1. korrus | 1084.8 |  |  | Ak-02 | 2 | BaseQuantities - Area: 9.3035 m2
Basic Wall:ol. olev - 780mm:830562 | 1. korrus | 3048 |  |  | 5220x1660 | 2 | BaseQuantities - Area: 11.1334 m2
Floor:ol. olev - 320mm:2985918 | 1. korrus |  |  |  | ol. olev - 320mm | 2 | BaseQuantities - Area: 101.222 m2
Floor:ol. olev - 320mm:2985918 | 1. korrus |  |  |  | ol. olev - 320mm | 2 | BaseQuantities - Area: 45.2277 m2
Floor:ol. olev - 320mm:2985918 | 1. korrus |  |  |  | ol. olev - 320mm | 2 | BaseQuantities - Area: 175.872 m2
Floor:ol. olev - 320mm:2985918 | 1. korrus |  |  |  | ol. olev - 320mm | 2 | BaseQuantities - Area: 5.03771 m2
Basic Wall:ol. olev - 780mm:835863 | 2. korrus | 3048 |  |  | 5220x1660 | 2 | BaseQuantities - Area: 11.1334 m2
Basic Wall:ol. olev - 780mm:835863 | 2. korrus |  |  |  | 5220x2360 | 2
3 x Basic Wall:ol. olev - 740mm:835864 | 2. korrus | 1044.8 |  |  | Ak-04 | 2 | BaseQuantities - Area: 7.18941 m2
3 x Basic Wall:ol. olev - 740mm:835864 | 2. korrus | 1044.8 |  |  | ol. olev klaassein_väljas | 2 | BaseQuantities - Area: 7.18941 m2
Basic Wall:ol. olev - 780mm:835868 | 2. korrus | 3048 |  |  | 5220x1660 | 2 | BaseQuantities - Area: 11.1334 m2
Basic Wall:ol. olev - 720mm:835869 | 2. korrus | 1024.8 |  |  | ol. olev klaassein_väljas | 2 | BaseQuantities - Area: 7.18941 m2
Basic Wall:ol. olev - 720mm:835869 | 2. korrus | 1024.8 |  |  | Ak-04 | 2 | BaseQuantities - Area: 7.18941 m2
3 x Basic Wall:ol. olev - 780mm:835871 | 2. korrus | 1084.8 |  |  | Ak-04 | 2 | BaseQuantities - Area: 7.18941 m2
3 x Basic Wall:ol. olev - 780mm:835871 | 2. korrus | 1084.8 |  |  | ol. olev klaassein_väljas | 2 | BaseQuantities - Area: 7.18941 m2
Floor:ol. olev - 320mm:2985918 | 2. korrus |  |  |  | ol. olev - 320mm | 2 | BaseQuantities - Area: 812.12 m2
Floor:ol. olev - 320mm:2985918 | 2. korrus |  |  |  | ol. olev - 320mm | 2 | BaseQuantities - Area: 44.9752 m2
Floor:ol. olev - 320mm:2985918 | 2. korrus |  | 2800 | 5910 | ol. olev - 320mm | 2
Floor:ol. olev - 320mm:2985918 | 2. korrus |  | 2750 | 5600 | ol. olev - 320mm | 2
Floor:ol. olev - 320mm:2985918 | 2. korrus |  | 840 | 540 | ol. olev - 320mm | 2
Floor:ol. olev - 320mm:2985918 | 2. korrus |  | 1280 | 1590 | ol. olev - 320mm | 2
Floor:ol. olev - 320mm:2985918 | 2. korrus |  |  |  | ol. olev - 320mm | 2 | BaseQuantities - Area: 16.5586 m2
Floor:ol. olev - 320mm:2985918 | 2. korrus |  |  |  | ol. olev - 320mm | 2 | BaseQuantities - Area: 4.99499 m2
Basic Wall:ol. olev - 590mm:861627 | 2. korrus | 3048 |  |  | ol. olev MKU-22 - 2220x1950, EI-15 | 2 | BaseQuantities - Area: 3.06601 m2
2 x Basic Wall:ol. olev - 590mm:861627 | 2. korrus | 3048 | 1950 | 457.2 | ol. olev MKU-22 - 2220x1950, EI-15 | 2
Basic Wall:ol. olev - 360mm:866172 | 3. korrus |  |  |  | ol. olev - 360mm | 2 | BaseQuantities - Area: 13.2548 m2
Basic Wall:ol. olev - 330mm:869698 | 3. korrus | 800 | 2100 | 200 | ol. olev MKU-15 - 800x2100 | Pset_OpeningElementCommon - FireExit: no; Pset_QuantityTakeOff - Reference: ol. olev MKU-15 - 800x2100
Floor:ol. olev - 300mm:2411640 | 3. korrus |  | 1365 | 5490.89 | ol. olev - 300mm | 2
Floor:ol. olev - 300mm:2411640 | 3. korrus |  | 5490.89 | 1480 | ol. olev - 300mm | 2
Floor:ol. olev - 300mm:2411640 | 3. korrus |  |  |  | ol. olev - 300mm | 2 | BaseQuantities - Area: 44.5868 m2
Floor:ol. olev - 300mm:2411640 | 3. korrus |  |  |  | ol. olev - 300mm | 2 | BaseQuantities - Area: 28.7553 m2
Floor:ol. olev - 300mm:2411640 | 3. korrus |  |  |  | ol. olev - 300mm | 2 | BaseQuantities - Area: 4.96052 m2
Basic Wall:ol. olev - 360mm:866172 | 4. korrus |  |  |  | ol. olev - 360mm | 2 | BaseQuantities - Area: 0.221531 m2
Basic Wall:ol. olev - 360mm:866172 | 4. korrus |  |  |  | ol. olev - 360mm | 2 | BaseQuantities - Area: 0.549534 m2
Basic Wall:ol. olev - 360mm:866172 | 4. korrus |  |  |  | ol. olev - 360mm | 2 | BaseQuantities - Area: 0.0288947 m2
Floor:ol. olev - 300mm:2411640 | 4. korrus |  |  |  | ol. olev - 300mm | 2 | BaseQuantities - Area: 45.2106 m2
Floor:ol. olev - 300mm:2411640 | 4. korrus |  |  |  | ol. olev - 300mm | 2 | BaseQuantities - Area: 28.4525 m2
Floor:ol. olev - 300mm:2411640 | 4. korrus |  | 5170 | 5190 | ol. olev - 300mm | 2
Floor:ol. olev - 300mm:2411640 | 4. korrus |  |  |  | ol. olev - 300mm | 2 | BaseQuantities - Area: 4.96052 m2
2 x Basic Wall:ol. olev - 590mm:1010136 | -1. korrus | 894.8 |  |  | ol. olev MK vent. rest | 2 | BaseQuantities - Area: 2.88944 m2
Basic Wall:ol. olev - 780mm:1010563 | -1. korrus |  |  |  | 5220x1660 | 2
Basic Wall:ol. olev - 780mm:1010563 | -1. korrus | 1084.8 |  |  | ol. olev klaassein_väljas | 2 | BaseQuantities - Area: 11.3811 m2
Basic Wall:ol. olev - 780mm:1010563 | -1. korrus | 1084.8 | 2550 | 5200 | ol. olev klaassein_sees | 2
Basic Wall:ol. olev - 670mm:1034850:1 | -2. korrus |  |  |  | ol. olev - 670mm | 2
Basic Wall:ol. olev - 460mm:892978 | 3. korrus |  |  |  | ol. olev - 460mm | 2 | BaseQuantities - Area: 11.7104 m2
2 x Basic Wall:ol. olev - 640mm:2254197 | 2. korrus | 3048 |  |  | VU-63_1200x2100 (kaar 400mm) | BaseQuantities - Area: 2.86685 m2; Pset_OpeningElementCommon - FireExit: no; Pset_QuantityTakeOff - Reference: VU-63_1200x2100 (kaar 400mm)
Basic Wall:ol. olev - 640mm:2254197 | 2. korrus | 3048 |  |  | ol. olev - 850x2100+390 | BaseQuantities - Area: 2.03965 m2; Pset_OpeningElementCommon - FireExit: yes; Pset_QuantityTakeOff - Reference: ol. olev - 850x2100+390
Basic Wall:ol. olev - 640mm:2254197 | 2. korrus | 800 | 2100 | 150 | SU-00 - 800x2100 | Pset_OpeningElementCommon - FireExit: no; Pset_QuantityTakeOff - Reference: SU-00 - 800x2100
Basic Wall:ol. olev - 640mm:770735 | 2. korrus |  |  |  | ol. olev - 640mm | 2 | BaseQuantities - Area: 0.529432 m2
Basic Wall:ol. olev - 640mm:770735 | 2. korrus |  |  |  | ol. olev - 640mm | 2 | BaseQuantities - Area: 2.28894 m2
Basic Wall:ol. olev - 780mm:2353352 | 1. korrus | 1084.8 |  |  | ol. olev klaassein_väljas | 2 | BaseQuantities - Area: 11.3811 m2
Basic Wall:ol. olev - 780mm:2353352 | 1. korrus |  |  |  | 5220x1660 | 2
Basic Wall:ol. olev - 780mm:2353352 | 1. korrus | 1084.8 | 2550 | 5200 | ol. olev klaassein_sees | 2
Basic Wall:ol. olev - 580mm:2355101 | 1. korrus | 3048 | 2100 | 1500 | ol. olev ava - 1500x2100 | 2
Basic Wall:ol. olev - 580mm:2355101 | 1. korrus | 900 | 2100 | 120 | ol. olev - 900x2100 | Pset_OpeningElementCommon - FireExit: yes; Pset_QuantityTakeOff - Reference: ol. olev - 900x2100
Floor:ol. olev - 350mm:2395541 | 1. korrus | 1018.73 | 570 | 53180 | F-korpuse kanal | 2
Floor:ol. olev - 350mm:4140251 | 1. korrus |  |  |  | ol. olev - 350mm | 2 | BaseQuantities - Area: 52.7591 m2
Floor:ol. olev - 315mm:2920690 | -1. korrus |  |  |  | ol. olev - 315mm | 2 | BaseQuantities - Area: 45.137 m2
Floor:ol. olev - 315mm:2920690 | -1. korrus |  | 1000 | 1050.18 | ol. olev - 315mm | 2
Floor:ol. olev - 315mm:2920690 | -1. korrus |  | 1100 | 1100 | ol. olev - 315mm | 2
Floor:ol. olev - 315mm:2920690 | -1. korrus |  | 729.795 | 730 | ol. olev - 315mm | 2
Floor:ol. olev - 315mm:2920690 | -1. korrus |  |  |  | ol. olev - 315mm | 2 | BaseQuantities - Area: 4.96052 m2
Basic Wall:ol. olev - 670mm:4555551 | -1. korrus | 974.8 |  |  | ol. olev klaassein_väljas | 2 | BaseQuantities - Area: 11.3811 m2
Basic Wall:ol. olev - 720mm:4556660:1 | 1. korrus |  |  |  | ol. olev - 720mm | 2
Basic Wall:ol. olev - 720mm:4556660 | 1. korrus | 1024.8 |  |  | ol. olev klaassein_väljas | 2 | BaseQuantities - Area: 11.3811 m2
Basic Wall:ol. olev - 720mm:4556660 | 1. korrus | 1300 | 2970 | 400 | ol. olev ava - 1300x2970 | 2
Basic Wall:ol. olev - 720mm:4556660 | 1. korrus | 1130 | 1950 | 400 | ol. olev ava - 1130x1950 | 2
7 x Basic Wall:ol. olev - 780mm, MK:6365457 | E-korpus 2. korrus | 3048 |  |  | 5220x1740 | 2 | BaseQuantities - Area: 11.551 m2
Basic Wall:ol. olev - 530mm:869394 | 3. korrus |  |  |  | ol. olev - 530mm | 2 | BaseQuantities - Area: 13.8685 m2
Basic Wall:ol. olev - 530mm:869394 | 4. korrus |  |  |  | ol. olev - 530mm | 2 | BaseQuantities - Area: 14.4388 m2
Basic Wall:ol. olev - 530mm:869394 | 4. korrus |  |  |  | ol. olev - 530mm | 2 | BaseQuantities - Area: 13.9286 m2
2 x Basic Wall:VS-01 - 165 sooj. mitte läbiv:8165071 | -1. korrus | 469.8 |  |  | ol. olev MK vent. rest | 2 | BaseQuantities - Area: 2.88944 m2
12 x Basic Wall:VS-01 - 165 sooj. mitte läbiv:8165071 | -1. korrus | 3048 | 500 | 500 | A-07_500x500 | 2
Basic Wall:VS-01 - 165 sooj. mitte läbiv:8165071 | -1. korrus | 200 | 3600 | 500 | Seina süvendid teljel 10' | 2
2 x Basic Wall:VS-01 - 165 sooj. mitte läbiv:8165114 | -1. korrus | 469.8 |  |  | ol. olev MK vent. rest | 2 | BaseQuantities - Area: 2.88944 m2
12 x Basic Wall:VS-01 - 165 sooj. mitte läbiv:8165114 | -1. korrus | 3048 | 500 | 500 | A-07_500x500 | 2
Basic Wall:VS-01 - 165 sooj. mitte läbiv:8165114 | -1. korrus | 200 | 3600 | 500 | Seina süvendid teljel 10' | 2
2 x Basic Wall:VS-01 - 165 sooj. mitte läbiv:8165229 | -1. korrus | 469.8 |  |  | ol. olev MK vent. rest | 2 | BaseQuantities - Area: 2.88944 m2
12 x Basic Wall:VS-01 - 165 sooj. mitte läbiv:8165229 | -1. korrus | 3048 | 500 | 500 | A-07_500x500 | 2
Basic Wall:VS-01 - 165 sooj. mitte läbiv:8165229 | -1. korrus | 200 | 3600 | 500 | Seina süvendid teljel 10' | 2
2 x Basic Wall:VS-01 - 165 sooj. mitte läbiv:8165281 | -1. korrus | 469.8 |  |  | ol. olev MK vent. rest | 2 | BaseQuantities - Area: 2.88944 m2
12 x Basic Wall:VS-01 - 165 sooj. mitte läbiv:8165281 | -1. korrus | 3048 | 500 | 500 | A-07_500x500 | 2
Basic Wall:VS-01 - 165 sooj. mitte läbiv:8165281 | -1. korrus | 200 | 3600 | 500 | Seina süvendid teljel 10' | 2
2 x Basic Wall:VS-01 - 165 sooj. mitte läbiv:8165335 | -1. korrus | 469.8 |  |  | ol. olev MK vent. rest | 2 | BaseQuantities - Area: 2.88944 m2
12 x Basic Wall:VS-01 - 165 sooj. mitte läbiv:8165335 | -1. korrus | 3048 | 500 | 500 | A-07_500x500 | 2
Basic Wall:VS-01 - 165 sooj. mitte läbiv:8165335 | -1. korrus | 200 | 3600 | 500 | Seina süvendid teljel 10' | 2
2 x Basic Wall:VS-01 - 165 sooj. mitte läbiv:8165391 | -1. korrus | 469.8 |  |  | ol. olev MK vent. rest | 2 | BaseQuantities - Area: 2.88944 m2
12 x Basic Wall:VS-01 - 165 sooj. mitte läbiv:8165391 | -1. korrus | 3048 | 500 | 500 | A-07_500x500 | 2
Basic Wall:VS-01 - 165 sooj. mitte läbiv:8165391 | -1. korrus | 200 | 3600 | 500 | Seina süvendid teljel 10' | 2
2 x Basic Wall:VS-01 - 165 sooj. mitte läbiv:8165441 | -1. korrus | 469.8 |  |  | ol. olev MK vent. rest | 2 | BaseQuantities - Area: 2.88944 m2
12 x Basic Wall:VS-01 - 165 sooj. mitte läbiv:8165441 | -1. korrus | 3048 | 500 | 500 | A-07_500x500 | 2
Basic Wall:VS-01 - 165 sooj. mitte läbiv:8165441 | -1. korrus | 200 | 3600 | 500 | Seina süvendid teljel 10' | 2
2 x Basic Wall:VS-01 - 165 sooj. mitte läbiv:8165511 | -1. korrus | 469.8 |  |  | ol. olev MK vent. rest | 2 | BaseQuantities - Area: 2.88944 m2
12 x Basic Wall:VS-01 - 165 sooj. mitte läbiv:8165511 | -1. korrus | 3048 | 500 | 500 | A-07_500x500 | 2
Basic Wall:VS-01 - 165 sooj. mitte läbiv:8165511 | -1. korrus | 200 | 3600 | 500 | Seina süvendid teljel 10' | 2
Basic Wall:VS-01 - 165 sooj. mitte läbiv:8166061 | -1. korrus |  |  |  | 5220x1660 | 2
Basic Wall:VS-03.1 - soojustus:8172023 | 1. korrus | 1300 | 2970 | 400 | ol. olev ava - 1300x2970 | 2
Basic Wall:VS-03.1 - soojustus:8172023 | 1. korrus | 1130 | 1950 | 400 | ol. olev ava - 1130x1950 | 2
Basic Wall:VS-01 - 165 sooj. mitte läbiv:8172788 | 1. korrus | 3048 |  |  | 5220x1390 | 2 | BaseQuantities - Area: 17.9572 m2
Basic Wall:VS-01 - 165 sooj. mitte läbiv:8172788 | 1. korrus |  |  |  | 2220x1950x350 | 2
Basic Wall:VS-03.1 - soojustus:8232846 | 3. korrus | 3048 | 2100 | 1380 | ol. olev ava - 1380x2100 | 2
Basic Wall:VS-03.1 - soojustus:8236908 | 4. korrus | 3048 | 900 | 860 | A-05_860x900mm | 2
Basic Wall:VS-22 - 340 akende all:10344990 | 3. korrus | 649.8 | 2300 | 2600 | A-15 | 2
Basic Wall:VS-22 - 340 akende all:8318297 | 3. korrus |  |  |  | VS-22 - 340 akende all | 2 | BaseQuantities - Area: 26.8175 m2
Basic Wall:ol. olev - 160mm:10387094 | 3. korrus | 464.8 | 2300 | 2600 | A-15 | 2
Basic Wall:VS-03.1 - soojustus:10392931 | 3. korrus | 389.3 |  |  | A-18 | 2 | BaseQuantities - Area: 0.955 m2
Basic Wall:VS-03.1 - soojustus:10392931 | 3. korrus | 3048 | 2100 | 1550 | ol. olev ava - 1550x2100 | 2
Basic Wall:VS-03.1 - soojustus:10395262 | 3. korrus | 3048 | 2100 | 1550 | ol. olev ava - 1550x2100 | 2
Basic Wall:VS-03.1 - soojustus:10395262 | 3. korrus | 389.3 |  |  | A-18 | 2 | BaseQuantities - Area: 0.955 m2
3 x Basic Wall:ol. olev - 780mm:10471659 | 1. korrus | 3048 |  |  | 5220x1705 | 2 | BaseQuantities - Area: 11.3683 m2
Basic Wall:ol. olev - 780mm:10471665 | 1. korrus | 3048 |  |  | 5220x1660 | 2 | BaseQuantities - Area: 11.1334 m2
Basic Wall:ol. olev - 530mm:869394 | 4. korrus |  |  |  | ol. olev - 530mm | 2 | BaseQuantities - Area: 13.334 m2
Basic Roof:TV-01 plaat 1 (tume):10916931:1 | E-korpus 2. korrus | 20 |  |  | TV-01 plaat 1 (tume) | 2 | BaseQuantities - Area: 346.551 m2
Basic Roof:TV-01 plaat 1 (tume):10916931:2 | E-korpus 2. korrus | 20 |  |  | TV-01 plaat 1 (tume) | 2 | BaseQuantities - Area: 346.551 m2
Basic Roof:TV-01 plaat 1 (tume):10916931:3 | E-korpus 2. korrus | 20 |  |  | TV-01 plaat 1 (tume) | 2 | BaseQuantities - Area: 346.551 m2
Basic Roof:TV-01 plaat 1 (tume):10916931:4 | E-korpus 2. korrus | 20 |  |  | TV-01 plaat 1 (tume) | 2 | BaseQuantities - Area: 346.551 m2
Basic Roof:TV-01 plaat 1 (tume):10916931:5 | E-korpus 2. korrus | 20 |  |  | TV-01 plaat 1 (tume) | 2 | BaseQuantities - Area: 346.551 m2
Basic Roof:TV-01 plaat 1 (tume):10916931:6 | E-korpus 2. korrus | 20 |  |  | TV-01 plaat 1 (tume) | 2 | BaseQuantities - Area: 346.551 m2
Basic Roof:TV-01 plaat 1 (tume):10916931:7 | E-korpus 2. korrus | 20 |  |  | TV-01 plaat 1 (tume) | 2 | BaseQuantities - Area: 346.551 m2
Floor:ol. olev - 450mm:2920876 | 1. korrus |  | 1987.44 | 2115 | ol. olev - 450mm | 2
Floor:ol. olev - 450mm:2920876 | 1. korrus |  | 5600 | 1375 | ol. olev - 450mm | 2
Floor:ol. olev - 450mm:2920876 | 1. korrus |  |  |  | ol. olev - 450mm | 2 | BaseQuantities - Area: 7.76975 m2
Basic Wall:ol. olev - 780mm:11608330 | 1. korrus | 1084.8 |  |  | ol. olev klaassein_väljas | 2 | BaseQuantities - Area: 11.3811 m2
Basic Wall:ol. olev - 780mm:11608330 | 1. korrus | 1084.8 | 2550 | 5200 | ol. olev klaassein_sees | 2
Basic Wall:SS-71 - 150 poorbetoon acoustic:4267480 | 1. korrus |  | 840 | 4730 | SS-71 - 150 poorbetoon acoustic | 2
Basic Wall:SS-71 - 150 poorbetoon acoustic:4267480 | 1. korrus |  | 390 | 840 | SS-71 - 150 poorbetoon acoustic | 2
Basic Wall:ol. olev - 640mm:17121057 | E-korpus 2. korrus | 3048 |  |  | VU-63_1200x2100 (kaar 400mm) | BaseQuantities - Area: 2.86685 m2; Pset_OpeningElementCommon - FireExit: yes; Pset_QuantityTakeOff - Reference: VU-63_1200x2100 (kaar 400mm)
Basic Wall:ol. olev - 640mm:17121057 | E-korpus 2. korrus | 3048 |  |  | VU-63_1200x2100 (kaar 400mm) | BaseQuantities - Area: 2.86685 m2; Pset_OpeningElementCommon - FireExit: no; Pset_QuantityTakeOff - Reference: VU-63_1200x2100 (kaar 400mm)
Basic Wall:ol. olev - 640mm:17121057 | E-korpus 2. korrus | 1320 | 2400 | 150 | ol. olev MKU-24 - 1320x2230mm | 2
Basic Wall:ol. olev - 640mm:17121057 | E-korpus 2. korrus | 800 | 2100 | 150 | SU-00 - 800x2100 | Pset_OpeningElementCommon - FireExit: no; Pset_QuantityTakeOff - Reference: SU-00 - 800x2100
SMA_D01, 1-poolne:uus puituks - 750x2250 lävepakuta:2242801:1 | 1. korrus | 250 | 2250 | 750
SMA_D01, 1-poolne:ol. olev MKU-15 - 800x2100:1383072:1 | 3. korrus | 200 | 2100 | 800
SMA_D02, 2-poolne:ol. olev - 630x1020:1759973:1 | 3. korrus | 300 | 1020 | 630
SMA_W1, 1-jaotus:A-07_500x500:9564196:1 | -1. korrus | 590 | 500 | 500
SMA_W1, 1-jaotus:A-07_500x500:9564197:1 | -1. korrus | 590 | 500 | 500
SMA_W1, 1-jaotus:A-07_500x500:9564198:1 | -1. korrus | 590 | 500 | 500
SMA_W1, 1-jaotus:A-07_500x500:9564199:1 | -1. korrus | 590 | 500 | 500
SMA_W1, 1-jaotus:A-07_500x500:9564200:1 | -1. korrus | 590 | 500 | 500
SMA_W1, 1-jaotus:A-07_500x500:9564201:1 | -1. korrus | 590 | 500 | 500
SMA_W1, 1-jaotus:A-07_500x500:9564206:1 | -1. korrus | 590 | 500 | 500
SMA_W1, 1-jaotus:A-07_500x500:9564205:1 | -1. korrus | 590 | 500 | 500
SMA_W1, 1-jaotus:A-07_500x500:9564204:1 | -1. korrus | 590 | 500 | 500
SMA_W1, 1-jaotus:A-07_500x500:9564203:1 | -1. korrus | 590 | 500 | 500
SMA_W1, 1-jaotus:A-07_500x500:9564202:1 | -1. korrus | 590 | 500 | 500
12 x Basic Wall:ol. olev - 590mm:1010136 | -1. korrus | 3048 | 500 | 500
SMA_W1, 1-jaotus:A-07_500x500:9564220:1 | -1. korrus | 590 | 500 | 500
SMA_D02, 2-poolne:SU-00 - 1500x2100:10952802:1 | 1. korrus | 580 | 2100 | 1500
SMA_D01, 1-poolne, kaar klaasiga:VU-63_1200x2100 (kaar 400mm):5600994:1 | E-korpus 2. korrus | 640 | BaseQuantities - Area: 2.86685 m2
SMA_D01, 1-poolne:SU-00 - puituks 800x2100 ventil. lävepakuga:8981842:1 | -1. korrus | 100 | 2100 | 800
SMA_D01, 1-poolne:SU-00 - 800x2100:8981867:1 | -1. korrus | 100 | 800 | 2100
Basic Wall:SS-70 - 100 poorbetoon:8981571 | -1. korrus | 3048 | 2100 | 800
SMA_D01, 1-poolne:SU-00 - 1000x2100 lävepakuta:9543578:1 | 1. korrus | 150 | 1000 | 2100
SMA_D01, 1-poolne:HLU-03 - 600x800mm:13043182:1 | -1. korrus | 300 | 600 | 800
SMA_D02, 2-poolne:2000x2400mm EI30 laskuv lävep. 2:13278779:1 | 1. korrus | 150 | 2400 | 2000
SMA_D01, 1-poolne:uus puituks - 700x2100 lävepakuta 2:15366973:1 | 1. korrus | 100 | 700 | 2100
SMA_D01, 1-poolne:uus puituks - 700x2100 lävepakuta 2:15367203:1 | 1. korrus | 100 | 700 | 2100
SMA_hooldusluuk:hooldusluuk 600x600mm TTK:16627925:1 | 1. korrus | 150 | 600 | 600
Basic Wall:SS-71 - 150 poorbetoon acoustic:16590092 | 1. korrus | 3048 | 600 | 600
Basic Wall:ol. olev - 640mm:17121057 | E-korpus 2. korrus | 3048 | BaseQuantities - Area: 2.03965 m2

# IfcOpeningElement: Recess (20)
Pset_OpeningElementCommon - sets with these values: 2
Name | In | Depth (mm) | Height (mm) | Width (mm) | Reference
Basic Wall:ol. olev - 780mm:788035 | 1. korrus | 200 | 3600 | 500 | Seina süvendid teljel 10'
Basic Wall:ol. olev - 780mm:788035 | 1. korrus | 130 | 320 | 5200 | uus void 3
Basic Wall:ol. olev - 780mm:824131 | 1. korrus | 570 | 1018.73 | 53180 | F-korpuse kanal
Basic Wall:ol. olev - 780mm:829503 | 1. korrus | 200 | 3600 | 500 | Seina süvendid teljel 10'
Basic Wall:ol. olev - 780mm:829503 | 1. korrus | 140 | 330 | 5200 | uus void 4
Basic Wall:ol. olev - 740mm:835864 | 2. korrus | 120 | 800 | 5200 | woidtelg10prim
Basic Wall:ol. olev - 780mm:835871 | 2. korrus | 120 | 800 | 5200 | Walls 1
Basic Wall:ol. olev - 600mm:836024 | 2. korrus | 100 | 3300 | 30 | TempVuuk 30x100mm
Basic Wall:ol. olev - 400mm:865091 | 3. korrus | 100 | 1239.41 | 30 | TempVuuk 30x100mm
Floor:ol. olev - 300mm:879121 | 3. korrus | 430 | 5200 | 300 | void 3k 6 N-P
Basic Wall:ol. olev - 590mm:1010136 | -1. korrus | 200 | 3600 | 500 | Seina süvendid teljel 10'
Basic Wall:ol. olev - 600mm:2336539 | E-korpus 2. korrus | 325.202 | 372.597 | 270 | Type 1
Basic Wall:ol. olev - 600mm:2336539 | E-korpus 2. korrus |  |  |  | 5220x1740
Basic Wall:ol. olev - 580mm:2355101 | 1. korrus |  |  |  | 5220x1660
Basic Wall:ol. olev - 580mm:2355101 | 1. korrus | 250 | 980 | 860 | ol. olev VK - 900x1020
Basic Wall:ol. olev - 600mm:2386300 | E-korpus 2. korrus | 100 | 1370 | 30 | TempVuuk 30x100mm
2 x Basic Wall:ol. olev - 670mm:4555551 | -1. korrus | 100 | 3300 | 30 | TempVuuk 30x100mm
Basic Wall:ol. olev - 720mm:4556660 | 1. korrus | 100 | 1930 | 30 | TempVuuk 30x100mm
Basic Wall:ol. olev - 640mm:17121057 | E-korpus 2. korrus | 270 | 372.597 | 325.202 | Type 1

# IfcPlate: System Panel:Peegelaknad 6-16-4-16-4, paneel (11)
In: 1. korrus
Type - PredefinedType: CURTAIN_PANEL; Material: <Unnamed>
Type - Pset_PlateCommon - IsExternal: no
Pset_PlateCommon - Reference: Peegelaknad 6-16-4-16-4, paneel
Pset_QuantityTakeOff - Reference: Peegelaknad 6-16-4-16-4, paneel
Name (System Panel:Peegelaknad 6-16-4-16-4, paneel:...)
10533025
10533130
10533238
10533346
10533454
10533562
10533670
10533778
10533886
10533994
10534102

# IfcPlate: System Panel:Peegelaknad 6-16-4-16-4, paneel (297)
Type - PredefinedType: CURTAIN_PANEL; Material: EST. Klaas. 3x. Default
Type - Pset_PlateCommon - IsExternal: no
Pset_PlateCommon - Reference: Peegelaknad 6-16-4-16-4, paneel
Pset_QuantityTakeOff - Reference: Peegelaknad 6-16-4-16-4, paneel
Name (System Panel:Peegelaknad 6-16-4-16-4, paneel:...) | In | NetVolume (m3)
10323826 | 2. korrus | 0.005846
10385965 | 3. korrus | 0.00715635
10386004 | 3. korrus | 0.0168925
10386008 | 3. korrus | 0.0126731
10386026 | 3. korrus | 0.00715635
10389265 | 3. korrus | 0.0168925
10389351 | 3. korrus | 0.0168925
10389366 | 3. korrus | 0.0168925
10389370 | 3. korrus | 0.0168925
10389385 | 3. korrus | 0.0168925
10389389 | 3. korrus | 0.0168925
10389438 | 3. korrus | 0.0168925
10389442 | 3. korrus | 0.0168925
10389457 | 3. korrus | 0.0168925
10389461 | 3. korrus | 0.0168925
10389476 | 3. korrus | 0.0168925
10389480 | 3. korrus | 0.0168925
10389495 | 3. korrus | 0.0168925
10389499 | 3. korrus | 0.0126731
10515218 | 1. korrus | 0.00531996
10515247 | 1. korrus | 0.0044275
10515243 | 1. korrus | 0.004715
10515233 | 1. korrus | 0.004715
10515239 | 1. korrus | 0.0044275
10515235 | 1. korrus | 0.00531996
10515252 | 1. korrus | 0.00128
10515253 | 1. korrus | 0.00175043
10515254 | 1. korrus | 0.00217651
10515255 | 1. korrus | 0.0025325
10515256 | 1. korrus | 0.0025325
10515257 | 1. korrus | 0.00217651
10515258 | 1. korrus | 0.00175043
10515259 | 1. korrus | 0.00128
10522643 | 1. korrus | 0.00531996
10522672 | 1. korrus | 0.0044275
10522668 | 1. korrus | 0.004715
10522658 | 1. korrus | 0.004715
10522664 | 1. korrus | 0.0044275
10522660 | 1. korrus | 0.00531996
10522677 | 1. korrus | 0.00128
10522678 | 1. korrus | 0.00175043
10522679 | 1. korrus | 0.00217651
10522680 | 1. korrus | 0.0025325
10522681 | 1. korrus | 0.0025325
10522682 | 1. korrus | 0.00217651
10522683 | 1. korrus | 0.00175043
10522684 | 1. korrus | 0.00128
10522800 | 1. korrus | 0.00531996
10522829 | 1. korrus | 0.0044275
10522825 | 1. korrus | 0.004715
10522815 | 1. korrus | 0.004715
10522821 | 1. korrus | 0.0044275
10522817 | 1. korrus | 0.00531996
10522834 | 1. korrus | 0.00128
10522835 | 1. korrus | 0.00175043
10522836 | 1. korrus | 0.00217651
10522837 | 1. korrus | 0.0025325
10522838 | 1. korrus | 0.0025325
10522839 | 1. korrus | 0.00217651
10522840 | 1. korrus | 0.00175043
10522841 | 1. korrus | 0.00128
10522950 | 1. korrus | 0.00531996
10522979 | 1. korrus | 0.0044275
10522975 | 1. korrus | 0.004715
10522965 | 1. korrus | 0.004715
10522971 | 1. korrus | 0.0044275
10522967 | 1. korrus | 0.00531996
10522984 | 1. korrus | 0.00128
10522985 | 1. korrus | 0.00175043
10522986 | 1. korrus | 0.00217651
10522987 | 1. korrus | 0.0025325
10522988 | 1. korrus | 0.0025325
10522989 | 1. korrus | 0.00217651
10522990 | 1. korrus | 0.00175043
10522991 | 1. korrus | 0.00128
10523116 | 1. korrus | 0.00531996
10523145 | 1. korrus | 0.0044275
10523141 | 1. korrus | 0.004715
10523131 | 1. korrus | 0.004715
10523137 | 1. korrus | 0.0044275
10523133 | 1. korrus | 0.00531996
10523150 | 1. korrus | 0.00128
10523151 | 1. korrus | 0.00175043
10523152 | 1. korrus | 0.00217651
10523153 | 1. korrus | 0.0025325
10523154 | 1. korrus | 0.0025325
10523155 | 1. korrus | 0.00217651
10523156 | 1. korrus | 0.00175043
10523157 | 1. korrus | 0.00128
10523266 | 1. korrus | 0.00531996
10523295 | 1. korrus | 0.0044275
10523291 | 1. korrus | 0.004715
10523281 | 1. korrus | 0.004715
10523287 | 1. korrus | 0.0044275
10523283 | 1. korrus | 0.00531996
10523300 | 1. korrus | 0.00128
10523301 | 1. korrus | 0.00175043
10523302 | 1. korrus | 0.00217651
10523303 | 1. korrus | 0.0025325
10523304 | 1. korrus | 0.0025325
10523305 | 1. korrus | 0.00217651
10523306 | 1. korrus | 0.00175043
10523307 | 1. korrus | 0.00128
10532953 | 1. korrus | 0.0042525
10532949 | 1. korrus | 0.0042525
10532963 | 1. korrus | 0.00501895
10532964 | 1. korrus | 0.00645445
10532965 | 1. korrus | 0.00716677
10532966 | 1. korrus | 0.0070032
10532968 | 1. korrus | 0.0070032
10532969 | 1. korrus | 0.00716677
10532970 | 1. korrus | 0.00645445
10532971 | 1. korrus | 0.00501895
10533061 | 1. korrus | 0.0042525
10533057 | 1. korrus | 0.0042525
10533071 | 1. korrus | 0.00501895
10533072 | 1. korrus | 0.00645445
10533073 | 1. korrus | 0.00716677
10533074 | 1. korrus | 0.0070032
10533076 | 1. korrus | 0.0070032
10533077 | 1. korrus | 0.00716677
10533078 | 1. korrus | 0.00645445
10533079 | 1. korrus | 0.00501895
10533169 | 1. korrus | 0.0042525
10533165 | 1. korrus | 0.0042525
10533179 | 1. korrus | 0.00501895
10533180 | 1. korrus | 0.00645445
10533181 | 1. korrus | 0.00716677
10533182 | 1. korrus | 0.0070032
10533184 | 1. korrus | 0.0070032
10533185 | 1. korrus | 0.00716677
10533186 | 1. korrus | 0.00645445
10533187 | 1. korrus | 0.00501895
10533277 | 1. korrus | 0.0042525
10533273 | 1. korrus | 0.0042525
10533287 | 1. korrus | 0.00501895
10533288 | 1. korrus | 0.00645445
10533289 | 1. korrus | 0.00716677
10533290 | 1. korrus | 0.0070032
10533292 | 1. korrus | 0.0070032
10533293 | 1. korrus | 0.00716677
10533294 | 1. korrus | 0.00645445
10533295 | 1. korrus | 0.00501895
10533385 | 1. korrus | 0.0042525
10533381 | 1. korrus | 0.0042525
10533395 | 1. korrus | 0.00501895
10533396 | 1. korrus | 0.00645445
10533397 | 1. korrus | 0.00716677
10533398 | 1. korrus | 0.0070032
10533400 | 1. korrus | 0.0070032
10533401 | 1. korrus | 0.00716677
10533402 | 1. korrus | 0.00645445
10533403 | 1. korrus | 0.00501895
10533493 | 1. korrus | 0.0042525
10533489 | 1. korrus | 0.0042525
10533503 | 1. korrus | 0.00501895
10533504 | 1. korrus | 0.00645445
10533505 | 1. korrus | 0.00716677
10533506 | 1. korrus | 0.0070032
10533508 | 1. korrus | 0.0070032
10533509 | 1. korrus | 0.00716677
10533510 | 1. korrus | 0.00645445
10533511 | 1. korrus | 0.00501895
10533601 | 1. korrus | 0.0042525
10533597 | 1. korrus | 0.0042525
10533611 | 1. korrus | 0.00501895
10533612 | 1. korrus | 0.00645445
10533613 | 1. korrus | 0.00716677
10533614 | 1. korrus | 0.0070032
10533616 | 1. korrus | 0.0070032
10533617 | 1. korrus | 0.00716677
10533618 | 1. korrus | 0.00645445
10533619 | 1. korrus | 0.00501895
10533709 | 1. korrus | 0.0042525
10533705 | 1. korrus | 0.0042525
10533719 | 1. korrus | 0.00501895
10533720 | 1. korrus | 0.00645445
10533721 | 1. korrus | 0.00716677
10533722 | 1. korrus | 0.0070032
10533724 | 1. korrus | 0.0070032
10533725 | 1. korrus | 0.00716677
10533726 | 1. korrus | 0.00645445
10533727 | 1. korrus | 0.00501895
10533817 | 1. korrus | 0.0042525
10533813 | 1. korrus | 0.0042525
10533827 | 1. korrus | 0.00501895
10533828 | 1. korrus | 0.00645445
10533829 | 1. korrus | 0.00716677
10533830 | 1. korrus | 0.0070032
10533832 | 1. korrus | 0.0070032
10533833 | 1. korrus | 0.00716677
10533834 | 1. korrus | 0.00645445
10533835 | 1. korrus | 0.00501895
10533925 | 1. korrus | 0.0042525
10533921 | 1. korrus | 0.0042525
10533935 | 1. korrus | 0.00501895
10533936 | 1. korrus | 0.00645445
10533937 | 1. korrus | 0.00716677
10533938 | 1. korrus | 0.0070032
10533940 | 1. korrus | 0.0070032
10533941 | 1. korrus | 0.00716677
10533942 | 1. korrus | 0.00645445
10533943 | 1. korrus | 0.00501895
10534033 | 1. korrus | 0.0042525
10534029 | 1. korrus | 0.0042525
10534043 | 1. korrus | 0.00501895
10534044 | 1. korrus | 0.00645445
10534045 | 1. korrus | 0.00716677
10534046 | 1. korrus | 0.0070032
10534048 | 1. korrus | 0.0070032
10534049 | 1. korrus | 0.00716677
10534050 | 1. korrus | 0.00645445
10534051 | 1. korrus | 0.00501895
10643987 | 2. korrus | 0.00365477
10644022 | 2. korrus | 0.00294
10644028 | 2. korrus | 0.00287
10644004 | 2. korrus | 0.00287
10644013 | 2. korrus | 0.00294
10644007 | 2. korrus | 0.00365477
10644020 | 2. korrus | 0.00144874
10644023 | 2. korrus | 0.00211529
10644026 | 2. korrus | 0.00256179
10644029 | 2. korrus | 0.00273374
10644005 | 2. korrus | 0.00273374
10644017 | 2. korrus | 0.00256179
10644014 | 2. korrus | 0.00211529
10644011 | 2. korrus | 0.00144874
10644081 | 2. korrus | 0.00365477
10644116 | 2. korrus | 0.00294
10644122 | 2. korrus | 0.00287
10644098 | 2. korrus | 0.00287
10644107 | 2. korrus | 0.00294
10644101 | 2. korrus | 0.00365477
10644114 | 2. korrus | 0.00144874
10644117 | 2. korrus | 0.00211529
10644120 | 2. korrus | 0.00256179
10644123 | 2. korrus | 0.00273374
10644099 | 2. korrus | 0.00273374
10644111 | 2. korrus | 0.00256179
10644108 | 2. korrus | 0.00211529
10644105 | 2. korrus | 0.00144874
10644175 | 2. korrus | 0.00365477
10644210 | 2. korrus | 0.00294
10644216 | 2. korrus | 0.00287
10644192 | 2. korrus | 0.00287
10644201 | 2. korrus | 0.00294
10644195 | 2. korrus | 0.00365477
10644208 | 2. korrus | 0.00144874
10644211 | 2. korrus | 0.00211529
10644214 | 2. korrus | 0.00256179
10644217 | 2. korrus | 0.00273374
10644193 | 2. korrus | 0.00273374
10644205 | 2. korrus | 0.00256179
10644202 | 2. korrus | 0.00211529
10644199 | 2. korrus | 0.00144874
10644269 | 2. korrus | 0.00365477
10644304 | 2. korrus | 0.00294
10644310 | 2. korrus | 0.00287
10644286 | 2. korrus | 0.00287
10644295 | 2. korrus | 0.00294
10644289 | 2. korrus | 0.00365477
10644302 | 2. korrus | 0.00144874
10644305 | 2. korrus | 0.00211529
10644308 | 2. korrus | 0.00256179
10644311 | 2. korrus | 0.00273374
10644287 | 2. korrus | 0.00273374
10644299 | 2. korrus | 0.00256179
10644296 | 2. korrus | 0.00211529
10644293 | 2. korrus | 0.00144874
10644363 | 2. korrus | 0.00365477
10644398 | 2. korrus | 0.00294
10644404 | 2. korrus | 0.00287
10644380 | 2. korrus | 0.00287
10644389 | 2. korrus | 0.00294
10644383 | 2. korrus | 0.00365477
10644396 | 2. korrus | 0.00144874
10644399 | 2. korrus | 0.00211529
10644402 | 2. korrus | 0.00256179
10644405 | 2. korrus | 0.00273374
10644381 | 2. korrus | 0.00273374
10644393 | 2. korrus | 0.00256179
10644390 | 2. korrus | 0.00211529
10644387 | 2. korrus | 0.00144874
10644457 | 2. korrus | 0.00365477
10644492 | 2. korrus | 0.00294
10644498 | 2. korrus | 0.00287
10644474 | 2. korrus | 0.00287
10644483 | 2. korrus | 0.00294
10644477 | 2. korrus | 0.00365477
10644490 | 2. korrus | 0.00144874
10644493 | 2. korrus | 0.00211529
10644496 | 2. korrus | 0.00256179
10644499 | 2. korrus | 0.00273374
10644475 | 2. korrus | 0.00273374
10644487 | 2. korrus | 0.00256179
10644484 | 2. korrus | 0.00211529
10644481 | 2. korrus | 0.00144874

# IfcPlate: System Panel:Solid (58)
In: 1. korrus
Type - PredefinedType: CURTAIN_PANEL; Material: LUMION_dark steel window frames
Type - Pset_PlateCommon - IsExternal: no; ThermalTransmittance: 3.7021 kg/K/s3
Pset_PlateCommon - Reference: Solid
Pset_QuantityTakeOff - Reference: Solid
Name (System Panel:Solid:...) | NetVolume (m3)
4455517 | 0.0022 | Pset_PlateCommon - IsExternal: yes
4455718 | 0.0022 | Pset_PlateCommon - IsExternal: yes
4455720 | 0.0022 | Pset_PlateCommon - IsExternal: yes
4455722 | 0.0022 | Pset_PlateCommon - IsExternal: yes
4455724 | 0.0022 | Pset_PlateCommon - IsExternal: yes
4455726 | 0.0022 | Pset_PlateCommon - IsExternal: yes
4455728 | 0.0022 | Pset_PlateCommon - IsExternal: yes
4455730 | 0.0022 | Pset_PlateCommon - IsExternal: yes
4455732 | 0.0022 | Pset_PlateCommon - IsExternal: yes
4455734 | 0.0022 | Pset_PlateCommon - IsExternal: yes
4455736 | 0.0022 | Pset_PlateCommon - IsExternal: yes
4455738 | 0.0022 | Pset_PlateCommon - IsExternal: yes
4455740 | 0.0022 | Pset_PlateCommon - IsExternal: yes
4455742 | 0.0022 | Pset_PlateCommon - IsExternal: yes
4455744 | 0.0022 | Pset_PlateCommon - IsExternal: yes
4455746 | 0.0022 | Pset_PlateCommon - IsExternal: yes
4455748 | 0.0022 | Pset_PlateCommon - IsExternal: yes
4455750 | 0.0022 | Pset_PlateCommon - IsExternal: yes
4455752 | 0.0022 | Pset_PlateCommon - IsExternal: yes
4455754 | 0.0022 | Pset_PlateCommon - IsExternal: yes
4455756 | 0.0022 | Pset_PlateCommon - IsExternal: yes
4455758 | 0.00220967 | Pset_PlateCommon - IsExternal: yes
4455760 | 0.0020813 | Pset_PlateCommon - IsExternal: yes
4455762 | 0.00193066 | Pset_PlateCommon - IsExternal: yes
4455764 | 0.00176162 | Pset_PlateCommon - IsExternal: yes
4455766 | 0.00156834 | Pset_PlateCommon - IsExternal: yes
4455768 | 0.00134064 | Pset_PlateCommon - IsExternal: yes
4455770 | 0.00105813 | Pset_PlateCommon - IsExternal: yes
4455772 | 0.000728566 | Pset_PlateCommon - IsExternal: yes
4455567 | 0.0022
4455611 | 0.0022
4455613 | 0.0022
4455615 | 0.0022
4455617 | 0.0022
4455619 | 0.0022
4455621 | 0.0022
4455623 | 0.0022
4455625 | 0.0022
4455627 | 0.0022
4455629 | 0.0022
4455631 | 0.0022
4455633 | 0.0022
4455635 | 0.0022
4455637 | 0.0022
4455645 | 0.0022
4455647 | 0.0022
4455649 | 0.0022
4455651 | 0.0022
4455653 | 0.0022
4455655 | 0.0022
4455657 | 0.00220967
4455659 | 0.0020813
4455661 | 0.00193066
4455663 | 0.00176162
4455665 | 0.00156834
4455667 | 0.00134064
4455669 | 0.00105813
4455671 | 0.000728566

# IfcPlate: System Panel:VLS Klaas KAR/LAM 6+1+6 (64)
Type - PredefinedType: CURTAIN_PANEL; Material: EST. Klaas. 1x. E-korpus
Type - Pset_PlateCommon - IsExternal: no
Pset_PlateCommon - Reference: VLS Klaas KAR/LAM 6+1+6
Pset_QuantityTakeOff - Reference: VLS Klaas KAR/LAM 6+1+6
Name (System Panel:VLS Klaas KAR/LAM 6+1+6:...) | In | NetVolume (m3)
2388850 | 1. korrus | 0.0296608
7887682 | 1. korrus | 0.0311558
7887684 | 1. korrus | 0.0187174
2388859 | 1. korrus | 0.0610234
7887694 | 1. korrus | 0.0850082
2388973 | 1. korrus | 0.030498
7887700 | 1. korrus | 0.031993
7887702 | 1. korrus | 0.0222755
3977817 | 1. korrus | 0.0277659
7887742 | 1. korrus | 0.0292609
7887744 | 1. korrus | 0.0337188
7887752 | 1. korrus | 0.024945
7887754 | 1. korrus | 0.0306582
7887756 | 1. korrus | 0.0291632
13282656 | 1. korrus | 0.0243984
13285758 | 1. korrus | 0.0258934
13285858 | 1. korrus | 0.0244582
6869784 | 1. korrus | 0.0184782
6869786 | 1. korrus | 0.0262373
6869788 | 1. korrus | 0.0276575
6869805 | 1. korrus | 0.0276575
6869790 | 1. korrus | 0.0262373
6869792 | 1. korrus | 0.0254898
6965721 | 2. korrus | 0.032591
6965723 | 2. korrus | 0.034086
6965725 | 2. korrus | 0.034086
6965763 | 2. korrus | 0.034086
6965765 | 2. korrus | 0.00383717
10329046 | 2. korrus | 0.0287538
10323831 | 2. korrus | 0.0155131
10323833 | 2. korrus | 0.0240197
10323835 | 2. korrus | 0.0225247
10323845 | 2. korrus | 0.023621
10323847 | 2. korrus | 0.025116
10323849 | 2. korrus | 0.023778
10323859 | 2. korrus | 0.0238453
10323861 | 2. korrus | 0.0323518
10323863 | 2. korrus | 0.0323518
10323865 | 2. korrus | 0.0323518
10323867 | 2. korrus | 0.0308568
10323883 | 2. korrus | 0.0159118
10323885 | 2. korrus | 0.0244183
10323887 | 2. korrus | 0.0229233
10323897 | 2. korrus | 0.0244183
10323899 | 2. korrus | 0.0259133
10323901 | 2. korrus | 0.0244183
13277709 | 1. korrus | 0.0386425
13278702 | 1. korrus | 0.007995
13284497 | 1. korrus | 0.0237854
13285291 | 1. korrus | 0.032292
13285347 | 1. korrus | 0.032292
13285446 | 1. korrus | 0.032292
13285561 | 1. korrus | 0.030797
13321293 | 1. korrus | 0.0293917
13321299 | 1. korrus | 0.0308867
13321303 | 1. korrus | 0.0308867
13321307 | 1. korrus | 0.0308867
13321311 | 1. korrus | 0.0308867
13321367 | 1. korrus | 0.029601
13918884 | 1. korrus | 0.0243835
13919169 | 1. korrus | 0.02392
13919124 | 1. korrus | 0.013754
13918991 | 1. korrus | 0.01196
13919310 | 1. korrus | 0.02691

# IfcRailing: MK piire, katusepõhine 1:Railing Roof Based (22)
In: E-korpus 2. korrus
Type - Material: LUMION_facade concrete
Type - Pset_RailingCommon - IsExternal: no
Pset_QuantityTakeOff - Reference: Railing Roof Based
Pset_RailingCommon - Reference: Railing Roof Based
AR - 002_Elemendi_staadium: Projekteeritud
Name (MK piire, katusepõhine 1:Railing Roof Based:...)
5539019 | Pset_RailingCommon - IsExternal: yes
5546940
5547031
5547319
5547584
5547760
5547952
5548185
5548239
5548303
5548371
5548451
5548511
5548807
5548867
5548921
5549056
5549108
5549162
5549305
5551038
5551162

# IfcRailing: MK piire, katusepõhine 4:PR-03 - Piirde element väljas, tumm (19)
In: E-korpus 2. korrus
Type - Material: LUMION_facade concrete
Type - Pset_RailingCommon - IsExternal: no
Pset_QuantityTakeOff - Reference: PR-03 - Piirde element väljas, tumm
Pset_RailingCommon - Reference: PR-03 - Piirde element väljas, tumm
AR - 002_Elemendi_staadium: Projekteeritud
Name (MK piire, katusepõhine 4:PR-03 - Piirde element väljas, tumm:...)
5542139 | Pset_RailingCommon - IsExternal: yes
5547124
5547320
5547585
5547761
5547953
5549396
5549480
5549540
5549598
5549656
5549716
5549784
5549842
5550244
5550472
5550530
5550596
5550656

# IfcRailing: PR3 mütsi moodul:PR3.1 - laius 790mm, pikkus1100mm (6)
Type - Material: LUMION_facade concrete
Type - Pset_RailingCommon - IsExternal: no
Pset_QuantityTakeOff - Reference: PR3.1 - laius 790mm, pikkus1100mm
Pset_RailingCommon - Reference: PR3.1 - laius 790mm, pikkus1100mm
AR - 002_Elemendi_staadium: Projekteeritud; 455_Eriomadused: PR3 mütsid
Name (PR3 mütsi moodul:PR3.1 - laius 790mm, pikkus1100mm:...) | In
14205273 | 1. korrus
14205274 | 1. korrus
14205277 | 1. korrus
14205278 | 1. korrus
14207168 | E-korpus 2. korrus
14208258 | E-korpus 2. korrus

# IfcRailing: PR3 mütsi moodul:PR3.2 - laius 790mm, pikkus1500mm (40)
Type - Material: LUMION_facade concrete
Type - Pset_RailingCommon - IsExternal: no
Pset_QuantityTakeOff - Reference: PR3.2 - laius 790mm, pikkus1500mm
Pset_RailingCommon - Reference: PR3.2 - laius 790mm, pikkus1500mm
AR - 002_Elemendi_staadium: Projekteeritud; 455_Eriomadused: PR3 mütsid
Name (PR3 mütsi moodul:PR3.2 - laius 790mm, pikkus1500mm:...) | In
14205275 | 1. korrus
14205276 | 1. korrus
14205279 | 1. korrus
14205280 | 1. korrus
14207196 | E-korpus 2. korrus
14207237 | E-korpus 2. korrus
14207636 | E-korpus 2. korrus
14207640 | E-korpus 2. korrus
14207648 | E-korpus 2. korrus
14207750 | E-korpus 2. korrus
14207763 | E-korpus 2. korrus
14207766 | E-korpus 2. korrus
14207769 | E-korpus 2. korrus
14207772 | E-korpus 2. korrus
14207775 | E-korpus 2. korrus
14207778 | E-korpus 2. korrus
14207781 | E-korpus 2. korrus
14207784 | E-korpus 2. korrus
14207787 | E-korpus 2. korrus
14207790 | E-korpus 2. korrus
14207793 | E-korpus 2. korrus
14207796 | E-korpus 2. korrus
14207799 | E-korpus 2. korrus
14207802 | E-korpus 2. korrus
14207805 | E-korpus 2. korrus
14207808 | E-korpus 2. korrus
14207811 | E-korpus 2. korrus
14207814 | E-korpus 2. korrus
14207817 | E-korpus 2. korrus
14207820 | E-korpus 2. korrus
14207823 | E-korpus 2. korrus
14207826 | E-korpus 2. korrus
14207829 | E-korpus 2. korrus
14207832 | E-korpus 2. korrus
14207835 | E-korpus 2. korrus
14207838 | E-korpus 2. korrus
14207841 | E-korpus 2. korrus
14207844 | E-korpus 2. korrus
14207847 | E-korpus 2. korrus
14207850 | E-korpus 2. korrus

# IfcRailing: PR3 mütsi moodul_Nurk 90:PR3.1N - laius 790mm, pikkus1100mm (3)
In: E-korpus 2. korrus
Type - Material: LUMION_facade concrete
Type - Pset_RailingCommon - IsExternal: no
Pset_QuantityTakeOff - Reference: PR3.1N - laius 790mm, pikkus1100mm
Pset_RailingCommon - Reference: PR3.1N - laius 790mm, pikkus1100mm
AR - 002_Elemendi_staadium: Projekteeritud; 455_Eriomadused: PR3 mütsid
Name (PR3 mütsi moodul_Nurk 90:PR3.1N - laius 790mm, pikkus1100mm:...)
14207862
14212974
14213091

# IfcRailing: Piirde element väljas 1, kõrge:PR-03 - Piirde element väljas (4)
In: 1. korrus
Type - Material: LUMION_facade concrete
Type - Pset_RailingCommon - IsExternal: no
Pset_QuantityTakeOff - Reference: PR-03 - Piirde element väljas
Pset_RailingCommon - Reference: PR-03 - Piirde element väljas
AR - 002_Elemendi_staadium: Olemasolev; 455_Eriomadused: vt. sisearhitektuuri projekti
Name (Piirde element väljas 1, kõrge:PR-03 - Piirde element väljas:...)
3795195
3797848
3798312
3798313

# IfcRailing: Piirde element väljas 1_post, kõrge:PR-03 - Piirde element väljas_vahepost, kõrge (2)
In: 1. korrus
Type - Material: LUMION_facade concrete
Type - Pset_RailingCommon - IsExternal: no
Pset_QuantityTakeOff - Reference: PR-03 - Piirde element väljas_vahepost, kõrge
Pset_RailingCommon - Reference: PR-03 - Piirde element väljas_vahepost, kõrge
AR - 002_Elemendi_staadium: Olemasolev; 455_Eriomadused: vt. sisearhitektuuri projekti
Name (Piirde element väljas 1_post, kõrge:PR-03 - Piirde element väljas_vahepost, kõrge:...)
3797927
3798314

# IfcRailing: Piirde element, nurgapost 2:Piirde element, nurgapost, Piirde element, nurgapost 2:Piirde element, nurgapost:3788420
In: E-korpus 2. korrus
Type - Material: LUMION_facade concrete
Type - Pset_RailingCommon - IsExternal: no
Pset_QuantityTakeOff - Reference: Piirde element, nurgapost
Pset_RailingCommon - Reference: Piirde element, nurgapost
AR - 002_Elemendi_staadium: Olemasolev

# IfcRailing: Piirde element, nurgapost:Piirde element, nurgapost, Piirde element, nurgapost:Piirde element, nurgapost:3785942
In: E-korpus 2. korrus
Type - Material: LUMION_facade concrete
Type - Pset_RailingCommon - IsExternal: no
Pset_QuantityTakeOff - Reference: Piirde element, nurgapost
Pset_RailingCommon - Reference: Piirde element, nurgapost
AR - 002_Elemendi_staadium: Olemasolev

# IfcRailing: Railing:KP-01 - Klaaspiire, 1200mm, c/c 4m, Railing:KP-01 - Klaaspiire, 1200mm, c/c 4m:8700165
In: 3. korrus
Type - Pset_RailingCommon - IsExternal: yes
Material: EST. Klaas. 1x. Default, EST. Metall. Alumiinium. Värvitud. RAL8022
Pset_QuantityTakeOff - Reference: KP-01 - Klaaspiire, 1200mm, c/c 4m
Pset_RailingCommon - Reference: KP-01 - Klaaspiire, 1200mm, c/c 4m; Height: 1219.2 mm
AR - 002_Elemendi_staadium: Projekteeritud; 130_Pikkus: 53220
BaseQuantities - Length: 53220 mm

# IfcRailing: Railing:KP-02 - Klaaspiire, 1000mm, c/c 4m, Railing:KP-02 - Klaaspiire, 1000mm, c/c 4m:8701801
In: 4. korrus
Type - Pset_RailingCommon - IsExternal: yes
Material: EST. Klaas. 1x. Default, EST. Metall. Alumiinium. Värvitud. RAL8022
Pset_QuantityTakeOff - Reference: KP-02 - Klaaspiire, 1000mm, c/c 4m
Pset_RailingCommon - Reference: KP-02 - Klaaspiire, 1000mm, c/c 4m; Height: 1000 mm
AR - 002_Elemendi_staadium: Projekteeritud; 130_Pikkus: 39290
BaseQuantities - Length: 39290 mm

# IfcRailing: Railing:ol. olev - horisontaalsed pulgad, 750mm, Railing:ol. olev - horisontaalsed pulgad, 750mm:7204930
In: 3. korrus
Type - Pset_RailingCommon - IsExternal: no
Material: EST. Metall. Teras. RAL9005, ol. olev materjal
Pset_QuantityTakeOff - Reference: ol. olev - horisontaalsed pulgad, 750mm
Pset_RailingCommon - Reference: ol. olev - horisontaalsed pulgad, 750mm; Height: 750 mm
AR - 002_Elemendi_staadium: Olemasolev; 455_Eriomadused: Metallist elemendid puhastada mehaaniliselt. Puhastusaste on Sa 2½. Kui teraselemendi ristlõike pindala kahenemine korrosiooni tõttu on suurem kui 30%, siis antud element tuleb kas asendada või tugevdada. Kruntida korrosioonivastase lahusega, seejärel värvida, värvikate ja paksus vastavalt C3 keskkonna saasteklassile standardi EVS-EN ISO 12944-2 järgi.; 130_Pikkus: 53220
BaseQuantities - Length: 53220 mm

# IfcRailing: Railing:ol. olev - horisontaalsed pulgad, 800mm, Railing:ol. olev - horisontaalsed pulgad, 800mm:7205025
In: 4. korrus
Type - Pset_RailingCommon - IsExternal: no
Material: EST. Metall. Teras. RAL9005, ol. olev materjal
Pset_QuantityTakeOff - Reference: ol. olev - horisontaalsed pulgad, 800mm
Pset_RailingCommon - Reference: ol. olev - horisontaalsed pulgad, 800mm; Height: 800 mm
AR - 002_Elemendi_staadium: Olemasolev; 455_Eriomadused: Metallist elemendid puhastada mehaaniliselt. Puhastusaste on Sa 2½. Kui teraselemendi ristlõike pindala kahenemine korrosiooni tõttu on suurem kui 30%, siis antud element tuleb kas asendada või tugevdada. Kruntida korrosioonivastase lahusega, seejärel vär; 130_Pikkus: 40586
BaseQuantities - Length: 40585.7 mm

# IfcRailing: Railing:ol. olev - vertikaalsed pulgad 750mm (2)
In: 3. korrus
Type - Pset_RailingCommon - IsExternal: no
Material: EST. Metall. Teras. RAL9005
Pset_QuantityTakeOff - Reference: ol. olev - vertikaalsed pulgad 750mm
Pset_RailingCommon - Reference: ol. olev - vertikaalsed pulgad 750mm; Height: 750 mm
AR - 002_Elemendi_staadium: Olemasolev; 455_Eriomadused: Metallist elemendid puhastada mehaaniliselt. Puhastusaste on Sa 2½. Kui teraselemendi ristlõike pindala kahenemine korrosiooni tõttu on suurem kui 30%, siis antud element tuleb kas asendada või tugevdada. Kruntida korrosioonivastase lahusega, seejärel värvida, värvikate ja paksus vastavalt C3 keskkonna saasteklassile standardi EVS-EN ISO 12944-2 järgi.
Name (Railing:ol. olev - vertikaalsed pulgad 750mm:...) | 130_Pikkus | Length (mm)
4086216 | 6723 | 6723.27
13126629 | 6888 | 6887.78

# IfcRoof: Basic Roof:KL-10.10 - mitte-käidav, SBS 2, Basic Roof:KL-10.10 - mitte-käidav, SBS 2:6605312
In: 3. korrus
Material: EST. Rullmaterjal. SBS 5 mm, EST. Soojustus.PIR_Eurothane Silver E 150 mm, EST. Soojustus. EPS 60 Silver 150 mm, EST. Betoon. Kohtvalu. Tasandus 10 mm
Pset_ConcreteElementGeneral - FireRating: R45
Pset_QuantityTakeOff - Reference: KL-10.10 - mitte-käidav, SBS 2
Pset_RoofCommon - IsExternal: yes; Reference: KL-10.10 - mitte-käidav, SBS 2; FireRating: R45; ProjectedArea: 62.5915 m2; TotalArea: 62.6771 m2
AR_Katus - 000_Muinsuskaitse: no; 001_Nimetus: KL-10.10 - mitte-käidav, SBS 2; 003_Elemendi_staadium: Projekteeritud; 205_Tüüp: KL-10.10; 325_Helipidavus: ≥52 dB; 330_Tulekindlus: R45; 340_Soojusläbivus: 0.11; 520_Pindala: 62.6771 m2

# IfcRoof: Basic Roof:KL-10.4 - mitte-käidav, SBS, Basic Roof:KL-10.4 - mitte-käidav, SBS:8714958
In: 3. korrus
Material: EST. Rullmaterjal. SBS 5 mm, EST. Soojustus.PIR_Eurothane Silver E 140 mm, EST. Soojustus. EPS 60 Silver 100 mm
Pset_ConcreteElementGeneral - FireRating: R45
Pset_QuantityTakeOff - Reference: KL-10.4 - mitte-käidav, SBS
Pset_RoofCommon - IsExternal: yes; Reference: KL-10.4 - mitte-käidav, SBS; FireRating: R45; ProjectedArea: 66.1913 m2; TotalArea: 65.4048 m2
AR_Katus - 000_Muinsuskaitse: no; 001_Nimetus: KL-10.4 - mitte-käidav, SBS; 003_Elemendi_staadium: Projekteeritud; 205_Tüüp: KL-10.4; 325_Helipidavus: ≥52 dB ≥52 dB; 330_Tulekindlus: R45; 340_Soojusläbivus: 0.14; 520_Pindala: 65.4048 m2

# IfcRoof: Basic Roof:KL-11 - mitte-käidav, ilma kaldeta, Basic Roof:KL-11 - mitte-käidav, ilma kaldeta:16660699
In: -1. korrus
Material: EST. Rullmaterjal. SBS 5 mm, EST. Soojustus.PIR_Eurothane Silver E 250 mm, EST. Betoon. Kohtvalu. Tasandus 30 mm
Pset_ConcreteElementGeneral - FireRating: R45
Pset_QuantityTakeOff - Reference: KL-11 - mitte-käidav, ilma kaldeta
Pset_RoofCommon - IsExternal: yes; Reference: KL-11 - mitte-käidav, ilma kaldeta; FireRating: R45; ProjectedArea: 4.87297 m2; TotalArea: 4.87297 m2
AR_Katus - 000_Muinsuskaitse: no; 001_Nimetus: KL-11 - mitte-käidav, ilma kaldeta; 003_Elemendi_staadium: Projekteeritud; 205_Tüüp: KL-11; 325_Helipidavus: ≥52 dB; 330_Tulekindlus: R45; 340_Soojusläbivus: 0.09; 520_Pindala: 4.87297 m2

# IfcRoof: Basic Roof:KL-20 - käidav, betoonplaat (5)
Material: EST. Betoon. Kohtvalu 50 mm, EST. Soojustus. EPS 100 kaldekiht, PIR Kingspan Therma TP10 100mm 220 mm
Pset_ConcreteElementGeneral - FireRating: R45
Pset_QuantityTakeOff - Reference: KL-20 - käidav, betoonplaat
Pset_RoofCommon - IsExternal: yes; Reference: KL-20 - käidav, betoonplaat; FireRating: R45
AR_Katus - 000_Muinsuskaitse: no; 001_Nimetus: KL-20 - käidav, betoonplaat; 003_Elemendi_staadium: Projekteeritud; 205_Tüüp: KL-20; 325_Helipidavus: ≥58 dB; 330_Tulekindlus: R45; 340_Soojusläbivus: 0.17
Name (Basic Roof:KL-20 - käidav, betoonplaat:...) | In | ProjectedArea (m2) | TotalArea (m2) = 520_Pindala (m2)
6609129 | 5. korrus | 105.449 | 105.893
6609137 | 4. korrus | 106.163 | 106.818
6609185 | 3. korrus |  | 106.261
6609333 | 3. korrus | 46.98 | 47.0199
6609882 | 3. korrus | 47.0061 | 47.0468

# IfcRoof: Basic Roof:KL-21 - käidav, betoonplaat, Basic Roof:KL-21 - käidav, betoonplaat:5181147
In: E-korpus 2. korrus
Material: EST. Betoon. Kohtvalu 50 mm, EST. Soojustus. EPS 100 kaldekiht, PIR Kingspan Therma TP10 100mm 250 mm
Pset_ConcreteElementGeneral - FireRating: R45
Pset_QuantityTakeOff - Reference: KL-21 - käidav, betoonplaat
Pset_RoofCommon - IsExternal: yes; Reference: KL-21 - käidav, betoonplaat; FireRating: R45; TotalArea: 1140.13 m2
AR_Katus - 000_Muinsuskaitse: no; 001_Nimetus: KL-21 - käidav, betoonplaat; 003_Elemendi_staadium: Projekteeritud; 205_Tüüp: KL-21; 325_Helipidavus: ≥58 dB; 330_Tulekindlus: R45; 340_Soojusläbivus: 0.14; 520_Pindala: 1140.13 m2

# IfcRoof: Basic Roof:KL-22 - lugemissaalide välistrepi alused (4)
Material: EST. Rullmaterjal. SBS 5 mm, EST. Soojustus.PIR_Eurothane Silver E 70 mm, EST. Betoon. Kohtvalu. Tasandus 20 mm
Pset_ConcreteElementGeneral - FireRating: R45
Pset_QuantityTakeOff - Reference: KL-22 - lugemissaalide välistrepi alused
Pset_RoofCommon - IsExternal: yes; Reference: KL-22 - lugemissaalide välistrepi alused; FireRating: R45
AR_Katus - 000_Muinsuskaitse: no; 001_Nimetus: KL-22 - lugemissaalide välistrepi alused; 003_Elemendi_staadium: Projekteeritud; 205_Tüüp: KL-22; 325_Helipidavus: ≥52 dB; 330_Tulekindlus: R45; 340_Soojusläbivus: 0.35
Name (Basic Roof:KL-22 - lugemissaalide välistrepi alused:...) | In | ProjectedArea (m2) | TotalArea (m2) = 520_Pindala (m2)
9524726 | 3. korrus | 6.20918 | 6.98412
9525248 | 3. korrus | 5.88741 | 6.63883
9529037 | 4. korrus | 5.88 | 6.60983
9529457 | 4. korrus | 5.88 | 6.63245

# IfcRoof: Basic Roof:VL-08.1 - käidav, rõdud (2)
In: 1. korrus
Material: EST. Betoon. Armeeritud. Kohtvalu 50 mm, EST. Geotekstiil 13 mm, EST. Soojustus. EPS 60 mm, EST. Soojustus. EPS 100 kaldekiht, PIR Kingspan Therma TP10 110mm 50 mm, EST. Betoon. Kohtvalu. Tasandus 30 mm
Pset_ConcreteElementGeneral - FireRating: R45
Pset_QuantityTakeOff - Reference: VL-08.1 - käidav, rõdud
Pset_RoofCommon - IsExternal: no; Reference: VL-08.1 - käidav, rõdud; FireRating: R45
AR_Katus - 000_Muinsuskaitse: no; 340_Soojusläbivus: 0; 001_Nimetus: VL-08.1 - käidav, rõdud; 003_Elemendi_staadium: Projekteeritud; 205_Tüüp: VL-08.1; 325_Helipidavus: ≥55 dB; 330_Tulekindlus: R45
Name (Basic Roof:VL-08.1 - käidav, rõdud:...) | ProjectedArea (m2) | TotalArea (m2) = 520_Pindala (m2)
6609713 | 26.348 | 26.353
6609906 | 26.1431 | 26.1481

# IfcRoof: Basic Roof:ol. olev - 100mm, Basic Roof:ol. olev - 100mm:10911358
In: 1. korrus
Material: ol. olev materjal 100 mm
Pset_ConcreteElementGeneral - FireRating: -
Pset_QuantityTakeOff - Reference: ol. olev - 100mm
Pset_RoofCommon - IsExternal: yes; Reference: ol. olev - 100mm; FireRating: -; ProjectedArea: 1.89316 m2; TotalArea: 1.89316 m2
AR_Katus - 000_Muinsuskaitse: no; 340_Soojusläbivus: 0; 001_Nimetus: ol. olev - 100mm; 003_Elemendi_staadium: Olemasolev; 205_Tüüp: -; 325_Helipidavus: -; 330_Tulekindlus: -; 520_Pindala: 1.89316 m2

# IfcRoof: Basic Roof:ol. olev - 220mm (9)
Material: ol. olev materjal 220 mm
Pset_ConcreteElementGeneral - FireRating: -
Pset_QuantityTakeOff - Reference: ol. olev - 220mm
Pset_RoofCommon - Reference: ol. olev - 220mm; FireRating: -; IsExternal: yes
AR_Katus - 000_Muinsuskaitse: no; 340_Soojusläbivus: 0; 001_Nimetus: ol. olev - 220mm; 003_Elemendi_staadium: Olemasolev; 205_Tüüp: -; 325_Helipidavus: -; 330_Tulekindlus: -
Name (Basic Roof:ol. olev - 220mm:...) | In | ProjectedArea (m2) | TotalArea (m2) = 520_Pindala (m2)
1236404 | 3. korrus | 65.2186 | 63.5033
2777973 | 3. korrus | 68.2728 | 63.371
6574199 | 4. korrus | 103.739 | 103.739
6574847 | 3. korrus | 117.264 | 117.264
6575067 | 1. korrus | 28.2411 | 28.2411
6575338 | 3. korrus | 47.0061 | 47.0061
6599280 | 3. korrus | 46.98 | 46.98
6609899 | 1. korrus | 28.0327 | 28.0327
8718467 | E-korpus 2. korrus | 1185.06 | 1179.05

# IfcSlab: Basic Roof:KL-11 - mitte-käidav, ilma kaldeta, Basic Roof:KL-11 - mitte-käidav, ilma kaldeta:16660699
In: -1. korrus
PredefinedType: ROOF; Material: EST. Rullmaterjal. SBS 5 mm, EST. Soojustus.PIR_Eurothane Silver E 250 mm, EST. Betoon. Kohtvalu. Tasandus 30 mm
Pset_ConcreteElementGeneral - FireRating: R45
Pset_QuantityTakeOff - Reference: KL-11 - mitte-käidav, ilma kaldeta; sets with these values: 2
Pset_SlabCommon - PitchAngle: 0 deg; IsExternal: yes; Reference: KL-11 - mitte-käidav, ilma kaldeta; FireRating: R45
AR_Vahelagi - 003_Elemendi_staadium: Projekteeritud; 505_Paksus: 285 mm; 510_Bruto_pindala: 4.87297 m2; 515_Neto_pindala: 4.87297 m2
BaseQuantities - NetArea: 0.452714 m2; NetVolume: 0.129023 m2; GrossArea: 4.87297 m2; GrossVolume: 0.129023 m2; Perimeter: 12940.3 mm

# IfcSlab: Basic Roof:ol. olev - 100mm, Basic Roof:ol. olev - 100mm:10911358
In: 1. korrus
PredefinedType: ROOF; Material: ol. olev materjal 100 mm
Pset_ConcreteElementGeneral - FireRating: -
Pset_QuantityTakeOff - Reference: ol. olev - 100mm; sets with these values: 2
Pset_SlabCommon - PitchAngle: 0 deg; IsExternal: yes; Reference: ol. olev - 100mm; FireRating: -
AR_Vahelagi - 003_Elemendi_staadium: Olemasolev; 505_Paksus: 100 mm; 510_Bruto_pindala: 1.89316 m2; 515_Neto_pindala: 1.89316 m2
BaseQuantities - NetArea: 0.17588 m2; NetVolume: 0.017588 m2; GrossArea: 1.89316 m2; GrossVolume: 0.017588 m2; Perimeter: 11165.3 mm

# IfcSlab: Basic Roof:ol. olev - 220mm (9)
Type - PredefinedType: ROOF
Type - Pset_ConcreteElementGeneral - FireRating: -
Type - Pset_SlabCommon - ThermalTransmittance: 0 kg/K/s3; IsExternal: yes; AcousticRating: -; FireRating: -
Type - AR_Vahelagi - 000_Muinsuskaitse: no; 340_Soojusläbivus: 0; 001_Nimetus: ol. olev - 220mm; 205_Tüüp: -; 325_Helipidavus: -; 330_Tulekindlus: -
Pset_QuantityTakeOff - Reference: ol. olev - 220mm; sets with these values: 2
Pset_SlabCommon - PitchAngle: 0 deg; Reference: ol. olev - 220mm
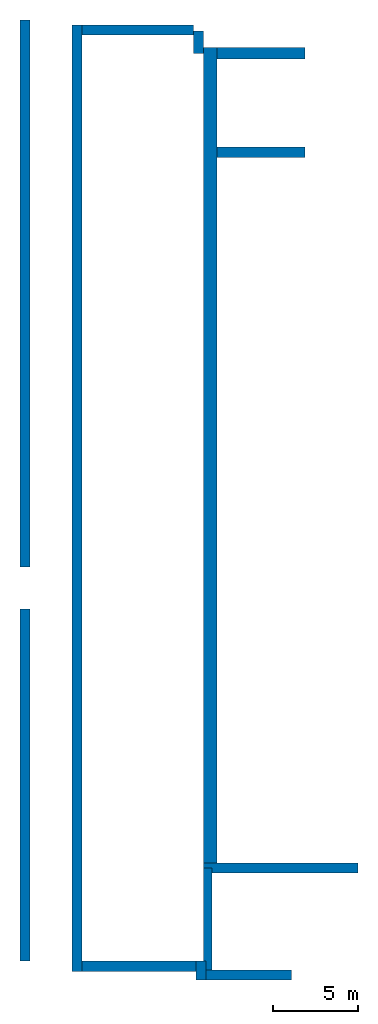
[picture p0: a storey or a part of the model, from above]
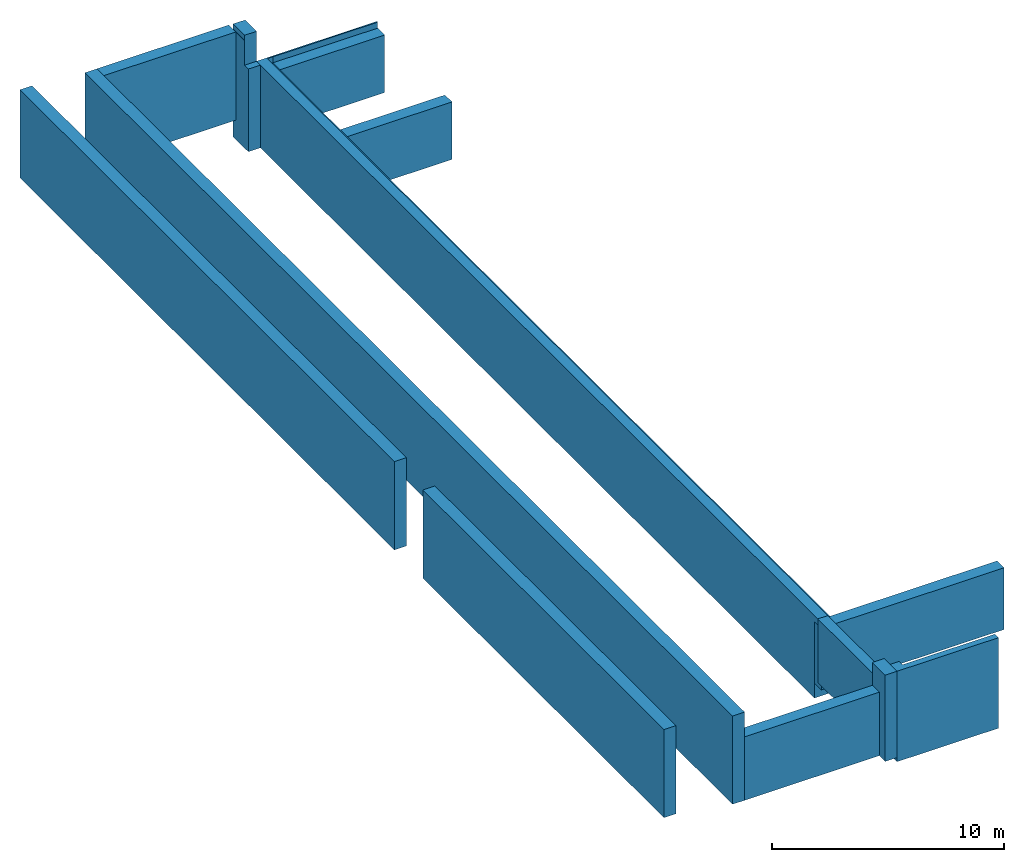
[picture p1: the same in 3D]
Properties of the parts of a building model (IFC2X3), part 6 of 7

# IfcSlab: Basic Roof:ol. olev - 220mm (9)
AR_Vahelagi - 003_Elemendi_staadium: Olemasolev; 505_Paksus: 220 mm
Name (Basic Roof:ol. olev - 220mm:...) | In | 510_Bruto_pindala (m2) = 515_Neto_pindala (m2) = NetArea (m2) | GrossArea (m2) | GrossVolume (m3) | NetVolume (m3) | Perimeter (mm) | Width (mm)
1236404:1 | 3. korrus | 63.5033 | 0.880228 | 0.19365 | 13.9707 | 4257.82 | 561.628
2777973:1 | 3. korrus | 63.371 | 7.82465 | 1.72142 | 13.9407 | 13409.7 | 5200.18
6574199:1 | 4. korrus | 103.739 | 80.5161 | 17.7135 | 22.8226 | 87520.4
6574847:1 | 3. korrus | 117.264 | 117.264 | 25.7981 | 25.7981 | 91580
6575067:1 | 1. korrus | 28.2411 | 23.9095 | 5.26008 | 6.21304 | 19600.7 | 5220
6575338:1 | 3. korrus | 47.0061 | 26.9883 | 5.93744 | 10.3413 | 20780.4 | 5170.18
6599280:1 | 3. korrus | 46.98 | 26.9883 | 5.93744 | 10.3356 | 20780.4 | 5170.18
6609899:1 | 1. korrus | 28.0327 | 23.8654 | 5.25038 | 6.1672 | 19581.5 | 5210.38
8718467:1 | E-korpus 2. korrus | 1179.05 | 370.715 | 81.5572 | 259.152 | 151958

# IfcSlab: Floor:P-03 - Amfiteatri lava (2)
In: 1. korrus
Type - PredefinedType: FLOOR; Material: EST. Betoonplaat tume 20 mm, EST. Betoonplaat 150 mm, EST. Soojustus. XPS. Default 200 mm
Type - Pset_ConcreteElementGeneral - FireRating: -
Type - Pset_SlabCommon - ThermalTransmittance: 0 kg/K/s3; IsExternal: yes; AcousticRating: -; FireRating: -
Type - AR_Vahelagi - 000_Muinsuskaitse: no; 340_Soojusläbivus: 0; 335_Välispiire: yes; 001_Nimetus: P-03 - Amfiteatri lava; 205_Tüüp: P-03; 325_Helipidavus: -; 330_Tulekindlus: -
Pset_QuantityTakeOff - Reference: P-03 - Amfiteatri lava; sets with these values: 2
Pset_SlabCommon - LoadBearing: no; PitchAngle: 0 deg; Reference: P-03 - Amfiteatri lava
AR_Vahelagi - 500_Kandev: no; 003_Elemendi_staadium: Projekteeritud; 505_Paksus: 370 mm
Name (Floor:P-03 - Amfiteatri lava:...) | 510_Bruto_pindala (m2) = 515_Neto_pindala (m2) = GrossArea (m2) = NetArea (m2) | GrossVolume (m3) = NetVolume (m3) | Perimeter (mm)
12142029 | 50.6898 | 18.7552 | 31432.7
12142490 | 48.3906 | 17.9045 | 35738.8

# IfcSlab: Floor:VL-03 - fuajee põrand, Floor:VL-03 - fuajee põrand:10158534
In: 1. korrus
Type - PredefinedType: FLOOR; Material: EST. Betoonplaat 25 mm, EST. Betoon. Armeeritud. Kohtvalu 70 mm, EST. Soojustus. EPS 135 mm
Type - Pset_ConcreteElementGeneral - FireRating: -
Type - Pset_SlabCommon - IsExternal: no; ThermalTransmittance: 0 kg/K/s3; AcousticRating: -; FireRating: -
Type - AR_Vahelagi - 000_Muinsuskaitse: no; 335_Välispiire: no; 340_Soojusläbivus: 0; 001_Nimetus: VL-03 - fuajee põrand; 205_Tüüp: VL-03; 325_Helipidavus: -; 330_Tulekindlus: -
Pset_QuantityTakeOff - Reference: VL-03 - fuajee põrand; sets with these values: 2
Pset_SlabCommon - LoadBearing: yes; PitchAngle: 0 deg; Reference: VL-03 - fuajee põrand
AR_Vahelagi - 500_Kandev: yes; 003_Elemendi_staadium: Projekteeritud; 505_Paksus: 230 mm; 510_Bruto_pindala: 1352.21 m2; 515_Neto_pindala: 1352.21 m2
BaseQuantities - GrossArea: 26.4145 m2; NetArea: 1352.21 m2; GrossVolume: 6.07535 m3; NetVolume: 311.008 m3; Perimeter: 353440 mm

# IfcSlab: Floor:VL-08 - 50 välisõhu kohal (2)
In: 3. korrus
Type - PredefinedType: FLOOR; Material: EST. Soojustus. EPS 50 mm, EST. Fassaadikate. Krohv. Valge 10 mm
Type - Pset_ConcreteElementGeneral - FireRating: REI60
Type - Pset_SlabCommon - ThermalTransmittance: 0 kg/K/s3; IsExternal: yes; AcousticRating: ≥55dB; FireRating: REI60
Type - AR_Vahelagi - 000_Muinsuskaitse: no; 340_Soojusläbivus: 0; 335_Välispiire: yes; 001_Nimetus: VL-08 - 50 välisõhu kohal; 205_Tüüp: VL-08; 325_Helipidavus: ≥55dB; 330_Tulekindlus: REI60
Pset_QuantityTakeOff - Reference: VL-08 - 50 välisõhu kohal; sets with these values: 2
Pset_SlabCommon - LoadBearing: yes; PitchAngle: 0 deg; Reference: VL-08 - 50 välisõhu kohal
AR_Vahelagi - 500_Kandev: yes; 003_Elemendi_staadium: Projekteeritud; 505_Paksus: 60 mm
BaseQuantities - Perimeter: 20900 mm; Width: 4400.18 mm
Name (Floor:VL-08 - 50 välisõhu kohal:...) | 510_Bruto_pindala (m2) = 515_Neto_pindala (m2) = NetArea (m2) | GrossArea (m2) | GrossVolume (m3) | NetVolume (m3)
10906010 | 27.1966 | 22.9689 | 1.37814 | 1.6318
10906024 | 27.2137 | 22.8958 | 1.37375 | 1.63282

# IfcSlab: Floor:muru, Floor:muru:17111920
In: 1. korrus
Type - PredefinedType: FLOOR; Material: LUMION_grass 200 mm
Type - Pset_ConcreteElementGeneral - FireRating: -
Type - Pset_SlabCommon - IsExternal: no; ThermalTransmittance: 0 kg/K/s3; AcousticRating: -; FireRating: -
Type - AR_Vahelagi - 000_Muinsuskaitse: no; 335_Välispiire: no; 340_Soojusläbivus: 0; 001_Nimetus: muru; 325_Helipidavus: -; 330_Tulekindlus: -
Pset_QuantityTakeOff - Reference: muru; sets with these values: 2
Pset_SlabCommon - LoadBearing: no; PitchAngle: 0 deg; Reference: muru
AR_Vahelagi - 003_Elemendi_staadium: Projekteeritud; 505_Paksus: 200 mm; 510_Bruto_pindala: 212.001 m2; 515_Neto_pindala: 212.001 m2
BaseQuantities - GrossArea: 212.001 m2; NetArea: 212.001 m2; GrossVolume: 42.4003 m3; NetVolume: 42.4003 m3; Perimeter: 102260 mm

# IfcSlab: Floor:ol. olev - 100mm, Floor:ol. olev - 100mm:10898519
In: 1. korrus
Type - PredefinedType: FLOOR; Material: ol. olev materjal 100 mm
Type - Pset_SlabCommon - IsExternal: no
Type - AR_Vahelagi - 335_Välispiire: no; 001_Nimetus: ol. olev - 100mm
Pset_QuantityTakeOff - Reference: ol. olev - 100mm; sets with these values: 2
Pset_SlabCommon - LoadBearing: no; PitchAngle: 0 deg; Reference: ol. olev - 100mm
AR_Vahelagi - 003_Elemendi_staadium: Olemasolev; 505_Paksus: 100 mm; 510_Bruto_pindala: 1.89019 m2; 515_Neto_pindala: 1.89019 m2
BaseQuantities - GrossArea: 1.89019 m2; NetArea: 1.89019 m2; GrossVolume: 0.189019 m3; NetVolume: 0.189019 m3; Perimeter: 11146.3 mm; Width: 362.773 mm

# IfcSlab: Floor:ol. olev - 200mm (2)
Type - PredefinedType: FLOOR; Material: ol. olev materjal 200 mm
Type - Pset_ConcreteElementGeneral - FireRating: -
Type - Pset_SlabCommon - IsExternal: no; ThermalTransmittance: 0 kg/K/s3; AcousticRating: -; FireRating: -
Type - AR_Vahelagi - 335_Välispiire: no; 340_Soojusläbivus: 0; 001_Nimetus: ol. olev - 200mm; 205_Tüüp: -; 325_Helipidavus: -; 330_Tulekindlus: -
Pset_QuantityTakeOff - Reference: ol. olev - 200mm; sets with these values: 2
Pset_SlabCommon - LoadBearing: no; Reference: ol. olev - 200mm; PitchAngle: 0 deg
AR_Vahelagi - 500_Kandev: no; 003_Elemendi_staadium: Olemasolev; 505_Paksus: 200 mm
Name (Floor:ol. olev - 200mm:...) | In | 510_Bruto_pindala (m2) = 515_Neto_pindala (m2) = NetArea (m2) | GrossArea (m2) | GrossVolume (m3) | NetVolume (m3) | Perimeter (mm) | Width (mm)
6282444 | -1. korrus | 0.53275 | 0.47169 | 0.0943379 | 0.10655 | 2919.59 | 646.15
6282788 | 1. korrus | 30.1249 | 30.1249 | 6.02497 | 6.02497 | 108709 | 560

# IfcSlab: Floor:ol. olev - 220mm (4)
Type - PredefinedType: FLOOR; Material: ol. olev materjal 220 mm
Type - Pset_SlabCommon - IsExternal: no
Type - AR_Vahelagi - 335_Välispiire: no; 001_Nimetus: ol. olev - 220mm
Pset_QuantityTakeOff - Reference: ol. olev - 220mm; sets with these values: 2
Pset_SlabCommon - LoadBearing: no; PitchAngle: 0 deg; Reference: ol. olev - 220mm
AR_Vahelagi - 500_Kandev: no; 003_Elemendi_staadium: Olemasolev; 505_Paksus: 220 mm
Name (Floor:ol. olev - 220mm:...) | In | 510_Bruto_pindala (m2) = 515_Neto_pindala (m2) = NetArea (m2) | NetVolume (m3) | Perimeter (mm) | GrossArea (m2) | GrossVolume (m3)
5225482 | E-korpus -1. korrus | 193.444 | 42.0175 | 157116 | Material: ol. olev materjal
5282192 | 1. korrus | 18.1534 | 3.99376 | 17930 | 3.66802 | 0.806965 | BaseQuantities - Width: 3475 mm
5292181 | 1. korrus | 5.46255 | 1.20176 | 12970 | 1.05027 | 0.231059 | BaseQuantities - Width: 995 mm
11019143 | 1. korrus | 1354.25 | 297.935 | 465336 | 27.6056 | 6.07324

# IfcSlab: Floor:ol. olev - 300mm (2)
Type - PredefinedType: FLOOR; Material: ol. olev materjal 300 mm
Type - Pset_SlabCommon - IsExternal: no
Type - AR_Vahelagi - 335_Välispiire: no; 001_Nimetus: ol. olev - 300mm
Pset_QuantityTakeOff - Reference: ol. olev - 300mm; sets with these values: 2
Pset_SlabCommon - LoadBearing: no; PitchAngle: 0 deg; Reference: ol. olev - 300mm
AR_Vahelagi - 500_Kandev: no; 003_Elemendi_staadium: Olemasolev; 505_Paksus: 300 mm
Name (Floor:ol. olev - 300mm:...) | In | 510_Bruto_pindala (m2) = 515_Neto_pindala (m2) = NetArea (m2) | NetVolume (m3) | Perimeter (mm)
879121 | 3. korrus | 3983.45 | 1195.05 | 434412 | BaseQuantities - GrossArea: 103.916 m2; GrossVolume: 31.1749 m3
891932 | 4. korrus | 3576.82 | 1071.12 | 427582 | Material: ol. olev materjal

# IfcSlab: Floor:ol. olev - 315mm, Floor:ol. olev - 315mm:2916542
In: -1. korrus
Type - PredefinedType: FLOOR; Material: ol. olev materjal 315 mm
Type - Pset_SlabCommon - IsExternal: yes
Type - AR_Vahelagi - 001_Nimetus: ol. olev - 315mm; 335_Välispiire: yes
Pset_QuantityTakeOff - Reference: ol. olev - 315mm; sets with these values: 2
Pset_SlabCommon - LoadBearing: no; PitchAngle: 0 deg; Reference: ol. olev - 315mm
AR_Vahelagi - 500_Kandev: no; 003_Elemendi_staadium: Olemasolev; 505_Paksus: 315 mm; 510_Bruto_pindala: 4383.17 m2; 515_Neto_pindala: 4383.17 m2
BaseQuantities - GrossArea: 253.13 m2; NetArea: 4383.17 m2; GrossVolume: 79.7361 m3; NetVolume: 1380.29 m3; Perimeter: 455192 mm

# IfcSlab: Floor:ol. olev - 320mm (2)
Type - PredefinedType: FLOOR; Material: ol. olev materjal 320 mm
Type - Pset_SlabCommon - IsExternal: no
Type - AR_Vahelagi - 335_Välispiire: no; 001_Nimetus: ol. olev - 320mm
Pset_QuantityTakeOff - Reference: ol. olev - 320mm; sets with these values: 2
Pset_SlabCommon - LoadBearing: no; Reference: ol. olev - 320mm; PitchAngle: 0 deg
AR_Vahelagi - 500_Kandev: no; 003_Elemendi_staadium: Olemasolev; 505_Paksus: 320 mm
Name (Floor:ol. olev - 320mm:...) | In | 510_Bruto_pindala (m2) = 515_Neto_pindala (m2) = NetArea (m2) | GrossArea (m2) | GrossVolume (m3) | NetVolume (m3) | Perimeter (mm) | Width (mm)
834595 | 1. korrus | 3778.71 | 2.13595 | 0.683505 | 1208.84 | 549790 | 1655.55
836247 | 2. korrus | 4570.28 | 2.56517 | 0.820854 | 1462.12 | 699300 | 1055.55

# IfcSlab: Floor:ol. olev - 350mm, Floor:ol. olev - 350mm:2395541
In: 1. korrus
Type - PredefinedType: FLOOR
Type - Pset_SlabCommon - IsExternal: no
Type - AR_Vahelagi - 001_Nimetus: ol. olev - 350mm
Material: ol. olev materjal
Pset_QuantityTakeOff - Reference: ol. olev - 350mm; sets with these values: 2
Pset_SlabCommon - LoadBearing: no; PitchAngle: 0 deg; Reference: ol. olev - 350mm
AR_Vahelagi - 500_Kandev: no; 003_Elemendi_staadium: Olemasolev; 505_Paksus: 350 mm; 510_Bruto_pindala: 758.215 m2; 515_Neto_pindala: 758.215 m2
BaseQuantities - NetArea: 758.215 m2; NetVolume: 265.133 m3; Perimeter: 237588 mm

# IfcSlab: Floor:ol. olev - 450mm, Floor:ol. olev - 450mm:11019551
In: 1. korrus
Type - PredefinedType: FLOOR; Material: ol. olev materjal 450 mm
Type - Pset_SlabCommon - IsExternal: no
Type - AR_Vahelagi - 001_Nimetus: ol. olev - 450mm
Pset_QuantityTakeOff - Reference: ol. olev - 450mm; sets with these values: 2
Pset_SlabCommon - LoadBearing: no; PitchAngle: 0 deg; Reference: ol. olev - 450mm
AR_Vahelagi - 500_Kandev: no; 003_Elemendi_staadium: Olemasolev; 505_Paksus: 450 mm; 510_Bruto_pindala: 771.415 m2; 515_Neto_pindala: 771.415 m2
BaseQuantities - GrossArea: 0.94717 m2; NetArea: 771.415 m2; GrossVolume: 0.426227 m3; NetVolume: 346.96 m3; Perimeter: 500988 mm

# IfcSlab: Floor:ol. olev - 600mm, Floor:ol. olev - 600mm:1242796
In: E-korpus 2. korrus
Type - PredefinedType: FLOOR; Material: ol. olev materjal 600 mm
Type - Pset_SlabCommon - IsExternal: no
Type - AR_Vahelagi - 001_Nimetus: ol. olev - 600mm
Pset_QuantityTakeOff - Reference: ol. olev - 600mm; sets with these values: 2
Pset_SlabCommon - LoadBearing: no; Reference: ol. olev - 600mm; PitchAngle: 0 deg
AR_Vahelagi - 500_Kandev: no; 003_Elemendi_staadium: Olemasolev; 505_Paksus: 600 mm; 510_Bruto_pindala: 87.1949 m2; 515_Neto_pindala: 87.1949 m2
BaseQuantities - GrossArea: 7.60235 m2; NetArea: 87.1949 m2; GrossVolume: 4.56141 m3; NetVolume: 52.317 m3; Perimeter: 50007.5 mm; Width: 561.628 mm

# IfcSlab: Monolithic Landing:100 mm Thickness (2)
In: 1. korrus
Type - PredefinedType: LANDING
Type - Pset_SlabCommon - IsExternal: no
Type - AR_Vahelagi - 001_Nimetus: 100 mm Thickness
Material: ol. olev materjal
Pset_QuantityTakeOff - Reference: 100 mm Thickness; sets with these values: 2
Pset_SlabCommon - PitchAngle: 0 deg; Reference: 100 mm Thickness
AR_Vahelagi - 003_Elemendi_staadium: Olemasolev
Name (Cast-In-Place Stair:Stair:...) | NetArea (m2) | NetVolume (m3)
4087577 Landing 1 | 7.42706 | 0.337155
4087629 Landing 1 | 9.08992 | 0.41756

# IfcSlab: Non-Monolithic Landing:Non-Monolithic Landing (2)
Type - PredefinedType: LANDING
Type - Pset_SlabCommon - IsExternal: no
Type - AR_Vahelagi - 001_Nimetus: Non-Monolithic Landing
Material: ol. olev materjal
Pset_QuantityTakeOff - Reference: Non-Monolithic Landing; sets with these values: 2
Pset_SlabCommon - Reference: Non-Monolithic Landing
AR_Vahelagi - 003_Elemendi_staadium: Olemasolev
Name (Assembled Stair:Stair:...) | In | GrossArea (m2) | NetArea (m2) | GrossVolume (m3) = NetVolume (m3) | Perimeter (mm) | Width (mm)
4087566 Landing 1 | 1. korrus | 3.2844 | 6.9638 | 0.16422 | 7900 | 1190
4087618 Landing 1 | E-korpus 2. korrus | 4.0848 | 8.5936 | 0.20424 | 8480 | 1480

# IfcSlab: Trepi alune 4K1:Trepi alune 4K, Trepi alune 4K1:Trepi alune 4K:2850047
In: 5. korrus
Type - PredefinedType: FLOOR; Material: LUMION_concrete stairs
Type - Pset_SlabCommon - IsExternal: no
Type - AR_Vahelagi - 001_Nimetus: Trepi alune 4K
Pset_QuantityTakeOff - Reference: Trepi alune 4K; sets with these values: 2
Pset_SlabCommon - Reference: Trepi alune 4K
AR_Vahelagi - 003_Elemendi_staadium: Olemasolev; 510_Bruto_pindala: 1.74799 m2; 515_Neto_pindala: 1.74799 m2
BaseQuantities - NetArea: 1.74799 m2; NetVolume: 2.01019 m3

# IfcSlab: Trepi alune 4K:Trepi alune 4K, Trepi alune 4K:Trepi alune 4K:2849949
In: 5. korrus
Type - PredefinedType: FLOOR; Material: LUMION_concrete stairs
Type - Pset_SlabCommon - IsExternal: no
Type - AR_Vahelagi - 001_Nimetus: Trepi alune 4K
Pset_QuantityTakeOff - Reference: Trepi alune 4K; sets with these values: 2
Pset_SlabCommon - Reference: Trepi alune 4K
AR_Vahelagi - 003_Elemendi_staadium: Olemasolev; 510_Bruto_pindala: 1.7775 m2; 515_Neto_pindala: 1.7775 m2
BaseQuantities - GrossArea: 1.7775 m2; NetArea: 1.7775 m2; GrossVolume: 0.551348 m3; NetVolume: 2.0965 m3; Perimeter: 16967.3 mm

# IfcSlab: VTR-11 betoonplaat:VTR-11 betoonplaat, VTR-11 betoonplaat:VTR-11 betoonplaat:3370880
In: 3. korrus
Type - PredefinedType: FLOOR; Material: LUMION_concrete stairs
Type - Pset_SlabCommon - IsExternal: no
Type - AR_Vahelagi - 001_Nimetus: VTR-11 betoonplaat
Pset_QuantityTakeOff - Reference: VTR-11 betoonplaat; sets with these values: 2
Pset_SlabCommon - Reference: VTR-11 betoonplaat
AR_Vahelagi - 003_Elemendi_staadium: Olemasolev; 510_Bruto_pindala: 1.709 m2; 515_Neto_pindala: 1.709 m2
BaseQuantities - GrossArea: 1.709 m2; NetArea: 1.709 m2; GrossVolume: 1.96535 m3; NetVolume: 1.96535 m3; Perimeter: 16549.7 mm

# IfcSlab: VTR-12 betoonplaat:VTR-12 betoonplaat, VTR-12 betoonplaat:VTR-12 betoonplaat:3370889
In: 3. korrus
Type - PredefinedType: FLOOR; Material: ol. olev materjal
Type - Pset_SlabCommon - IsExternal: no
Type - AR_Vahelagi - 001_Nimetus: VTR-12 betoonplaat
Pset_QuantityTakeOff - Reference: VTR-12 betoonplaat; sets with these values: 2
Pset_SlabCommon - Reference: VTR-12 betoonplaat
AR_Vahelagi - 003_Elemendi_staadium: Olemasolev; 510_Bruto_pindala: 1.80565 m2; 515_Neto_pindala: 1.80565 m2
BaseQuantities - GrossArea: 1.80565 m2; NetArea: 1.80565 m2; GrossVolume: 1.82371 m3; NetVolume: 1.82371 m3; Perimeter: 17111.9 mm

# IfcStair: Assembled Stair:VTR-11, 165x300mm (3)
ShapeType: STRAIGHT_RUN_STAIR
Pset_QuantityTakeOff - Reference: VTR-11, 165x300mm
Pset_StairCommon - IsExternal: yes; Reference: VTR-11, 165x300mm; NumberOfRiser: 20; NumberOfTreads: 20; RiserHeight: 165 mm; TreadLength: 300 mm
AR - 335_Välispiire: yes; 001_Nimetus: VTR-11, 165x300mm; 002_Elemendi_staadium: Projekteeritud; 205_Tüüp: VTR-11; 455_Eriomadused: vt. spetsi AR-8-04-02; 220_Viimistlus: Musta kiviga pesubetoonplaat 30x120x5cm, must, esiserv 15mm faasiga; 310_Materjal: Metallkonstruktsioonist trepp
Name (Assembled Stair:Stair:...) | In
11996242 | 3. korrus
12056405 | 4. korrus
12056749 | 4. korrus

# IfcStair: Assembled Stair:VTR-12, 165x300mm, Assembled Stair:Stair:11996553
In: 3. korrus
ShapeType: STRAIGHT_RUN_STAIR
Pset_QuantityTakeOff - Reference: VTR-12, 165x300mm
Pset_StairCommon - IsExternal: yes; Reference: VTR-12, 165x300mm; NumberOfRiser: 20; NumberOfTreads: 20; RiserHeight: 165 mm; TreadLength: 300 mm
AR - 335_Välispiire: yes; 001_Nimetus: VTR-12, 165x300mm; 002_Elemendi_staadium: Projekteeritud; 205_Tüüp: VTR-12; 455_Eriomadused: vt. spetsi AR-8-04-02; 220_Viimistlus: Musta kiviga pesubetoonplaat 30x120x5cm, must, esiserv 15mm faasiga; 310_Materjal: Metallkonstruktsioonist trepp

# IfcStair: Assembled Stair:ol. olev trepp 50 (2)
ShapeType: STRAIGHT_RUN_STAIR
Pset_QuantityTakeOff - Reference: ol. olev trepp 50
Pset_StairCommon - IsExternal: no; Reference: ol. olev trepp 50; NumberOfRiser: 11; NumberOfTreads: 10; RiserHeight: 148.333 mm; TreadLength: 300 mm
AR - 001_Nimetus: ol. olev trepp 50; 002_Elemendi_staadium: Olemasolev
Name (Assembled Stair:Stair:...) | In
4087566 | 1. korrus
4087618 | E-korpus 2. korrus

# IfcStair: Cast-In-Place Stair:ol. olev trepp, 150x300 H=55 (2)
In: 1. korrus
ShapeType: STRAIGHT_RUN_STAIR
Pset_QuantityTakeOff - Reference: ol. olev trepp, 150x300 H=55
Pset_StairCommon - IsExternal: no; Reference: ol. olev trepp, 150x300 H=55; NumberOfRiser: 11; NumberOfTreads: 10; RiserHeight: 148.333 mm; TreadLength: 300 mm
AR - 001_Nimetus: ol. olev trepp, 150x300 H=55; 002_Elemendi_staadium: Olemasolev
Name (Cast-In-Place Stair:Stair:...)
4087577
4087629

# IfcStair: Cast-In-Place Stair:ol. olev trepp,166x300, Cast-In-Place Stair:Stair:5231754
In: E-korpus -1. korrus
ShapeType: STRAIGHT_RUN_STAIR
Pset_QuantityTakeOff - Reference: ol. olev trepp,166x300
Pset_StairCommon - IsExternal: no; Reference: ol. olev trepp,166x300; NumberOfRiser: 7; NumberOfTreads: 6; RiserHeight: 160 mm; TreadLength: 300 mm
AR - 001_Nimetus: ol. olev trepp,166x300; 002_Elemendi_staadium: Olemasolev

# IfcStair: trepitalaˇ72:trepitalaˇ1 (2)
In: 1. korrus
Name (trepitalaˇ72:trepitalaˇ1:...)
4087653 | Material: ol. olev materjal
4087653 | Pset_QuantityTakeOff - Reference: trepitalaˇ1; Pset_StairCommon - IsExternal: no; Reference: trepitalaˇ1; AR - 001_Nimetus: trepitalaˇ1; 002_Elemendi_staadium: Olemasolev

# IfcStair: trepitalaˇ74:trepitalaˇ1 (2)
In: 1. korrus
Name (trepitalaˇ74:trepitalaˇ1:...)
4087603 | Material: <Unnamed>
4087603 | Pset_QuantityTakeOff - Reference: trepitalaˇ1; Pset_StairCommon - IsExternal: no; Reference: trepitalaˇ1; AR - 001_Nimetus: trepitalaˇ1; 002_Elemendi_staadium: Olemasolev

# IfcStairFlight: Monolithic Run:Monolithic Run 55mm (2)
In: 1. korrus
Type - PredefinedType: STRAIGHT
Type - Pset_StairFlightCommon - NosingLength: 0 mm
NumberOfRiser: 11; NumberOfTreads: 10; RiserHeight: 0.486658 mm; TreadLength: 0.984252 mm; Material: ol. olev materjal
Pset_QuantityTakeOff - Reference: Monolithic Run 55mm
Pset_StairFlightCommon - Reference: Monolithic Run 55mm; NumberOfRiser: 11; NumberOfTreads: 10; RiserHeight: 148.333 mm; TreadLength: 300 mm; TreadLengthAtOffset: 300 mm; TreadLengthAtInnerSide: 300 mm
BaseQuantities - Length: 3000 mm
Name (Cast-In-Place Stair:Stair:...) | WalkingLineOffset (mm) | NetVolume (m3)
4087577 Run 1 | 1.91929 | 0.461013
4087629 Run 1 | 1.9685 | 0.487881

# IfcStairFlight: Monolithic Run:Ol. olev monolithic Run 400mm, Cast-In-Place Stair:Stair:5231754 Run 1
In: E-korpus -1. korrus
Type - PredefinedType: STRAIGHT
Type - Pset_StairFlightCommon - NosingLength: 0 mm
NumberOfRiser: 7; NumberOfTreads: 6; RiserHeight: 0.524934 mm; TreadLength: 0.984252 mm; Material: ol. olev - trepp
Pset_QuantityTakeOff - Reference: Ol. olev monolithic Run 400mm
Pset_StairFlightCommon - Reference: Ol. olev monolithic Run 400mm; NumberOfRiser: 7; NumberOfTreads: 6; RiserHeight: 160 mm; TreadLength: 300 mm; WalkingLineOffset: 4.04199 mm; TreadLengthAtOffset: 300 mm; TreadLengthAtInnerSide: 300 mm
BaseQuantities - NetVolume: 2.21719 m3; Length: 1800 mm

# IfcStairFlight: Non-Monolithic Run:Graniitplaat 60mm (4)
Type - PredefinedType: STRAIGHT
Type - Pset_StairFlightCommon - NosingLength: 0 mm
NumberOfRiser: 20; NumberOfTreads: 20; RiserHeight: 0.541339 mm; TreadLength: 0.984252 mm; Material: EST. Betoonplaat
Pset_QuantityTakeOff - Reference: Graniitplaat 60mm
Pset_StairFlightCommon - Reference: Graniitplaat 60mm; NumberOfRiser: 20; NumberOfTreads: 20; RiserHeight: 165 mm; TreadLength: 300 mm; TreadLengthAtOffset: 300 mm; TreadLengthAtInnerSide: 300 mm
BaseQuantities - Length: 6000 mm
Name (Assembled Stair:Stair:...) | In | WalkingLineOffset (mm) | GrossVolume (m3) | NetVolume (m3)
11996242 Run 1 | 3. korrus | 1.60761 | 0.01764 | 0.3528
11996553 Run 1 | 3. korrus | 1.54199 | 0.01692 | 0.3384
12056405 Run 1 | 4. korrus | 1.60761 | 0.01764 | 0.3528
12056749 Run 1 | 4. korrus | 1.60761 | 0.01764 | 0.3528

# IfcStairFlight: Non-Monolithic Run:ol. olev 50mm tread (2)
Type - PredefinedType: STRAIGHT
Type - Pset_StairFlightCommon - NosingLength: 0 mm
NumberOfRiser: 11; NumberOfTreads: 10; RiserHeight: 0.486658 mm; TreadLength: 0.984252 mm; Material: ol. olev materjal
Pset_QuantityTakeOff - Reference: ol. olev 50mm tread
Pset_StairFlightCommon - Reference: ol. olev 50mm tread; NumberOfRiser: 11; NumberOfTreads: 10; RiserHeight: 148.333 mm; TreadLength: 300 mm; TreadLengthAtOffset: 300 mm; TreadLengthAtInnerSide: 300 mm
BaseQuantities - Length: 3000 mm
Name (Assembled Stair:Stair:...) | In | WalkingLineOffset (mm) | GrossVolume (m3) | NetVolume (m3)
4087566 Run 1 | 1. korrus | 2.08333 | 0.01905 | 0.1905
4087618 Run 1 | E-korpus 2. korrus | 2.24738 | 0.02055 | 0.2055

# IfcWall: Basic Wall:SS-71 - 150 poorbetoon acoustic, Basic Wall:SS-71 - 150 poorbetoon acoustic:9543424
In: 1. korrus
Type - PredefinedType: STANDARD; Material: EST. Müüritis. Väikeplokk. Betoon-õõnesplokk 150 mm
Type - Pset_ConcreteElementGeneral - FireRating: EI180
Type - Pset_FireRatingProperties - SurfaceSpreadOfFlame: A1
Type - Pset_WallCommon - IsExternal: no; ThermalTransmittance: 0 kg/K/s3; AcousticRating: 44dB; FireRating: EI180; SurfaceSpreadOfFlame: A1
Type - AR_Sein - 000_Muinsuskaitse: no; 335_Välispiire: no; 340_Soojusläbivus: 0; 001_Nimetus: SS-71 - 150 poorbetoon acoustic; 205_Tüüp: SS-71; 325_Helipidavus: 44dB; 330_Tulekindlus: EI180; 376_Viimistlus_väljast: -; 505_Paksus: 150 mm
Pset_QuantityTakeOff - Reference: SS-71 - 150 poorbetoon acoustic; sets with these values: 2
Pset_WallCommon - ExtendToStructure: no; LoadBearing: no; Reference: SS-71 - 150 poorbetoon acoustic
AR_Sein - 500_Kandev: no; 003_Elemendi_staadium: Projekteeritud; 605_Neto_pindala: 9.26823 m2

# IfcWall: Basic Wall:VS-02 - 125 sooj. läbiv, Basic Wall:VS-02 - 125 sooj. läbiv:10312829
In: E-korpus 2. korrus
Type - PredefinedType: STANDARD; Material: EST. Ehitusplaat. Kipsplaat 15 mm, EST. Ehitusplaat. OSB 15 mm, EST. Õhkvahe. Roov. Kipsplaadi alusroov.Puit. Vertikaalne 25 mm, EST. Soojustus.PIR. Default 70 mm
Type - Pset_ConcreteElementGeneral - FireRating: REI180
Type - Pset_WallCommon - IsExternal: yes; AcousticRating: ≥65dB; FireRating: REI180; ThermalTransmittance: 0.36 kg/K/s3
Type - AR_Sein - 000_Muinsuskaitse: no; 335_Välispiire: yes; 001_Nimetus: VS-02 - 125 sooj. läbiv; 205_Tüüp: VS-02; 325_Helipidavus: ≥65dB; 330_Tulekindlus: REI180; 340_Soojusläbivus: 0.36; 376_Viimistlus_väljast: -; 505_Paksus: 125 mm
Pset_QuantityTakeOff - Reference: VS-02 - 125 sooj. läbiv; sets with these values: 2
Pset_WallCommon - ExtendToStructure: no; LoadBearing: no; Reference: VS-02 - 125 sooj. läbiv
AR_Sein - 500_Kandev: no; 003_Elemendi_staadium: Projekteeritud; 605_Neto_pindala: 37.1217 m2

# IfcWall: Basic Wall:VS-03.1 - soojustus (10)
Type - PredefinedType: STANDARD; Material: EST. Soojustus.PIR_Powerwall Pro 30 mm, EST. Metall. Alumiinium. Mütsprofiil. 42 mm, EST. Ehitusplaat. Kipsplaat 12.5 mm
Type - Pset_ConcreteElementGeneral - FireRating: REI180
Type - Pset_WallCommon - IsExternal: yes; AcousticRating: ≥55dB; FireRating: REI180; ThermalTransmittance: 0.34 kg/K/s3
Type - AR_Sein - 000_Muinsuskaitse: no; 335_Välispiire: yes; 001_Nimetus: VS-03.1 - soojustus; 205_Tüüp: VS-03.1; 325_Helipidavus: ≥55dB; 330_Tulekindlus: REI180; 340_Soojusläbivus: 0.34; 376_Viimistlus_väljast: -; 505_Paksus: 84.5 mm
Pset_QuantityTakeOff - Reference: VS-03.1 - soojustus; sets with these values: 2
Pset_WallCommon - LoadBearing: no; Reference: VS-03.1 - soojustus
AR_Sein - 500_Kandev: no; 003_Elemendi_staadium: Projekteeritud
Name (Basic Wall:VS-03.1 - soojustus:...) | In | ExtendToStructure | 605_Neto_pindala (m2)
8172449 | 1. korrus | no | 18.6832
8172576 | 1. korrus | no | 19.8466
8228435 | 2. korrus | no | 6.11312
8228485 | 2. korrus | no | 9.80272
8228546 | 2. korrus | no | 3.17151
8228711 | 2. korrus | no | 6.05523
8228768 | 2. korrus | no | 6.58306
8228810 | 2. korrus | no | 5.64716
8233235 | 3. korrus | yes | 8.79334
10395263 | 3. korrus | no | 7.54728

# IfcWall: Basic Wall:VS-21 - 160 plaadi tagune, Basic Wall:VS-21 - 160 plaadi tagune:10386668
In: 3. korrus
Type - PredefinedType: STANDARD; Material: EST. Ehitusplaat. Kipsplaat 12.5 mm, EST. Metall. Alumiinium. Mütsprofiil. 28 mm, EST. Soojustus.PIR. Default 120 mm
Type - Pset_ConcreteElementGeneral - FireRating: REI120
Type - Pset_WallCommon - IsExternal: yes; AcousticRating: ≥55dB; FireRating: REI120; ThermalTransmittance: 0.15 kg/K/s3
Type - AR_Sein - 000_Muinsuskaitse: no; 335_Välispiire: yes; 001_Nimetus: VS-21 - 160 plaadi tagune; 205_Tüüp: VS-21; 325_Helipidavus: ≥55dB; 330_Tulekindlus: REI120; 340_Soojusläbivus: 0.15; 376_Viimistlus_väljast: -; 505_Paksus: 160.5 mm
Pset_QuantityTakeOff - Reference: VS-21 - 160 plaadi tagune; sets with these values: 2
Pset_WallCommon - ExtendToStructure: no; LoadBearing: no; Reference: VS-21 - 160 plaadi tagune
AR_Sein - 500_Kandev: no; 003_Elemendi_staadium: Projekteeritud; 605_Neto_pindala: 11.2628 m2

# IfcWall: Basic Wall:ol. olev - 130mm, Basic Wall:ol. olev - 130mm:10389528
In: 3. korrus
Type - PredefinedType: STANDARD; Material: ol. olev materjal 130 mm
Type - Pset_WallCommon - IsExternal: no
Type - AR_Sein - 001_Nimetus: ol. olev - 130mm; 505_Paksus: 130 mm
Pset_QuantityTakeOff - Reference: ol. olev - 130mm; sets with these values: 2
Pset_WallCommon - ExtendToStructure: no; LoadBearing: no; Reference: ol. olev - 130mm
AR_Sein - 003_Elemendi_staadium: Olemasolev; 605_Neto_pindala: 8.15385 m2

# IfcWall: Basic Wall:ol. olev - 200mm, Basic Wall:ol. olev - 200mm:884873
In: 4. korrus
Type - PredefinedType: STANDARD; Material: ol. olev materjal 200 mm
Type - Pset_ConcreteElementGeneral - FireRating: -
Type - Pset_WallCommon - IsExternal: no; AcousticRating: -; FireRating: -; ThermalTransmittance: 0 kg/K/s3
Type - AR_Sein - 001_Nimetus: ol. olev - 200mm; 205_Tüüp: -; 325_Helipidavus: -; 330_Tulekindlus: -; 335_Välispiire: no; 340_Soojusläbivus: 0; 376_Viimistlus_väljast: -; 505_Paksus: 200 mm
Pset_QuantityTakeOff - Reference: ol. olev - 200mm; sets with these values: 2
Pset_WallCommon - LoadBearing: no; Reference: ol. olev - 200mm; ExtendToStructure: yes
AR_Sein - 500_Kandev: no; 003_Elemendi_staadium: Olemasolev; 605_Neto_pindala: 9.85618 m2

# IfcWall: Basic Wall:ol. olev - 330mm (2)
In: 3. korrus
Type - PredefinedType: STANDARD; Material: ol. olev materjal 330 mm
Type - Pset_WallCommon - IsExternal: no
Type - AR_Sein - 001_Nimetus: ol. olev - 330mm; 505_Paksus: 330 mm
Pset_QuantityTakeOff - Reference: ol. olev - 330mm; sets with these values: 2
Pset_WallCommon - LoadBearing: no; Reference: ol. olev - 330mm
AR_Sein - 003_Elemendi_staadium: Olemasolev
Name (Basic Wall:ol. olev - 330mm:...) | ExtendToStructure | 605_Neto_pindala (m2)
869614 | yes | 12.9746 | AR_Sein - 500_Kandev: no
10386469 | no | 12.59

# IfcWall: Basic Wall:ol. olev - 350mm, Basic Wall:ol. olev - 350mm:836156
In: 2. korrus
Type - PredefinedType: STANDARD; Material: ol. olev materjal 350 mm
Type - Pset_WallCommon - IsExternal: no
Type - AR_Sein - 001_Nimetus: ol. olev - 350mm; 505_Paksus: 350 mm
Pset_QuantityTakeOff - Reference: ol. olev - 350mm; sets with these values: 2
Pset_WallCommon - LoadBearing: yes; ExtendToStructure: yes; Reference: ol. olev - 350mm
AR_Sein - 500_Kandev: yes; 003_Elemendi_staadium: Olemasolev; 605_Neto_pindala: 16.5578 m2

# IfcWall: Basic Wall:ol. olev - 380mm, Basic Wall:ol. olev - 380mm:10355833
In: 3. korrus
Type - PredefinedType: STANDARD; Material: ol. olev materjal 380 mm
Type - Pset_WallCommon - IsExternal: no
Type - AR_Sein - 001_Nimetus: ol. olev - 380mm; 505_Paksus: 380 mm
Pset_QuantityTakeOff - Reference: ol. olev - 380mm; sets with these values: 2
Pset_WallCommon - ExtendToStructure: no; LoadBearing: yes; Reference: ol. olev - 380mm
AR_Sein - 500_Kandev: yes; 003_Elemendi_staadium: Olemasolev; 605_Neto_pindala: 12.947 m2

# IfcWall: Basic Wall:ol. olev - 510mm, Basic Wall:ol. olev - 510mm:1014939
In: -1. korrus
Type - PredefinedType: STANDARD; Material: ol. olev materjal 510 mm
Type - Pset_WallCommon - IsExternal: no
Type - AR_Sein - 001_Nimetus: ol. olev - 510mm; 505_Paksus: 510 mm
Pset_QuantityTakeOff - Reference: ol. olev - 510mm; sets with these values: 2
Pset_WallCommon - ExtendToStructure: no; LoadBearing: no; Reference: ol. olev - 510mm
AR_Sein - 500_Kandev: no; 003_Elemendi_staadium: Olemasolev; 605_Neto_pindala: 16.7762 m2

# IfcWall: Basic Wall:ol. olev - 590mm (3)
Type - PredefinedType: STANDARD; Material: ol. olev materjal 590 mm
Type - Pset_WallCommon - IsExternal: no
Type - AR_Sein - 001_Nimetus: ol. olev - 590mm; 505_Paksus: 590 mm
Pset_QuantityTakeOff - Reference: ol. olev - 590mm; sets with these values: 2
Pset_WallCommon - ExtendToStructure: no; LoadBearing: yes; Reference: ol. olev - 590mm
AR_Sein - 500_Kandev: yes; 003_Elemendi_staadium: Olemasolev
Name (Basic Wall:ol. olev - 590mm:...) | In | 605_Neto_pindala (m2)
869002 | 3. korrus | 10.53
882997 | 4. korrus | 9.68924
3377436 | 4. korrus | 9.56611

# IfcWall: Basic Wall:ol. olev - 600mm (4)
Type - PredefinedType: STANDARD; Material: ol. olev materjal 600 mm
Type - Pset_WallCommon - IsExternal: no
Type - AR_Sein - 001_Nimetus: ol. olev - 600mm; 505_Paksus: 600 mm
Pset_QuantityTakeOff - Reference: ol. olev - 600mm; sets with these values: 2
Pset_WallCommon - ExtendToStructure: no; Reference: ol. olev - 600mm
AR_Sein - 003_Elemendi_staadium: Olemasolev
Name (Basic Wall:ol. olev - 600mm:...) | In | LoadBearing = 500_Kandev | 605_Neto_pindala (m2)
1035309 | -2. korrus | yes | 28.7504
2372194 | -1. korrus | yes | 12.4155
4555413 | -1. korrus | no | 18.6074
5232531 | -2. korrus | no | 32.3187

# IfcWall: Basic Wall:ol. olev - 640mm, Basic Wall:ol. olev - 640mm:5600993
In: 2. korrus
Type - PredefinedType: STANDARD; Material: ol. olev materjal 640 mm
Type - Pset_WallCommon - IsExternal: no
Type - AR_Sein - 001_Nimetus: ol. olev - 640mm; 505_Paksus: 640 mm
Pset_QuantityTakeOff - Reference: ol. olev - 640mm; sets with these values: 2
Pset_WallCommon - ExtendToStructure: no; LoadBearing: no; Reference: ol. olev - 640mm
AR_Sein - 500_Kandev: no; 605_Neto_pindala: 0.0211059 m2

# IfcWall: Basic Wall:ol. olev - 700mm, Basic Wall:ol. olev - 700mm:779157
In: 1. korrus
Type - PredefinedType: STANDARD; Material: ol. olev materjal 700 mm
Type - Pset_WallCommon - IsExternal: no
Type - AR_Sein - 001_Nimetus: ol. olev - 700mm; 505_Paksus: 700 mm
Pset_QuantityTakeOff - Reference: ol. olev - 700mm; sets with these values: 2
Pset_WallCommon - Reference: ol. olev - 700mm; ExtendToStructure: no; LoadBearing: yes
AR_Sein - 003_Elemendi_staadium: Olemasolev; 500_Kandev: yes; 605_Neto_pindala: 34.8419 m2

# IfcWall: Basic Wall:ol. olev - 740mm, Basic Wall:ol. olev - 740mm:2358462
In: -1. korrus
Type - PredefinedType: STANDARD; Material: ol. olev materjal 740 mm
Type - Pset_WallCommon - IsExternal: no
Type - AR_Sein - 001_Nimetus: ol. olev - 740mm; 505_Paksus: 740 mm
Pset_QuantityTakeOff - Reference: ol. olev - 740mm; sets with these values: 2
Pset_WallCommon - ExtendToStructure: no; LoadBearing: yes; Reference: ol. olev - 740mm
AR_Sein - 500_Kandev: yes; 003_Elemendi_staadium: Olemasolev; 605_Neto_pindala: 83.5836 m2

# IfcWall: Basic Wall:ol. olev - 780mm (3)
Type - PredefinedType: STANDARD; Material: ol. olev materjal 780 mm
Type - Pset_WallCommon - IsExternal: no
Type - AR_Sein - 000_Muinsuskaitse: no; 001_Nimetus: ol. olev - 780mm; 205_Tüüp: Ol.ol; 505_Paksus: 780 mm
Pset_QuantityTakeOff - Reference: ol. olev - 780mm; sets with these values: 2
Pset_WallCommon - ExtendToStructure: no; Reference: ol. olev - 780mm
AR_Sein - 003_Elemendi_staadium: Olemasolev
Name (Basic Wall:ol. olev - 780mm:...) | In | LoadBearing = 500_Kandev | 605_Neto_pindala (m2)
782742 | 1. korrus | no | 22.0609
858173 | E-korpus 2. korrus | yes | 70.8763
1034675 | -2. korrus | yes | 209.201

# IfcWall: Parapeti müts 11:PR-02_8, Parapeti müts 11:PR-02_8:10885984
In: 4. korrus
Type - Material: EST. Metall. Teras. RAL9005
Type - Pset_ConcreteElementGeneral - FireRating: -
Type - Pset_WallCommon - ThermalTransmittance: 0 kg/K/s3; IsExternal: yes; AcousticRating: -; FireRating: -
Type - AR_Sein - 340_Soojusläbivus: 0; 335_Välispiire: yes; 001_Nimetus: PR-02_8; 205_Tüüp: PR-02; 325_Helipidavus: -; 330_Tulekindlus: -; 376_Viimistlus_väljast: Impregneeritakse läbipaistva Disboxan 451 ImprägnierCreme.
Pset_QuantityTakeOff - Reference: PR-02_8; sets with these values: 2
Pset_WallCommon - LoadBearing: no; Reference: PR-02_8
AR_Sein - 500_Kandev: no; 003_Elemendi_staadium: Projekteeritud; 605_Neto_pindala: 16.9751 m2

# IfcWall: Parapeti müts 12:PR-02_9, Parapeti müts 12:PR-02_9:10894394
In: 3. korrus
Type - Material: EST. Metall. Teras. RAL9005
Type - Pset_ConcreteElementGeneral - FireRating: -
Type - Pset_WallCommon - ThermalTransmittance: 0 kg/K/s3; IsExternal: yes; AcousticRating: -; FireRating: -
Type - AR_Sein - 340_Soojusläbivus: 0; 335_Välispiire: yes; 001_Nimetus: PR-02_9; 205_Tüüp: PR-02; 325_Helipidavus: -; 330_Tulekindlus: -; 376_Viimistlus_väljast: Impregneeritakse läbipaistva Disboxan 451 ImprägnierCreme.
Pset_QuantityTakeOff - Reference: PR-02_9; sets with these values: 2
Pset_WallCommon - LoadBearing: no; Reference: PR-02_9
AR_Sein - 500_Kandev: no; 003_Elemendi_staadium: Projekteeritud; 605_Neto_pindala: 16.8934 m2

# IfcWall: Parapeti müts 14:PR-02_11, Parapeti müts 14:PR-02_11:10893829
In: 4. korrus
Type - Material: EST. Metall. Teras. RAL9005
Type - Pset_ConcreteElementGeneral - FireRating: -
Type - Pset_WallCommon - ThermalTransmittance: 0 kg/K/s3; IsExternal: yes; AcousticRating: -; FireRating: -
Type - AR_Sein - 340_Soojusläbivus: 0; 335_Välispiire: yes; 001_Nimetus: PR-02_11; 205_Tüüp: PR-02; 325_Helipidavus: -; 330_Tulekindlus: -; 376_Viimistlus_väljast: Impregneeritakse läbipaistva Disboxan 451 ImprägnierCreme.
Pset_QuantityTakeOff - Reference: PR-02_11; sets with these values: 2
Pset_WallCommon - LoadBearing: no; Reference: PR-02_11
AR_Sein - 500_Kandev: no; 003_Elemendi_staadium: Projekteeritud; 605_Neto_pindala: 16.5899 m2

# IfcWall: Parapeti müts 15:PR-02_12, Parapeti müts 15:PR-02_12:10893919
In: 3. korrus
Type - Material: EST. Metall. Teras. RAL9005
Type - Pset_ConcreteElementGeneral - FireRating: -
Type - Pset_WallCommon - ThermalTransmittance: 0 kg/K/s3; IsExternal: yes; AcousticRating: -; FireRating: -
Type - AR_Sein - 340_Soojusläbivus: 0; 335_Välispiire: yes; 001_Nimetus: PR-02_12; 205_Tüüp: PR-02; 325_Helipidavus: -; 330_Tulekindlus: -; 376_Viimistlus_väljast: Impregneeritakse läbipaistva Disboxan 451 ImprägnierCreme.
Pset_QuantityTakeOff - Reference: PR-02_12; sets with these values: 2
Pset_WallCommon - LoadBearing: no; Reference: PR-02_12
AR_Sein - 500_Kandev: no; 003_Elemendi_staadium: Projekteeritud; 605_Neto_pindala: 16.6489 m2

# IfcWall: Parapeti müts 42:PR-06_3, Parapeti müts 42:PR-06_3:10959334
In: E-korpus 3. korrus
Type - Material: EST. ECOTERM
Type - Pset_ConcreteElementGeneral - FireRating: -
Type - Pset_WallCommon - ThermalTransmittance: 0 kg/K/s3; IsExternal: yes; AcousticRating: -; FireRating: -
Type - AR_Sein - 340_Soojusläbivus: 0; 335_Välispiire: yes; 001_Nimetus: PR-06_3; 205_Tüüp: PR-01; 325_Helipidavus: -; 330_Tulekindlus: -; 376_Viimistlus_väljast: Impregneeritakse läbipaistva Disboxan 451 ImprägnierCreme.
Pset_QuantityTakeOff - Reference: PR-06_3; sets with these values: 2
Pset_WallCommon - LoadBearing: no; Reference: PR-06_3
AR_Sein - 500_Kandev: no; 003_Elemendi_staadium: Projekteeritud; 605_Neto_pindala: 22.6229 m2

# IfcWall: Tugimüür 4:TM-01_4, Tugimüür 4:TM-01_4:13096863
In: E-korpus 3. korrus
Type - Material: EST. Metall. Teras. RAL9005
Type - Pset_ConcreteElementGeneral - FireRating: -
Type - Pset_WallCommon - ThermalTransmittance: 0 kg/K/s3; IsExternal: yes; AcousticRating: -; FireRating: -
Type - AR_Sein - 340_Soojusläbivus: 0; 335_Välispiire: yes; 001_Nimetus: TM-01_4; 205_Tüüp: TM-01; 325_Helipidavus: -; 330_Tulekindlus: -; 376_Viimistlus_väljast: Impregneeritakse läbipaistva Disboxan 451 ImprägnierCreme.
Pset_QuantityTakeOff - Reference: TM-01_4; sets with these values: 2
Pset_WallCommon - LoadBearing: no; Reference: TM-01_4
AR_Sein - 500_Kandev: no; 003_Elemendi_staadium: Projekteeritud; 605_Neto_pindala: 2.39334 m2

# IfcWall: Vents kalle:ol. olev vent kalle, Vents kalle:ol. olev vent kalle:4455827
In: -1. korrus
Type - Material: Default Wall
Type - Pset_WallCommon - IsExternal: no
Type - AR_Sein - 001_Nimetus: ol. olev vent kalle
Pset_QuantityTakeOff - Reference: ol. olev vent kalle; sets with these values: 2
Pset_WallCommon - LoadBearing: no; Reference: ol. olev vent kalle
AR_Sein - 500_Kandev: no; 003_Elemendi_staadium: Olemasolev; 605_Neto_pindala: 1.76957 m2

# IfcWallStandardCase: Basic Wall:SS-50.1 - 115 kergsein 38db ühepoolne (18)
Type - PredefinedType: STANDARD; Material: EST. Ehitusplaat. Kipsplaat 12.5 mm, EST. Ehitusplaat. OSB 12 mm, EST. Roov. Kipsplaadi alusroov.Mineraalvillaga. Vertikaalne 66 mm
Type - Pset_ConcreteElementGeneral - FireRating: -
Type - Pset_WallCommon - IsExternal: no; ThermalTransmittance: 0 kg/K/s3; AcousticRating: ≥38dB; FireRating: -
Type - AR_Sein - 000_Muinsuskaitse: no; 335_Välispiire: no; 340_Soojusläbivus: 0; 001_Nimetus: SS-50.1 - 115 kergsein 38db ühepoolne; 205_Tüüp: SS-50.1; 325_Helipidavus: ≥38dB; 330_Tulekindlus: -; 376_Viimistlus_väljast: -; 505_Paksus: 90.5 mm
BaseQuantities - Width: 90.5 mm
Pset_QuantityTakeOff - Reference: SS-50.1 - 115 kergsein 38db ühepoolne; sets with these values: 2
Pset_WallCommon - LoadBearing: no; Reference: SS-50.1 - 115 kergsein 38db ühepoolne
AR_Sein - 500_Kandev: no; 003_Elemendi_staadium: Projekteeritud
Name (Basic Wall:SS-50.1 - 115 kergsein 38db ühepoolne:...) | In | Height (mm) | Length (mm) | GrossFootprintArea (m2) | GrossVolume (m3) | GrossSideArea (m2) = NetSideArea (m2) = 605_Neto_pindala (m2) | NetVolume (m3) | ExtendToStructure
11977962 | 1. korrus | 2980 | 239.5 | 0.0216747 | 0.0645908 | 0.71371 | 0.0645908 | yes
11977963 | 1. korrus | 2980 | 400 | 0.0362 | 0.107876 | 1.192 | 0.107876 | yes
11977964 | 1. korrus | 2980 | 239.5 | 0.0216747 | 0.0645908 | 0.71371 | 0.0645908 | yes
12137236 | 2. korrus | 3000 | 320 | 0.02896 | 0.08688 | 0.96 | 0.08688 | no
12137256 | 2. korrus | 3000 | 309.5 | 0.0280097 | 0.0840292 | 0.9285 | 0.0840292 | no
12137275 | 2. korrus | 3000 | 229.5 | 0.0207697 | 0.0623092 | 0.6885 | 0.0623093 | no
12139013 | 3. korrus | 3000 | 490.5 | 0.0443902 | 0.133171 | 1.4715 | 0.133171 | no
12139035 | 3. korrus | 3220 | 309.5 | 0.0280097 | 0.0901914 | 0.99659 | 0.0901914 | yes
12139056 | 3. korrus | 3220 | 400 | 0.0362 | 0.116564 | 1.288 | 0.116564 | yes
13111883 | 3. korrus | 3000 | 290.5 | 0.0262903 | 0.0788708 | 0.8715 | 0.0788707 | no
13111905 | 3. korrus | 3000 | 309.5 | 0.0280097 | 0.0840292 | 0.9285 | 0.0840292 | no
13111926 | 3. korrus | 3000 | 200 | 0.0181 | 0.0543 | 0.6 | 0.0543 | no
15578237 | 3. korrus | 3000 | 390.5 | 0.0222177 | 0.0937489 | 1.0359 | 0.0937489 | no
15578238 | 3. korrus | 3000 | 309.5 | 0.0280097 | 0.0840292 | 0.9285 | 0.0840292 | no
15578239 | 3. korrus | 3000 | 300 | 0.02715 | 0.0691782 | 0.7644 | 0.0691782 | no
15578385 | 3. korrus | 3000 | 290.5 | 0.0262902 | 0.0788707 | 0.8715 | 0.0788707 | no
15578386 | 3. korrus | 3000 | 309.5 | 0.0280097 | 0.0840292 | 0.9285 | 0.0840292 | no
15578387 | 3. korrus | 3000 | 200 | 0.0181 | 0.0543 | 0.6 | 0.0543 | no

# IfcWallStandardCase: Basic Wall:SS-51 - 115 kergsein 38db niiskuskindlam (5)
In: 1. korrus
Type - PredefinedType: STANDARD; Material: Gypsum Wall Board 12.5 mm, EST. Ehitusplaat. OSB 12 mm, Default 66 mm, EST. Ehitusplaat. OSB 12 mm, Gypsum Wall Board 12.5 mm
Type - Pset_ConcreteElementGeneral - FireRating: EI-30
Type - Pset_WallCommon - IsExternal: no; ThermalTransmittance: 0 kg/K/s3; AcousticRating: ≥38dB; FireRating: EI-30
Type - AR_Sein - 000_Muinsuskaitse: no; 335_Välispiire: no; 340_Soojusläbivus: 0; 001_Nimetus: SS-51 - 115 kergsein 38db niiskuskindlam; 205_Tüüp: SS-51; 325_Helipidavus: ≥38dB; 330_Tulekindlus: EI-30; 376_Viimistlus_väljast: -; 505_Paksus: 115 mm
BaseQuantities - Height: 580 mm; Width: 115 mm
Pset_QuantityTakeOff - Reference: SS-51 - 115 kergsein 38db niiskuskindlam; sets with these values: 2
Pset_WallCommon - ExtendToStructure: no; LoadBearing: no; Reference: SS-51 - 115 kergsein 38db niiskuskindlam
AR_Sein - 500_Kandev: no; 003_Elemendi_staadium: Projekteeritud
Name (Basic Wall:SS-51 - 115 kergsein 38db niiskuskindlam:...) | Length (mm) | GrossFootprintArea (m2) | GrossVolume (m3) = NetVolume (m3) | GrossSideArea (m2) = NetSideArea (m2) = 605_Neto_pindala (m2)
12887327 | 5210 | 0.59915 | 0.347507 | 3.0218
12887344 | 3210 | 0.36915 | 0.214107 | 1.8618
12887345 | 6147.5 | 0.706963 | 0.410038 | 3.56555
12887346 | 5210 | 0.59915 | 0.347507 | 3.0218
12887348 | 5210 | 0.59915 | 0.347507 | 3.0218

# IfcWallStandardCase: Basic Wall:SS-52 - 145 kergsein 48db (19)
Type - PredefinedType: STANDARD; Material: EST. Ehitusplaat. Kipsplaat 12.5 mm, EST. Ehitusplaat. Kipsplaat 12.5 mm, EST. Roov. Kipsplaadi alusroov.Mineraalvillaga. Vertikaalne 95 mm, EST. Ehitusplaat. Kipsplaat 12.5 mm, EST. Ehitusplaat. Kipsplaat 12.5 mm
Type - Pset_ConcreteElementGeneral - FireRating: EI60
Type - Pset_WallCommon - IsExternal: no; ThermalTransmittance: 0 kg/K/s3; AcousticRating: ≥48dB; FireRating: EI60
Type - AR_Sein - 000_Muinsuskaitse: no; 335_Välispiire: no; 340_Soojusläbivus: 0; 001_Nimetus: SS-52 - 145 kergsein 48db; 205_Tüüp: SS-52; 325_Helipidavus: ≥48dB; 330_Tulekindlus: EI60; 376_Viimistlus_väljast: -; 505_Paksus: 145 mm
BaseQuantities - Width: 145 mm
Pset_QuantityTakeOff - Reference: SS-52 - 145 kergsein 48db; sets with these values: 2
Pset_WallCommon - ExtendToStructure: no; LoadBearing: no; Reference: SS-52 - 145 kergsein 48db
AR_Sein - 500_Kandev: no; 003_Elemendi_staadium: Projekteeritud
Name (Basic Wall:SS-52 - 145 kergsein 48db:...) | In | Height (mm) | Length (mm) | GrossFootprintArea (m2) | GrossVolume (m3) = NetVolume (m3) | GrossSideArea (m2) = NetSideArea (m2) | 605_Neto_pindala (m2)
6982904 | 1. korrus | 580 | 5730.5 | 0.830923 | 0.362108 | 2.4973 | 3.32369
6982905 | 1. korrus | 330 | 5380 | 0.7801 | 0.208635 | 1.43886 | 1.7754
10323827 | 2. korrus | 330 | 2380 | 0.3451 | 0.113883 | 0.7854 | 0.7854
10323828 | 2. korrus | 330 | 2520 | 0.3654 | 0.0756117 | 0.52146 | 0.8316
10323829 | 2. korrus | 330 | 5380 | 0.7801 | 0.208635 | 1.43886 | 1.7754
10323880 | 2. korrus | 300 | 2420 | 0.3509 | 0.10527 | 0.726 | 0.726
10323881 | 2. korrus | 300 | 2600 | 0.377 | 0.0687379 | 0.474054 | 0.78
10324146 | 2. korrus | 600 | 5675 | 0.822875 | 0.382816 | 2.64011 | 3.405
11605475 | 1. korrus | 2323.22 | 300 | 0.0435 | 0.100954 | 0.696233 | 0.696233
13285967 | 1. korrus | 330 | 2600 | 0.377 | 0.0756117 | 0.52146 | 0.858
13286006 | 1. korrus | 330 | 5370 | 0.77865 | 0.208635 | 1.43886 | 1.7721
13919498 | 1. korrus | 300 | 2420 | 0.3509 | 0.10527 | 0.726 | 0.726
13919539 | 1. korrus | 300 | 2570 | 0.37265 | 0.0687379 | 0.474054 | 0.771
16033010 | 1. korrus | 2400 | 150 | 0.02175 | 0.0522 | 0.36 | 0.36
16033257 | 1. korrus | 2400 | 150 | 0.02175 | 0.0522 | 0.36 | 0.36
16033471 | 1. korrus | 2400 | 150 | 0.02175 | 0.0522 | 0.36 | 0.36
16034141 | 2. korrus | 2400 | 150 | 0.02175 | 0.0522 | 0.36 | 0.36
16034779 | 2. korrus | 2400 | 150 | 0.02175 | 0.0522 | 0.36 | 0.36
16035197 | 2. korrus | 2400 | 150 | 0.02175 | 0.0522 | 0.36 | 0.36

# IfcWallStandardCase: Basic Wall:SS-53 - 170 kergsein 52db, Basic Wall:SS-53 - 170 kergsein 52db:6869704
In: 1. korrus
Type - PredefinedType: STANDARD; Material: EST. Ehitusplaat. Kipsplaat 12.5 mm, EST. Ehitusplaat. Kipsplaat 12.5 mm, EST. Roov. Kipsplaadi alusroov.Mineraalvillaga. Vertikaalne 120 mm, EST. Ehitusplaat. Kipsplaat 12.5 mm, EST. Ehitusplaat. Kipsplaat 12.5 mm
Type - Pset_ConcreteElementGeneral - FireRating: EI60
Type - Pset_WallCommon - IsExternal: no; ThermalTransmittance: 0 kg/K/s3; AcousticRating: ≥52dB; FireRating: EI60
Type - AR_Sein - 000_Muinsuskaitse: no; 335_Välispiire: no; 340_Soojusläbivus: 0; 001_Nimetus: SS-53 - 170 kergsein 52db; 205_Tüüp: SS-53; 325_Helipidavus: ≥52dB; 330_Tulekindlus: EI60; 376_Viimistlus_väljast: -; 505_Paksus: 170 mm
BaseQuantities - Height: 2730 mm; Length: 2410 mm; Width: 170 mm; GrossFootprintArea: 0.4097 m2; GrossVolume: 1.11848 m3; GrossSideArea: 6.5793 m2; NetSideArea: 6.5793 m2; NetVolume: 1.11848 m3
Pset_QuantityTakeOff - Reference: SS-53 - 170 kergsein 52db; sets with these values: 2
Pset_WallCommon - ExtendToStructure: no; LoadBearing: no; Reference: SS-53 - 170 kergsein 52db
AR_Sein - 500_Kandev: no; 003_Elemendi_staadium: Projekteeritud; 605_Neto_pindala: 6.5793 m2

# IfcWallStandardCase: Basic Wall:SS-57 - 80 kergsein wc (8)
Type - PredefinedType: STANDARD; Material: EST. Ehitusplaat. Kipsplaat 13 mm, EST. Õhkvahe. Roov. Kipsplaadi alusroov. Vertikaalne 67 mm
Type - Pset_ConcreteElementGeneral - FireRating: -
Type - Pset_WallCommon - IsExternal: no; ThermalTransmittance: 0 kg/K/s3; AcousticRating: -; FireRating: -
Type - AR_Sein - 000_Muinsuskaitse: no; 335_Välispiire: no; 340_Soojusläbivus: 0; 001_Nimetus: SS-57 - 80 kergsein wc; 205_Tüüp: SS-57; 325_Helipidavus: -; 330_Tulekindlus: -; 376_Viimistlus_väljast: -; 505_Paksus: 80 mm
BaseQuantities - Width: 80 mm
Pset_QuantityTakeOff - Reference: SS-57 - 80 kergsein wc; sets with these values: 2
Pset_WallCommon - LoadBearing: no; Reference: SS-57 - 80 kergsein wc
AR_Sein - 500_Kandev: no; 003_Elemendi_staadium: Projekteeritud
Name (Basic Wall:SS-57 - 80 kergsein wc:...) | In | Height (mm) | Length (mm) | GrossFootprintArea (m2) | GrossVolume (m3) = NetVolume (m3) | GrossSideArea (m2) = NetSideArea (m2) = 605_Neto_pindala (m2) | ExtendToStructure
8981988 | -1. korrus | 2980 | 1051.58 | 0.0841261 | 0.250696 | 3.1337 | yes
10746597 | 1. korrus | 2980 | 1100 | 0.088 | 0.26224 | 3.278 | no
10746598 | 1. korrus | 3300 | 1030 | 0.0824 | 0.27192 | 3.399 | no
12826790 | 3. korrus | 3000 | 380 | 0.0188 | 0.080352 | 1.0044 | no
12826791 | 3. korrus | 3000 | 320 | 0.0256 | 0.0768 | 0.96 | no
12826792 | 3. korrus | 3000 | 300 | 0.024 | 0.061152 | 0.7644 | no
16017371 | -1. korrus | 2980 | 240 | 0.0192 | 0.057216 | 0.7152 | no
16017398 | -1. korrus | 2980 | 270 | 0.0216 | 0.064368 | 0.8046 | no

# IfcWallStandardCase: Basic Wall:SS-70 - 100 poorbetoon (8)
Type - PredefinedType: STANDARD; Material: EST. Müüritis. Väikeplokk. Poorbetoonplokk 100 mm
Type - Pset_ConcreteElementGeneral - FireRating: EI90
Type - Pset_FireRatingProperties - SurfaceSpreadOfFlame: A1
Type - Pset_WallCommon - IsExternal: no; ThermalTransmittance: 0 kg/K/s3; AcousticRating: 36dB; FireRating: EI90; SurfaceSpreadOfFlame: A1
Type - AR_Sein - 000_Muinsuskaitse: no; 335_Välispiire: no; 340_Soojusläbivus: 0; 001_Nimetus: SS-70 - 100 poorbetoon; 205_Tüüp: SS-70; 325_Helipidavus: 36dB; 330_Tulekindlus: EI90; 376_Viimistlus_väljast: -; 505_Paksus: 100 mm
BaseQuantities - Height: 2980 mm; Width: 100 mm
Pset_QuantityTakeOff - Reference: SS-70 - 100 poorbetoon; sets with these values: 2
Pset_WallCommon - LoadBearing: no; Reference: SS-70 - 100 poorbetoon
AR_Sein - 500_Kandev: no; 003_Elemendi_staadium: Projekteeritud
Name (Basic Wall:SS-70 - 100 poorbetoon:...) | In | Length (mm) | GrossFootprintArea (m2) | GrossVolume (m3) = NetVolume (m3) | GrossSideArea (m2) = NetSideArea (m2) | ExtendToStructure | 605_Neto_pindala (m2)
4434790 | -1. korrus | 5715.17 | 0.571517 | 1.31578 | 13.1578 | yes | 17.0312
8981494 | -1. korrus | 2824.75 | 0.282475 | 0.673775 | 6.73775 | yes | 6.73775
8981521 | -1. korrus | 3195.44 | 0.319544 | 0.784241 | 7.84241 | yes | 7.84241
8981571 | -1. korrus | 2790.42 | 0.279042 | 0.4442 | 4.442 | yes | 6.63546
8981746 | -1. korrus | 2495.44 | 0.249544 | 0.743641 | 7.43641 | yes | 7.43641
8981804 | -1. korrus | 600 | 0.06 | 0.1788 | 1.788 | yes | 1.788
15366857 | 1. korrus | 2130 | 0.213 | 0.34074 | 3.4074 | no | 3.4074
15367308 | 1. korrus | 2130 | 0.213 | 0.63474 | 6.3474 | no | 6.3474

# IfcWallStandardCase: Basic Wall:SS-71 - 150 poorbetoon acoustic (6)
Type - PredefinedType: STANDARD; Material: EST. Müüritis. Väikeplokk. Betoon-õõnesplokk 150 mm
Type - Pset_ConcreteElementGeneral - FireRating: EI180
Type - Pset_FireRatingProperties - SurfaceSpreadOfFlame: A1
Type - Pset_WallCommon - IsExternal: no; ThermalTransmittance: 0 kg/K/s3; AcousticRating: 44dB; FireRating: EI180; SurfaceSpreadOfFlame: A1
Type - AR_Sein - 000_Muinsuskaitse: no; 335_Välispiire: no; 340_Soojusläbivus: 0; 001_Nimetus: SS-71 - 150 poorbetoon acoustic; 205_Tüüp: SS-71; 325_Helipidavus: 44dB; 330_Tulekindlus: EI180; 376_Viimistlus_väljast: -; 505_Paksus: 150 mm
BaseQuantities - Width: 150 mm
Pset_QuantityTakeOff - Reference: SS-71 - 150 poorbetoon acoustic; sets with these values: 2
Pset_WallCommon - ExtendToStructure: no; LoadBearing: no; Reference: SS-71 - 150 poorbetoon acoustic
AR_Sein - 500_Kandev: no; 003_Elemendi_staadium: Projekteeritud
Name (Basic Wall:SS-71 - 150 poorbetoon acoustic:...) | In | Height (mm) | Length (mm) | GrossFootprintArea (m2) | GrossVolume (m3) | GrossSideArea (m2) | NetSideArea (m2) | NetVolume (m3) | 605_Neto_pindala (m2)
8066044 | -1. korrus | 2980 | 5880.17 | 0.882026 | 2.04742 | 13.6495 | 13.6495 | 2.04742 | 17.5229
8761005 | -1. korrus | 2980 | 5880.17 | 0.882026 | 2.04742 | 13.6495 | 13.6495 | 2.04742 | 17.5229
13278286 | 1. korrus | 3590 | 5210 | 0.7815 | 1.50095 | 10.0063 | 10.0063 | 1.50095 | 10.0063
15367732 | 1. korrus | 2980 | 1540 | 0.231 | 0.68838 | 4.5892 | 4.5892 | 0.68838 | 4.5892
16590092 | 1. korrus | 3300 | 5550 | 0.8325 | 2.20284 | 14.6856 | 14.3256 | 2.14884 | 17.595
16590407 | 2. korrus | 3300 | 5800 | 0.87 | 2.20284 | 14.6856 | 14.6856 | 2.20284 | 19.14

# IfcWallStandardCase: Basic Wall:VS-01 - 165 sooj. mitte läbiv (11)
Type - PredefinedType: STANDARD; Material: EST. Ehitusplaat. Kipsplaat 14 mm, EST. Ehitusplaat. OSB 15 mm, EST. Õhkvahe. Roov. Kipsplaadi alusroov. Vertikaalne 66 mm, EST. Soojustus.PIR. Default 70 mm
Type - Pset_ConcreteElementGeneral - FireRating: REI180
Type - Pset_WallCommon - IsExternal: yes; AcousticRating: ≥65dB; FireRating: REI180; ThermalTransmittance: 0.22 kg/K/s3
Type - AR_Sein - 000_Muinsuskaitse: no; 335_Välispiire: yes; 001_Nimetus: VS-01 - 165 sooj. mitte läbiv; 205_Tüüp: VS-01; 325_Helipidavus: ≥65dB; 330_Tulekindlus: REI180; 340_Soojusläbivus: 0.22; 376_Viimistlus_väljast: -; 505_Paksus: 165 mm
BaseQuantities - Width: 165 mm
Pset_QuantityTakeOff - Reference: VS-01 - 165 sooj. mitte läbiv; sets with these values: 2
Pset_WallCommon - ExtendToStructure: no; LoadBearing: no; Reference: VS-01 - 165 sooj. mitte läbiv
AR_Sein - 500_Kandev: no; 003_Elemendi_staadium: Projekteeritud
Name (Basic Wall:VS-01 - 165 sooj. mitte läbiv:...) | In | Height (mm) | Length (mm) | GrossFootprintArea (m2) | GrossVolume (m3) | GrossSideArea (m2) | NetSideArea (m2) | NetVolume (m3) | 605_Neto_pindala (m2)
8165071 | -1. korrus | 2980 | 5250.38 | 0.866312 | 2.58161 | 15.6461 | 15.6461 | 2.58161 | 15.6461
8165114 | -1. korrus | 2980 | 8355.31 | 1.37863 | 4.10831 | 24.8988 | 24.1488 | 3.98456 | 24.1488
8165229 | -1. korrus | 2980 | 9244.69 | 1.52537 | 4.54561 | 27.5492 | 26.7992 | 4.42186 | 26.7992
8165281 | -1. korrus | 2980 | 3300 | 0.5445 | 1.62261 | 9.834 | 9.584 | 1.58136 | 9.584
8165335 | -1. korrus | 2980 | 4380 | 0.7227 | 2.15365 | 13.0524 | 12.5524 | 2.07115 | 12.5524
8165391 | -1. korrus | 2980 | 4004.07 | 0.660671 | 1.9688 | 11.9321 | 11.6821 | 1.92755 | 11.6821
8165441 | -1. korrus | 2980 | 5605.93 | 0.924979 | 2.75644 | 16.7057 | 16.2057 | 2.67394 | 16.2057
8165511 | -1. korrus | 2980 | 5320 | 0.8778 | 2.61584 | 15.8536 | 15.8536 | 2.61584 | 15.8536
8166061 | -1. korrus | 1200 | 7300 | 1.2045 | 1.4454 | 8.76 | 8.76 | 1.4454 | 8.76
8172788 | 1. korrus | 2980 | 4695.5 | 0.774758 | 2.1171 | 12.8309 | 12.8309 | 2.1171 | 13.9926
8228331 | 2. korrus | 3000 | 5020 | 0.8283 | 2.15111 | 13.037 | 13.037 | 2.15111 | 15.06

# IfcWallStandardCase: Basic Wall:VS-02 - 125 sooj. läbiv (3)
Type - PredefinedType: STANDARD; Material: EST. Ehitusplaat. Kipsplaat 15 mm, EST. Ehitusplaat. OSB 15 mm, EST. Õhkvahe. Roov. Kipsplaadi alusroov.Puit. Vertikaalne 25 mm, EST. Soojustus.PIR. Default 70 mm
Type - Pset_ConcreteElementGeneral - FireRating: REI180
Type - Pset_WallCommon - IsExternal: yes; AcousticRating: ≥65dB; FireRating: REI180; ThermalTransmittance: 0.36 kg/K/s3
Type - AR_Sein - 000_Muinsuskaitse: no; 335_Välispiire: yes; 001_Nimetus: VS-02 - 125 sooj. läbiv; 205_Tüüp: VS-02; 325_Helipidavus: ≥65dB; 330_Tulekindlus: REI180; 340_Soojusläbivus: 0.36; 376_Viimistlus_väljast: -; 505_Paksus: 125 mm
BaseQuantities - Width: 125 mm
Pset_QuantityTakeOff - Reference: VS-02 - 125 sooj. läbiv; sets with these values: 2
Pset_WallCommon - ExtendToStructure: no; LoadBearing: no; Reference: VS-02 - 125 sooj. läbiv
AR_Sein - 500_Kandev: no; 003_Elemendi_staadium: Projekteeritud
Name (Basic Wall:VS-02 - 125 sooj. läbiv:...) | In | Height (mm) | Length (mm) | GrossFootprintArea (m2) | GrossVolume (m3) = NetVolume (m3) | GrossSideArea (m2) = NetSideArea (m2) | 605_Neto_pindala (m2)
8233346 | 3. korrus | 3046.52 | 925.5 | 0.115688 | 0.352444 | 2.81956 | 2.81956
8233385 | 3. korrus | 3000 | 5545 | 0.693125 | 0.686318 | 5.49054 | 16.635
8237346 | 4. korrus | 3027.51 | 1065.5 | 0.133187 | 0.0854066 | 0.683253 | 3.22581

# IfcWallStandardCase: Basic Wall:VS-03.1 - soojustus (48)
Type - PredefinedType: STANDARD; Material: EST. Soojustus.PIR_Powerwall Pro 30 mm, EST. Metall. Alumiinium. Mütsprofiil. 42 mm, EST. Ehitusplaat. Kipsplaat 12.5 mm
Type - Pset_ConcreteElementGeneral - FireRating: REI180
Type - Pset_WallCommon - IsExternal: yes; AcousticRating: ≥55dB; FireRating: REI180; ThermalTransmittance: 0.34 kg/K/s3
Type - AR_Sein - 000_Muinsuskaitse: no; 335_Välispiire: yes; 001_Nimetus: VS-03.1 - soojustus; 205_Tüüp: VS-03.1; 325_Helipidavus: ≥55dB; 330_Tulekindlus: REI180; 340_Soojusläbivus: 0.34; 376_Viimistlus_väljast: -; 505_Paksus: 84.5 mm
BaseQuantities - Width: 84.5 mm
Pset_QuantityTakeOff - Reference: VS-03.1 - soojustus; sets with these values: 2
Pset_WallCommon - LoadBearing: no; Reference: VS-03.1 - soojustus
AR_Sein - 003_Elemendi_staadium: Projekteeritud
Name (Basic Wall:VS-03.1 - soojustus:...) | In | Height (mm) | Length (mm) | GrossFootprintArea (m2) | GrossVolume (m3) | GrossSideArea (m2) = NetSideArea (m2) | NetVolume (m3) | ExtendToStructure | 500_Kandev | 605_Neto_pindala (m2)
8172023 | 1. korrus | 2980 | 1630 | 0.137735 | 0.254374 | 3.01034 | 0.254374 | no | no | 4.8574
8228599 | 2. korrus | 3000 | 2100 | 0.17745 | 0.53235 | 6.3 | 0.53235 | no | no | 6.3
8228661 | 2. korrus | 3000 | 2760 | 0.23322 | 0.69966 | 8.28 | 0.69966 | no | no | 8.28
8232643 | 3. korrus | 3000 | 2960 | 0.25012 | 0.451276 | 5.34054 | 0.451276 | no | no | 8.82228
8232846 | 3. korrus | 3000 | 2475.5 | 0.20918 | 0.382658 | 4.5285 | 0.382658 | no | no | 4.5285
8233196 | 3. korrus | 1772.44 | 1010 | 0.085345 | 0.151269 | 1.79016 | 0.149394 | yes | no | 1.79016
8236908 | 4. korrus | 2960 | 1240 | 0.10478 | 0.0775826 | 0.918137 | 0.0775826 | no | no | 3.6704
8236936 | 4. korrus | 3000 | 2515.5 | 0.21256 | 0.637679 | 7.5465 | 0.637679 | yes | no | 7.5465
8236958 | 4. korrus | 2288.22 | 1155.5 | 0.0976398 | 0.0436366 | 0.516409 | 0.0432143 | yes | no | 2.68675
8237097 | 4. korrus | 3000 | 916.773 | 0.0774673 | 0.232402 | 2.75032 | 0.232402 | no | no | 2.75032
8237119 | 4. korrus | 1644.43 | 1065.5 | 0.0900347 | 0.0313594 | 0.371118 | 0.0309362 | yes | no | 1.75214
8237238 | 4. korrus | 3000 | 2600 | 0.2197 | 0.6591 | 7.8 | 0.6591 | no | no | 7.8
8750834 | -1. korrus | 2980 | 5455.17 | 0.460962 | 1.11183 | 13.1578 | 1.11183 | yes | no | 16.2564
10392931 | 3. korrus | 3000 | 2860 | 0.24167 | 0.644311 | 7.62499 | 0.644311 | no | no | 7.62499
10395262 | 3. korrus | 3000 | 2630 | 0.222235 | 0.391659 | 4.63501 | 0.391659 | no | no | 4.63501
11112170 | 2. korrus | 3000 | 5344.75 | 0.451631 | 1.11291 | 13.1705 | 1.11291 | no | no | 16.0343
11994837 | 3. korrus | 2417.72 | 1150 | 0.097175 | 0.234942 | 2.78038 | 0.232779 | yes | no | 2.78038
11994838 | 3. korrus | 3037.12 | 2175.5 | 0.18383 | 0.533078 | 6.30861 | 0.533078 | no | no | 6.30861
11994840 | 3. korrus | 3037.12 | 1065.5 | 0.0900347 | 0.273446 | 3.23605 | 0.273446 | no | no | 3.23605
15532151 | 2. korrus | 800 | 5200 | 0.4394 | 0.35152 | 4.16 | 0.35152 | no | no | 4.16
15532420 | 2. korrus | 800 | 35.5 | 0.00299975 | 0.0057122 | 0.0676 | 0.0023998 | no | no | 0.0284
15532486 | 2. korrus | 800 | 35.5 | 0.00299975 | 0.0057122 | 0.0676 | 0.0023998 | no | no | 0.0284
15532766 | 2. korrus | 800 | 2550 | 0.215475 | 0.17238 | 2.04 | 0.17238 | no | no | 2.04
15532767 | 2. korrus | 800 | 120 | 0.01014 | 0.008112 | 0.096 | 0.008112 | no | no | 0.096
15532768 | 2. korrus | 800 | 35.5 | 0.00299975 | 0.0057122 | 0.0676 | 0.0023998 | no | no | 0.0284
15532780 | 2. korrus | 800 | 5200 | 0.4394 | 0.35152 | 4.16 | 0.35152 | no | no | 4.16
15532781 | 2. korrus | 800 | 35.5 | 0.00299975 | 0.0057122 | 0.0676 | 0.0023998 | no | no | 0.0284
15532782 | 2. korrus | 800 | 35.5 | 0.00299975 | 0.0057122 | 0.0676 | 0.0023998 | no | no | 0.0284
15533522 | 2. korrus | 800 | 2650 | 0.223925 | 0.17914 | 2.12 | 0.17914 | no | no | 2.12
15534064 | 2. korrus | 800 | 5200 | 0.4394 | 0.35152 | 4.16 | 0.35152 | no | no | 4.16
15534065 | 2. korrus | 800 | 35.0129 | 0.00295859 | 0.0057122 | 0.0676 | 0.00236688 | no | no | 0.0280104
15534066 | 2. korrus | 800 | 98.4877 | 0.00832221 | 0.00665777 | 0.0787902 | 0.00665777 | no | no | 0.0787902
15534230 | 2. korrus | 800 | 5198 | 0.439231 | 0.351385 | 4.1584 | 0.351385 | no | no | 4.1584
15534371 | 2. korrus | 800 | 117.75 | 0.00994987 | 0.0079599 | 0.0942 | 0.0079599 | no | no | 0.0942
15534713 | 2. korrus | 800 | 119.513 | 0.0100988 | 0.00807908 | 0.0956104 | 0.00807908 | no | no | 0.0956104
15534938 | 2. korrus | 800 | 5200 | 0.4394 | 0.35152 | 4.16 | 0.35152 | no | no | 4.16
15534939 | 2. korrus | 800 | 119.513 | 0.0100988 | 0.00807908 | 0.0956104 | 0.00807908 | no | no | 0.0956104
15534940 | 2. korrus | 800 | 119.513 | 0.0100988 | 0.00807908 | 0.0956104 | 0.00807908 | no | no | 0.0956104
15991586 | 1. korrus | 320 | 5121 | 0.432724 | 0.138472 | 1.63872 | 0.138472 | no | no | 1.63872
15991987 | 1. korrus | 320 | 5121 | 0.432724 | 0.138472 | 1.63872 | 0.138472 | no | no | 1.63872
15992038 | 1. korrus | 320 | 5121 | 0.432724 | 0.138472 | 1.63872 | 0.138472 | no | no | 1.63872
15992087 | 1. korrus | 320 | 5121 | 0.432724 | 0.138472 | 1.63872 | 0.138472 | no | no | 1.63872
15992194 | 1. korrus | 320 | 5121 | 0.432724 | 0.138472 | 1.63872 | 0.138472 | no | no | 1.63872
15992250 | 1. korrus | 320 | 5121 | 0.432724 | 0.138472 | 1.63872 | 0.138472 | no | no | 1.63872
16447897 | 1. korrus | 2980 | 5020.5 | 0.424232 | 1.08421 | 12.8309 | 1.08421 | no |  | 14.9611
16874548 | 3. korrus | 2100 | 330 | 0.027885 | 0.0585585 | 0.693 | 0.0585585 | no |  | 0.693
16874550 | 3. korrus | 2100 | 195.5 | 0.0165197 | 0.0346915 | 0.41055 | 0.0346915 | no |  | 0.41055
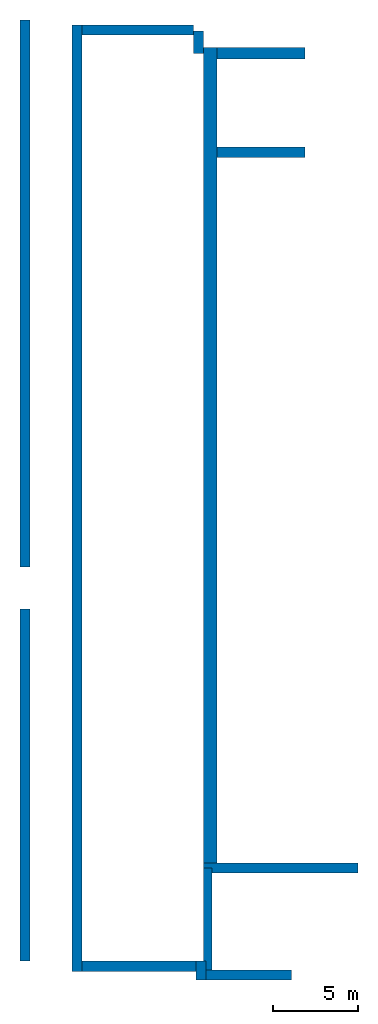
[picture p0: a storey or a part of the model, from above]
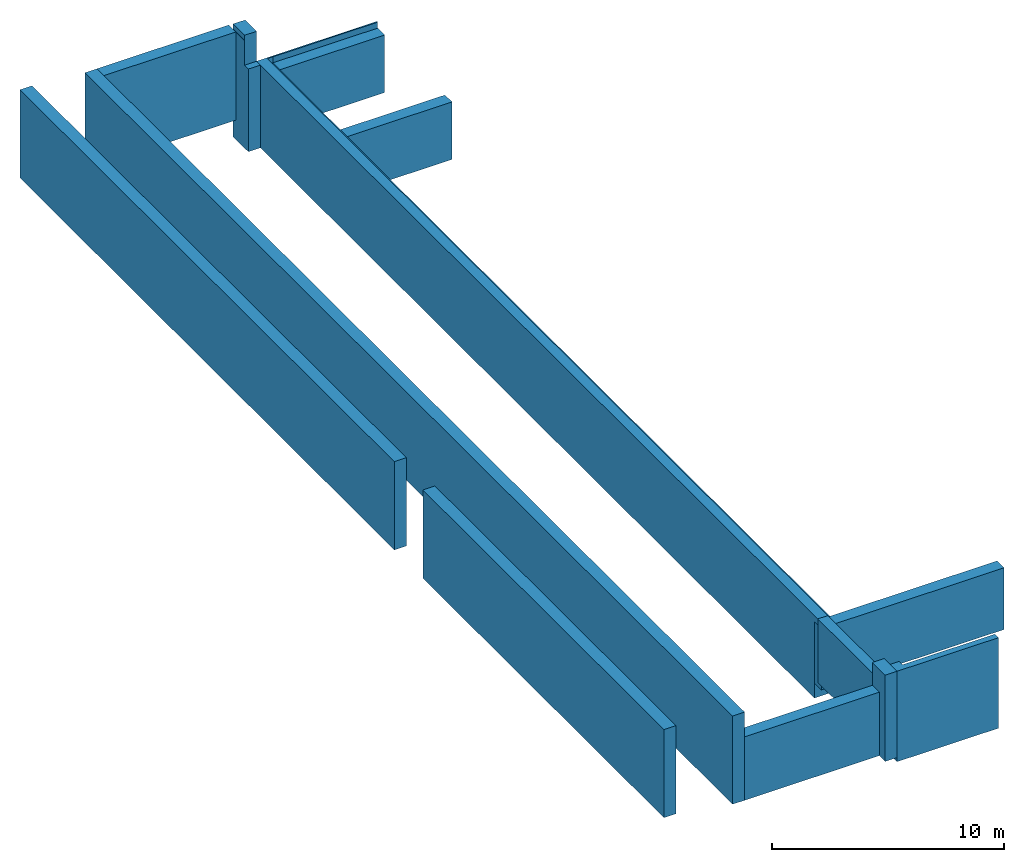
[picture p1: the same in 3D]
Properties of the parts of a building model (IFC2X3), part 7 of 7

# IfcWallStandardCase: Basic Wall:VS-03.1 - soojustus (48)
Name (Basic Wall:VS-03.1 - soojustus:...) | In | Height (mm) | Length (mm) | GrossFootprintArea (m2) | GrossVolume (m3) | GrossSideArea (m2) = NetSideArea (m2) | NetVolume (m3) | ExtendToStructure | 500_Kandev | 605_Neto_pindala (m2)
16874552 | 3. korrus | 2100 | 280 | 0.02366 | 0.049686 | 0.588 | 0.049686 | no |  | 0.588

# IfcWallStandardCase: Basic Wall:VS-03.1_karkass+kips (12)
In: 1. korrus
Type - PredefinedType: STANDARD; Material: EST. Metall. Alumiinium. Mütsprofiil. 27 mm, EST. Ehitusplaat. Kipsplaat 12.5 mm
Type - Pset_ConcreteElementGeneral - FireRating: REI180
Type - Pset_WallCommon - IsExternal: yes; AcousticRating: ≥55dB; FireRating: REI180; ThermalTransmittance: 0.34 kg/K/s3
Type - AR_Sein - 000_Muinsuskaitse: no; 335_Välispiire: yes; 001_Nimetus: VS-03.1_karkass+kips; 205_Tüüp: VS-03.1; 325_Helipidavus: ≥55dB; 330_Tulekindlus: REI180; 340_Soojusläbivus: 0.34; 376_Viimistlus_väljast: -; 505_Paksus: 39.5 mm
BaseQuantities - Height: 1670 mm; Length: 489.5 mm; Width: 39.5 mm; GrossFootprintArea: 0.0193352 m2; GrossVolume: 0.0322899 m3; GrossSideArea: 0.817465 m2; NetSideArea: 0.817465 m2; NetVolume: 0.0322899 m3
Pset_QuantityTakeOff - Reference: VS-03.1_karkass+kips; sets with these values: 2
Pset_WallCommon - ExtendToStructure: no; LoadBearing: no; Reference: VS-03.1_karkass+kips
AR_Sein - 500_Kandev: no; 003_Elemendi_staadium: Projekteeritud; 605_Neto_pindala: 0.817465 m2
Name (Basic Wall:VS-03.1_karkass+kips:...)
15991138
15991444
15991985
15991986
15992036
15992037
15992085
15992086
15992192
15992193
15992248
15992249

# IfcWallStandardCase: Basic Wall:VS-13.1 - 300 poorbetoon + EPS, Basic Wall:VS-13.1 - 300 poorbetoon + EPS:13038453
In: -1. korrus
Type - PredefinedType: STANDARD; Material: EST. Soojustus. EPS 150 mm, EST. Müüritis. Väikeplokk. Poorbetoonplokk 150 mm
Type - Pset_ConcreteElementGeneral - FireRating: REI120
Type - Pset_ReinforcementBarPitchOfWall - Description: Õhuvõtukambri sein -1. korrusel
Type - Pset_WallCommon - IsExternal: yes; AcousticRating: ≥40dB; FireRating: REI120; ThermalTransmittance: 0.2 kg/K/s3
Type - AR_Sein - 000_Muinsuskaitse: no; 335_Välispiire: yes; 001_Nimetus: VS-13.1 - 300 poorbetoon + EPS; 205_Tüüp: VS-13.1; 325_Helipidavus: ≥40dB; 330_Tulekindlus: REI120; 340_Soojusläbivus: 0.2; 376_Viimistlus_väljast: -; 505_Paksus: 300 mm
BaseQuantities - Height: 2980 mm; Length: 5600 mm; Width: 300 mm; GrossFootprintArea: 1.68 m2; GrossVolume: 5.0064 m3; GrossSideArea: 16.688 m2; NetSideArea: 16.208 m2; NetVolume: 4.8624 m3
Pset_QuantityTakeOff - Reference: VS-13.1 - 300 poorbetoon + EPS; sets with these values: 2
Pset_WallCommon - LoadBearing: no; ExtendToStructure: yes; Reference: VS-13.1 - 300 poorbetoon + EPS
AR_Sein - 500_Kandev: no; 003_Elemendi_staadium: Projekteeritud; 605_Neto_pindala: 16.208 m2

# IfcWallStandardCase: Basic Wall:VS-22 - 340 akende all, Basic Wall:VS-22 - 340 akende all:10344990
In: 3. korrus
Type - PredefinedType: STANDARD; Material: EST. Metall. Alumiinium. Fassaadikate. Värvitud. RAL0000 5 mm, EST. Õhkvahe. Roov. Fassaadikatte alusroov. Horisontaalne 40 mm, EST. Müüritis. Väikeplokk. bauroc UNIVERSAL 300 mm
Type - Pset_ConcreteElementGeneral - FireRating: REI120
Type - Pset_WallCommon - IsExternal: yes; AcousticRating: ≥40dB; FireRating: REI120; ThermalTransmittance: 0.26 kg/K/s3
Type - AR_Sein - 000_Muinsuskaitse: no; 335_Välispiire: yes; 001_Nimetus: VS-22 - 340 akende all; 205_Tüüp: VS-22; 325_Helipidavus: ≥40dB; 330_Tulekindlus: REI120; 340_Soojusläbivus: 0.26; 376_Viimistlus_väljast: -; 505_Paksus: 345 mm
BaseQuantities - Height: 1515.38 mm; Length: 30400 mm; Width: 345 mm; GrossFootprintArea: 10.488 m2; GrossVolume: 6.45293 m3; GrossSideArea: 18.7042 m2; NetSideArea: 18.7042 m2; NetVolume: 5.98992 m3
Pset_QuantityTakeOff - Reference: VS-22 - 340 akende all; sets with these values: 2
Pset_WallCommon - ExtendToStructure: no; LoadBearing: no; Reference: VS-22 - 340 akende all
AR_Sein - 500_Kandev: no; 003_Elemendi_staadium: Projekteeritud; 605_Neto_pindala: 18.7042 m2

# IfcWallStandardCase: Basic Wall:ol. olev - 120mm, Basic Wall:ol. olev - 120mm:1030389
In: -1. korrus
Type - PredefinedType: STANDARD; Material: ol. olev materjal 120 mm
Type - Pset_WallCommon - IsExternal: no
Type - AR_Sein - 001_Nimetus: ol. olev - 120mm; 505_Paksus: 120 mm
BaseQuantities - Height: 2750 mm; Length: 2600 mm; Width: 120 mm; GrossFootprintArea: 0.312 m2; GrossVolume: 0.52146 m3; GrossSideArea: 4.3455 m2; NetSideArea: 4.3455 m2; NetVolume: 0.52146 m3
Pset_QuantityTakeOff - Reference: ol. olev - 120mm; sets with these values: 2
Pset_WallCommon - LoadBearing: no; ExtendToStructure: yes; Reference: ol. olev - 120mm
AR_Sein - 500_Kandev: no; 003_Elemendi_staadium: Olemasolev; 605_Neto_pindala: 7.15 m2

# IfcWallStandardCase: Basic Wall:ol. olev - 160mm (3)
Type - PredefinedType: STANDARD; Material: ol. olev materjal 160 mm
Type - Pset_WallCommon - IsExternal: no
Type - AR_Sein - 001_Nimetus: ol. olev - 160mm; 505_Paksus: 160 mm
BaseQuantities - Width: 160 mm
Pset_QuantityTakeOff - Reference: ol. olev - 160mm; sets with these values: 2
Pset_WallCommon - LoadBearing: no; Reference: ol. olev - 160mm
AR_Sein - 003_Elemendi_staadium: Olemasolev
Name (Basic Wall:ol. olev - 160mm:...) | In | Height (mm) | Length (mm) | GrossFootprintArea (m2) | GrossVolume (m3) = NetVolume (m3) | GrossSideArea (m2) = NetSideArea (m2) | ExtendToStructure | 500_Kandev | 605_Neto_pindala (m2)
862491 | 2. korrus | 2730 | 5470 | 0.8752 | 1.94384 | 12.149 | yes | no | 14.9331
1014130 | -1. korrus | 2985 | 2600.17 | 0.416028 | 1.24184 | 7.76152 | no | no | 7.76152
10387094 | 3. korrus | 400 | 29600 | 4.736 | 1.85696 | 11.606 | no |  | 11.606

# IfcWallStandardCase: Basic Wall:ol. olev - 200mm (7)
Type - PredefinedType: STANDARD; Material: ol. olev materjal 200 mm
Type - Pset_ConcreteElementGeneral - FireRating: -
Type - Pset_WallCommon - IsExternal: no; AcousticRating: -; FireRating: -; ThermalTransmittance: 0 kg/K/s3
Type - AR_Sein - 001_Nimetus: ol. olev - 200mm; 205_Tüüp: -; 325_Helipidavus: -; 330_Tulekindlus: -; 335_Välispiire: no; 340_Soojusläbivus: 0; 376_Viimistlus_väljast: -; 505_Paksus: 200 mm
BaseQuantities - Width: 200 mm
Pset_QuantityTakeOff - Reference: ol. olev - 200mm; sets with these values: 2
Pset_WallCommon - Reference: ol. olev - 200mm
AR_Sein - 003_Elemendi_staadium: Olemasolev
Name (Basic Wall:ol. olev - 200mm:...) | In | Height (mm) | Length (mm) | GrossFootprintArea (m2) | GrossVolume (m3) | GrossSideArea (m2) = NetSideArea (m2) | NetVolume (m3) | LoadBearing = 500_Kandev | ExtendToStructure | 605_Neto_pindala (m2)
828432 | 1. korrus | 2980 | 5550 | 1.11 | 2.65231 | 13.2615 | 2.65231 | no | yes | 16.539
836157 | 2. korrus | 3000 | 5800 | 1.158 | 2.67011 | 13.3505 | 2.67011 | yes | yes | 17.4
869770 | 3. korrus | 3000 | 1160 | 0.232 | 0.36 | 1.8 | 0.36 | no | no | 1.8
884964 | 4. korrus | 2243.94 | 1150 | 0.23 | 0.139206 | 0.696028 | 0.135955 | no | yes | 2.58053
6282243 | -1. korrus | 1415 | 929.795 | 0.185959 | 0.23946 | 1.1973 | 0.23946 | no | no | 1.31566
6282244 | -1. korrus | 1415 | 930 | 0.186 | 0.26319 | 1.31595 | 0.26319 | no | no | 1.31595
6282245 | -1. korrus | 1415 | 929.795 | 0.185959 | 0.18286 | 0.914302 | 0.18286 | no | no | 1.31566

# IfcWallStandardCase: Basic Wall:ol. olev - 250mm, Basic Wall:ol. olev - 250mm:827887
In: 1. korrus
Type - PredefinedType: STANDARD; Material: ol. olev materjal 250 mm
Type - Pset_WallCommon - IsExternal: no
Type - AR_Sein - 001_Nimetus: ol. olev - 250mm; 505_Paksus: 250 mm
BaseQuantities - Height: 2730 mm; Length: 5550 mm; Width: 250 mm; GrossFootprintArea: 1.38 m2; GrossVolume: 2.61537 m3; GrossSideArea: 10.4615 m2; NetSideArea: 10.4615 m2; NetVolume: 2.5949 m3
Pset_QuantityTakeOff - Reference: ol. olev - 250mm; sets with these values: 2
Pset_WallCommon - ExtendToStructure: no; LoadBearing: no; Reference: ol. olev - 250mm
AR_Sein - 500_Kandev: no; 003_Elemendi_staadium: Olemasolev; 605_Neto_pindala: 13.464 m2

# IfcWallStandardCase: Basic Wall:ol. olev - 290mm, Basic Wall:ol. olev - 290mm:828109
In: 1. korrus
Type - PredefinedType: STANDARD; Material: ol. olev materjal 290 mm
Type - Pset_WallCommon - IsExternal: no
Type - AR_Sein - 001_Nimetus: ol. olev - 290mm; 505_Paksus: 290 mm
BaseQuantities - Height: 2730 mm; Length: 5400 mm; Width: 290 mm; GrossFootprintArea: 1.566 m2; GrossVolume: 3.47571 m3; GrossSideArea: 11.9852 m2; NetSideArea: 11.9852 m2; NetVolume: 3.47571 m3
Pset_QuantityTakeOff - Reference: ol. olev - 290mm; sets with these values: 2
Pset_WallCommon - ExtendToStructure: no; LoadBearing: yes; Reference: ol. olev - 290mm
AR_Sein - 500_Kandev: yes; 003_Elemendi_staadium: Olemasolev; 605_Neto_pindala: 14.742 m2

# IfcWallStandardCase: Basic Wall:ol. olev - 300mm (3)
In: 3. korrus
Type - PredefinedType: STANDARD; Material: ol. olev materjal 300 mm
Type - Pset_WallCommon - IsExternal: no
Type - AR_Sein - 001_Nimetus: ol. olev - 300mm; 505_Paksus: 300 mm
BaseQuantities - Width: 300 mm
Pset_QuantityTakeOff - Reference: ol. olev - 300mm; sets with these values: 2
Pset_WallCommon - LoadBearing: no; ExtendToStructure: yes; Reference: ol. olev - 300mm
AR_Sein - 500_Kandev: no; 003_Elemendi_staadium: Olemasolev
Name (Basic Wall:ol. olev - 300mm:...) | Height (mm) | Length (mm) | GrossFootprintArea (m2) | GrossVolume (m3) | GrossSideArea (m2) | NetSideArea (m2) = 605_Neto_pindala (m2) | NetVolume (m3)
871451 | 2279.7 | 1010 | 0.303 | 0.690749 | 2.3025 | 1.6599 | 0.474335
1488976 | 2373.21 | 1150 | 0.345 | 0.818759 | 2.7292 | 2.7292 | 0.791504
1759692 | 1728.5 | 1010 | 0.303 | 0.523735 | 1.74578 | 1.74578 | 0.500101

# IfcWallStandardCase: Basic Wall:ol. olev - 330mm, Basic Wall:ol. olev - 330mm:869698
In: 3. korrus
Type - PredefinedType: STANDARD; Material: ol. olev materjal 330 mm
Type - Pset_WallCommon - IsExternal: no
Type - AR_Sein - 001_Nimetus: ol. olev - 330mm; 505_Paksus: 330 mm
BaseQuantities - Height: 3000 mm; Length: 630 mm; Width: 330 mm; GrossFootprintArea: 0.2079 m2; GrossVolume: 0.6237 m3; GrossSideArea: 1.89 m2; NetSideArea: 1.89 m2; NetVolume: 0.6237 m3
Pset_QuantityTakeOff - Reference: ol. olev - 330mm; sets with these values: 2
Pset_WallCommon - ExtendToStructure: no; LoadBearing: no; Reference: ol. olev - 330mm
AR_Sein - 500_Kandev: no; 003_Elemendi_staadium: Olemasolev; 605_Neto_pindala: 1.89 m2

# IfcWallStandardCase: Basic Wall:ol. olev - 360mm (3)
Type - PredefinedType: STANDARD; Material: ol. olev materjal 360 mm
Type - Pset_WallCommon - IsExternal: no
Type - AR_Sein - 001_Nimetus: ol. olev - 360mm; 505_Paksus: 360 mm
BaseQuantities - Width: 360 mm
Pset_QuantityTakeOff - Reference: ol. olev - 360mm; sets with these values: 2
Pset_WallCommon - ExtendToStructure: no; LoadBearing: yes; Reference: ol. olev - 360mm
AR_Sein - 500_Kandev: yes; 003_Elemendi_staadium: Olemasolev
Name (Basic Wall:ol. olev - 360mm:...) | In | Height (mm) | Length (mm) | GrossFootprintArea (m2) | GrossVolume (m3) = NetVolume (m3) | GrossSideArea (m2) = NetSideArea (m2) = 605_Neto_pindala (m2)
869090 | 3. korrus | 3510 | 7874.65 | 2.83487 | 5.17869 | 14.3852
883196 | 4. korrus | 3480 | 8057.46 | 2.90069 | 5.82289 | 16.1747
883294 | 4. korrus | 3480 | 7525.19 | 2.70907 | 5.74607 | 15.9613

# IfcWallStandardCase: Basic Wall:ol. olev - 380mm, Basic Wall:ol. olev - 380mm:2355096
In: 1. korrus
Type - PredefinedType: STANDARD; Material: ol. olev materjal 380 mm
Type - Pset_WallCommon - IsExternal: no
Type - AR_Sein - 001_Nimetus: ol. olev - 380mm; 505_Paksus: 380 mm
BaseQuantities - Height: 2980 mm; Length: 1570 mm; Width: 380 mm; GrossFootprintArea: 0.5966 m2; GrossVolume: 0.477452 m3; GrossSideArea: 1.25645 m2; NetSideArea: 1.25645 m2; NetVolume: 0.477452 m3
Pset_QuantityTakeOff - Reference: ol. olev - 380mm; sets with these values: 2
Pset_WallCommon - ExtendToStructure: no; LoadBearing: no; Reference: ol. olev - 380mm
AR_Sein - 500_Kandev: no; 003_Elemendi_staadium: Olemasolev; 605_Neto_pindala: 4.6786 m2

# IfcWallStandardCase: Basic Wall:ol. olev - 400mm (3)
Type - PredefinedType: STANDARD; Material: ol. olev materjal 400 mm
Type - Pset_WallCommon - IsExternal: no
Type - AR_Sein - 001_Nimetus: ol. olev - 400mm; 505_Paksus: 400 mm
BaseQuantities - Width: 400 mm
Pset_QuantityTakeOff - Reference: ol. olev - 400mm; sets with these values: 2
Pset_WallCommon - ExtendToStructure: no; LoadBearing: no; Reference: ol. olev - 400mm
AR_Sein - 500_Kandev: no; 003_Elemendi_staadium: Olemasolev
Name (Basic Wall:ol. olev - 400mm:...) | In | Height (mm) | Length (mm) | GrossFootprintArea (m2) | GrossVolume (m3) | GrossSideArea (m2) = NetSideArea (m2) | NetVolume (m3) | 605_Neto_pindala (m2)
865091 | 3. korrus | 1239.41 | 6560 | 2.624 | 2.85569 | 7.13923 | 2.85197 | 8.13054
1014418 | -1. korrus | 2985 | 5880.17 | 2.35207 | 5.46894 | 13.6724 | 5.46894 | 17.5523
1014508 | -1. korrus | 2980 | 5880.17 | 2.35207 | 5.45978 | 13.6495 | 5.45978 | 17.5229

# IfcWallStandardCase: Basic Wall:ol. olev - 420mm, Basic Wall:ol. olev - 420mm:1227294
In: E-korpus 2. korrus
Type - PredefinedType: STANDARD; Material: ol. olev materjal 420 mm
Type - Pset_WallCommon - IsExternal: no
Type - AR_Sein - 001_Nimetus: ol. olev - 420mm; 505_Paksus: 420 mm
BaseQuantities - Height: 1370 mm; Length: 9686.57 mm; Width: 420 mm; GrossFootprintArea: 0.235884 m2; GrossVolume: 0.323161 m3; GrossSideArea: 0.76943 m2; NetSideArea: 0.76943 m2; NetVolume: 0.323161 m3
Pset_QuantityTakeOff - Reference: ol. olev - 420mm; sets with these values: 2
Pset_WallCommon - ExtendToStructure: no; LoadBearing: yes; Reference: ol. olev - 420mm
AR_Sein - 500_Kandev: yes; 003_Elemendi_staadium: Olemasolev; 605_Neto_pindala: 10.2963 m2

# IfcWallStandardCase: Basic Wall:ol. olev - 460mm, Basic Wall:ol. olev - 460mm:2077215
In: 3. korrus
Type - PredefinedType: STANDARD; Material: ol. olev materjal 460 mm
Type - Pset_WallCommon - IsExternal: no
Type - AR_Sein - 001_Nimetus: ol. olev - 460mm; 505_Paksus: 460 mm
BaseQuantities - Height: 3266.52 mm; Length: 8005 mm; Width: 460 mm; GrossFootprintArea: 3.6823 m2; GrossVolume: 6.64154 m3; GrossSideArea: 14.4381 m2; NetSideArea: 14.4381 m2; NetVolume: 6.64154 m3
Pset_QuantityTakeOff - Reference: ol. olev - 460mm; sets with these values: 2
Pset_WallCommon - ExtendToStructure: no; LoadBearing: yes; Reference: ol. olev - 460mm
AR_Sein - 500_Kandev: yes; 003_Elemendi_staadium: Olemasolev; 605_Neto_pindala: 14.4381 m2

# IfcWallStandardCase: Basic Wall:ol. olev - 480mm, Basic Wall:ol. olev - 480mm:834320
In: 1. korrus
Type - PredefinedType: STANDARD; Material: ol. olev materjal 480 mm
Type - Pset_WallCommon - IsExternal: no
Type - AR_Sein - 001_Nimetus: ol. olev - 480mm; 505_Paksus: 480 mm
BaseQuantities - Height: 2980 mm; Length: 1141.45 mm; Width: 480 mm; GrossFootprintArea: 0.461085 m2; GrossVolume: 0.686592 m3; GrossSideArea: 1.4304 m2; NetSideArea: 1.4304 m2; NetVolume: 0.603097 m3
Pset_QuantityTakeOff - Reference: ol. olev - 480mm; sets with these values: 2
Pset_WallCommon - ExtendToStructure: no; LoadBearing: yes; Reference: ol. olev - 480mm
AR_Sein - 500_Kandev: yes; 003_Elemendi_staadium: Olemasolev; 605_Neto_pindala: 3.40151 m2

# IfcWallStandardCase: Basic Wall:ol. olev - 500mm, Basic Wall:ol. olev - 500mm:1035361
In: -2. korrus
Type - PredefinedType: STANDARD; Material: ol. olev materjal 500 mm
Type - Pset_WallCommon - IsExternal: no
Type - AR_Sein - 001_Nimetus: ol. olev - 500mm; 505_Paksus: 500 mm
BaseQuantities - Height: 3340 mm; Length: 6000 mm; Width: 500 mm; GrossFootprintArea: 3 m2; GrossVolume: 9.56625 m3; GrossSideArea: 19.1325 m2; NetSideArea: 19.1325 m2; NetVolume: 9.56625 m3
Pset_QuantityTakeOff - Reference: ol. olev - 500mm; sets with these values: 2
Pset_WallCommon - ExtendToStructure: no; LoadBearing: no; Reference: ol. olev - 500mm
AR_Sein - 500_Kandev: no; 003_Elemendi_staadium: Olemasolev; 605_Neto_pindala: 19.1325 m2

# IfcWallStandardCase: Basic Wall:ol. olev - 530mm (9)
Type - PredefinedType: STANDARD; Material: ol. olev materjal 530 mm
Type - Pset_WallCommon - IsExternal: no
Type - AR_Sein - 001_Nimetus: ol. olev - 530mm; 505_Paksus: 530 mm
BaseQuantities - Width: 530 mm
Pset_QuantityTakeOff - Reference: ol. olev - 530mm; sets with these values: 2
Pset_WallCommon - ExtendToStructure: no; LoadBearing: no; Reference: ol. olev - 530mm
AR_Sein - 003_Elemendi_staadium: Olemasolev
Name (Basic Wall:ol. olev - 530mm:...) | In | Height (mm) | Length (mm) | GrossFootprintArea (m2) | GrossVolume (m3) | GrossSideArea (m2) = NetSideArea (m2) | NetVolume (m3) | 500_Kandev | 605_Neto_pindala (m2)
1955640 | -1. korrus | 2985 | 5990.17 | 3.17479 | 7.23421 | 13.6495 | 7.23421 | no | 17.8507
6565372 | 3. korrus | 4017.59 | 7934.65 | 4.20536 | 3.78824 | 7.14763 | 3.78824 | no | 7.14763
6565966 | 4. korrus | 697.59 | 3000 | 1.59 | 1.10917 | 2.09277 | 1.10917 | no | 2.09277
6576004 | 4. korrus | 3935.62 | 8479.65 | 4.49421 | 3.95087 | 7.45446 | 3.95087 | no | 7.45446
6576036 | 5. korrus | 665.618 | 2670 | 1.4151 | 0.186972 | 0.352778 | 0.109425 | no | 1.7772
6579720 | 4. korrus | 3938.22 | 8101.93 | 4.29402 | 3.62411 | 6.83794 | 3.62411 | no | 6.83794
6580351 | 5. korrus | 1178.22 | 3108.88 | 1.64771 | 0.4185 | 0.789623 | 0.4185 | no | 3.66295
10886648 | 4. korrus | 943.659 | 2960 | 1.5688 | 1.48041 | 2.79323 | 1.48041 |  | 2.79323
10886903 | 4. korrus | 3950.18 | 8065 | 4.27445 | 4.00434 | 7.55537 | 4.00434 |  | 7.55537

# IfcWallStandardCase: Basic Wall:ol. olev - 560mm, Basic Wall:ol. olev - 560mm:13626060
In: 1. korrus
Type - PredefinedType: STANDARD; Material: ol. olev materjal 560 mm
Type - Pset_WallCommon - IsExternal: no
Type - AR_Sein - 001_Nimetus: ol. olev - 560mm; 505_Paksus: 560 mm
BaseQuantities - Height: 230 mm; Length: 5175 mm; Width: 560 mm; GrossFootprintArea: 2.898 m2; GrossVolume: 0.66654 m3; GrossSideArea: 1.19025 m2; NetSideArea: 1.19025 m2; NetVolume: 0.66654 m3
Pset_QuantityTakeOff - Reference: ol. olev - 560mm; sets with these values: 2
Pset_WallCommon - ExtendToStructure: no; LoadBearing: no; Reference: ol. olev - 560mm
AR_Sein - 003_Elemendi_staadium: Olemasolev; 605_Neto_pindala: 1.19025 m2

# IfcWallStandardCase: Basic Wall:ol. olev - 580mm (2)
In: 1. korrus
Type - PredefinedType: STANDARD; Material: ol. olev materjal 580 mm
Type - Pset_WallCommon - IsExternal: no
Type - AR_Sein - 001_Nimetus: ol. olev - 580mm; 505_Paksus: 580 mm
BaseQuantities - Width: 580 mm
Pset_QuantityTakeOff - Reference: ol. olev - 580mm; sets with these values: 2
Pset_WallCommon - ExtendToStructure: no; LoadBearing: no; Reference: ol. olev - 580mm
Name (Basic Wall:ol. olev - 580mm:...) | Height (mm) | Length (mm) | GrossFootprintArea (m2) | GrossVolume (m3) | GrossSideArea (m2) = NetSideArea (m2) | NetVolume (m3) | 605_Neto_pindala (m2)
2355101 | 2980 | 5990 | 3.4742 | 8.49478 | 14.6462 | 8.2378 | 13.7899 | AR_Sein - 500_Kandev: no; 003_Elemendi_staadium: Olemasolev
11994862 | 980 | 860 | 0.4988 | 0.488824 | 0.8428 | 0.2107 | 0.8428

# IfcWallStandardCase: Basic Wall:ol. olev - 590mm (6)
Type - PredefinedType: STANDARD; Material: ol. olev materjal 590 mm
Type - Pset_WallCommon - IsExternal: no
Type - AR_Sein - 001_Nimetus: ol. olev - 590mm; 505_Paksus: 590 mm
BaseQuantities - Width: 590 mm
Pset_QuantityTakeOff - Reference: ol. olev - 590mm; sets with these values: 2
Pset_WallCommon - ExtendToStructure: no; Reference: ol. olev - 590mm
AR_Sein - 003_Elemendi_staadium: Olemasolev
Name (Basic Wall:ol. olev - 590mm:...) | In | Height (mm) | Length (mm) | GrossFootprintArea (m2) | GrossVolume (m3) | GrossSideArea (m2) | NetSideArea (m2) | NetVolume (m3) | LoadBearing = 500_Kandev | 605_Neto_pindala (m2)
788125 | 1. korrus | 3300 | 6000 | 3.54 | 8.54768 | 14.4876 | 14.4876 | 8.54768 | no | 19.8
861627 | 2. korrus | 3000 | 5970 | 3.5223 | 7.82372 | 13.2605 | 13.2605 | 7.82372 | yes | 17.91
1010136 | -1. korrus | 3300 | 53810 | 31.7479 | 104.752 | 177.547 | 168.772 | 96.3791 | no | 168.772
1477366 | 3. korrus | 3266.52 | 2960 | 1.7464 | 5.70465 | 9.6689 | 9.6689 | 5.70465 | yes | 9.6689
3373597 | 3. korrus | 3300 | 4385 | 2.58715 | 1.30484 | 2.2116 | 2.2116 | 1.30484 | yes | 14.4705
3373945 | 3. korrus | 3300 | 4500 | 2.655 | 1.30484 | 2.2116 | 2.2116 | 1.30484 | yes | 14.85

# IfcWallStandardCase: Basic Wall:ol. olev - 600mm (14)
Type - PredefinedType: STANDARD; Material: ol. olev materjal 600 mm
Type - Pset_WallCommon - IsExternal: no
Type - AR_Sein - 001_Nimetus: ol. olev - 600mm; 505_Paksus: 600 mm
BaseQuantities - Width: 600 mm
Pset_QuantityTakeOff - Reference: ol. olev - 600mm; sets with these values: 2
Pset_WallCommon - ExtendToStructure: no; Reference: ol. olev - 600mm
AR_Sein - 003_Elemendi_staadium: Olemasolev
Name (Basic Wall:ol. olev - 600mm:...) | In | Height (mm) | Length (mm) | GrossFootprintArea (m2) | GrossVolume (m3) | GrossSideArea (m2) = NetSideArea (m2) | NetVolume (m3) | LoadBearing | 500_Kandev | 605_Neto_pindala (m2)
824342 | 1. korrus | 1930 | 6600 | 3.96 | 5.98707 | 9.97845 | 5.98707 | yes | yes | 12.738
836024 | 2. korrus | 3300 | 6570 | 3.942 | 11.4052 | 19.0086 | 11.3953 | yes | yes | 21.681
933782 | E-korpus 3. korrus | 1189.48 | 2088.47 | 1.11849 | 0.857588 | 1.42931 | 0.857588 | no | no | 2.48419
1034292 | -2. korrus | 3025 | 5210.17 | 3.1261 | 7.96849 | 13.2808 | 7.96849 | no | no | 15.7608
1034626 | -2. korrus | 3245 | 9090.17 | 5.4541 | 10.0667 | 16.7778 | 10.0667 | yes | yes | 29.4976
2336539 | E-korpus 2. korrus | 3000 | 2088.47 | 1.11849 | 2.16407 | 3.60679 | 2.14946 | yes | yes | 6.16481
2386300 | E-korpus 2. korrus | 1370 | 6570 | 3.942 | 4.73487 | 7.89145 | 4.73076 | no |  | 9.0009
4023938 | 3. korrus | 645 | 6630 | 3.978 | 2.24467 | 3.74112 | 2.24467 | yes | yes | 4.27635
5221726 | -2. korrus | 4540 | 1106 | 0.6636 | 2.79674 | 4.66124 | 2.79674 | yes | yes | 4.66124
5221727 | -2. korrus | 4640 | 55804.8 | 33.4829 | 154.373 | 257.288 | 154.373 | yes | yes | 258.934
5221729 | -2. korrus | 3340 | 6700 | 4.02 | 13.4268 | 22.378 | 13.4268 | yes | yes | 22.378
5232357 | -2. korrus | 4640 | 6560 | 3.936 | 18.263 | 30.4384 | 7.46248 | yes | yes | 30.4384
5235456 | -2. korrus | 4640 | 20778.3 | 12.467 | 57.8467 | 96.4111 | 57.8467 | yes | yes | 96.4111
17121350 | -2. korrus | 4640 | 32257.2 | 19.3543 | 88.0168 | 146.695 | 88.0168 | no |  | 149.673

# IfcWallStandardCase: Basic Wall:ol. olev - 640mm (4)
Type - PredefinedType: STANDARD; Material: ol. olev materjal 640 mm
Type - Pset_WallCommon - IsExternal: no
Type - AR_Sein - 001_Nimetus: ol. olev - 640mm; 505_Paksus: 640 mm
BaseQuantities - Width: 640 mm
Pset_QuantityTakeOff - Reference: ol. olev - 640mm; sets with these values: 2
Pset_WallCommon - ExtendToStructure: no; LoadBearing: no; Reference: ol. olev - 640mm
AR_Sein - 003_Elemendi_staadium: Olemasolev
Name (Basic Wall:ol. olev - 640mm:...) | In | Height (mm) | Length (mm) | GrossFootprintArea (m2) | GrossVolume (m3) | GrossSideArea (m2) = NetSideArea (m2) | NetVolume (m3) | 605_Neto_pindala (m2)
1213129 | 3. korrus | 534.251 | 18212.7 | 1.34866 | 0.720522 | 1.12582 | 0.720522 | 17.6386 | AR_Sein - 500_Kandev: no
2254197 | 2. korrus | 3300 | 13200 | 8.448 | 23.0849 | 36.0702 | 23.0849 | 36.0702 | AR_Sein - 500_Kandev: no
17120147 | 2. korrus | 3300 | 16441.7 | 0.215219 | 1.35168 | 2.112 | 0.710223 | 51.7293
17121057 | E-korpus 2. korrus | 1430 | 13500 | 8.64 | 11.303 | 17.661 | 11.2809 | 17.661

# IfcWallStandardCase: Basic Wall:ol. olev - 670mm (3)
Type - PredefinedType: STANDARD; Material: ol. olev materjal 670 mm
Type - Pset_WallCommon - IsExternal: no
Type - AR_Sein - 001_Nimetus: ol. olev - 670mm; 505_Paksus: 670 mm
BaseQuantities - Width: 670 mm
Pset_QuantityTakeOff - Reference: ol. olev - 670mm; sets with these values: 2
Pset_WallCommon - ExtendToStructure: no; LoadBearing: yes; Reference: ol. olev - 670mm
AR_Sein - 500_Kandev: yes; 003_Elemendi_staadium: Olemasolev
Name (Basic Wall:ol. olev - 670mm:...) | In | Height (mm) | Length (mm) | GrossFootprintArea (m2) | GrossVolume (m3) | GrossSideArea (m2) = NetSideArea (m2) | NetVolume (m3) | 605_Neto_pindala (m2)
1034850 | -2. korrus | 3340 | 5210.17 | 3.49082 | 9.82474 | 14.6638 | 8.97078 | 17.0565
4555551 | -1. korrus | 3300 | 5860 | 3.9262 | 6.97839 | 10.4155 | 6.96849 | 10.4155
6993617 | -1. korrus | 1345 | 1300 | 0.871 | 1.17149 | 1.7485 | 1.17149 | 1.7485

# IfcWallStandardCase: Basic Wall:ol. olev - 700mm (2)
Type - PredefinedType: STANDARD; Material: ol. olev materjal 700 mm
Type - Pset_WallCommon - IsExternal: no
Type - AR_Sein - 001_Nimetus: ol. olev - 700mm; 505_Paksus: 700 mm
BaseQuantities - Width: 700 mm
Pset_QuantityTakeOff - Reference: ol. olev - 700mm; sets with these values: 2
Pset_WallCommon - Reference: ol. olev - 700mm; ExtendToStructure: no; LoadBearing: yes
AR_Sein - 500_Kandev: yes; 003_Elemendi_staadium: Olemasolev
Name (Basic Wall:ol. olev - 700mm:...) | In | Height (mm) | Length (mm) | GrossFootprintArea (m2) | GrossVolume (m3) = NetVolume (m3) | GrossSideArea (m2) = NetSideArea (m2) | 605_Neto_pindala (m2)
829424 | 1. korrus | 3300 | 5200 | 3.64 | 10.1413 | 14.4876 | 17.16
835870 | 2. korrus | 3000 | 5980 | 4.186 | 9.21938 | 13.1705 | 17.94

# IfcWallStandardCase: Basic Wall:ol. olev - 720mm (4)
Type - PredefinedType: STANDARD; Material: ol. olev materjal 720 mm
Type - Pset_WallCommon - IsExternal: no
Type - AR_Sein - 001_Nimetus: ol. olev - 720mm; 505_Paksus: 720 mm
BaseQuantities - Width: 720 mm
Pset_QuantityTakeOff - Reference: ol. olev - 720mm; sets with these values: 2
Pset_WallCommon - ExtendToStructure: no; Reference: ol. olev - 720mm
Name (Basic Wall:ol. olev - 720mm:...) | In | Height (mm) | Length (mm) | GrossFootprintArea (m2) | GrossVolume (m3) | GrossSideArea (m2) | NetSideArea (m2) | NetVolume (m3) | LoadBearing | 500_Kandev | 003_Elemendi_staadium | 605_Neto_pindala (m2)
827943 | 1. korrus | 3300 | 6135 | 4.3128 | 14.2917 | 19.8497 | 19.8497 | 14.2917 | no | no | Olemasolev | 19.8497
835869 | 2. korrus | 3000 | 6398.55 | 4.60696 | 13.7907 | 19.1538 | 19.1538 | 13.7907 | yes | yes | Olemasolev | 19.1538
4556660 | 1. korrus | 3660 | 5810 | 4.1832 | 7.00488 | 9.72901 | 9.72875 | 6.29006 | no | no | Olemasolev | 9.88341
15886762 | 2. korrus | 50 | 42.25 | 0.03042 | 0.0223375 | 0.0310244 | 0.0310244 | 0.00131078 | no |  |  | 0.0021125

# IfcWallStandardCase: Basic Wall:ol. olev - 740mm (5)
Type - PredefinedType: STANDARD; Material: ol. olev materjal 740 mm
Type - Pset_WallCommon - IsExternal: no
Type - AR_Sein - 001_Nimetus: ol. olev - 740mm; 505_Paksus: 740 mm
BaseQuantities - Width: 740 mm
Pset_QuantityTakeOff - Reference: ol. olev - 740mm; sets with these values: 2
Pset_WallCommon - ExtendToStructure: no; Reference: ol. olev - 740mm
Name (Basic Wall:ol. olev - 740mm:...) | In | Height (mm) | Length (mm) | GrossFootprintArea (m2) | GrossVolume (m3) | GrossSideArea (m2) | NetSideArea (m2) | NetVolume (m3) | LoadBearing | 605_Neto_pindala (m2)
835864 | 2. korrus | 3000 | 17316.4 | 12.8142 | 21.9362 | 29.6435 | 29.6436 | 20.5417 | yes | 29.6426 | AR_Sein - 500_Kandev: yes; 003_Elemendi_staadium: Olemasolev
1233233 | 1. korrus | 3100 | 2193.16 | 1.4182 | 2.75653 | 3.72505 | 3.72505 | 2.75653 | yes | 6.79878 | AR_Sein - 500_Kandev: yes; 003_Elemendi_staadium: Olemasolev
10644699 | 2. korrus | 50 | 5157.75 | 3.81673 | 0.190837 | 0.257887 | 0.257887 | 0.160016 | no | 0.257887
10644700 | 2. korrus | 50 | 5200 | 3.848 | 0.1924 | 0.26 | 0.26 | 0.161327 | no | 0.26
10644701 | 2. korrus | 50 | 5200 | 3.848 | 0.1924 | 0.26 | 0.26 | 0.161327 | no | 0.26

# IfcWallStandardCase: Basic Wall:ol. olev - 780mm (18)
Type - PredefinedType: STANDARD; Material: ol. olev materjal 780 mm
Type - Pset_WallCommon - IsExternal: no
Type - AR_Sein - 000_Muinsuskaitse: no; 001_Nimetus: ol. olev - 780mm; 205_Tüüp: Ol.ol; 505_Paksus: 780 mm
BaseQuantities - Width: 780 mm
Pset_QuantityTakeOff - Reference: ol. olev - 780mm; sets with these values: 2
Pset_WallCommon - ExtendToStructure: no; Reference: ol. olev - 780mm
Name (Basic Wall:ol. olev - 780mm:...) | In | Height (mm) | Length (mm) | GrossFootprintArea (m2) | GrossVolume (m3) | GrossSideArea (m2) | NetSideArea (m2) | NetVolume (m3) | LoadBearing | 500_Kandev | 003_Elemendi_staadium | 605_Neto_pindala (m2)
783042 | 1. korrus | 2980 | 11567.4 | 9.02257 | 21.6886 | 27.8058 | 27.8058 | 21.3395 | no | no | Olemasolev | 27.8058
788035 | 1. korrus | 3300 | 18315 | 14.2857 | 47.1428 | 60.4395 | 32.5287 | 24.5528 | no | no | Olemasolev | 31.6287
824131 | 1. korrus | 3870 | 54570.4 | 42.5649 | 75.7533 | 97.1196 | 97.1188 | 75.7538 | no | no | Olemasolev | 97.1188
829503 | 1. korrus | 3300 | 18475 | 14.4105 | 47.4902 | 60.8849 | 32.974 | 24.8284 | yes | yes | Olemasolev | 32.074
830562 | 1. korrus | 1321.6 | 5190.44 | 4.04854 | 0.803088 | 1.0296 | 5.26704 | 3.41907 | yes | yes | Olemasolev | 4.38349
835863 | 2. korrus | 3000 | 5810 | 4.5318 | 1.8252 | 2.34 | 6.60389 | 4.91134 | no | no | Olemasolev | 6.29667
835868 | 2. korrus | 3000 | 5910.38 | 4.61009 | 1.8252 | 2.34 | 6.60389 | 5.14622 | no | no | Olemasolev | 6.5978
835871 | 2. korrus | 3000 | 17775 | 13.8645 | 24.1621 | 30.9771 | 30.9768 | 22.7582 | yes | yes | Olemasolev | 30.9764
1010563 | -1. korrus | 3300 | 5990 | 4.6722 | 11.7894 | 15.1146 | 15.1146 | 11.7894 | yes | yes | Olemasolev | 18.81
2353352 | 1. korrus | 3580 | 6400 | 4.992 | 8.30341 | 10.6454 | 10.6456 | 8.30344 | no | no | Olemasolev | 10.6456
10471659 | 1. korrus | 2980 | 18393.3 | 14.3467 | 16.1515 | 20.707 | 20.7072 | 16.1515 | no |  | Olemasolev | 20.7072
10471665 | 1. korrus | 1321.6 | 5220 | 4.0716 | 0.803088 | 1.0296 | 5.29349 | 3.44931 | no |  | Olemasolev | 4.42227
10471666 | 1. korrus | 2980 | 804.274 | 0.627334 | 1.86945 | 2.39674 | 2.39674 | 1.86945 | no |  | Olemasolev | 2.39674
10674844 | 2. korrus | 50 | 5200 | 4.056 | 0.2028 | 0.26 | 0.26 | 0.1716 | no |  |  | 0.26
10674845 | 2. korrus | 50 | 5200 | 4.056 | 0.2028 | 0.26 | 0.26 | 0.1716 | no |  |  | 0.26
10674846 | 2. korrus | 50 | 5200 | 4.056 | 0.2028 | 0.26 | 0.26 | 0.1716 | no |  |  | 0.26
11608330 | 1. korrus | 3300 | 5820 | 4.5396 | 12.9219 | 16.5666 | 16.5666 | 12.9219 | no |  | Olemasolev | 19.206
11608350 | 2. korrus | 3950 | 6240 | 4.8672 | 15.4672 | 19.8297 | 19.8297 | 15.4672 | yes | yes | Olemasolev | 23.8245

# IfcWallStandardCase: Basic Wall:ol. olev - 780mm, MK, Basic Wall:ol. olev - 780mm, MK:6365457
In: E-korpus 2. korrus
Type - PredefinedType: STANDARD; Material: ol. olev materjal 780 mm
Type - Pset_WallCommon - IsExternal: no
Type - AR_Sein - 000_Muinsuskaitse: yes; 001_Nimetus: ol. olev - 780mm, MK; 505_Paksus: 780 mm
BaseQuantities - Height: 3220.85 mm; Length: 41190.8 mm; Width: 780 mm; GrossFootprintArea: 32.1288 m2; GrossVolume: 85.4654 m3; GrossSideArea: 109.571 m2; NetSideArea: 51.8167 m2; NetVolume: 40.4165 m3
Pset_QuantityTakeOff - Reference: ol. olev - 780mm, MK; sets with these values: 2
Pset_WallCommon - ExtendToStructure: no; LoadBearing: no; Reference: ol. olev - 780mm, MK
AR_Sein - 500_Kandev: no; 003_Elemendi_staadium: Olemasolev; 605_Neto_pindala: 51.8167 m2

# IfcWindow: Klaasseina akna tüüp 1:Aken, klaas, vasak (24)
Type - ParameterTakesPrecedence: no; Sizeable: no; Material: EST. Klaas. 3x. Default, LUMION_dark steel window frames
Type - Pset_DoorWindowGlazingType - SolarHeatGainTransmittance: 0.4
Type - Pset_ManufacturerTypeInformation - Manufacturer: Aluprof
Type - Pset_WindowCommon - IsExternal: yes; ThermalTransmittance: 0.8 kg/K/s3; FireRating: -; AcousticRating: 35dB
Type - AR_Aken - 335_Väalispiire: yes; 001_Nimetus: Aken, klaas, vasak; 300_Tüüp: -; 310_Materjal: Alumiinium; 315_Avanemine: Saksa tüüpi; 320_Klaas: Toonitud peegelklaas, pronks; 325_Helipidavus: 35dB; 330_Tulekindlus: -; 340_Soojusläbivus: 0.8; 345_Paiksekiirgus_tegur: 0.4; 350_Klaaspakett: 3-kordne klaaspakett, toonitud peegelklaas, pronks; 375_Viimistlus_seest: RAL9005 (must); 376_Viimistlus_väljast: RAL9005 (must); 900_Tootja: Aluprof; 905_Mudel: MB-104 Passive SI
Pset_QuantityTakeOff - Reference: Aken, klaas, vasak
Pset_WindowCommon - Reference: Aken, klaas, vasak
AR_Aken - 003_Elemendi_staadium: Projekteeritud
Name (Klaasseina akna tüüp 1:Aken, klaas, vasak:...) | In | OverallHeight (mm) = 305_Ava_mõõt_kõrgus (mm) = Height (mm) | OverallWidth (mm) = 305_Ava_mõõt_laius (mm) = Width (mm) | 355_Pindala (m2) = Area (m2)
10515249 | 1. korrus | 1150 | 420 | 0.483
10515245 | 1. korrus | 1150 | 385 | 0.44275
10522674 | 1. korrus | 1150 | 420 | 0.483
10522670 | 1. korrus | 1150 | 385 | 0.44275
10522831 | 1. korrus | 1150 | 420 | 0.483
10522827 | 1. korrus | 1150 | 385 | 0.44275
10522981 | 1. korrus | 1150 | 420 | 0.483
10522977 | 1. korrus | 1150 | 385 | 0.44275
10523147 | 1. korrus | 1150 | 420 | 0.483
10523143 | 1. korrus | 1150 | 385 | 0.44275
10523297 | 1. korrus | 1150 | 420 | 0.483
10523293 | 1. korrus | 1150 | 385 | 0.44275
10644019 | 2. korrus | 700 | 420 | 0.294
10644025 | 2. korrus | 700 | 420 | 0.294
10644113 | 2. korrus | 700 | 420 | 0.294
10644119 | 2. korrus | 700 | 420 | 0.294
10644207 | 2. korrus | 700 | 420 | 0.294
10644213 | 2. korrus | 700 | 420 | 0.294
10644301 | 2. korrus | 700 | 420 | 0.294
10644307 | 2. korrus | 700 | 420 | 0.294
10644395 | 2. korrus | 700 | 420 | 0.294
10644401 | 2. korrus | 700 | 420 | 0.294
10644489 | 2. korrus | 700 | 420 | 0.294
10644495 | 2. korrus | 700 | 420 | 0.294

# IfcWindow: Klaasseina akna tüüp 2:Aken, 2-poolne, avanemine alla 1 (16)
In: 3. korrus
Type - ParameterTakesPrecedence: no; Sizeable: no; Material: EST. Klaas. 3x. Default, LUMION_dark steel window frames
Type - Pset_DoorWindowGlazingType - SolarHeatGainTransmittance: 0.4
Type - Pset_ManufacturerTypeInformation - Manufacturer: Aluprof
Type - Pset_WindowCommon - IsExternal: yes; ThermalTransmittance: 0.8 kg/K/s3; FireRating: -; AcousticRating: 35dB
Type - AR_Aken - 335_Väalispiire: yes; 001_Nimetus: Aken, 2-poolne, avanemine alla 1; 300_Tüüp: -; 310_Materjal: Alumiinium; 315_Avanemine: Saksa tüüpi; 320_Klaas: Toonitud peegelklaas, pronks; 325_Helipidavus: 35dB; 330_Tulekindlus: -; 340_Soojusläbivus: 0.8; 345_Paiksekiirgus_tegur: 0.4; 350_Klaaspakett: 3x klaaspakett, toonitud peegelklaas, pronks; 375_Viimistlus_seest: RAL9005 (must); 376_Viimistlus_väljast: RAL9005 (must); 900_Tootja: Aluprof; 905_Mudel: MB-104 Passive SI
OverallHeight: 1134.84 mm; OverallWidth: 1165 mm
Pset_QuantityTakeOff - Reference: Aken, 2-poolne, avanemine alla 1
Pset_WindowCommon - Reference: Aken, 2-poolne, avanemine alla 1
AR_Aken - 003_Elemendi_staadium: Projekteeritud; 305_Ava_mõõt_laius: 1165 mm; 305_Ava_mõõt_kõrgus: 350 mm; 355_Pindala: 0.40775 m2
BaseQuantities - Height: 350 mm; Width: 1165 mm; Area: 0.40775 m2
Name (Klaasseina akna tüüp 2:Aken, 2-poolne, avanemine alla 1:...)
10386006
10386009
10389349
10389352
10389368
10389371
10389387
10389390
10389440
10389443
10389459
10389462
10389478
10389481
10389497
10389500

# IfcWindow: Klaasseina akna tüüp 6:Aken, klaas, parem (24)
Type - ParameterTakesPrecedence: no; Sizeable: no; Material: EST. Klaas. 3x. Default, LUMION_dark steel window frames
Type - Pset_DoorWindowGlazingType - SolarHeatGainTransmittance: 0.4
Type - Pset_ManufacturerTypeInformation - Manufacturer: Aluprof
Type - Pset_WindowCommon - IsExternal: yes; ThermalTransmittance: 0.8 kg/K/s3; FireRating: -; AcousticRating: 35dB
Type - AR_Aken - 335_Väalispiire: yes; 001_Nimetus: Aken, klaas, parem; 300_Tüüp: -; 310_Materjal: Alumiinium; 315_Avanemine: Saksa tüüpi; 320_Klaas: Toonitud peegelklaas, pronks; 325_Helipidavus: 35dB; 330_Tulekindlus: -; 340_Soojusläbivus: 0.8; 345_Paiksekiirgus_tegur: 0.4; 350_Klaaspakett: 3-kordne klaaspakett, toonitud peegelklaas, pronks; 375_Viimistlus_seest: RAL9005 (must); 376_Viimistlus_väljast: RAL9005 (must); 900_Tootja: Aluprof; 905_Mudel: MB-104 Passive SI
Pset_QuantityTakeOff - Reference: Aken, klaas, parem
Pset_WindowCommon - Reference: Aken, klaas, parem
AR_Aken - 003_Elemendi_staadium: Projekteeritud
Name (Klaasseina akna tüüp 6:Aken, klaas, parem:...) | In | OverallHeight (mm) = 305_Ava_mõõt_kõrgus (mm) = Height (mm) | OverallWidth (mm) = 305_Ava_mõõt_laius (mm) = Width (mm) | 355_Pindala (m2) = Area (m2)
10515241 | 1. korrus | 1150 | 385 | 0.44275
10515237 | 1. korrus | 1150 | 420 | 0.483
10522666 | 1. korrus | 1150 | 385 | 0.44275
10522662 | 1. korrus | 1150 | 420 | 0.483
10522823 | 1. korrus | 1150 | 385 | 0.44275
10522819 | 1. korrus | 1150 | 420 | 0.483
10522973 | 1. korrus | 1150 | 385 | 0.44275
10522969 | 1. korrus | 1150 | 420 | 0.483
10523139 | 1. korrus | 1150 | 385 | 0.44275
10523135 | 1. korrus | 1150 | 420 | 0.483
10523289 | 1. korrus | 1150 | 385 | 0.44275
10523285 | 1. korrus | 1150 | 420 | 0.483
10644016 | 2. korrus | 700 | 420 | 0.294
10644010 | 2. korrus | 700 | 420 | 0.294
10644110 | 2. korrus | 700 | 420 | 0.294
10644104 | 2. korrus | 700 | 420 | 0.294
10644204 | 2. korrus | 700 | 420 | 0.294
10644198 | 2. korrus | 700 | 420 | 0.294
10644298 | 2. korrus | 700 | 420 | 0.294
10644292 | 2. korrus | 700 | 420 | 0.294
10644392 | 2. korrus | 700 | 420 | 0.294
10644386 | 2. korrus | 700 | 420 | 0.294
10644486 | 2. korrus | 700 | 420 | 0.294
10644480 | 2. korrus | 700 | 420 | 0.294

# IfcWindow: Klaasseina akna tüüp 9:Aken, üles avanev (22)
In: 1. korrus
Type - ParameterTakesPrecedence: no; Sizeable: no; Material: EST. Klaas. 3x. Default, LUMION_dark steel window frames
Type - Pset_DoorWindowGlazingType - SolarHeatGainTransmittance: 0.4
Type - Pset_ManufacturerTypeInformation - Manufacturer: Aluprof
Type - Pset_WindowCommon - IsExternal: yes; ThermalTransmittance: 0.8 kg/K/s3; FireRating: -; AcousticRating: 35dB
Type - AR_Aken - 335_Väalispiire: yes; 001_Nimetus: Aken, üles avanev; 300_Tüüp: -; 315_Avanemine: Saksa tüüpi; 320_Klaas: Toonitud peegelklaas, pronks; 325_Helipidavus: 35dB; 330_Tulekindlus: -; 340_Soojusläbivus: 0.8; 345_Paiksekiirgus_tegur: 0.4; 350_Klaaspakett: 3-kordne klaaspakett, toonitud peegelklaas, pronks; 375_Viimistlus_seest: RAL9005 (must); 376_Viimistlus_väljast: RAL9005 (must); 900_Tootja: Aluprof; 905_Mudel: MB-104 Passive SI
OverallHeight: 450 mm; OverallWidth: 940 mm
Pset_QuantityTakeOff - Reference: Aken, üles avanev
Pset_WindowCommon - Reference: Aken, üles avanev
AR_Aken - 003_Elemendi_staadium: Projekteeritud; 305_Ava_mõõt_laius: 940 mm; 305_Ava_mõõt_kõrgus: 450 mm; 355_Pindala: 0.423 m2
BaseQuantities - Height: 450 mm; Width: 940 mm; Area: 0.423 m2
Name (Klaasseina akna tüüp 9:Aken, üles avanev:...)
10532933
10532959
10533041
10533067
10533149
10533175
10533257
10533283
10533365
10533391
10533473
10533499
10533581
10533607
10533689
10533715
10533797
10533823
10533905
10533931
10534013
10534039

# IfcWindow: SMA_W1, 1-jaotus:A-07_500x500 (12)
In: -1. korrus
Type - ParameterTakesPrecedence: no; Sizeable: no; Material: LUMION_dark steel window frames, EST. Klaas. 3x. Default
Type - Pset_DoorWindowGlazingType - SolarHeatGainTransmittance: 0.4
Type - Pset_ManufacturerTypeInformation - Manufacturer: Aluprof
Type - Pset_WindowCommon - IsExternal: yes; FireRating: -; AcousticRating: 35dB; ThermalTransmittance: 0.81 kg/K/s3
Type - AR_Aken - 335_Väalispiire: yes; 001_Nimetus: A-07_500x500; 300_Tüüp: A-07; 305_Ava_mõõt_laius: 500 mm; 305_Ava_mõõt_kõrgus: 500 mm; 310_Materjal: Alumiinium; 315_Avanemine: Mitte-avanevad; 320_Klaas: Toonitud peegelklaas, pronks; 325_Helipidavus: 35dB; 330_Tulekindlus: -; 340_Soojusläbivus: 0.81; 345_Paiksekiirgus_tegur: 0.4; 350_Klaaspakett: Min. 3x klaaspakett, toonitud peegelklaas, pronks; 375_Viimistlus_seest: RAl9005 (must); 376_Viimistlus_väljast: RAL9005 (must); 900_Tootja: Aluprof; 905_Mudel: MB-104 Passive SI
OverallHeight: 500 mm; OverallWidth: 500 mm
Pset_QuantityTakeOff - Reference: A-07_500x500
Pset_WindowCommon - Reference: A-07_500x500
AR_Aken - 003_Elemendi_staadium: Projekteeritud; 355_Pindala: 0.80233 m2
BaseQuantities - Height: 500 mm; Width: 500 mm; Area: 0.80233 m2
Name (SMA_W1, 1-jaotus:A-07_500x500:...)
9564196
9564197
9564198
9564199
9564200
9564201
9564202
9564203
9564204
9564205
9564206
9564220

# IfcZone (20)
Name
TT 57 | Description: EI60
TT 21 | Description: EI60
TT 27 | Description: EI90
SE AB 3.1M2
SE AB -1.1M4 kõrvaltsoon
TT 48 | Description: EI60
SE AB -1.1M4
TT 23 | Description: EI60
TT 05 | Description: EI60
SE F 1.1M2
SE AB 3.1M2 kõrvaltsoon
TT 01 | Description: EI60
SE AB 1.1M4
SE TR3 L3
TT 26 | Description: EI60
TT 29 | Description: EI90
SE AB 4.1M4
SE TR8 L3
SE AB -2.1M2 AT
TT 41 | Description: EI60
